VERSION 5.8 ;
BUSBITCHARS "[]" ;
DIVIDERCHAR "/" ;
UNITS
    DATABASE MICRONS 1000 ;
END UNITS

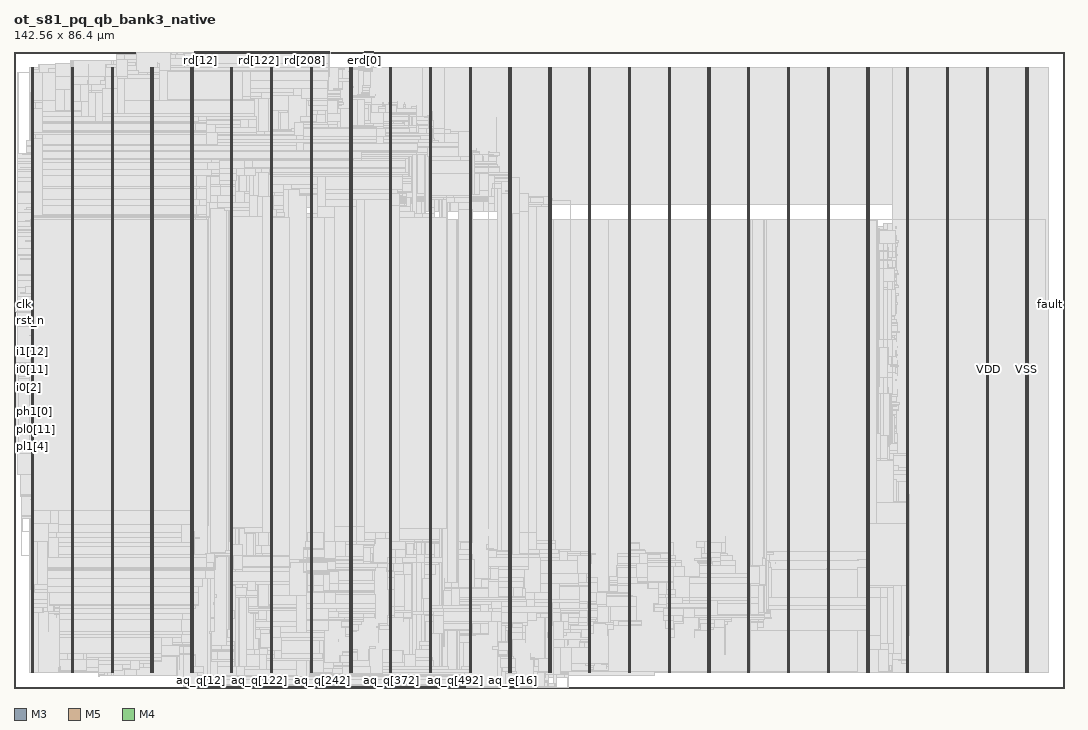
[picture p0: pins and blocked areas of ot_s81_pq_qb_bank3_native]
MACRO ot_s81_pq_qb_bank3_native
  FOREIGN ot_s81_pq_qb_bank3_native 0 0 ;
  CLASS BLOCK ;
  SIZE 142.56 BY 86.4 ;
  PIN aq_e[0]
    DIRECTION INPUT ;
    USE SIGNAL ;
    PORT
      LAYER M3 ;
        RECT  66.528 0 66.546 0.144 ;
    END
  END aq_e[0]
  PIN aq_e[10]
    DIRECTION INPUT ;
    USE SIGNAL ;
    PORT
      LAYER M3 ;
        RECT  67.248 0 67.266 0.144 ;
    END
  END aq_e[10]
  PIN aq_e[11]
    DIRECTION INPUT ;
    USE SIGNAL ;
    PORT
      LAYER M5 ;
        RECT  67.296 0 67.32 0.192 ;
    END
  END aq_e[11]
  PIN aq_e[12]
    DIRECTION INPUT ;
    USE SIGNAL ;
    PORT
      LAYER M3 ;
        RECT  67.392 0 67.41 0.144 ;
    END
  END aq_e[12]
  PIN aq_e[13]
    DIRECTION INPUT ;
    USE SIGNAL ;
    PORT
      LAYER M5 ;
        RECT  67.44 0 67.464 0.192 ;
    END
  END aq_e[13]
  PIN aq_e[14]
    DIRECTION INPUT ;
    USE SIGNAL ;
    PORT
      LAYER M3 ;
        RECT  67.536 0 67.554 0.144 ;
    END
  END aq_e[14]
  PIN aq_e[15]
    DIRECTION INPUT ;
    USE SIGNAL ;
    PORT
      LAYER M5 ;
        RECT  67.584 0 67.608 0.192 ;
    END
  END aq_e[15]
  PIN aq_e[16]
    DIRECTION INPUT ;
    USE SIGNAL ;
    PORT
      LAYER M3 ;
        RECT  67.68 0 67.698 0.144 ;
    END
  END aq_e[16]
  PIN aq_e[17]
    DIRECTION INPUT ;
    USE SIGNAL ;
    PORT
      LAYER M5 ;
        RECT  67.728 0 67.752 0.192 ;
    END
  END aq_e[17]
  PIN aq_e[18]
    DIRECTION INPUT ;
    USE SIGNAL ;
    PORT
      LAYER M3 ;
        RECT  67.824 0 67.842 0.144 ;
    END
  END aq_e[18]
  PIN aq_e[19]
    DIRECTION INPUT ;
    USE SIGNAL ;
    PORT
      LAYER M5 ;
        RECT  67.872 0 67.896 0.192 ;
    END
  END aq_e[19]
  PIN aq_e[1]
    DIRECTION INPUT ;
    USE SIGNAL ;
    PORT
      LAYER M5 ;
        RECT  66.576 0 66.6 0.192 ;
    END
  END aq_e[1]
  PIN aq_e[2]
    DIRECTION INPUT ;
    USE SIGNAL ;
    PORT
      LAYER M3 ;
        RECT  66.672 0 66.69 0.144 ;
    END
  END aq_e[2]
  PIN aq_e[3]
    DIRECTION INPUT ;
    USE SIGNAL ;
    PORT
      LAYER M5 ;
        RECT  66.72 0 66.744 0.192 ;
    END
  END aq_e[3]
  PIN aq_e[4]
    DIRECTION INPUT ;
    USE SIGNAL ;
    PORT
      LAYER M3 ;
        RECT  66.816 0 66.834 0.144 ;
    END
  END aq_e[4]
  PIN aq_e[5]
    DIRECTION INPUT ;
    USE SIGNAL ;
    PORT
      LAYER M5 ;
        RECT  66.864 0 66.888 0.192 ;
    END
  END aq_e[5]
  PIN aq_e[6]
    DIRECTION INPUT ;
    USE SIGNAL ;
    PORT
      LAYER M3 ;
        RECT  66.96 0 66.978 0.144 ;
    END
  END aq_e[6]
  PIN aq_e[7]
    DIRECTION INPUT ;
    USE SIGNAL ;
    PORT
      LAYER M5 ;
        RECT  67.008 0 67.032 0.192 ;
    END
  END aq_e[7]
  PIN aq_e[8]
    DIRECTION INPUT ;
    USE SIGNAL ;
    PORT
      LAYER M3 ;
        RECT  67.104 0 67.122 0.144 ;
    END
  END aq_e[8]
  PIN aq_e[9]
    DIRECTION INPUT ;
    USE SIGNAL ;
    PORT
      LAYER M5 ;
        RECT  67.152 0 67.176 0.192 ;
    END
  END aq_e[9]
  PIN aq_p[0]
    DIRECTION INPUT ;
    USE SIGNAL ;
    PORT
      LAYER M3 ;
        RECT  70.488 0 70.506 0.144 ;
    END
  END aq_p[0]
  PIN aq_p[1]
    DIRECTION INPUT ;
    USE SIGNAL ;
    PORT
      LAYER M5 ;
        RECT  70.512 0 70.536 0.192 ;
    END
  END aq_p[1]
  PIN aq_p[2]
    DIRECTION INPUT ;
    USE SIGNAL ;
    PORT
      LAYER M3 ;
        RECT  70.632 0 70.65 0.144 ;
    END
  END aq_p[2]
  PIN aq_p[3]
    DIRECTION INPUT ;
    USE SIGNAL ;
    PORT
      LAYER M5 ;
        RECT  70.656 0 70.68 0.192 ;
    END
  END aq_p[3]
  PIN aq_p[4]
    DIRECTION INPUT ;
    USE SIGNAL ;
    PORT
      LAYER M3 ;
        RECT  70.776 0 70.794 0.144 ;
    END
  END aq_p[4]
  PIN aq_p[5]
    DIRECTION INPUT ;
    USE SIGNAL ;
    PORT
      LAYER M5 ;
        RECT  70.8 0 70.824 0.192 ;
    END
  END aq_p[5]
  PIN aq_p[6]
    DIRECTION INPUT ;
    USE SIGNAL ;
    PORT
      LAYER M3 ;
        RECT  70.92 0 70.938 0.144 ;
    END
  END aq_p[6]
  PIN aq_p[7]
    DIRECTION INPUT ;
    USE SIGNAL ;
    PORT
      LAYER M5 ;
        RECT  70.944 0 70.968 0.192 ;
    END
  END aq_p[7]
  PIN aq_p[8]
    DIRECTION INPUT ;
    USE SIGNAL ;
    PORT
      LAYER M3 ;
        RECT  71.064 0 71.082 0.144 ;
    END
  END aq_p[8]
  PIN aq_p[9]
    DIRECTION INPUT ;
    USE SIGNAL ;
    PORT
      LAYER M5 ;
        RECT  71.088 0 71.112 0.192 ;
    END
  END aq_p[9]
  PIN aq_q[0]
    DIRECTION INPUT ;
    USE SIGNAL ;
    PORT
      LAYER M3 ;
        RECT  24.48 0 24.498 0.144 ;
    END
  END aq_q[0]
  PIN aq_q[100]
    DIRECTION INPUT ;
    USE SIGNAL ;
    PORT
      LAYER M3 ;
        RECT  31.68 0 31.698 0.144 ;
    END
  END aq_q[100]
  PIN aq_q[101]
    DIRECTION INPUT ;
    USE SIGNAL ;
    PORT
      LAYER M5 ;
        RECT  31.728 0 31.752 0.192 ;
    END
  END aq_q[101]
  PIN aq_q[102]
    DIRECTION INPUT ;
    USE SIGNAL ;
    PORT
      LAYER M3 ;
        RECT  31.824 0 31.842 0.144 ;
    END
  END aq_q[102]
  PIN aq_q[103]
    DIRECTION INPUT ;
    USE SIGNAL ;
    PORT
      LAYER M5 ;
        RECT  31.872 0 31.896 0.192 ;
    END
  END aq_q[103]
  PIN aq_q[104]
    DIRECTION INPUT ;
    USE SIGNAL ;
    PORT
      LAYER M3 ;
        RECT  31.968 0 31.986 0.144 ;
    END
  END aq_q[104]
  PIN aq_q[105]
    DIRECTION INPUT ;
    USE SIGNAL ;
    PORT
      LAYER M5 ;
        RECT  32.016 0 32.04 0.192 ;
    END
  END aq_q[105]
  PIN aq_q[106]
    DIRECTION INPUT ;
    USE SIGNAL ;
    PORT
      LAYER M3 ;
        RECT  32.112 0 32.13 0.144 ;
    END
  END aq_q[106]
  PIN aq_q[107]
    DIRECTION INPUT ;
    USE SIGNAL ;
    PORT
      LAYER M5 ;
        RECT  32.16 0 32.184 0.192 ;
    END
  END aq_q[107]
  PIN aq_q[108]
    DIRECTION INPUT ;
    USE SIGNAL ;
    PORT
      LAYER M3 ;
        RECT  32.256 0 32.274 0.144 ;
    END
  END aq_q[108]
  PIN aq_q[109]
    DIRECTION INPUT ;
    USE SIGNAL ;
    PORT
      LAYER M5 ;
        RECT  32.304 0 32.328 0.192 ;
    END
  END aq_q[109]
  PIN aq_q[10]
    DIRECTION INPUT ;
    USE SIGNAL ;
    PORT
      LAYER M3 ;
        RECT  25.2 0 25.218 0.144 ;
    END
  END aq_q[10]
  PIN aq_q[110]
    DIRECTION INPUT ;
    USE SIGNAL ;
    PORT
      LAYER M3 ;
        RECT  32.4 0 32.418 0.144 ;
    END
  END aq_q[110]
  PIN aq_q[111]
    DIRECTION INPUT ;
    USE SIGNAL ;
    PORT
      LAYER M5 ;
        RECT  32.448 0 32.472 0.192 ;
    END
  END aq_q[111]
  PIN aq_q[112]
    DIRECTION INPUT ;
    USE SIGNAL ;
    PORT
      LAYER M3 ;
        RECT  32.544 0 32.562 0.144 ;
    END
  END aq_q[112]
  PIN aq_q[113]
    DIRECTION INPUT ;
    USE SIGNAL ;
    PORT
      LAYER M5 ;
        RECT  32.592 0 32.616 0.192 ;
    END
  END aq_q[113]
  PIN aq_q[114]
    DIRECTION INPUT ;
    USE SIGNAL ;
    PORT
      LAYER M3 ;
        RECT  32.688 0 32.706 0.144 ;
    END
  END aq_q[114]
  PIN aq_q[115]
    DIRECTION INPUT ;
    USE SIGNAL ;
    PORT
      LAYER M5 ;
        RECT  32.736 0 32.76 0.192 ;
    END
  END aq_q[115]
  PIN aq_q[116]
    DIRECTION INPUT ;
    USE SIGNAL ;
    PORT
      LAYER M3 ;
        RECT  32.832 0 32.85 0.144 ;
    END
  END aq_q[116]
  PIN aq_q[117]
    DIRECTION INPUT ;
    USE SIGNAL ;
    PORT
      LAYER M5 ;
        RECT  32.88 0 32.904 0.192 ;
    END
  END aq_q[117]
  PIN aq_q[118]
    DIRECTION INPUT ;
    USE SIGNAL ;
    PORT
      LAYER M3 ;
        RECT  32.976 0 32.994 0.144 ;
    END
  END aq_q[118]
  PIN aq_q[119]
    DIRECTION INPUT ;
    USE SIGNAL ;
    PORT
      LAYER M5 ;
        RECT  33.024 0 33.048 0.192 ;
    END
  END aq_q[119]
  PIN aq_q[11]
    DIRECTION INPUT ;
    USE SIGNAL ;
    PORT
      LAYER M5 ;
        RECT  25.248 0 25.272 0.192 ;
    END
  END aq_q[11]
  PIN aq_q[120]
    DIRECTION INPUT ;
    USE SIGNAL ;
    PORT
      LAYER M3 ;
        RECT  33.12 0 33.138 0.144 ;
    END
  END aq_q[120]
  PIN aq_q[121]
    DIRECTION INPUT ;
    USE SIGNAL ;
    PORT
      LAYER M5 ;
        RECT  33.168 0 33.192 0.192 ;
    END
  END aq_q[121]
  PIN aq_q[122]
    DIRECTION INPUT ;
    USE SIGNAL ;
    PORT
      LAYER M3 ;
        RECT  33.264 0 33.282 0.144 ;
    END
  END aq_q[122]
  PIN aq_q[123]
    DIRECTION INPUT ;
    USE SIGNAL ;
    PORT
      LAYER M5 ;
        RECT  33.312 0 33.336 0.192 ;
    END
  END aq_q[123]
  PIN aq_q[124]
    DIRECTION INPUT ;
    USE SIGNAL ;
    PORT
      LAYER M3 ;
        RECT  33.408 0 33.426 0.144 ;
    END
  END aq_q[124]
  PIN aq_q[125]
    DIRECTION INPUT ;
    USE SIGNAL ;
    PORT
      LAYER M5 ;
        RECT  33.456 0 33.48 0.192 ;
    END
  END aq_q[125]
  PIN aq_q[126]
    DIRECTION INPUT ;
    USE SIGNAL ;
    PORT
      LAYER M3 ;
        RECT  33.552 0 33.57 0.144 ;
    END
  END aq_q[126]
  PIN aq_q[127]
    DIRECTION INPUT ;
    USE SIGNAL ;
    PORT
      LAYER M5 ;
        RECT  33.6 0 33.624 0.192 ;
    END
  END aq_q[127]
  PIN aq_q[128]
    DIRECTION INPUT ;
    USE SIGNAL ;
    PORT
      LAYER M3 ;
        RECT  33.696 0 33.714 0.144 ;
    END
  END aq_q[128]
  PIN aq_q[129]
    DIRECTION INPUT ;
    USE SIGNAL ;
    PORT
      LAYER M5 ;
        RECT  33.744 0 33.768 0.192 ;
    END
  END aq_q[129]
  PIN aq_q[12]
    DIRECTION INPUT ;
    USE SIGNAL ;
    PORT
      LAYER M3 ;
        RECT  25.344 0 25.362 0.144 ;
    END
  END aq_q[12]
  PIN aq_q[130]
    DIRECTION INPUT ;
    USE SIGNAL ;
    PORT
      LAYER M3 ;
        RECT  33.84 0 33.858 0.144 ;
    END
  END aq_q[130]
  PIN aq_q[131]
    DIRECTION INPUT ;
    USE SIGNAL ;
    PORT
      LAYER M5 ;
        RECT  33.888 0 33.912 0.192 ;
    END
  END aq_q[131]
  PIN aq_q[132]
    DIRECTION INPUT ;
    USE SIGNAL ;
    PORT
      LAYER M3 ;
        RECT  33.984 0 34.002 0.144 ;
    END
  END aq_q[132]
  PIN aq_q[133]
    DIRECTION INPUT ;
    USE SIGNAL ;
    PORT
      LAYER M5 ;
        RECT  34.032 0 34.056 0.192 ;
    END
  END aq_q[133]
  PIN aq_q[134]
    DIRECTION INPUT ;
    USE SIGNAL ;
    PORT
      LAYER M3 ;
        RECT  34.128 0 34.146 0.144 ;
    END
  END aq_q[134]
  PIN aq_q[135]
    DIRECTION INPUT ;
    USE SIGNAL ;
    PORT
      LAYER M5 ;
        RECT  34.176 0 34.2 0.192 ;
    END
  END aq_q[135]
  PIN aq_q[136]
    DIRECTION INPUT ;
    USE SIGNAL ;
    PORT
      LAYER M3 ;
        RECT  34.272 0 34.29 0.144 ;
    END
  END aq_q[136]
  PIN aq_q[137]
    DIRECTION INPUT ;
    USE SIGNAL ;
    PORT
      LAYER M5 ;
        RECT  34.32 0 34.344 0.192 ;
    END
  END aq_q[137]
  PIN aq_q[138]
    DIRECTION INPUT ;
    USE SIGNAL ;
    PORT
      LAYER M3 ;
        RECT  34.416 0 34.434 0.144 ;
    END
  END aq_q[138]
  PIN aq_q[139]
    DIRECTION INPUT ;
    USE SIGNAL ;
    PORT
      LAYER M5 ;
        RECT  34.464 0 34.488 0.192 ;
    END
  END aq_q[139]
  PIN aq_q[13]
    DIRECTION INPUT ;
    USE SIGNAL ;
    PORT
      LAYER M5 ;
        RECT  25.392 0 25.416 0.192 ;
    END
  END aq_q[13]
  PIN aq_q[140]
    DIRECTION INPUT ;
    USE SIGNAL ;
    PORT
      LAYER M3 ;
        RECT  34.56 0 34.578 0.144 ;
    END
  END aq_q[140]
  PIN aq_q[141]
    DIRECTION INPUT ;
    USE SIGNAL ;
    PORT
      LAYER M5 ;
        RECT  34.608 0 34.632 0.192 ;
    END
  END aq_q[141]
  PIN aq_q[142]
    DIRECTION INPUT ;
    USE SIGNAL ;
    PORT
      LAYER M3 ;
        RECT  34.704 0 34.722 0.144 ;
    END
  END aq_q[142]
  PIN aq_q[143]
    DIRECTION INPUT ;
    USE SIGNAL ;
    PORT
      LAYER M5 ;
        RECT  34.752 0 34.776 0.192 ;
    END
  END aq_q[143]
  PIN aq_q[144]
    DIRECTION INPUT ;
    USE SIGNAL ;
    PORT
      LAYER M3 ;
        RECT  34.848 0 34.866 0.144 ;
    END
  END aq_q[144]
  PIN aq_q[145]
    DIRECTION INPUT ;
    USE SIGNAL ;
    PORT
      LAYER M5 ;
        RECT  34.896 0 34.92 0.192 ;
    END
  END aq_q[145]
  PIN aq_q[146]
    DIRECTION INPUT ;
    USE SIGNAL ;
    PORT
      LAYER M3 ;
        RECT  34.992 0 35.01 0.144 ;
    END
  END aq_q[146]
  PIN aq_q[147]
    DIRECTION INPUT ;
    USE SIGNAL ;
    PORT
      LAYER M5 ;
        RECT  35.04 0 35.064 0.192 ;
    END
  END aq_q[147]
  PIN aq_q[148]
    DIRECTION INPUT ;
    USE SIGNAL ;
    PORT
      LAYER M3 ;
        RECT  35.136 0 35.154 0.144 ;
    END
  END aq_q[148]
  PIN aq_q[149]
    DIRECTION INPUT ;
    USE SIGNAL ;
    PORT
      LAYER M5 ;
        RECT  35.184 0 35.208 0.192 ;
    END
  END aq_q[149]
  PIN aq_q[14]
    DIRECTION INPUT ;
    USE SIGNAL ;
    PORT
      LAYER M3 ;
        RECT  25.488 0 25.506 0.144 ;
    END
  END aq_q[14]
  PIN aq_q[150]
    DIRECTION INPUT ;
    USE SIGNAL ;
    PORT
      LAYER M3 ;
        RECT  35.28 0 35.298 0.144 ;
    END
  END aq_q[150]
  PIN aq_q[151]
    DIRECTION INPUT ;
    USE SIGNAL ;
    PORT
      LAYER M5 ;
        RECT  35.328 0 35.352 0.192 ;
    END
  END aq_q[151]
  PIN aq_q[152]
    DIRECTION INPUT ;
    USE SIGNAL ;
    PORT
      LAYER M3 ;
        RECT  35.424 0 35.442 0.144 ;
    END
  END aq_q[152]
  PIN aq_q[153]
    DIRECTION INPUT ;
    USE SIGNAL ;
    PORT
      LAYER M5 ;
        RECT  35.472 0 35.496 0.192 ;
    END
  END aq_q[153]
  PIN aq_q[154]
    DIRECTION INPUT ;
    USE SIGNAL ;
    PORT
      LAYER M3 ;
        RECT  35.568 0 35.586 0.144 ;
    END
  END aq_q[154]
  PIN aq_q[155]
    DIRECTION INPUT ;
    USE SIGNAL ;
    PORT
      LAYER M5 ;
        RECT  35.616 0 35.64 0.192 ;
    END
  END aq_q[155]
  PIN aq_q[156]
    DIRECTION INPUT ;
    USE SIGNAL ;
    PORT
      LAYER M3 ;
        RECT  35.712 0 35.73 0.144 ;
    END
  END aq_q[156]
  PIN aq_q[157]
    DIRECTION INPUT ;
    USE SIGNAL ;
    PORT
      LAYER M5 ;
        RECT  35.76 0 35.784 0.192 ;
    END
  END aq_q[157]
  PIN aq_q[158]
    DIRECTION INPUT ;
    USE SIGNAL ;
    PORT
      LAYER M3 ;
        RECT  35.856 0 35.874 0.144 ;
    END
  END aq_q[158]
  PIN aq_q[159]
    DIRECTION INPUT ;
    USE SIGNAL ;
    PORT
      LAYER M5 ;
        RECT  35.904 0 35.928 0.192 ;
    END
  END aq_q[159]
  PIN aq_q[15]
    DIRECTION INPUT ;
    USE SIGNAL ;
    PORT
      LAYER M5 ;
        RECT  25.536 0 25.56 0.192 ;
    END
  END aq_q[15]
  PIN aq_q[160]
    DIRECTION INPUT ;
    USE SIGNAL ;
    PORT
      LAYER M3 ;
        RECT  36 0 36.018 0.144 ;
    END
  END aq_q[160]
  PIN aq_q[161]
    DIRECTION INPUT ;
    USE SIGNAL ;
    PORT
      LAYER M5 ;
        RECT  36.048 0 36.072 0.192 ;
    END
  END aq_q[161]
  PIN aq_q[162]
    DIRECTION INPUT ;
    USE SIGNAL ;
    PORT
      LAYER M3 ;
        RECT  36.144 0 36.162 0.144 ;
    END
  END aq_q[162]
  PIN aq_q[163]
    DIRECTION INPUT ;
    USE SIGNAL ;
    PORT
      LAYER M5 ;
        RECT  36.192 0 36.216 0.192 ;
    END
  END aq_q[163]
  PIN aq_q[164]
    DIRECTION INPUT ;
    USE SIGNAL ;
    PORT
      LAYER M3 ;
        RECT  36.288 0 36.306 0.144 ;
    END
  END aq_q[164]
  PIN aq_q[165]
    DIRECTION INPUT ;
    USE SIGNAL ;
    PORT
      LAYER M5 ;
        RECT  36.336 0 36.36 0.192 ;
    END
  END aq_q[165]
  PIN aq_q[166]
    DIRECTION INPUT ;
    USE SIGNAL ;
    PORT
      LAYER M3 ;
        RECT  36.432 0 36.45 0.144 ;
    END
  END aq_q[166]
  PIN aq_q[167]
    DIRECTION INPUT ;
    USE SIGNAL ;
    PORT
      LAYER M5 ;
        RECT  36.48 0 36.504 0.192 ;
    END
  END aq_q[167]
  PIN aq_q[168]
    DIRECTION INPUT ;
    USE SIGNAL ;
    PORT
      LAYER M3 ;
        RECT  36.576 0 36.594 0.144 ;
    END
  END aq_q[168]
  PIN aq_q[169]
    DIRECTION INPUT ;
    USE SIGNAL ;
    PORT
      LAYER M5 ;
        RECT  36.624 0 36.648 0.192 ;
    END
  END aq_q[169]
  PIN aq_q[16]
    DIRECTION INPUT ;
    USE SIGNAL ;
    PORT
      LAYER M3 ;
        RECT  25.632 0 25.65 0.144 ;
    END
  END aq_q[16]
  PIN aq_q[170]
    DIRECTION INPUT ;
    USE SIGNAL ;
    PORT
      LAYER M3 ;
        RECT  36.72 0 36.738 0.144 ;
    END
  END aq_q[170]
  PIN aq_q[171]
    DIRECTION INPUT ;
    USE SIGNAL ;
    PORT
      LAYER M5 ;
        RECT  36.768 0 36.792 0.192 ;
    END
  END aq_q[171]
  PIN aq_q[172]
    DIRECTION INPUT ;
    USE SIGNAL ;
    PORT
      LAYER M3 ;
        RECT  36.864 0 36.882 0.144 ;
    END
  END aq_q[172]
  PIN aq_q[173]
    DIRECTION INPUT ;
    USE SIGNAL ;
    PORT
      LAYER M5 ;
        RECT  36.912 0 36.936 0.192 ;
    END
  END aq_q[173]
  PIN aq_q[174]
    DIRECTION INPUT ;
    USE SIGNAL ;
    PORT
      LAYER M3 ;
        RECT  37.008 0 37.026 0.144 ;
    END
  END aq_q[174]
  PIN aq_q[175]
    DIRECTION INPUT ;
    USE SIGNAL ;
    PORT
      LAYER M5 ;
        RECT  37.056 0 37.08 0.192 ;
    END
  END aq_q[175]
  PIN aq_q[176]
    DIRECTION INPUT ;
    USE SIGNAL ;
    PORT
      LAYER M3 ;
        RECT  37.152 0 37.17 0.144 ;
    END
  END aq_q[176]
  PIN aq_q[177]
    DIRECTION INPUT ;
    USE SIGNAL ;
    PORT
      LAYER M5 ;
        RECT  37.2 0 37.224 0.192 ;
    END
  END aq_q[177]
  PIN aq_q[178]
    DIRECTION INPUT ;
    USE SIGNAL ;
    PORT
      LAYER M3 ;
        RECT  37.296 0 37.314 0.144 ;
    END
  END aq_q[178]
  PIN aq_q[179]
    DIRECTION INPUT ;
    USE SIGNAL ;
    PORT
      LAYER M5 ;
        RECT  37.344 0 37.368 0.192 ;
    END
  END aq_q[179]
  PIN aq_q[17]
    DIRECTION INPUT ;
    USE SIGNAL ;
    PORT
      LAYER M5 ;
        RECT  25.68 0 25.704 0.192 ;
    END
  END aq_q[17]
  PIN aq_q[180]
    DIRECTION INPUT ;
    USE SIGNAL ;
    PORT
      LAYER M3 ;
        RECT  37.44 0 37.458 0.144 ;
    END
  END aq_q[180]
  PIN aq_q[181]
    DIRECTION INPUT ;
    USE SIGNAL ;
    PORT
      LAYER M5 ;
        RECT  37.488 0 37.512 0.192 ;
    END
  END aq_q[181]
  PIN aq_q[182]
    DIRECTION INPUT ;
    USE SIGNAL ;
    PORT
      LAYER M3 ;
        RECT  37.584 0 37.602 0.144 ;
    END
  END aq_q[182]
  PIN aq_q[183]
    DIRECTION INPUT ;
    USE SIGNAL ;
    PORT
      LAYER M5 ;
        RECT  37.632 0 37.656 0.192 ;
    END
  END aq_q[183]
  PIN aq_q[184]
    DIRECTION INPUT ;
    USE SIGNAL ;
    PORT
      LAYER M3 ;
        RECT  37.728 0 37.746 0.144 ;
    END
  END aq_q[184]
  PIN aq_q[185]
    DIRECTION INPUT ;
    USE SIGNAL ;
    PORT
      LAYER M5 ;
        RECT  37.776 0 37.8 0.192 ;
    END
  END aq_q[185]
  PIN aq_q[186]
    DIRECTION INPUT ;
    USE SIGNAL ;
    PORT
      LAYER M3 ;
        RECT  37.872 0 37.89 0.144 ;
    END
  END aq_q[186]
  PIN aq_q[187]
    DIRECTION INPUT ;
    USE SIGNAL ;
    PORT
      LAYER M5 ;
        RECT  37.92 0 37.944 0.192 ;
    END
  END aq_q[187]
  PIN aq_q[188]
    DIRECTION INPUT ;
    USE SIGNAL ;
    PORT
      LAYER M3 ;
        RECT  38.016 0 38.034 0.144 ;
    END
  END aq_q[188]
  PIN aq_q[189]
    DIRECTION INPUT ;
    USE SIGNAL ;
    PORT
      LAYER M5 ;
        RECT  38.064 0 38.088 0.192 ;
    END
  END aq_q[189]
  PIN aq_q[18]
    DIRECTION INPUT ;
    USE SIGNAL ;
    PORT
      LAYER M3 ;
        RECT  25.776 0 25.794 0.144 ;
    END
  END aq_q[18]
  PIN aq_q[190]
    DIRECTION INPUT ;
    USE SIGNAL ;
    PORT
      LAYER M3 ;
        RECT  38.16 0 38.178 0.144 ;
    END
  END aq_q[190]
  PIN aq_q[191]
    DIRECTION INPUT ;
    USE SIGNAL ;
    PORT
      LAYER M5 ;
        RECT  38.208 0 38.232 0.192 ;
    END
  END aq_q[191]
  PIN aq_q[192]
    DIRECTION INPUT ;
    USE SIGNAL ;
    PORT
      LAYER M3 ;
        RECT  38.304 0 38.322 0.144 ;
    END
  END aq_q[192]
  PIN aq_q[193]
    DIRECTION INPUT ;
    USE SIGNAL ;
    PORT
      LAYER M5 ;
        RECT  38.352 0 38.376 0.192 ;
    END
  END aq_q[193]
  PIN aq_q[194]
    DIRECTION INPUT ;
    USE SIGNAL ;
    PORT
      LAYER M3 ;
        RECT  38.448 0 38.466 0.144 ;
    END
  END aq_q[194]
  PIN aq_q[195]
    DIRECTION INPUT ;
    USE SIGNAL ;
    PORT
      LAYER M5 ;
        RECT  38.496 0 38.52 0.192 ;
    END
  END aq_q[195]
  PIN aq_q[196]
    DIRECTION INPUT ;
    USE SIGNAL ;
    PORT
      LAYER M3 ;
        RECT  38.592 0 38.61 0.144 ;
    END
  END aq_q[196]
  PIN aq_q[197]
    DIRECTION INPUT ;
    USE SIGNAL ;
    PORT
      LAYER M5 ;
        RECT  38.64 0 38.664 0.192 ;
    END
  END aq_q[197]
  PIN aq_q[198]
    DIRECTION INPUT ;
    USE SIGNAL ;
    PORT
      LAYER M3 ;
        RECT  38.736 0 38.754 0.144 ;
    END
  END aq_q[198]
  PIN aq_q[199]
    DIRECTION INPUT ;
    USE SIGNAL ;
    PORT
      LAYER M5 ;
        RECT  38.784 0 38.808 0.192 ;
    END
  END aq_q[199]
  PIN aq_q[19]
    DIRECTION INPUT ;
    USE SIGNAL ;
    PORT
      LAYER M5 ;
        RECT  25.824 0 25.848 0.192 ;
    END
  END aq_q[19]
  PIN aq_q[1]
    DIRECTION INPUT ;
    USE SIGNAL ;
    PORT
      LAYER M5 ;
        RECT  24.528 0 24.552 0.192 ;
    END
  END aq_q[1]
  PIN aq_q[200]
    DIRECTION INPUT ;
    USE SIGNAL ;
    PORT
      LAYER M3 ;
        RECT  38.88 0 38.898 0.144 ;
    END
  END aq_q[200]
  PIN aq_q[201]
    DIRECTION INPUT ;
    USE SIGNAL ;
    PORT
      LAYER M5 ;
        RECT  38.928 0 38.952 0.192 ;
    END
  END aq_q[201]
  PIN aq_q[202]
    DIRECTION INPUT ;
    USE SIGNAL ;
    PORT
      LAYER M3 ;
        RECT  39.024 0 39.042 0.144 ;
    END
  END aq_q[202]
  PIN aq_q[203]
    DIRECTION INPUT ;
    USE SIGNAL ;
    PORT
      LAYER M5 ;
        RECT  39.072 0 39.096 0.192 ;
    END
  END aq_q[203]
  PIN aq_q[204]
    DIRECTION INPUT ;
    USE SIGNAL ;
    PORT
      LAYER M3 ;
        RECT  39.168 0 39.186 0.144 ;
    END
  END aq_q[204]
  PIN aq_q[205]
    DIRECTION INPUT ;
    USE SIGNAL ;
    PORT
      LAYER M5 ;
        RECT  39.216 0 39.24 0.192 ;
    END
  END aq_q[205]
  PIN aq_q[206]
    DIRECTION INPUT ;
    USE SIGNAL ;
    PORT
      LAYER M3 ;
        RECT  39.312 0 39.33 0.144 ;
    END
  END aq_q[206]
  PIN aq_q[207]
    DIRECTION INPUT ;
    USE SIGNAL ;
    PORT
      LAYER M5 ;
        RECT  39.36 0 39.384 0.192 ;
    END
  END aq_q[207]
  PIN aq_q[208]
    DIRECTION INPUT ;
    USE SIGNAL ;
    PORT
      LAYER M3 ;
        RECT  39.456 0 39.474 0.144 ;
    END
  END aq_q[208]
  PIN aq_q[209]
    DIRECTION INPUT ;
    USE SIGNAL ;
    PORT
      LAYER M5 ;
        RECT  39.504 0 39.528 0.192 ;
    END
  END aq_q[209]
  PIN aq_q[20]
    DIRECTION INPUT ;
    USE SIGNAL ;
    PORT
      LAYER M3 ;
        RECT  25.92 0 25.938 0.144 ;
    END
  END aq_q[20]
  PIN aq_q[210]
    DIRECTION INPUT ;
    USE SIGNAL ;
    PORT
      LAYER M3 ;
        RECT  39.6 0 39.618 0.144 ;
    END
  END aq_q[210]
  PIN aq_q[211]
    DIRECTION INPUT ;
    USE SIGNAL ;
    PORT
      LAYER M5 ;
        RECT  39.648 0 39.672 0.192 ;
    END
  END aq_q[211]
  PIN aq_q[212]
    DIRECTION INPUT ;
    USE SIGNAL ;
    PORT
      LAYER M3 ;
        RECT  39.744 0 39.762 0.144 ;
    END
  END aq_q[212]
  PIN aq_q[213]
    DIRECTION INPUT ;
    USE SIGNAL ;
    PORT
      LAYER M5 ;
        RECT  39.792 0 39.816 0.192 ;
    END
  END aq_q[213]
  PIN aq_q[214]
    DIRECTION INPUT ;
    USE SIGNAL ;
    PORT
      LAYER M3 ;
        RECT  39.888 0 39.906 0.144 ;
    END
  END aq_q[214]
  PIN aq_q[215]
    DIRECTION INPUT ;
    USE SIGNAL ;
    PORT
      LAYER M5 ;
        RECT  39.936 0 39.96 0.192 ;
    END
  END aq_q[215]
  PIN aq_q[216]
    DIRECTION INPUT ;
    USE SIGNAL ;
    PORT
      LAYER M3 ;
        RECT  40.032 0 40.05 0.144 ;
    END
  END aq_q[216]
  PIN aq_q[217]
    DIRECTION INPUT ;
    USE SIGNAL ;
    PORT
      LAYER M5 ;
        RECT  40.08 0 40.104 0.192 ;
    END
  END aq_q[217]
  PIN aq_q[218]
    DIRECTION INPUT ;
    USE SIGNAL ;
    PORT
      LAYER M3 ;
        RECT  40.176 0 40.194 0.144 ;
    END
  END aq_q[218]
  PIN aq_q[219]
    DIRECTION INPUT ;
    USE SIGNAL ;
    PORT
      LAYER M5 ;
        RECT  40.224 0 40.248 0.192 ;
    END
  END aq_q[219]
  PIN aq_q[21]
    DIRECTION INPUT ;
    USE SIGNAL ;
    PORT
      LAYER M5 ;
        RECT  25.968 0 25.992 0.192 ;
    END
  END aq_q[21]
  PIN aq_q[220]
    DIRECTION INPUT ;
    USE SIGNAL ;
    PORT
      LAYER M3 ;
        RECT  40.32 0 40.338 0.144 ;
    END
  END aq_q[220]
  PIN aq_q[221]
    DIRECTION INPUT ;
    USE SIGNAL ;
    PORT
      LAYER M5 ;
        RECT  40.368 0 40.392 0.192 ;
    END
  END aq_q[221]
  PIN aq_q[222]
    DIRECTION INPUT ;
    USE SIGNAL ;
    PORT
      LAYER M3 ;
        RECT  40.464 0 40.482 0.144 ;
    END
  END aq_q[222]
  PIN aq_q[223]
    DIRECTION INPUT ;
    USE SIGNAL ;
    PORT
      LAYER M5 ;
        RECT  40.512 0 40.536 0.192 ;
    END
  END aq_q[223]
  PIN aq_q[224]
    DIRECTION INPUT ;
    USE SIGNAL ;
    PORT
      LAYER M3 ;
        RECT  40.608 0 40.626 0.144 ;
    END
  END aq_q[224]
  PIN aq_q[225]
    DIRECTION INPUT ;
    USE SIGNAL ;
    PORT
      LAYER M5 ;
        RECT  40.656 0 40.68 0.192 ;
    END
  END aq_q[225]
  PIN aq_q[226]
    DIRECTION INPUT ;
    USE SIGNAL ;
    PORT
      LAYER M3 ;
        RECT  40.752 0 40.77 0.144 ;
    END
  END aq_q[226]
  PIN aq_q[227]
    DIRECTION INPUT ;
    USE SIGNAL ;
    PORT
      LAYER M5 ;
        RECT  40.8 0 40.824 0.192 ;
    END
  END aq_q[227]
  PIN aq_q[228]
    DIRECTION INPUT ;
    USE SIGNAL ;
    PORT
      LAYER M3 ;
        RECT  40.896 0 40.914 0.144 ;
    END
  END aq_q[228]
  PIN aq_q[229]
    DIRECTION INPUT ;
    USE SIGNAL ;
    PORT
      LAYER M5 ;
        RECT  40.944 0 40.968 0.192 ;
    END
  END aq_q[229]
  PIN aq_q[22]
    DIRECTION INPUT ;
    USE SIGNAL ;
    PORT
      LAYER M3 ;
        RECT  26.064 0 26.082 0.144 ;
    END
  END aq_q[22]
  PIN aq_q[230]
    DIRECTION INPUT ;
    USE SIGNAL ;
    PORT
      LAYER M3 ;
        RECT  41.04 0 41.058 0.144 ;
    END
  END aq_q[230]
  PIN aq_q[231]
    DIRECTION INPUT ;
    USE SIGNAL ;
    PORT
      LAYER M5 ;
        RECT  41.088 0 41.112 0.192 ;
    END
  END aq_q[231]
  PIN aq_q[232]
    DIRECTION INPUT ;
    USE SIGNAL ;
    PORT
      LAYER M3 ;
        RECT  41.184 0 41.202 0.144 ;
    END
  END aq_q[232]
  PIN aq_q[233]
    DIRECTION INPUT ;
    USE SIGNAL ;
    PORT
      LAYER M5 ;
        RECT  41.232 0 41.256 0.192 ;
    END
  END aq_q[233]
  PIN aq_q[234]
    DIRECTION INPUT ;
    USE SIGNAL ;
    PORT
      LAYER M3 ;
        RECT  41.328 0 41.346 0.144 ;
    END
  END aq_q[234]
  PIN aq_q[235]
    DIRECTION INPUT ;
    USE SIGNAL ;
    PORT
      LAYER M5 ;
        RECT  41.376 0 41.4 0.192 ;
    END
  END aq_q[235]
  PIN aq_q[236]
    DIRECTION INPUT ;
    USE SIGNAL ;
    PORT
      LAYER M3 ;
        RECT  41.472 0 41.49 0.144 ;
    END
  END aq_q[236]
  PIN aq_q[237]
    DIRECTION INPUT ;
    USE SIGNAL ;
    PORT
      LAYER M5 ;
        RECT  41.52 0 41.544 0.192 ;
    END
  END aq_q[237]
  PIN aq_q[238]
    DIRECTION INPUT ;
    USE SIGNAL ;
    PORT
      LAYER M3 ;
        RECT  41.616 0 41.634 0.144 ;
    END
  END aq_q[238]
  PIN aq_q[239]
    DIRECTION INPUT ;
    USE SIGNAL ;
    PORT
      LAYER M5 ;
        RECT  41.664 0 41.688 0.192 ;
    END
  END aq_q[239]
  PIN aq_q[23]
    DIRECTION INPUT ;
    USE SIGNAL ;
    PORT
      LAYER M5 ;
        RECT  26.112 0 26.136 0.192 ;
    END
  END aq_q[23]
  PIN aq_q[240]
    DIRECTION INPUT ;
    USE SIGNAL ;
    PORT
      LAYER M3 ;
        RECT  41.76 0 41.778 0.144 ;
    END
  END aq_q[240]
  PIN aq_q[241]
    DIRECTION INPUT ;
    USE SIGNAL ;
    PORT
      LAYER M5 ;
        RECT  41.808 0 41.832 0.192 ;
    END
  END aq_q[241]
  PIN aq_q[242]
    DIRECTION INPUT ;
    USE SIGNAL ;
    PORT
      LAYER M3 ;
        RECT  41.904 0 41.922 0.144 ;
    END
  END aq_q[242]
  PIN aq_q[243]
    DIRECTION INPUT ;
    USE SIGNAL ;
    PORT
      LAYER M5 ;
        RECT  41.952 0 41.976 0.192 ;
    END
  END aq_q[243]
  PIN aq_q[244]
    DIRECTION INPUT ;
    USE SIGNAL ;
    PORT
      LAYER M3 ;
        RECT  42.048 0 42.066 0.144 ;
    END
  END aq_q[244]
  PIN aq_q[245]
    DIRECTION INPUT ;
    USE SIGNAL ;
    PORT
      LAYER M5 ;
        RECT  42.096 0 42.12 0.192 ;
    END
  END aq_q[245]
  PIN aq_q[246]
    DIRECTION INPUT ;
    USE SIGNAL ;
    PORT
      LAYER M3 ;
        RECT  42.192 0 42.21 0.144 ;
    END
  END aq_q[246]
  PIN aq_q[247]
    DIRECTION INPUT ;
    USE SIGNAL ;
    PORT
      LAYER M5 ;
        RECT  42.24 0 42.264 0.192 ;
    END
  END aq_q[247]
  PIN aq_q[248]
    DIRECTION INPUT ;
    USE SIGNAL ;
    PORT
      LAYER M3 ;
        RECT  42.336 0 42.354 0.144 ;
    END
    PORT
      LAYER M3 ;
        RECT  42.264 0.031 42.426 0.067 ;
    END
  END aq_q[248]
  PIN aq_q[249]
    DIRECTION INPUT ;
    USE SIGNAL ;
    PORT
      LAYER M5 ;
        RECT  42.384 0 42.408 0.192 ;
    END
  END aq_q[249]
  PIN aq_q[24]
    DIRECTION INPUT ;
    USE SIGNAL ;
    PORT
      LAYER M3 ;
        RECT  26.208 0 26.226 0.144 ;
    END
  END aq_q[24]
  PIN aq_q[250]
    DIRECTION INPUT ;
    USE SIGNAL ;
    PORT
      LAYER M3 ;
        RECT  42.48 0 42.498 0.144 ;
    END
  END aq_q[250]
  PIN aq_q[251]
    DIRECTION INPUT ;
    USE SIGNAL ;
    PORT
      LAYER M5 ;
        RECT  42.528 0 42.552 0.192 ;
    END
  END aq_q[251]
  PIN aq_q[252]
    DIRECTION INPUT ;
    USE SIGNAL ;
    PORT
      LAYER M3 ;
        RECT  42.624 0 42.642 0.144 ;
    END
  END aq_q[252]
  PIN aq_q[253]
    DIRECTION INPUT ;
    USE SIGNAL ;
    PORT
      LAYER M5 ;
        RECT  42.672 0 42.696 0.192 ;
    END
  END aq_q[253]
  PIN aq_q[254]
    DIRECTION INPUT ;
    USE SIGNAL ;
    PORT
      LAYER M3 ;
        RECT  42.768 0 42.786 0.144 ;
    END
  END aq_q[254]
  PIN aq_q[255]
    DIRECTION INPUT ;
    USE SIGNAL ;
    PORT
      LAYER M5 ;
        RECT  42.816 0 42.84 0.192 ;
    END
  END aq_q[255]
  PIN aq_q[256]
    DIRECTION INPUT ;
    USE SIGNAL ;
    PORT
      LAYER M3 ;
        RECT  42.912 0 42.93 0.144 ;
    END
  END aq_q[256]
  PIN aq_q[257]
    DIRECTION INPUT ;
    USE SIGNAL ;
    PORT
      LAYER M5 ;
        RECT  42.96 0 42.984 0.192 ;
    END
  END aq_q[257]
  PIN aq_q[258]
    DIRECTION INPUT ;
    USE SIGNAL ;
    PORT
      LAYER M3 ;
        RECT  43.056 0 43.074 0.144 ;
    END
  END aq_q[258]
  PIN aq_q[259]
    DIRECTION INPUT ;
    USE SIGNAL ;
    PORT
      LAYER M5 ;
        RECT  43.104 0 43.128 0.192 ;
    END
  END aq_q[259]
  PIN aq_q[25]
    DIRECTION INPUT ;
    USE SIGNAL ;
    PORT
      LAYER M5 ;
        RECT  26.256 0 26.28 0.192 ;
    END
  END aq_q[25]
  PIN aq_q[260]
    DIRECTION INPUT ;
    USE SIGNAL ;
    PORT
      LAYER M3 ;
        RECT  43.2 0 43.218 0.144 ;
    END
  END aq_q[260]
  PIN aq_q[261]
    DIRECTION INPUT ;
    USE SIGNAL ;
    PORT
      LAYER M5 ;
        RECT  43.248 0 43.272 0.192 ;
    END
  END aq_q[261]
  PIN aq_q[262]
    DIRECTION INPUT ;
    USE SIGNAL ;
    PORT
      LAYER M3 ;
        RECT  43.344 0 43.362 0.144 ;
    END
  END aq_q[262]
  PIN aq_q[263]
    DIRECTION INPUT ;
    USE SIGNAL ;
    PORT
      LAYER M5 ;
        RECT  43.392 0 43.416 0.192 ;
    END
  END aq_q[263]
  PIN aq_q[264]
    DIRECTION INPUT ;
    USE SIGNAL ;
    PORT
      LAYER M3 ;
        RECT  43.488 0 43.506 0.144 ;
    END
  END aq_q[264]
  PIN aq_q[265]
    DIRECTION INPUT ;
    USE SIGNAL ;
    PORT
      LAYER M5 ;
        RECT  43.536 0 43.56 0.192 ;
    END
  END aq_q[265]
  PIN aq_q[266]
    DIRECTION INPUT ;
    USE SIGNAL ;
    PORT
      LAYER M3 ;
        RECT  43.632 0 43.65 0.144 ;
    END
  END aq_q[266]
  PIN aq_q[267]
    DIRECTION INPUT ;
    USE SIGNAL ;
    PORT
      LAYER M5 ;
        RECT  43.68 0 43.704 0.192 ;
    END
  END aq_q[267]
  PIN aq_q[268]
    DIRECTION INPUT ;
    USE SIGNAL ;
    PORT
      LAYER M3 ;
        RECT  43.776 0 43.794 0.144 ;
    END
  END aq_q[268]
  PIN aq_q[269]
    DIRECTION INPUT ;
    USE SIGNAL ;
    PORT
      LAYER M5 ;
        RECT  43.824 0 43.848 0.192 ;
    END
  END aq_q[269]
  PIN aq_q[26]
    DIRECTION INPUT ;
    USE SIGNAL ;
    PORT
      LAYER M3 ;
        RECT  26.352 0 26.37 0.144 ;
    END
  END aq_q[26]
  PIN aq_q[270]
    DIRECTION INPUT ;
    USE SIGNAL ;
    PORT
      LAYER M3 ;
        RECT  43.92 0 43.938 0.144 ;
    END
  END aq_q[270]
  PIN aq_q[271]
    DIRECTION INPUT ;
    USE SIGNAL ;
    PORT
      LAYER M5 ;
        RECT  43.968 0 43.992 0.192 ;
    END
  END aq_q[271]
  PIN aq_q[272]
    DIRECTION INPUT ;
    USE SIGNAL ;
    PORT
      LAYER M3 ;
        RECT  44.064 0 44.082 0.144 ;
    END
  END aq_q[272]
  PIN aq_q[273]
    DIRECTION INPUT ;
    USE SIGNAL ;
    PORT
      LAYER M5 ;
        RECT  44.112 0 44.136 0.192 ;
    END
  END aq_q[273]
  PIN aq_q[274]
    DIRECTION INPUT ;
    USE SIGNAL ;
    PORT
      LAYER M3 ;
        RECT  44.208 0 44.226 0.144 ;
    END
  END aq_q[274]
  PIN aq_q[275]
    DIRECTION INPUT ;
    USE SIGNAL ;
    PORT
      LAYER M5 ;
        RECT  44.256 0 44.28 0.192 ;
    END
  END aq_q[275]
  PIN aq_q[276]
    DIRECTION INPUT ;
    USE SIGNAL ;
    PORT
      LAYER M3 ;
        RECT  44.352 0 44.37 0.144 ;
    END
  END aq_q[276]
  PIN aq_q[277]
    DIRECTION INPUT ;
    USE SIGNAL ;
    PORT
      LAYER M5 ;
        RECT  44.4 0 44.424 0.192 ;
    END
  END aq_q[277]
  PIN aq_q[278]
    DIRECTION INPUT ;
    USE SIGNAL ;
    PORT
      LAYER M3 ;
        RECT  44.496 0 44.514 0.144 ;
    END
  END aq_q[278]
  PIN aq_q[279]
    DIRECTION INPUT ;
    USE SIGNAL ;
    PORT
      LAYER M5 ;
        RECT  44.544 0 44.568 0.192 ;
    END
  END aq_q[279]
  PIN aq_q[27]
    DIRECTION INPUT ;
    USE SIGNAL ;
    PORT
      LAYER M5 ;
        RECT  26.4 0 26.424 0.192 ;
    END
  END aq_q[27]
  PIN aq_q[280]
    DIRECTION INPUT ;
    USE SIGNAL ;
    PORT
      LAYER M3 ;
        RECT  44.64 0 44.658 0.144 ;
    END
  END aq_q[280]
  PIN aq_q[281]
    DIRECTION INPUT ;
    USE SIGNAL ;
    PORT
      LAYER M5 ;
        RECT  44.688 0 44.712 0.192 ;
    END
  END aq_q[281]
  PIN aq_q[282]
    DIRECTION INPUT ;
    USE SIGNAL ;
    PORT
      LAYER M3 ;
        RECT  44.784 0 44.802 0.144 ;
    END
  END aq_q[282]
  PIN aq_q[283]
    DIRECTION INPUT ;
    USE SIGNAL ;
    PORT
      LAYER M5 ;
        RECT  44.832 0 44.856 0.192 ;
    END
  END aq_q[283]
  PIN aq_q[284]
    DIRECTION INPUT ;
    USE SIGNAL ;
    PORT
      LAYER M3 ;
        RECT  44.928 0 44.946 0.144 ;
    END
  END aq_q[284]
  PIN aq_q[285]
    DIRECTION INPUT ;
    USE SIGNAL ;
    PORT
      LAYER M5 ;
        RECT  44.976 0 45 0.192 ;
    END
  END aq_q[285]
  PIN aq_q[286]
    DIRECTION INPUT ;
    USE SIGNAL ;
    PORT
      LAYER M3 ;
        RECT  45.072 0 45.09 0.144 ;
    END
  END aq_q[286]
  PIN aq_q[287]
    DIRECTION INPUT ;
    USE SIGNAL ;
    PORT
      LAYER M5 ;
        RECT  45.12 0 45.144 0.192 ;
    END
  END aq_q[287]
  PIN aq_q[288]
    DIRECTION INPUT ;
    USE SIGNAL ;
    PORT
      LAYER M3 ;
        RECT  45.216 0 45.234 0.144 ;
    END
  END aq_q[288]
  PIN aq_q[289]
    DIRECTION INPUT ;
    USE SIGNAL ;
    PORT
      LAYER M5 ;
        RECT  45.264 0 45.288 0.192 ;
    END
  END aq_q[289]
  PIN aq_q[28]
    DIRECTION INPUT ;
    USE SIGNAL ;
    PORT
      LAYER M3 ;
        RECT  26.496 0 26.514 0.144 ;
    END
  END aq_q[28]
  PIN aq_q[290]
    DIRECTION INPUT ;
    USE SIGNAL ;
    PORT
      LAYER M3 ;
        RECT  45.36 0 45.378 0.144 ;
    END
  END aq_q[290]
  PIN aq_q[291]
    DIRECTION INPUT ;
    USE SIGNAL ;
    PORT
      LAYER M5 ;
        RECT  45.408 0 45.432 0.192 ;
    END
  END aq_q[291]
  PIN aq_q[292]
    DIRECTION INPUT ;
    USE SIGNAL ;
    PORT
      LAYER M3 ;
        RECT  45.504 0 45.522 0.144 ;
    END
  END aq_q[292]
  PIN aq_q[293]
    DIRECTION INPUT ;
    USE SIGNAL ;
    PORT
      LAYER M5 ;
        RECT  45.552 0 45.576 0.192 ;
    END
  END aq_q[293]
  PIN aq_q[294]
    DIRECTION INPUT ;
    USE SIGNAL ;
    PORT
      LAYER M3 ;
        RECT  45.648 0 45.666 0.144 ;
    END
  END aq_q[294]
  PIN aq_q[295]
    DIRECTION INPUT ;
    USE SIGNAL ;
    PORT
      LAYER M5 ;
        RECT  45.696 0 45.72 0.192 ;
    END
  END aq_q[295]
  PIN aq_q[296]
    DIRECTION INPUT ;
    USE SIGNAL ;
    PORT
      LAYER M3 ;
        RECT  45.792 0 45.81 0.144 ;
    END
  END aq_q[296]
  PIN aq_q[297]
    DIRECTION INPUT ;
    USE SIGNAL ;
    PORT
      LAYER M5 ;
        RECT  45.84 0 45.864 0.192 ;
    END
  END aq_q[297]
  PIN aq_q[298]
    DIRECTION INPUT ;
    USE SIGNAL ;
    PORT
      LAYER M3 ;
        RECT  45.936 0 45.954 0.144 ;
    END
  END aq_q[298]
  PIN aq_q[299]
    DIRECTION INPUT ;
    USE SIGNAL ;
    PORT
      LAYER M5 ;
        RECT  45.984 0 46.008 0.192 ;
    END
  END aq_q[299]
  PIN aq_q[29]
    DIRECTION INPUT ;
    USE SIGNAL ;
    PORT
      LAYER M5 ;
        RECT  26.544 0 26.568 0.192 ;
    END
  END aq_q[29]
  PIN aq_q[2]
    DIRECTION INPUT ;
    USE SIGNAL ;
    PORT
      LAYER M3 ;
        RECT  24.624 0 24.642 0.144 ;
    END
  END aq_q[2]
  PIN aq_q[300]
    DIRECTION INPUT ;
    USE SIGNAL ;
    PORT
      LAYER M3 ;
        RECT  46.08 0 46.098 0.144 ;
    END
  END aq_q[300]
  PIN aq_q[301]
    DIRECTION INPUT ;
    USE SIGNAL ;
    PORT
      LAYER M5 ;
        RECT  46.128 0 46.152 0.192 ;
    END
  END aq_q[301]
  PIN aq_q[302]
    DIRECTION INPUT ;
    USE SIGNAL ;
    PORT
      LAYER M3 ;
        RECT  46.224 0 46.242 0.144 ;
    END
  END aq_q[302]
  PIN aq_q[303]
    DIRECTION INPUT ;
    USE SIGNAL ;
    PORT
      LAYER M5 ;
        RECT  46.272 0 46.296 0.192 ;
    END
  END aq_q[303]
  PIN aq_q[304]
    DIRECTION INPUT ;
    USE SIGNAL ;
    PORT
      LAYER M3 ;
        RECT  46.368 0 46.386 0.144 ;
    END
  END aq_q[304]
  PIN aq_q[305]
    DIRECTION INPUT ;
    USE SIGNAL ;
    PORT
      LAYER M5 ;
        RECT  46.416 0 46.44 0.192 ;
    END
  END aq_q[305]
  PIN aq_q[306]
    DIRECTION INPUT ;
    USE SIGNAL ;
    PORT
      LAYER M3 ;
        RECT  46.512 0 46.53 0.144 ;
    END
  END aq_q[306]
  PIN aq_q[307]
    DIRECTION INPUT ;
    USE SIGNAL ;
    PORT
      LAYER M5 ;
        RECT  46.56 0 46.584 0.192 ;
    END
  END aq_q[307]
  PIN aq_q[308]
    DIRECTION INPUT ;
    USE SIGNAL ;
    PORT
      LAYER M3 ;
        RECT  46.656 0 46.674 0.144 ;
    END
  END aq_q[308]
  PIN aq_q[309]
    DIRECTION INPUT ;
    USE SIGNAL ;
    PORT
      LAYER M5 ;
        RECT  46.704 0 46.728 0.192 ;
    END
  END aq_q[309]
  PIN aq_q[30]
    DIRECTION INPUT ;
    USE SIGNAL ;
    PORT
      LAYER M3 ;
        RECT  26.64 0 26.658 0.144 ;
    END
  END aq_q[30]
  PIN aq_q[310]
    DIRECTION INPUT ;
    USE SIGNAL ;
    PORT
      LAYER M3 ;
        RECT  46.8 0 46.818 0.144 ;
    END
  END aq_q[310]
  PIN aq_q[311]
    DIRECTION INPUT ;
    USE SIGNAL ;
    PORT
      LAYER M5 ;
        RECT  46.848 0 46.872 0.192 ;
    END
  END aq_q[311]
  PIN aq_q[312]
    DIRECTION INPUT ;
    USE SIGNAL ;
    PORT
      LAYER M3 ;
        RECT  46.944 0 46.962 0.144 ;
    END
  END aq_q[312]
  PIN aq_q[313]
    DIRECTION INPUT ;
    USE SIGNAL ;
    PORT
      LAYER M5 ;
        RECT  46.992 0 47.016 0.192 ;
    END
  END aq_q[313]
  PIN aq_q[314]
    DIRECTION INPUT ;
    USE SIGNAL ;
    PORT
      LAYER M3 ;
        RECT  47.088 0 47.106 0.144 ;
    END
  END aq_q[314]
  PIN aq_q[315]
    DIRECTION INPUT ;
    USE SIGNAL ;
    PORT
      LAYER M5 ;
        RECT  47.136 0 47.16 0.192 ;
    END
  END aq_q[315]
  PIN aq_q[316]
    DIRECTION INPUT ;
    USE SIGNAL ;
    PORT
      LAYER M3 ;
        RECT  47.232 0 47.25 0.144 ;
    END
  END aq_q[316]
  PIN aq_q[317]
    DIRECTION INPUT ;
    USE SIGNAL ;
    PORT
      LAYER M5 ;
        RECT  47.28 0 47.304 0.192 ;
    END
  END aq_q[317]
  PIN aq_q[318]
    DIRECTION INPUT ;
    USE SIGNAL ;
    PORT
      LAYER M3 ;
        RECT  47.376 0 47.394 0.144 ;
    END
  END aq_q[318]
  PIN aq_q[319]
    DIRECTION INPUT ;
    USE SIGNAL ;
    PORT
      LAYER M5 ;
        RECT  47.424 0 47.448 0.192 ;
    END
  END aq_q[319]
  PIN aq_q[31]
    DIRECTION INPUT ;
    USE SIGNAL ;
    PORT
      LAYER M5 ;
        RECT  26.688 0 26.712 0.192 ;
    END
  END aq_q[31]
  PIN aq_q[320]
    DIRECTION INPUT ;
    USE SIGNAL ;
    PORT
      LAYER M3 ;
        RECT  47.52 0 47.538 0.144 ;
    END
  END aq_q[320]
  PIN aq_q[321]
    DIRECTION INPUT ;
    USE SIGNAL ;
    PORT
      LAYER M5 ;
        RECT  47.568 0 47.592 0.192 ;
    END
  END aq_q[321]
  PIN aq_q[322]
    DIRECTION INPUT ;
    USE SIGNAL ;
    PORT
      LAYER M3 ;
        RECT  47.664 0 47.682 0.144 ;
    END
  END aq_q[322]
  PIN aq_q[323]
    DIRECTION INPUT ;
    USE SIGNAL ;
    PORT
      LAYER M5 ;
        RECT  47.712 0 47.736 0.192 ;
    END
  END aq_q[323]
  PIN aq_q[324]
    DIRECTION INPUT ;
    USE SIGNAL ;
    PORT
      LAYER M3 ;
        RECT  47.808 0 47.826 0.144 ;
    END
  END aq_q[324]
  PIN aq_q[325]
    DIRECTION INPUT ;
    USE SIGNAL ;
    PORT
      LAYER M5 ;
        RECT  47.856 0 47.88 0.192 ;
    END
  END aq_q[325]
  PIN aq_q[326]
    DIRECTION INPUT ;
    USE SIGNAL ;
    PORT
      LAYER M3 ;
        RECT  47.952 0 47.97 0.144 ;
    END
  END aq_q[326]
  PIN aq_q[327]
    DIRECTION INPUT ;
    USE SIGNAL ;
    PORT
      LAYER M5 ;
        RECT  48 0 48.024 0.192 ;
    END
  END aq_q[327]
  PIN aq_q[328]
    DIRECTION INPUT ;
    USE SIGNAL ;
    PORT
      LAYER M3 ;
        RECT  48.096 0 48.114 0.144 ;
    END
  END aq_q[328]
  PIN aq_q[329]
    DIRECTION INPUT ;
    USE SIGNAL ;
    PORT
      LAYER M5 ;
        RECT  48.144 0 48.168 0.192 ;
    END
  END aq_q[329]
  PIN aq_q[32]
    DIRECTION INPUT ;
    USE SIGNAL ;
    PORT
      LAYER M3 ;
        RECT  26.784 0 26.802 0.144 ;
    END
  END aq_q[32]
  PIN aq_q[330]
    DIRECTION INPUT ;
    USE SIGNAL ;
    PORT
      LAYER M3 ;
        RECT  48.24 0 48.258 0.144 ;
    END
  END aq_q[330]
  PIN aq_q[331]
    DIRECTION INPUT ;
    USE SIGNAL ;
    PORT
      LAYER M5 ;
        RECT  48.288 0 48.312 0.192 ;
    END
  END aq_q[331]
  PIN aq_q[332]
    DIRECTION INPUT ;
    USE SIGNAL ;
    PORT
      LAYER M3 ;
        RECT  48.384 0 48.402 0.144 ;
    END
  END aq_q[332]
  PIN aq_q[333]
    DIRECTION INPUT ;
    USE SIGNAL ;
    PORT
      LAYER M5 ;
        RECT  48.432 0 48.456 0.192 ;
    END
  END aq_q[333]
  PIN aq_q[334]
    DIRECTION INPUT ;
    USE SIGNAL ;
    PORT
      LAYER M3 ;
        RECT  48.528 0 48.546 0.144 ;
    END
  END aq_q[334]
  PIN aq_q[335]
    DIRECTION INPUT ;
    USE SIGNAL ;
    PORT
      LAYER M5 ;
        RECT  48.576 0 48.6 0.192 ;
    END
  END aq_q[335]
  PIN aq_q[336]
    DIRECTION INPUT ;
    USE SIGNAL ;
    PORT
      LAYER M3 ;
        RECT  48.672 0 48.69 0.144 ;
    END
  END aq_q[336]
  PIN aq_q[337]
    DIRECTION INPUT ;
    USE SIGNAL ;
    PORT
      LAYER M5 ;
        RECT  48.72 0 48.744 0.192 ;
    END
  END aq_q[337]
  PIN aq_q[338]
    DIRECTION INPUT ;
    USE SIGNAL ;
    PORT
      LAYER M3 ;
        RECT  48.816 0 48.834 0.144 ;
    END
  END aq_q[338]
  PIN aq_q[339]
    DIRECTION INPUT ;
    USE SIGNAL ;
    PORT
      LAYER M5 ;
        RECT  48.864 0 48.888 0.192 ;
    END
  END aq_q[339]
  PIN aq_q[33]
    DIRECTION INPUT ;
    USE SIGNAL ;
    PORT
      LAYER M5 ;
        RECT  26.832 0 26.856 0.192 ;
    END
  END aq_q[33]
  PIN aq_q[340]
    DIRECTION INPUT ;
    USE SIGNAL ;
    PORT
      LAYER M3 ;
        RECT  48.96 0 48.978 0.144 ;
    END
  END aq_q[340]
  PIN aq_q[341]
    DIRECTION INPUT ;
    USE SIGNAL ;
    PORT
      LAYER M5 ;
        RECT  49.008 0 49.032 0.192 ;
    END
  END aq_q[341]
  PIN aq_q[342]
    DIRECTION INPUT ;
    USE SIGNAL ;
    PORT
      LAYER M3 ;
        RECT  49.104 0 49.122 0.144 ;
    END
  END aq_q[342]
  PIN aq_q[343]
    DIRECTION INPUT ;
    USE SIGNAL ;
    PORT
      LAYER M5 ;
        RECT  49.152 0 49.176 0.192 ;
    END
  END aq_q[343]
  PIN aq_q[344]
    DIRECTION INPUT ;
    USE SIGNAL ;
    PORT
      LAYER M3 ;
        RECT  49.248 0 49.266 0.144 ;
    END
  END aq_q[344]
  PIN aq_q[345]
    DIRECTION INPUT ;
    USE SIGNAL ;
    PORT
      LAYER M5 ;
        RECT  49.296 0 49.32 0.192 ;
    END
  END aq_q[345]
  PIN aq_q[346]
    DIRECTION INPUT ;
    USE SIGNAL ;
    PORT
      LAYER M3 ;
        RECT  49.392 0 49.41 0.144 ;
    END
  END aq_q[346]
  PIN aq_q[347]
    DIRECTION INPUT ;
    USE SIGNAL ;
    PORT
      LAYER M5 ;
        RECT  49.44 0 49.464 0.192 ;
    END
  END aq_q[347]
  PIN aq_q[348]
    DIRECTION INPUT ;
    USE SIGNAL ;
    PORT
      LAYER M3 ;
        RECT  49.536 0 49.554 0.144 ;
    END
  END aq_q[348]
  PIN aq_q[349]
    DIRECTION INPUT ;
    USE SIGNAL ;
    PORT
      LAYER M5 ;
        RECT  49.584 0 49.608 0.192 ;
    END
  END aq_q[349]
  PIN aq_q[34]
    DIRECTION INPUT ;
    USE SIGNAL ;
    PORT
      LAYER M3 ;
        RECT  26.928 0 26.946 0.144 ;
    END
  END aq_q[34]
  PIN aq_q[350]
    DIRECTION INPUT ;
    USE SIGNAL ;
    PORT
      LAYER M3 ;
        RECT  49.68 0 49.698 0.144 ;
    END
  END aq_q[350]
  PIN aq_q[351]
    DIRECTION INPUT ;
    USE SIGNAL ;
    PORT
      LAYER M5 ;
        RECT  49.728 0 49.752 0.192 ;
    END
  END aq_q[351]
  PIN aq_q[352]
    DIRECTION INPUT ;
    USE SIGNAL ;
    PORT
      LAYER M3 ;
        RECT  49.824 0 49.842 0.144 ;
    END
  END aq_q[352]
  PIN aq_q[353]
    DIRECTION INPUT ;
    USE SIGNAL ;
    PORT
      LAYER M5 ;
        RECT  49.872 0 49.896 0.192 ;
    END
  END aq_q[353]
  PIN aq_q[354]
    DIRECTION INPUT ;
    USE SIGNAL ;
    PORT
      LAYER M3 ;
        RECT  49.968 0 49.986 0.144 ;
    END
  END aq_q[354]
  PIN aq_q[355]
    DIRECTION INPUT ;
    USE SIGNAL ;
    PORT
      LAYER M5 ;
        RECT  50.016 0 50.04 0.192 ;
    END
  END aq_q[355]
  PIN aq_q[356]
    DIRECTION INPUT ;
    USE SIGNAL ;
    PORT
      LAYER M3 ;
        RECT  50.112 0 50.13 0.144 ;
    END
  END aq_q[356]
  PIN aq_q[357]
    DIRECTION INPUT ;
    USE SIGNAL ;
    PORT
      LAYER M5 ;
        RECT  50.16 0 50.184 0.192 ;
    END
  END aq_q[357]
  PIN aq_q[358]
    DIRECTION INPUT ;
    USE SIGNAL ;
    PORT
      LAYER M3 ;
        RECT  50.256 0 50.274 0.144 ;
    END
  END aq_q[358]
  PIN aq_q[359]
    DIRECTION INPUT ;
    USE SIGNAL ;
    PORT
      LAYER M5 ;
        RECT  50.304 0 50.328 0.192 ;
    END
  END aq_q[359]
  PIN aq_q[35]
    DIRECTION INPUT ;
    USE SIGNAL ;
    PORT
      LAYER M5 ;
        RECT  26.976 0 27 0.192 ;
    END
  END aq_q[35]
  PIN aq_q[360]
    DIRECTION INPUT ;
    USE SIGNAL ;
    PORT
      LAYER M3 ;
        RECT  50.4 0 50.418 0.144 ;
    END
  END aq_q[360]
  PIN aq_q[361]
    DIRECTION INPUT ;
    USE SIGNAL ;
    PORT
      LAYER M5 ;
        RECT  50.448 0 50.472 0.192 ;
    END
  END aq_q[361]
  PIN aq_q[362]
    DIRECTION INPUT ;
    USE SIGNAL ;
    PORT
      LAYER M3 ;
        RECT  50.544 0 50.562 0.144 ;
    END
  END aq_q[362]
  PIN aq_q[363]
    DIRECTION INPUT ;
    USE SIGNAL ;
    PORT
      LAYER M5 ;
        RECT  50.592 0 50.616 0.192 ;
    END
  END aq_q[363]
  PIN aq_q[364]
    DIRECTION INPUT ;
    USE SIGNAL ;
    PORT
      LAYER M3 ;
        RECT  50.688 0 50.706 0.144 ;
    END
  END aq_q[364]
  PIN aq_q[365]
    DIRECTION INPUT ;
    USE SIGNAL ;
    PORT
      LAYER M5 ;
        RECT  50.736 0 50.76 0.192 ;
    END
  END aq_q[365]
  PIN aq_q[366]
    DIRECTION INPUT ;
    USE SIGNAL ;
    PORT
      LAYER M3 ;
        RECT  50.832 0 50.85 0.144 ;
    END
  END aq_q[366]
  PIN aq_q[367]
    DIRECTION INPUT ;
    USE SIGNAL ;
    PORT
      LAYER M5 ;
        RECT  50.88 0 50.904 0.192 ;
    END
  END aq_q[367]
  PIN aq_q[368]
    DIRECTION INPUT ;
    USE SIGNAL ;
    PORT
      LAYER M3 ;
        RECT  50.976 0 50.994 0.144 ;
    END
  END aq_q[368]
  PIN aq_q[369]
    DIRECTION INPUT ;
    USE SIGNAL ;
    PORT
      LAYER M5 ;
        RECT  51.024 0 51.048 0.192 ;
    END
  END aq_q[369]
  PIN aq_q[36]
    DIRECTION INPUT ;
    USE SIGNAL ;
    PORT
      LAYER M3 ;
        RECT  27.072 0 27.09 0.144 ;
    END
  END aq_q[36]
  PIN aq_q[370]
    DIRECTION INPUT ;
    USE SIGNAL ;
    PORT
      LAYER M3 ;
        RECT  51.12 0 51.138 0.144 ;
    END
  END aq_q[370]
  PIN aq_q[371]
    DIRECTION INPUT ;
    USE SIGNAL ;
    PORT
      LAYER M5 ;
        RECT  51.168 0 51.192 0.192 ;
    END
  END aq_q[371]
  PIN aq_q[372]
    DIRECTION INPUT ;
    USE SIGNAL ;
    PORT
      LAYER M3 ;
        RECT  51.264 0 51.282 0.144 ;
    END
  END aq_q[372]
  PIN aq_q[373]
    DIRECTION INPUT ;
    USE SIGNAL ;
    PORT
      LAYER M5 ;
        RECT  51.312 0 51.336 0.192 ;
    END
  END aq_q[373]
  PIN aq_q[374]
    DIRECTION INPUT ;
    USE SIGNAL ;
    PORT
      LAYER M3 ;
        RECT  51.408 0 51.426 0.144 ;
    END
  END aq_q[374]
  PIN aq_q[375]
    DIRECTION INPUT ;
    USE SIGNAL ;
    PORT
      LAYER M5 ;
        RECT  51.456 0 51.48 0.192 ;
    END
  END aq_q[375]
  PIN aq_q[376]
    DIRECTION INPUT ;
    USE SIGNAL ;
    PORT
      LAYER M3 ;
        RECT  51.552 0 51.57 0.144 ;
    END
  END aq_q[376]
  PIN aq_q[377]
    DIRECTION INPUT ;
    USE SIGNAL ;
    PORT
      LAYER M5 ;
        RECT  51.6 0 51.624 0.192 ;
    END
  END aq_q[377]
  PIN aq_q[378]
    DIRECTION INPUT ;
    USE SIGNAL ;
    PORT
      LAYER M3 ;
        RECT  51.696 0 51.714 0.144 ;
    END
  END aq_q[378]
  PIN aq_q[379]
    DIRECTION INPUT ;
    USE SIGNAL ;
    PORT
      LAYER M5 ;
        RECT  51.744 0 51.768 0.192 ;
    END
  END aq_q[379]
  PIN aq_q[37]
    DIRECTION INPUT ;
    USE SIGNAL ;
    PORT
      LAYER M5 ;
        RECT  27.12 0 27.144 0.192 ;
    END
  END aq_q[37]
  PIN aq_q[380]
    DIRECTION INPUT ;
    USE SIGNAL ;
    PORT
      LAYER M3 ;
        RECT  51.84 0 51.858 0.144 ;
    END
  END aq_q[380]
  PIN aq_q[381]
    DIRECTION INPUT ;
    USE SIGNAL ;
    PORT
      LAYER M5 ;
        RECT  51.888 0 51.912 0.192 ;
    END
  END aq_q[381]
  PIN aq_q[382]
    DIRECTION INPUT ;
    USE SIGNAL ;
    PORT
      LAYER M3 ;
        RECT  51.984 0 52.002 0.144 ;
    END
  END aq_q[382]
  PIN aq_q[383]
    DIRECTION INPUT ;
    USE SIGNAL ;
    PORT
      LAYER M5 ;
        RECT  52.032 0 52.056 0.192 ;
    END
  END aq_q[383]
  PIN aq_q[384]
    DIRECTION INPUT ;
    USE SIGNAL ;
    PORT
      LAYER M3 ;
        RECT  52.128 0 52.146 0.144 ;
    END
  END aq_q[384]
  PIN aq_q[385]
    DIRECTION INPUT ;
    USE SIGNAL ;
    PORT
      LAYER M5 ;
        RECT  52.176 0 52.2 0.192 ;
    END
  END aq_q[385]
  PIN aq_q[386]
    DIRECTION INPUT ;
    USE SIGNAL ;
    PORT
      LAYER M3 ;
        RECT  52.272 0 52.29 0.144 ;
    END
  END aq_q[386]
  PIN aq_q[387]
    DIRECTION INPUT ;
    USE SIGNAL ;
    PORT
      LAYER M5 ;
        RECT  52.32 0 52.344 0.192 ;
    END
  END aq_q[387]
  PIN aq_q[388]
    DIRECTION INPUT ;
    USE SIGNAL ;
    PORT
      LAYER M3 ;
        RECT  52.416 0 52.434 0.144 ;
    END
  END aq_q[388]
  PIN aq_q[389]
    DIRECTION INPUT ;
    USE SIGNAL ;
    PORT
      LAYER M5 ;
        RECT  52.464 0 52.488 0.192 ;
    END
  END aq_q[389]
  PIN aq_q[38]
    DIRECTION INPUT ;
    USE SIGNAL ;
    PORT
      LAYER M3 ;
        RECT  27.216 0 27.234 0.144 ;
    END
  END aq_q[38]
  PIN aq_q[390]
    DIRECTION INPUT ;
    USE SIGNAL ;
    PORT
      LAYER M3 ;
        RECT  52.56 0 52.578 0.144 ;
    END
  END aq_q[390]
  PIN aq_q[391]
    DIRECTION INPUT ;
    USE SIGNAL ;
    PORT
      LAYER M5 ;
        RECT  52.608 0 52.632 0.192 ;
    END
  END aq_q[391]
  PIN aq_q[392]
    DIRECTION INPUT ;
    USE SIGNAL ;
    PORT
      LAYER M3 ;
        RECT  52.704 0 52.722 0.144 ;
    END
  END aq_q[392]
  PIN aq_q[393]
    DIRECTION INPUT ;
    USE SIGNAL ;
    PORT
      LAYER M5 ;
        RECT  52.752 0 52.776 0.192 ;
    END
  END aq_q[393]
  PIN aq_q[394]
    DIRECTION INPUT ;
    USE SIGNAL ;
    PORT
      LAYER M3 ;
        RECT  52.848 0 52.866 0.144 ;
    END
  END aq_q[394]
  PIN aq_q[395]
    DIRECTION INPUT ;
    USE SIGNAL ;
    PORT
      LAYER M5 ;
        RECT  52.896 0 52.92 0.192 ;
    END
  END aq_q[395]
  PIN aq_q[396]
    DIRECTION INPUT ;
    USE SIGNAL ;
    PORT
      LAYER M3 ;
        RECT  52.992 0 53.01 0.144 ;
    END
  END aq_q[396]
  PIN aq_q[397]
    DIRECTION INPUT ;
    USE SIGNAL ;
    PORT
      LAYER M5 ;
        RECT  53.04 0 53.064 0.192 ;
    END
  END aq_q[397]
  PIN aq_q[398]
    DIRECTION INPUT ;
    USE SIGNAL ;
    PORT
      LAYER M3 ;
        RECT  53.136 0 53.154 0.144 ;
    END
  END aq_q[398]
  PIN aq_q[399]
    DIRECTION INPUT ;
    USE SIGNAL ;
    PORT
      LAYER M5 ;
        RECT  53.184 0 53.208 0.192 ;
    END
  END aq_q[399]
  PIN aq_q[39]
    DIRECTION INPUT ;
    USE SIGNAL ;
    PORT
      LAYER M5 ;
        RECT  27.264 0 27.288 0.192 ;
    END
  END aq_q[39]
  PIN aq_q[3]
    DIRECTION INPUT ;
    USE SIGNAL ;
    PORT
      LAYER M5 ;
        RECT  24.672 0 24.696 0.192 ;
    END
  END aq_q[3]
  PIN aq_q[400]
    DIRECTION INPUT ;
    USE SIGNAL ;
    PORT
      LAYER M3 ;
        RECT  53.28 0 53.298 0.144 ;
    END
  END aq_q[400]
  PIN aq_q[401]
    DIRECTION INPUT ;
    USE SIGNAL ;
    PORT
      LAYER M5 ;
        RECT  53.328 0 53.352 0.192 ;
    END
  END aq_q[401]
  PIN aq_q[402]
    DIRECTION INPUT ;
    USE SIGNAL ;
    PORT
      LAYER M3 ;
        RECT  53.424 0 53.442 0.144 ;
    END
  END aq_q[402]
  PIN aq_q[403]
    DIRECTION INPUT ;
    USE SIGNAL ;
    PORT
      LAYER M5 ;
        RECT  53.472 0 53.496 0.192 ;
    END
  END aq_q[403]
  PIN aq_q[404]
    DIRECTION INPUT ;
    USE SIGNAL ;
    PORT
      LAYER M3 ;
        RECT  53.568 0 53.586 0.144 ;
    END
  END aq_q[404]
  PIN aq_q[405]
    DIRECTION INPUT ;
    USE SIGNAL ;
    PORT
      LAYER M5 ;
        RECT  53.616 0 53.64 0.192 ;
    END
  END aq_q[405]
  PIN aq_q[406]
    DIRECTION INPUT ;
    USE SIGNAL ;
    PORT
      LAYER M3 ;
        RECT  53.712 0 53.73 0.144 ;
    END
  END aq_q[406]
  PIN aq_q[407]
    DIRECTION INPUT ;
    USE SIGNAL ;
    PORT
      LAYER M5 ;
        RECT  53.76 0 53.784 0.192 ;
    END
  END aq_q[407]
  PIN aq_q[408]
    DIRECTION INPUT ;
    USE SIGNAL ;
    PORT
      LAYER M3 ;
        RECT  53.856 0 53.874 0.144 ;
    END
  END aq_q[408]
  PIN aq_q[409]
    DIRECTION INPUT ;
    USE SIGNAL ;
    PORT
      LAYER M5 ;
        RECT  53.904 0 53.928 0.192 ;
    END
  END aq_q[409]
  PIN aq_q[40]
    DIRECTION INPUT ;
    USE SIGNAL ;
    PORT
      LAYER M3 ;
        RECT  27.36 0 27.378 0.144 ;
    END
  END aq_q[40]
  PIN aq_q[410]
    DIRECTION INPUT ;
    USE SIGNAL ;
    PORT
      LAYER M3 ;
        RECT  54 0 54.018 0.144 ;
    END
  END aq_q[410]
  PIN aq_q[411]
    DIRECTION INPUT ;
    USE SIGNAL ;
    PORT
      LAYER M5 ;
        RECT  54.048 0 54.072 0.192 ;
    END
  END aq_q[411]
  PIN aq_q[412]
    DIRECTION INPUT ;
    USE SIGNAL ;
    PORT
      LAYER M3 ;
        RECT  54.144 0 54.162 0.144 ;
    END
  END aq_q[412]
  PIN aq_q[413]
    DIRECTION INPUT ;
    USE SIGNAL ;
    PORT
      LAYER M5 ;
        RECT  54.192 0 54.216 0.192 ;
    END
  END aq_q[413]
  PIN aq_q[414]
    DIRECTION INPUT ;
    USE SIGNAL ;
    PORT
      LAYER M3 ;
        RECT  54.288 0 54.306 0.144 ;
    END
  END aq_q[414]
  PIN aq_q[415]
    DIRECTION INPUT ;
    USE SIGNAL ;
    PORT
      LAYER M5 ;
        RECT  54.336 0 54.36 0.192 ;
    END
  END aq_q[415]
  PIN aq_q[416]
    DIRECTION INPUT ;
    USE SIGNAL ;
    PORT
      LAYER M3 ;
        RECT  54.432 0 54.45 0.144 ;
    END
  END aq_q[416]
  PIN aq_q[417]
    DIRECTION INPUT ;
    USE SIGNAL ;
    PORT
      LAYER M5 ;
        RECT  54.48 0 54.504 0.192 ;
    END
  END aq_q[417]
  PIN aq_q[418]
    DIRECTION INPUT ;
    USE SIGNAL ;
    PORT
      LAYER M3 ;
        RECT  54.576 0 54.594 0.144 ;
    END
  END aq_q[418]
  PIN aq_q[419]
    DIRECTION INPUT ;
    USE SIGNAL ;
    PORT
      LAYER M5 ;
        RECT  54.624 0 54.648 0.192 ;
    END
  END aq_q[419]
  PIN aq_q[41]
    DIRECTION INPUT ;
    USE SIGNAL ;
    PORT
      LAYER M5 ;
        RECT  27.408 0 27.432 0.192 ;
    END
  END aq_q[41]
  PIN aq_q[420]
    DIRECTION INPUT ;
    USE SIGNAL ;
    PORT
      LAYER M3 ;
        RECT  54.72 0 54.738 0.144 ;
    END
  END aq_q[420]
  PIN aq_q[421]
    DIRECTION INPUT ;
    USE SIGNAL ;
    PORT
      LAYER M5 ;
        RECT  54.768 0 54.792 0.192 ;
    END
  END aq_q[421]
  PIN aq_q[422]
    DIRECTION INPUT ;
    USE SIGNAL ;
    PORT
      LAYER M3 ;
        RECT  54.864 0 54.882 0.144 ;
    END
  END aq_q[422]
  PIN aq_q[423]
    DIRECTION INPUT ;
    USE SIGNAL ;
    PORT
      LAYER M5 ;
        RECT  54.912 0 54.936 0.192 ;
    END
  END aq_q[423]
  PIN aq_q[424]
    DIRECTION INPUT ;
    USE SIGNAL ;
    PORT
      LAYER M3 ;
        RECT  55.008 0 55.026 0.144 ;
    END
  END aq_q[424]
  PIN aq_q[425]
    DIRECTION INPUT ;
    USE SIGNAL ;
    PORT
      LAYER M5 ;
        RECT  55.056 0 55.08 0.192 ;
    END
  END aq_q[425]
  PIN aq_q[426]
    DIRECTION INPUT ;
    USE SIGNAL ;
    PORT
      LAYER M3 ;
        RECT  55.152 0 55.17 0.144 ;
    END
  END aq_q[426]
  PIN aq_q[427]
    DIRECTION INPUT ;
    USE SIGNAL ;
    PORT
      LAYER M5 ;
        RECT  55.2 0 55.224 0.192 ;
    END
  END aq_q[427]
  PIN aq_q[428]
    DIRECTION INPUT ;
    USE SIGNAL ;
    PORT
      LAYER M3 ;
        RECT  55.296 0 55.314 0.144 ;
    END
  END aq_q[428]
  PIN aq_q[429]
    DIRECTION INPUT ;
    USE SIGNAL ;
    PORT
      LAYER M5 ;
        RECT  55.344 0 55.368 0.192 ;
    END
  END aq_q[429]
  PIN aq_q[42]
    DIRECTION INPUT ;
    USE SIGNAL ;
    PORT
      LAYER M3 ;
        RECT  27.504 0 27.522 0.144 ;
    END
  END aq_q[42]
  PIN aq_q[430]
    DIRECTION INPUT ;
    USE SIGNAL ;
    PORT
      LAYER M3 ;
        RECT  55.44 0 55.458 0.144 ;
    END
  END aq_q[430]
  PIN aq_q[431]
    DIRECTION INPUT ;
    USE SIGNAL ;
    PORT
      LAYER M5 ;
        RECT  55.488 0 55.512 0.192 ;
    END
  END aq_q[431]
  PIN aq_q[432]
    DIRECTION INPUT ;
    USE SIGNAL ;
    PORT
      LAYER M3 ;
        RECT  55.584 0 55.602 0.144 ;
    END
  END aq_q[432]
  PIN aq_q[433]
    DIRECTION INPUT ;
    USE SIGNAL ;
    PORT
      LAYER M5 ;
        RECT  55.632 0 55.656 0.192 ;
    END
  END aq_q[433]
  PIN aq_q[434]
    DIRECTION INPUT ;
    USE SIGNAL ;
    PORT
      LAYER M3 ;
        RECT  55.728 0 55.746 0.144 ;
    END
  END aq_q[434]
  PIN aq_q[435]
    DIRECTION INPUT ;
    USE SIGNAL ;
    PORT
      LAYER M5 ;
        RECT  55.776 0 55.8 0.192 ;
    END
  END aq_q[435]
  PIN aq_q[436]
    DIRECTION INPUT ;
    USE SIGNAL ;
    PORT
      LAYER M3 ;
        RECT  55.872 0 55.89 0.144 ;
    END
  END aq_q[436]
  PIN aq_q[437]
    DIRECTION INPUT ;
    USE SIGNAL ;
    PORT
      LAYER M5 ;
        RECT  55.92 0 55.944 0.192 ;
    END
  END aq_q[437]
  PIN aq_q[438]
    DIRECTION INPUT ;
    USE SIGNAL ;
    PORT
      LAYER M3 ;
        RECT  56.016 0 56.034 0.144 ;
    END
  END aq_q[438]
  PIN aq_q[439]
    DIRECTION INPUT ;
    USE SIGNAL ;
    PORT
      LAYER M5 ;
        RECT  56.064 0 56.088 0.192 ;
    END
  END aq_q[439]
  PIN aq_q[43]
    DIRECTION INPUT ;
    USE SIGNAL ;
    PORT
      LAYER M5 ;
        RECT  27.552 0 27.576 0.192 ;
    END
  END aq_q[43]
  PIN aq_q[440]
    DIRECTION INPUT ;
    USE SIGNAL ;
    PORT
      LAYER M3 ;
        RECT  56.16 0 56.178 0.144 ;
    END
  END aq_q[440]
  PIN aq_q[441]
    DIRECTION INPUT ;
    USE SIGNAL ;
    PORT
      LAYER M5 ;
        RECT  56.208 0 56.232 0.192 ;
    END
  END aq_q[441]
  PIN aq_q[442]
    DIRECTION INPUT ;
    USE SIGNAL ;
    PORT
      LAYER M3 ;
        RECT  56.304 0 56.322 0.144 ;
    END
  END aq_q[442]
  PIN aq_q[443]
    DIRECTION INPUT ;
    USE SIGNAL ;
    PORT
      LAYER M5 ;
        RECT  56.352 0 56.376 0.192 ;
    END
  END aq_q[443]
  PIN aq_q[444]
    DIRECTION INPUT ;
    USE SIGNAL ;
    PORT
      LAYER M3 ;
        RECT  56.448 0 56.466 0.144 ;
    END
  END aq_q[444]
  PIN aq_q[445]
    DIRECTION INPUT ;
    USE SIGNAL ;
    PORT
      LAYER M5 ;
        RECT  56.496 0 56.52 0.192 ;
    END
  END aq_q[445]
  PIN aq_q[446]
    DIRECTION INPUT ;
    USE SIGNAL ;
    PORT
      LAYER M3 ;
        RECT  56.592 0 56.61 0.144 ;
    END
  END aq_q[446]
  PIN aq_q[447]
    DIRECTION INPUT ;
    USE SIGNAL ;
    PORT
      LAYER M5 ;
        RECT  56.64 0 56.664 0.192 ;
    END
  END aq_q[447]
  PIN aq_q[448]
    DIRECTION INPUT ;
    USE SIGNAL ;
    PORT
      LAYER M3 ;
        RECT  56.736 0 56.754 0.144 ;
    END
  END aq_q[448]
  PIN aq_q[449]
    DIRECTION INPUT ;
    USE SIGNAL ;
    PORT
      LAYER M5 ;
        RECT  56.784 0 56.808 0.192 ;
    END
  END aq_q[449]
  PIN aq_q[44]
    DIRECTION INPUT ;
    USE SIGNAL ;
    PORT
      LAYER M3 ;
        RECT  27.648 0 27.666 0.144 ;
    END
  END aq_q[44]
  PIN aq_q[450]
    DIRECTION INPUT ;
    USE SIGNAL ;
    PORT
      LAYER M3 ;
        RECT  56.88 0 56.898 0.144 ;
    END
  END aq_q[450]
  PIN aq_q[451]
    DIRECTION INPUT ;
    USE SIGNAL ;
    PORT
      LAYER M5 ;
        RECT  56.928 0 56.952 0.192 ;
    END
  END aq_q[451]
  PIN aq_q[452]
    DIRECTION INPUT ;
    USE SIGNAL ;
    PORT
      LAYER M3 ;
        RECT  57.024 0 57.042 0.144 ;
    END
  END aq_q[452]
  PIN aq_q[453]
    DIRECTION INPUT ;
    USE SIGNAL ;
    PORT
      LAYER M5 ;
        RECT  57.072 0 57.096 0.192 ;
    END
  END aq_q[453]
  PIN aq_q[454]
    DIRECTION INPUT ;
    USE SIGNAL ;
    PORT
      LAYER M3 ;
        RECT  57.168 0 57.186 0.144 ;
    END
  END aq_q[454]
  PIN aq_q[455]
    DIRECTION INPUT ;
    USE SIGNAL ;
    PORT
      LAYER M5 ;
        RECT  57.216 0 57.24 0.192 ;
    END
  END aq_q[455]
  PIN aq_q[456]
    DIRECTION INPUT ;
    USE SIGNAL ;
    PORT
      LAYER M3 ;
        RECT  57.312 0 57.33 0.144 ;
    END
  END aq_q[456]
  PIN aq_q[457]
    DIRECTION INPUT ;
    USE SIGNAL ;
    PORT
      LAYER M5 ;
        RECT  57.36 0 57.384 0.192 ;
    END
  END aq_q[457]
  PIN aq_q[458]
    DIRECTION INPUT ;
    USE SIGNAL ;
    PORT
      LAYER M3 ;
        RECT  57.456 0 57.474 0.144 ;
    END
  END aq_q[458]
  PIN aq_q[459]
    DIRECTION INPUT ;
    USE SIGNAL ;
    PORT
      LAYER M5 ;
        RECT  57.504 0 57.528 0.192 ;
    END
  END aq_q[459]
  PIN aq_q[45]
    DIRECTION INPUT ;
    USE SIGNAL ;
    PORT
      LAYER M5 ;
        RECT  27.696 0 27.72 0.192 ;
    END
  END aq_q[45]
  PIN aq_q[460]
    DIRECTION INPUT ;
    USE SIGNAL ;
    PORT
      LAYER M3 ;
        RECT  57.6 0 57.618 0.144 ;
    END
  END aq_q[460]
  PIN aq_q[461]
    DIRECTION INPUT ;
    USE SIGNAL ;
    PORT
      LAYER M5 ;
        RECT  57.648 0 57.672 0.192 ;
    END
  END aq_q[461]
  PIN aq_q[462]
    DIRECTION INPUT ;
    USE SIGNAL ;
    PORT
      LAYER M3 ;
        RECT  57.744 0 57.762 0.144 ;
    END
  END aq_q[462]
  PIN aq_q[463]
    DIRECTION INPUT ;
    USE SIGNAL ;
    PORT
      LAYER M5 ;
        RECT  57.792 0 57.816 0.192 ;
    END
  END aq_q[463]
  PIN aq_q[464]
    DIRECTION INPUT ;
    USE SIGNAL ;
    PORT
      LAYER M3 ;
        RECT  57.888 0 57.906 0.144 ;
    END
  END aq_q[464]
  PIN aq_q[465]
    DIRECTION INPUT ;
    USE SIGNAL ;
    PORT
      LAYER M5 ;
        RECT  57.936 0 57.96 0.192 ;
    END
  END aq_q[465]
  PIN aq_q[466]
    DIRECTION INPUT ;
    USE SIGNAL ;
    PORT
      LAYER M3 ;
        RECT  58.032 0 58.05 0.144 ;
    END
  END aq_q[466]
  PIN aq_q[467]
    DIRECTION INPUT ;
    USE SIGNAL ;
    PORT
      LAYER M5 ;
        RECT  58.08 0 58.104 0.192 ;
    END
  END aq_q[467]
  PIN aq_q[468]
    DIRECTION INPUT ;
    USE SIGNAL ;
    PORT
      LAYER M3 ;
        RECT  58.176 0 58.194 0.144 ;
    END
  END aq_q[468]
  PIN aq_q[469]
    DIRECTION INPUT ;
    USE SIGNAL ;
    PORT
      LAYER M5 ;
        RECT  58.224 0 58.248 0.192 ;
    END
  END aq_q[469]
  PIN aq_q[46]
    DIRECTION INPUT ;
    USE SIGNAL ;
    PORT
      LAYER M3 ;
        RECT  27.792 0 27.81 0.144 ;
    END
  END aq_q[46]
  PIN aq_q[470]
    DIRECTION INPUT ;
    USE SIGNAL ;
    PORT
      LAYER M3 ;
        RECT  58.32 0 58.338 0.144 ;
    END
  END aq_q[470]
  PIN aq_q[471]
    DIRECTION INPUT ;
    USE SIGNAL ;
    PORT
      LAYER M5 ;
        RECT  58.368 0 58.392 0.192 ;
    END
  END aq_q[471]
  PIN aq_q[472]
    DIRECTION INPUT ;
    USE SIGNAL ;
    PORT
      LAYER M3 ;
        RECT  58.464 0 58.482 0.144 ;
    END
  END aq_q[472]
  PIN aq_q[473]
    DIRECTION INPUT ;
    USE SIGNAL ;
    PORT
      LAYER M5 ;
        RECT  58.512 0 58.536 0.192 ;
    END
  END aq_q[473]
  PIN aq_q[474]
    DIRECTION INPUT ;
    USE SIGNAL ;
    PORT
      LAYER M3 ;
        RECT  58.608 0 58.626 0.144 ;
    END
  END aq_q[474]
  PIN aq_q[475]
    DIRECTION INPUT ;
    USE SIGNAL ;
    PORT
      LAYER M5 ;
        RECT  58.656 0 58.68 0.192 ;
    END
  END aq_q[475]
  PIN aq_q[476]
    DIRECTION INPUT ;
    USE SIGNAL ;
    PORT
      LAYER M3 ;
        RECT  58.752 0 58.77 0.144 ;
    END
  END aq_q[476]
  PIN aq_q[477]
    DIRECTION INPUT ;
    USE SIGNAL ;
    PORT
      LAYER M5 ;
        RECT  58.8 0 58.824 0.192 ;
    END
  END aq_q[477]
  PIN aq_q[478]
    DIRECTION INPUT ;
    USE SIGNAL ;
    PORT
      LAYER M3 ;
        RECT  58.896 0 58.914 0.144 ;
    END
  END aq_q[478]
  PIN aq_q[479]
    DIRECTION INPUT ;
    USE SIGNAL ;
    PORT
      LAYER M5 ;
        RECT  58.944 0 58.968 0.192 ;
    END
  END aq_q[479]
  PIN aq_q[47]
    DIRECTION INPUT ;
    USE SIGNAL ;
    PORT
      LAYER M5 ;
        RECT  27.84 0 27.864 0.192 ;
    END
  END aq_q[47]
  PIN aq_q[480]
    DIRECTION INPUT ;
    USE SIGNAL ;
    PORT
      LAYER M3 ;
        RECT  59.04 0 59.058 0.144 ;
    END
  END aq_q[480]
  PIN aq_q[481]
    DIRECTION INPUT ;
    USE SIGNAL ;
    PORT
      LAYER M5 ;
        RECT  59.088 0 59.112 0.192 ;
    END
  END aq_q[481]
  PIN aq_q[482]
    DIRECTION INPUT ;
    USE SIGNAL ;
    PORT
      LAYER M3 ;
        RECT  59.184 0 59.202 0.144 ;
    END
  END aq_q[482]
  PIN aq_q[483]
    DIRECTION INPUT ;
    USE SIGNAL ;
    PORT
      LAYER M5 ;
        RECT  59.232 0 59.256 0.192 ;
    END
  END aq_q[483]
  PIN aq_q[484]
    DIRECTION INPUT ;
    USE SIGNAL ;
    PORT
      LAYER M3 ;
        RECT  59.328 0 59.346 0.144 ;
    END
  END aq_q[484]
  PIN aq_q[485]
    DIRECTION INPUT ;
    USE SIGNAL ;
    PORT
      LAYER M5 ;
        RECT  59.376 0 59.4 0.192 ;
    END
  END aq_q[485]
  PIN aq_q[486]
    DIRECTION INPUT ;
    USE SIGNAL ;
    PORT
      LAYER M3 ;
        RECT  59.472 0 59.49 0.144 ;
    END
  END aq_q[486]
  PIN aq_q[487]
    DIRECTION INPUT ;
    USE SIGNAL ;
    PORT
      LAYER M5 ;
        RECT  59.52 0 59.544 0.192 ;
    END
  END aq_q[487]
  PIN aq_q[488]
    DIRECTION INPUT ;
    USE SIGNAL ;
    PORT
      LAYER M3 ;
        RECT  59.616 0 59.634 0.144 ;
    END
  END aq_q[488]
  PIN aq_q[489]
    DIRECTION INPUT ;
    USE SIGNAL ;
    PORT
      LAYER M5 ;
        RECT  59.664 0 59.688 0.192 ;
    END
  END aq_q[489]
  PIN aq_q[48]
    DIRECTION INPUT ;
    USE SIGNAL ;
    PORT
      LAYER M3 ;
        RECT  27.936 0 27.954 0.144 ;
    END
  END aq_q[48]
  PIN aq_q[490]
    DIRECTION INPUT ;
    USE SIGNAL ;
    PORT
      LAYER M3 ;
        RECT  59.76 0 59.778 0.144 ;
    END
  END aq_q[490]
  PIN aq_q[491]
    DIRECTION INPUT ;
    USE SIGNAL ;
    PORT
      LAYER M5 ;
        RECT  59.808 0 59.832 0.192 ;
    END
  END aq_q[491]
  PIN aq_q[492]
    DIRECTION INPUT ;
    USE SIGNAL ;
    PORT
      LAYER M3 ;
        RECT  59.904 0 59.922 0.144 ;
    END
  END aq_q[492]
  PIN aq_q[493]
    DIRECTION INPUT ;
    USE SIGNAL ;
    PORT
      LAYER M5 ;
        RECT  59.952 0 59.976 0.192 ;
    END
  END aq_q[493]
  PIN aq_q[494]
    DIRECTION INPUT ;
    USE SIGNAL ;
    PORT
      LAYER M3 ;
        RECT  60.048 0 60.066 0.144 ;
    END
  END aq_q[494]
  PIN aq_q[495]
    DIRECTION INPUT ;
    USE SIGNAL ;
    PORT
      LAYER M5 ;
        RECT  60.096 0 60.12 0.192 ;
    END
  END aq_q[495]
  PIN aq_q[496]
    DIRECTION INPUT ;
    USE SIGNAL ;
    PORT
      LAYER M3 ;
        RECT  60.192 0 60.21 0.144 ;
    END
  END aq_q[496]
  PIN aq_q[497]
    DIRECTION INPUT ;
    USE SIGNAL ;
    PORT
      LAYER M5 ;
        RECT  60.24 0 60.264 0.192 ;
    END
  END aq_q[497]
  PIN aq_q[498]
    DIRECTION INPUT ;
    USE SIGNAL ;
    PORT
      LAYER M3 ;
        RECT  60.336 0 60.354 0.144 ;
    END
  END aq_q[498]
  PIN aq_q[499]
    DIRECTION INPUT ;
    USE SIGNAL ;
    PORT
      LAYER M5 ;
        RECT  60.384 0 60.408 0.192 ;
    END
  END aq_q[499]
  PIN aq_q[49]
    DIRECTION INPUT ;
    USE SIGNAL ;
    PORT
      LAYER M5 ;
        RECT  27.984 0 28.008 0.192 ;
    END
  END aq_q[49]
  PIN aq_q[4]
    DIRECTION INPUT ;
    USE SIGNAL ;
    PORT
      LAYER M3 ;
        RECT  24.768 0 24.786 0.144 ;
    END
  END aq_q[4]
  PIN aq_q[500]
    DIRECTION INPUT ;
    USE SIGNAL ;
    PORT
      LAYER M3 ;
        RECT  60.48 0 60.498 0.144 ;
    END
  END aq_q[500]
  PIN aq_q[501]
    DIRECTION INPUT ;
    USE SIGNAL ;
    PORT
      LAYER M5 ;
        RECT  60.528 0 60.552 0.192 ;
    END
  END aq_q[501]
  PIN aq_q[502]
    DIRECTION INPUT ;
    USE SIGNAL ;
    PORT
      LAYER M3 ;
        RECT  60.624 0 60.642 0.144 ;
    END
  END aq_q[502]
  PIN aq_q[503]
    DIRECTION INPUT ;
    USE SIGNAL ;
    PORT
      LAYER M5 ;
        RECT  60.672 0 60.696 0.192 ;
    END
  END aq_q[503]
  PIN aq_q[504]
    DIRECTION INPUT ;
    USE SIGNAL ;
    PORT
      LAYER M3 ;
        RECT  60.768 0 60.786 0.144 ;
    END
  END aq_q[504]
  PIN aq_q[505]
    DIRECTION INPUT ;
    USE SIGNAL ;
    PORT
      LAYER M5 ;
        RECT  60.816 0 60.84 0.192 ;
    END
  END aq_q[505]
  PIN aq_q[506]
    DIRECTION INPUT ;
    USE SIGNAL ;
    PORT
      LAYER M3 ;
        RECT  60.912 0 60.93 0.144 ;
    END
  END aq_q[506]
  PIN aq_q[507]
    DIRECTION INPUT ;
    USE SIGNAL ;
    PORT
      LAYER M5 ;
        RECT  60.96 0 60.984 0.192 ;
    END
  END aq_q[507]
  PIN aq_q[508]
    DIRECTION INPUT ;
    USE SIGNAL ;
    PORT
      LAYER M3 ;
        RECT  61.056 0 61.074 0.144 ;
    END
  END aq_q[508]
  PIN aq_q[509]
    DIRECTION INPUT ;
    USE SIGNAL ;
    PORT
      LAYER M5 ;
        RECT  61.104 0 61.128 0.192 ;
    END
  END aq_q[509]
  PIN aq_q[50]
    DIRECTION INPUT ;
    USE SIGNAL ;
    PORT
      LAYER M3 ;
        RECT  28.08 0 28.098 0.144 ;
    END
  END aq_q[50]
  PIN aq_q[510]
    DIRECTION INPUT ;
    USE SIGNAL ;
    PORT
      LAYER M3 ;
        RECT  61.2 0 61.218 0.144 ;
    END
  END aq_q[510]
  PIN aq_q[511]
    DIRECTION INPUT ;
    USE SIGNAL ;
    PORT
      LAYER M5 ;
        RECT  61.248 0 61.272 0.192 ;
    END
  END aq_q[511]
  PIN aq_q[51]
    DIRECTION INPUT ;
    USE SIGNAL ;
    PORT
      LAYER M5 ;
        RECT  28.128 0 28.152 0.192 ;
    END
  END aq_q[51]
  PIN aq_q[52]
    DIRECTION INPUT ;
    USE SIGNAL ;
    PORT
      LAYER M3 ;
        RECT  28.224 0 28.242 0.144 ;
    END
  END aq_q[52]
  PIN aq_q[53]
    DIRECTION INPUT ;
    USE SIGNAL ;
    PORT
      LAYER M5 ;
        RECT  28.272 0 28.296 0.192 ;
    END
  END aq_q[53]
  PIN aq_q[54]
    DIRECTION INPUT ;
    USE SIGNAL ;
    PORT
      LAYER M3 ;
        RECT  28.368 0 28.386 0.144 ;
    END
  END aq_q[54]
  PIN aq_q[55]
    DIRECTION INPUT ;
    USE SIGNAL ;
    PORT
      LAYER M5 ;
        RECT  28.416 0 28.44 0.192 ;
    END
  END aq_q[55]
  PIN aq_q[56]
    DIRECTION INPUT ;
    USE SIGNAL ;
    PORT
      LAYER M3 ;
        RECT  28.512 0 28.53 0.144 ;
    END
  END aq_q[56]
  PIN aq_q[57]
    DIRECTION INPUT ;
    USE SIGNAL ;
    PORT
      LAYER M5 ;
        RECT  28.56 0 28.584 0.192 ;
    END
  END aq_q[57]
  PIN aq_q[58]
    DIRECTION INPUT ;
    USE SIGNAL ;
    PORT
      LAYER M3 ;
        RECT  28.656 0 28.674 0.144 ;
    END
  END aq_q[58]
  PIN aq_q[59]
    DIRECTION INPUT ;
    USE SIGNAL ;
    PORT
      LAYER M5 ;
        RECT  28.704 0 28.728 0.192 ;
    END
  END aq_q[59]
  PIN aq_q[5]
    DIRECTION INPUT ;
    USE SIGNAL ;
    PORT
      LAYER M5 ;
        RECT  24.816 0 24.84 0.192 ;
    END
  END aq_q[5]
  PIN aq_q[60]
    DIRECTION INPUT ;
    USE SIGNAL ;
    PORT
      LAYER M3 ;
        RECT  28.8 0 28.818 0.144 ;
    END
  END aq_q[60]
  PIN aq_q[61]
    DIRECTION INPUT ;
    USE SIGNAL ;
    PORT
      LAYER M5 ;
        RECT  28.848 0 28.872 0.192 ;
    END
  END aq_q[61]
  PIN aq_q[62]
    DIRECTION INPUT ;
    USE SIGNAL ;
    PORT
      LAYER M3 ;
        RECT  28.944 0 28.962 0.144 ;
    END
  END aq_q[62]
  PIN aq_q[63]
    DIRECTION INPUT ;
    USE SIGNAL ;
    PORT
      LAYER M5 ;
        RECT  28.992 0 29.016 0.192 ;
    END
  END aq_q[63]
  PIN aq_q[64]
    DIRECTION INPUT ;
    USE SIGNAL ;
    PORT
      LAYER M3 ;
        RECT  29.088 0 29.106 0.144 ;
    END
  END aq_q[64]
  PIN aq_q[65]
    DIRECTION INPUT ;
    USE SIGNAL ;
    PORT
      LAYER M5 ;
        RECT  29.136 0 29.16 0.192 ;
    END
  END aq_q[65]
  PIN aq_q[66]
    DIRECTION INPUT ;
    USE SIGNAL ;
    PORT
      LAYER M3 ;
        RECT  29.232 0 29.25 0.144 ;
    END
  END aq_q[66]
  PIN aq_q[67]
    DIRECTION INPUT ;
    USE SIGNAL ;
    PORT
      LAYER M5 ;
        RECT  29.28 0 29.304 0.192 ;
    END
  END aq_q[67]
  PIN aq_q[68]
    DIRECTION INPUT ;
    USE SIGNAL ;
    PORT
      LAYER M3 ;
        RECT  29.376 0 29.394 0.144 ;
    END
  END aq_q[68]
  PIN aq_q[69]
    DIRECTION INPUT ;
    USE SIGNAL ;
    PORT
      LAYER M5 ;
        RECT  29.424 0 29.448 0.192 ;
    END
  END aq_q[69]
  PIN aq_q[6]
    DIRECTION INPUT ;
    USE SIGNAL ;
    PORT
      LAYER M3 ;
        RECT  24.912 0 24.93 0.144 ;
    END
  END aq_q[6]
  PIN aq_q[70]
    DIRECTION INPUT ;
    USE SIGNAL ;
    PORT
      LAYER M3 ;
        RECT  29.52 0 29.538 0.144 ;
    END
  END aq_q[70]
  PIN aq_q[71]
    DIRECTION INPUT ;
    USE SIGNAL ;
    PORT
      LAYER M5 ;
        RECT  29.568 0 29.592 0.192 ;
    END
  END aq_q[71]
  PIN aq_q[72]
    DIRECTION INPUT ;
    USE SIGNAL ;
    PORT
      LAYER M3 ;
        RECT  29.664 0 29.682 0.144 ;
    END
  END aq_q[72]
  PIN aq_q[73]
    DIRECTION INPUT ;
    USE SIGNAL ;
    PORT
      LAYER M5 ;
        RECT  29.712 0 29.736 0.192 ;
    END
  END aq_q[73]
  PIN aq_q[74]
    DIRECTION INPUT ;
    USE SIGNAL ;
    PORT
      LAYER M3 ;
        RECT  29.808 0 29.826 0.144 ;
    END
  END aq_q[74]
  PIN aq_q[75]
    DIRECTION INPUT ;
    USE SIGNAL ;
    PORT
      LAYER M5 ;
        RECT  29.856 0 29.88 0.192 ;
    END
  END aq_q[75]
  PIN aq_q[76]
    DIRECTION INPUT ;
    USE SIGNAL ;
    PORT
      LAYER M3 ;
        RECT  29.952 0 29.97 0.144 ;
    END
  END aq_q[76]
  PIN aq_q[77]
    DIRECTION INPUT ;
    USE SIGNAL ;
    PORT
      LAYER M5 ;
        RECT  30 0 30.024 0.192 ;
    END
  END aq_q[77]
  PIN aq_q[78]
    DIRECTION INPUT ;
    USE SIGNAL ;
    PORT
      LAYER M3 ;
        RECT  30.096 0 30.114 0.144 ;
    END
  END aq_q[78]
  PIN aq_q[79]
    DIRECTION INPUT ;
    USE SIGNAL ;
    PORT
      LAYER M5 ;
        RECT  30.144 0 30.168 0.192 ;
    END
  END aq_q[79]
  PIN aq_q[7]
    DIRECTION INPUT ;
    USE SIGNAL ;
    PORT
      LAYER M5 ;
        RECT  24.96 0 24.984 0.192 ;
    END
  END aq_q[7]
  PIN aq_q[80]
    DIRECTION INPUT ;
    USE SIGNAL ;
    PORT
      LAYER M3 ;
        RECT  30.24 0 30.258 0.144 ;
    END
  END aq_q[80]
  PIN aq_q[81]
    DIRECTION INPUT ;
    USE SIGNAL ;
    PORT
      LAYER M5 ;
        RECT  30.288 0 30.312 0.192 ;
    END
  END aq_q[81]
  PIN aq_q[82]
    DIRECTION INPUT ;
    USE SIGNAL ;
    PORT
      LAYER M3 ;
        RECT  30.384 0 30.402 0.144 ;
    END
  END aq_q[82]
  PIN aq_q[83]
    DIRECTION INPUT ;
    USE SIGNAL ;
    PORT
      LAYER M5 ;
        RECT  30.432 0 30.456 0.192 ;
    END
  END aq_q[83]
  PIN aq_q[84]
    DIRECTION INPUT ;
    USE SIGNAL ;
    PORT
      LAYER M3 ;
        RECT  30.528 0 30.546 0.144 ;
    END
  END aq_q[84]
  PIN aq_q[85]
    DIRECTION INPUT ;
    USE SIGNAL ;
    PORT
      LAYER M5 ;
        RECT  30.576 0 30.6 0.192 ;
    END
  END aq_q[85]
  PIN aq_q[86]
    DIRECTION INPUT ;
    USE SIGNAL ;
    PORT
      LAYER M3 ;
        RECT  30.672 0 30.69 0.144 ;
    END
  END aq_q[86]
  PIN aq_q[87]
    DIRECTION INPUT ;
    USE SIGNAL ;
    PORT
      LAYER M5 ;
        RECT  30.72 0 30.744 0.192 ;
    END
  END aq_q[87]
  PIN aq_q[88]
    DIRECTION INPUT ;
    USE SIGNAL ;
    PORT
      LAYER M3 ;
        RECT  30.816 0 30.834 0.144 ;
    END
  END aq_q[88]
  PIN aq_q[89]
    DIRECTION INPUT ;
    USE SIGNAL ;
    PORT
      LAYER M5 ;
        RECT  30.864 0 30.888 0.192 ;
    END
  END aq_q[89]
  PIN aq_q[8]
    DIRECTION INPUT ;
    USE SIGNAL ;
    PORT
      LAYER M3 ;
        RECT  25.056 0 25.074 0.144 ;
    END
  END aq_q[8]
  PIN aq_q[90]
    DIRECTION INPUT ;
    USE SIGNAL ;
    PORT
      LAYER M3 ;
        RECT  30.96 0 30.978 0.144 ;
    END
  END aq_q[90]
  PIN aq_q[91]
    DIRECTION INPUT ;
    USE SIGNAL ;
    PORT
      LAYER M5 ;
        RECT  31.008 0 31.032 0.192 ;
    END
  END aq_q[91]
  PIN aq_q[92]
    DIRECTION INPUT ;
    USE SIGNAL ;
    PORT
      LAYER M3 ;
        RECT  31.104 0 31.122 0.144 ;
    END
  END aq_q[92]
  PIN aq_q[93]
    DIRECTION INPUT ;
    USE SIGNAL ;
    PORT
      LAYER M5 ;
        RECT  31.152 0 31.176 0.192 ;
    END
  END aq_q[93]
  PIN aq_q[94]
    DIRECTION INPUT ;
    USE SIGNAL ;
    PORT
      LAYER M3 ;
        RECT  31.248 0 31.266 0.144 ;
    END
  END aq_q[94]
  PIN aq_q[95]
    DIRECTION INPUT ;
    USE SIGNAL ;
    PORT
      LAYER M5 ;
        RECT  31.296 0 31.32 0.192 ;
    END
  END aq_q[95]
  PIN aq_q[96]
    DIRECTION INPUT ;
    USE SIGNAL ;
    PORT
      LAYER M3 ;
        RECT  31.392 0 31.41 0.144 ;
    END
  END aq_q[96]
  PIN aq_q[97]
    DIRECTION INPUT ;
    USE SIGNAL ;
    PORT
      LAYER M5 ;
        RECT  31.44 0 31.464 0.192 ;
    END
  END aq_q[97]
  PIN aq_q[98]
    DIRECTION INPUT ;
    USE SIGNAL ;
    PORT
      LAYER M3 ;
        RECT  31.536 0 31.554 0.144 ;
    END
  END aq_q[98]
  PIN aq_q[99]
    DIRECTION INPUT ;
    USE SIGNAL ;
    PORT
      LAYER M5 ;
        RECT  31.584 0 31.608 0.192 ;
    END
  END aq_q[99]
  PIN aq_q[9]
    DIRECTION INPUT ;
    USE SIGNAL ;
    PORT
      LAYER M5 ;
        RECT  25.104 0 25.128 0.192 ;
    END
  END aq_q[9]
  PIN clk
    DIRECTION INPUT ;
    USE SIGNAL ;
    PORT
      LAYER M4 ;
        RECT  0 52.032 0.192 52.056 ;
    END
    PORT
      LAYER M4 ;
        RECT  0.156 52.032 0.205 52.056 ;
    END
  END clk
  PIN erd[0]
    DIRECTION OUTPUT ;
    USE SIGNAL ;
    PORT
      LAYER M3 ;
        RECT  47.52 86.256 47.538 86.4 ;
    END
  END erd[0]
  PIN erd[1]
    DIRECTION OUTPUT ;
    USE SIGNAL ;
    PORT
      LAYER M3 ;
        RECT  47.664 86.256 47.682 86.4 ;
    END
  END erd[1]
  PIN erd[2]
    DIRECTION OUTPUT ;
    USE SIGNAL ;
    PORT
      LAYER M3 ;
        RECT  47.808 86.256 47.826 86.4 ;
    END
  END erd[2]
  PIN erd[3]
    DIRECTION OUTPUT ;
    USE SIGNAL ;
    PORT
      LAYER M3 ;
        RECT  47.952 86.256 47.97 86.4 ;
    END
  END erd[3]
  PIN erd[4]
    DIRECTION OUTPUT ;
    USE SIGNAL ;
    PORT
      LAYER M3 ;
        RECT  48.096 86.256 48.114 86.4 ;
    END
  END erd[4]
  PIN erd[5]
    DIRECTION OUTPUT ;
    USE SIGNAL ;
    PORT
      LAYER M3 ;
        RECT  48.24 86.256 48.258 86.4 ;
    END
  END erd[5]
  PIN erd[6]
    DIRECTION OUTPUT ;
    USE SIGNAL ;
    PORT
      LAYER M3 ;
        RECT  48.384 86.256 48.402 86.4 ;
    END
  END erd[6]
  PIN erd[7]
    DIRECTION OUTPUT ;
    USE SIGNAL ;
    PORT
      LAYER M3 ;
        RECT  48.528 86.256 48.546 86.4 ;
    END
  END erd[7]
  PIN erd[8]
    DIRECTION OUTPUT ;
    USE SIGNAL ;
    PORT
      LAYER M3 ;
        RECT  48.672 86.256 48.69 86.4 ;
    END
  END erd[8]
  PIN erd[9]
    DIRECTION OUTPUT ;
    USE SIGNAL ;
    PORT
      LAYER M3 ;
        RECT  48.816 86.256 48.834 86.4 ;
    END
  END erd[9]
  PIN fault
    DIRECTION OUTPUT ;
    USE SIGNAL ;
    PORT
      LAYER M4 ;
        RECT  142.368 52.032 142.56 52.056 ;
    END
    PORT
      LAYER M4 ;
        RECT  141.325 52.032 142.38 52.056 ;
    END
  END fault
  PIN i0[0]
    DIRECTION INPUT ;
    USE SIGNAL ;
    PORT
      LAYER M4 ;
        RECT  0 41.616 0.192 41.64 ;
    END
  END i0[0]
  PIN i0[10]
    DIRECTION INPUT ;
    USE SIGNAL ;
    PORT
      LAYER M4 ;
        RECT  0 43.056 0.192 43.08 ;
    END
  END i0[10]
  PIN i0[11]
    DIRECTION INPUT ;
    USE SIGNAL ;
    PORT
      LAYER M4 ;
        RECT  0 43.2 0.192 43.224 ;
    END
  END i0[11]
  PIN i0[12]
    DIRECTION INPUT ;
    USE SIGNAL ;
    PORT
      LAYER M4 ;
        RECT  0 43.344 0.192 43.368 ;
    END
  END i0[12]
  PIN i0[13]
    DIRECTION INPUT ;
    USE SIGNAL ;
    PORT
      LAYER M4 ;
        RECT  0 43.488 0.192 43.512 ;
    END
  END i0[13]
  PIN i0[14]
    DIRECTION INPUT ;
    USE SIGNAL ;
    PORT
      LAYER M4 ;
        RECT  0 43.632 0.192 43.656 ;
    END
  END i0[14]
  PIN i0[15]
    DIRECTION INPUT ;
    USE SIGNAL ;
    PORT
      LAYER M4 ;
        RECT  0 43.776 0.192 43.8 ;
    END
  END i0[15]
  PIN i0[1]
    DIRECTION INPUT ;
    USE SIGNAL ;
    PORT
      LAYER M4 ;
        RECT  0 41.76 0.192 41.784 ;
    END
  END i0[1]
  PIN i0[2]
    DIRECTION INPUT ;
    USE SIGNAL ;
    PORT
      LAYER M4 ;
        RECT  0 41.904 0.192 41.928 ;
    END
  END i0[2]
  PIN i0[3]
    DIRECTION INPUT ;
    USE SIGNAL ;
    PORT
      LAYER M4 ;
        RECT  0 42.048 0.192 42.072 ;
    END
  END i0[3]
  PIN i0[4]
    DIRECTION INPUT ;
    USE SIGNAL ;
    PORT
      LAYER M4 ;
        RECT  0 42.192 0.192 42.216 ;
    END
  END i0[4]
  PIN i0[5]
    DIRECTION INPUT ;
    USE SIGNAL ;
    PORT
      LAYER M4 ;
        RECT  0 42.336 0.192 42.36 ;
    END
  END i0[5]
  PIN i0[6]
    DIRECTION INPUT ;
    USE SIGNAL ;
    PORT
      LAYER M4 ;
        RECT  0 42.48 0.192 42.504 ;
    END
  END i0[6]
  PIN i0[7]
    DIRECTION INPUT ;
    USE SIGNAL ;
    PORT
      LAYER M4 ;
        RECT  0 42.624 0.192 42.648 ;
    END
  END i0[7]
  PIN i0[8]
    DIRECTION INPUT ;
    USE SIGNAL ;
    PORT
      LAYER M4 ;
        RECT  0 42.768 0.192 42.792 ;
    END
  END i0[8]
  PIN i0[9]
    DIRECTION INPUT ;
    USE SIGNAL ;
    PORT
      LAYER M4 ;
        RECT  0 42.912 0.192 42.936 ;
    END
  END i0[9]
  PIN i1[0]
    DIRECTION INPUT ;
    USE SIGNAL ;
    PORT
      LAYER M4 ;
        RECT  0 43.92 0.192 43.944 ;
    END
  END i1[0]
  PIN i1[10]
    DIRECTION INPUT ;
    USE SIGNAL ;
    PORT
      LAYER M4 ;
        RECT  0 45.36 0.192 45.384 ;
    END
  END i1[10]
  PIN i1[11]
    DIRECTION INPUT ;
    USE SIGNAL ;
    PORT
      LAYER M4 ;
        RECT  0 45.504 0.192 45.528 ;
    END
  END i1[11]
  PIN i1[12]
    DIRECTION INPUT ;
    USE SIGNAL ;
    PORT
      LAYER M4 ;
        RECT  0 45.648 0.192 45.672 ;
    END
  END i1[12]
  PIN i1[13]
    DIRECTION INPUT ;
    USE SIGNAL ;
    PORT
      LAYER M4 ;
        RECT  0 45.792 0.192 45.816 ;
    END
  END i1[13]
  PIN i1[14]
    DIRECTION INPUT ;
    USE SIGNAL ;
    PORT
      LAYER M4 ;
        RECT  0 45.936 0.192 45.96 ;
    END
  END i1[14]
  PIN i1[15]
    DIRECTION INPUT ;
    USE SIGNAL ;
    PORT
      LAYER M4 ;
        RECT  0 46.08 0.192 46.104 ;
    END
  END i1[15]
  PIN i1[1]
    DIRECTION INPUT ;
    USE SIGNAL ;
    PORT
      LAYER M4 ;
        RECT  0 44.064 0.192 44.088 ;
    END
  END i1[1]
  PIN i1[2]
    DIRECTION INPUT ;
    USE SIGNAL ;
    PORT
      LAYER M4 ;
        RECT  0 44.208 0.192 44.232 ;
    END
  END i1[2]
  PIN i1[3]
    DIRECTION INPUT ;
    USE SIGNAL ;
    PORT
      LAYER M4 ;
        RECT  0 44.352 0.192 44.376 ;
    END
  END i1[3]
  PIN i1[4]
    DIRECTION INPUT ;
    USE SIGNAL ;
    PORT
      LAYER M4 ;
        RECT  0 44.496 0.192 44.52 ;
    END
  END i1[4]
  PIN i1[5]
    DIRECTION INPUT ;
    USE SIGNAL ;
    PORT
      LAYER M4 ;
        RECT  0 44.64 0.192 44.664 ;
    END
  END i1[5]
  PIN i1[6]
    DIRECTION INPUT ;
    USE SIGNAL ;
    PORT
      LAYER M4 ;
        RECT  0 44.784 0.192 44.808 ;
    END
  END i1[6]
  PIN i1[7]
    DIRECTION INPUT ;
    USE SIGNAL ;
    PORT
      LAYER M4 ;
        RECT  0 44.928 0.192 44.952 ;
    END
  END i1[7]
  PIN i1[8]
    DIRECTION INPUT ;
    USE SIGNAL ;
    PORT
      LAYER M4 ;
        RECT  0 45.072 0.192 45.096 ;
    END
  END i1[8]
  PIN i1[9]
    DIRECTION INPUT ;
    USE SIGNAL ;
    PORT
      LAYER M4 ;
        RECT  0 45.216 0.192 45.24 ;
    END
  END i1[9]
  PIN ph0[0]
    DIRECTION INPUT ;
    USE SIGNAL ;
    PORT
      LAYER M4 ;
        RECT  0 38.448 0.192 38.472 ;
    END
  END ph0[0]
  PIN ph0[1]
    DIRECTION INPUT ;
    USE SIGNAL ;
    PORT
      LAYER M4 ;
        RECT  0 38.304 0.192 38.328 ;
    END
  END ph0[1]
  PIN ph0[2]
    DIRECTION INPUT ;
    USE SIGNAL ;
    PORT
      LAYER M4 ;
        RECT  0 38.16 0.192 38.184 ;
    END
  END ph0[2]
  PIN ph0[3]
    DIRECTION INPUT ;
    USE SIGNAL ;
    PORT
      LAYER M4 ;
        RECT  0 38.016 0.192 38.04 ;
    END
  END ph0[3]
  PIN ph0[4]
    DIRECTION INPUT ;
    USE SIGNAL ;
    PORT
      LAYER M4 ;
        RECT  0 37.872 0.192 37.896 ;
    END
  END ph0[4]
  PIN ph0[5]
    DIRECTION INPUT ;
    USE SIGNAL ;
    PORT
      LAYER M4 ;
        RECT  0 37.728 0.192 37.752 ;
    END
  END ph0[5]
  PIN ph1[0]
    DIRECTION INPUT ;
    USE SIGNAL ;
    PORT
      LAYER M4 ;
        RECT  0 37.584 0.192 37.608 ;
    END
  END ph1[0]
  PIN ph1[1]
    DIRECTION INPUT ;
    USE SIGNAL ;
    PORT
      LAYER M4 ;
        RECT  0 37.44 0.192 37.464 ;
    END
  END ph1[1]
  PIN ph1[2]
    DIRECTION INPUT ;
    USE SIGNAL ;
    PORT
      LAYER M4 ;
        RECT  0 37.296 0.192 37.32 ;
    END
  END ph1[2]
  PIN ph1[3]
    DIRECTION INPUT ;
    USE SIGNAL ;
    PORT
      LAYER M4 ;
        RECT  0 37.152 0.192 37.176 ;
    END
  END ph1[3]
  PIN ph1[4]
    DIRECTION INPUT ;
    USE SIGNAL ;
    PORT
      LAYER M4 ;
        RECT  0 37.008 0.192 37.032 ;
    END
  END ph1[4]
  PIN ph1[5]
    DIRECTION INPUT ;
    USE SIGNAL ;
    PORT
      LAYER M4 ;
        RECT  0 36.864 0.192 36.888 ;
    END
  END ph1[5]
  PIN pl0[0]
    DIRECTION INPUT ;
    USE SIGNAL ;
    PORT
      LAYER M4 ;
        RECT  0 36.72 0.192 36.744 ;
    END
  END pl0[0]
  PIN pl0[10]
    DIRECTION INPUT ;
    USE SIGNAL ;
    PORT
      LAYER M4 ;
        RECT  0 35.28 0.192 35.304 ;
    END
  END pl0[10]
  PIN pl0[11]
    DIRECTION INPUT ;
    USE SIGNAL ;
    PORT
      LAYER M4 ;
        RECT  0 35.136 0.192 35.16 ;
    END
  END pl0[11]
  PIN pl0[12]
    DIRECTION INPUT ;
    USE SIGNAL ;
    PORT
      LAYER M4 ;
        RECT  0 34.992 0.192 35.016 ;
    END
  END pl0[12]
  PIN pl0[13]
    DIRECTION INPUT ;
    USE SIGNAL ;
    PORT
      LAYER M4 ;
        RECT  0 34.848 0.192 34.872 ;
    END
  END pl0[13]
  PIN pl0[14]
    DIRECTION INPUT ;
    USE SIGNAL ;
    PORT
      LAYER M4 ;
        RECT  0 34.704 0.192 34.728 ;
    END
  END pl0[14]
  PIN pl0[15]
    DIRECTION INPUT ;
    USE SIGNAL ;
    PORT
      LAYER M4 ;
        RECT  0 34.56 0.192 34.584 ;
    END
  END pl0[15]
  PIN pl0[1]
    DIRECTION INPUT ;
    USE SIGNAL ;
    PORT
      LAYER M4 ;
        RECT  0 36.576 0.192 36.6 ;
    END
  END pl0[1]
  PIN pl0[2]
    DIRECTION INPUT ;
    USE SIGNAL ;
    PORT
      LAYER M4 ;
        RECT  0 36.432 0.192 36.456 ;
    END
  END pl0[2]
  PIN pl0[3]
    DIRECTION INPUT ;
    USE SIGNAL ;
    PORT
      LAYER M4 ;
        RECT  0 36.288 0.192 36.312 ;
    END
  END pl0[3]
  PIN pl0[4]
    DIRECTION INPUT ;
    USE SIGNAL ;
    PORT
      LAYER M4 ;
        RECT  0 36.144 0.192 36.168 ;
    END
  END pl0[4]
  PIN pl0[5]
    DIRECTION INPUT ;
    USE SIGNAL ;
    PORT
      LAYER M4 ;
        RECT  0 36 0.192 36.024 ;
    END
  END pl0[5]
  PIN pl0[6]
    DIRECTION INPUT ;
    USE SIGNAL ;
    PORT
      LAYER M4 ;
        RECT  0 35.856 0.192 35.88 ;
    END
  END pl0[6]
  PIN pl0[7]
    DIRECTION INPUT ;
    USE SIGNAL ;
    PORT
      LAYER M4 ;
        RECT  0 35.712 0.192 35.736 ;
    END
  END pl0[7]
  PIN pl0[8]
    DIRECTION INPUT ;
    USE SIGNAL ;
    PORT
      LAYER M4 ;
        RECT  0 35.568 0.192 35.592 ;
    END
  END pl0[8]
  PIN pl0[9]
    DIRECTION INPUT ;
    USE SIGNAL ;
    PORT
      LAYER M4 ;
        RECT  0 35.424 0.192 35.448 ;
    END
  END pl0[9]
  PIN pl1[0]
    DIRECTION INPUT ;
    USE SIGNAL ;
    PORT
      LAYER M4 ;
        RECT  0 34.416 0.192 34.44 ;
    END
  END pl1[0]
  PIN pl1[10]
    DIRECTION INPUT ;
    USE SIGNAL ;
    PORT
      LAYER M4 ;
        RECT  0 32.976 0.192 33 ;
    END
  END pl1[10]
  PIN pl1[11]
    DIRECTION INPUT ;
    USE SIGNAL ;
    PORT
      LAYER M4 ;
        RECT  0 32.832 0.192 32.856 ;
    END
  END pl1[11]
  PIN pl1[12]
    DIRECTION INPUT ;
    USE SIGNAL ;
    PORT
      LAYER M4 ;
        RECT  0 32.688 0.192 32.712 ;
    END
  END pl1[12]
  PIN pl1[13]
    DIRECTION INPUT ;
    USE SIGNAL ;
    PORT
      LAYER M4 ;
        RECT  0 32.544 0.192 32.568 ;
    END
  END pl1[13]
  PIN pl1[14]
    DIRECTION INPUT ;
    USE SIGNAL ;
    PORT
      LAYER M4 ;
        RECT  0 32.4 0.192 32.424 ;
    END
  END pl1[14]
  PIN pl1[15]
    DIRECTION INPUT ;
    USE SIGNAL ;
    PORT
      LAYER M4 ;
        RECT  0 32.256 0.192 32.28 ;
    END
  END pl1[15]
  PIN pl1[1]
    DIRECTION INPUT ;
    USE SIGNAL ;
    PORT
      LAYER M4 ;
        RECT  0 34.272 0.192 34.296 ;
    END
  END pl1[1]
  PIN pl1[2]
    DIRECTION INPUT ;
    USE SIGNAL ;
    PORT
      LAYER M4 ;
        RECT  0 34.128 0.192 34.152 ;
    END
  END pl1[2]
  PIN pl1[3]
    DIRECTION INPUT ;
    USE SIGNAL ;
    PORT
      LAYER M4 ;
        RECT  0 33.984 0.192 34.008 ;
    END
  END pl1[3]
  PIN pl1[4]
    DIRECTION INPUT ;
    USE SIGNAL ;
    PORT
      LAYER M4 ;
        RECT  0 33.84 0.192 33.864 ;
    END
  END pl1[4]
  PIN pl1[5]
    DIRECTION INPUT ;
    USE SIGNAL ;
    PORT
      LAYER M4 ;
        RECT  0 33.696 0.192 33.72 ;
    END
  END pl1[5]
  PIN pl1[6]
    DIRECTION INPUT ;
    USE SIGNAL ;
    PORT
      LAYER M4 ;
        RECT  0 33.552 0.192 33.576 ;
    END
  END pl1[6]
  PIN pl1[7]
    DIRECTION INPUT ;
    USE SIGNAL ;
    PORT
      LAYER M4 ;
        RECT  0 33.408 0.192 33.432 ;
    END
  END pl1[7]
  PIN pl1[8]
    DIRECTION INPUT ;
    USE SIGNAL ;
    PORT
      LAYER M4 ;
        RECT  0 33.264 0.192 33.288 ;
    END
  END pl1[8]
  PIN pl1[9]
    DIRECTION INPUT ;
    USE SIGNAL ;
    PORT
      LAYER M4 ;
        RECT  0 33.12 0.192 33.144 ;
    END
  END pl1[9]
  PIN rd[0]
    DIRECTION OUTPUT ;
    USE SIGNAL ;
    PORT
      LAYER M3 ;
        RECT  24.48 86.256 24.498 86.4 ;
    END
  END rd[0]
  PIN rd[100]
    DIRECTION OUTPUT ;
    USE SIGNAL ;
    PORT
      LAYER M3 ;
        RECT  31.68 86.256 31.698 86.4 ;
    END
  END rd[100]
  PIN rd[101]
    DIRECTION OUTPUT ;
    USE SIGNAL ;
    PORT
      LAYER M5 ;
        RECT  31.728 86.208 31.752 86.4 ;
    END
  END rd[101]
  PIN rd[102]
    DIRECTION OUTPUT ;
    USE SIGNAL ;
    PORT
      LAYER M3 ;
        RECT  31.824 86.256 31.842 86.4 ;
    END
  END rd[102]
  PIN rd[103]
    DIRECTION OUTPUT ;
    USE SIGNAL ;
    PORT
      LAYER M5 ;
        RECT  31.872 86.208 31.896 86.4 ;
    END
  END rd[103]
  PIN rd[104]
    DIRECTION OUTPUT ;
    USE SIGNAL ;
    PORT
      LAYER M3 ;
        RECT  31.968 86.256 31.986 86.4 ;
    END
  END rd[104]
  PIN rd[105]
    DIRECTION OUTPUT ;
    USE SIGNAL ;
    PORT
      LAYER M5 ;
        RECT  32.016 86.208 32.04 86.4 ;
    END
  END rd[105]
  PIN rd[106]
    DIRECTION OUTPUT ;
    USE SIGNAL ;
    PORT
      LAYER M3 ;
        RECT  32.112 86.256 32.13 86.4 ;
    END
  END rd[106]
  PIN rd[107]
    DIRECTION OUTPUT ;
    USE SIGNAL ;
    PORT
      LAYER M5 ;
        RECT  32.16 86.208 32.184 86.4 ;
    END
  END rd[107]
  PIN rd[108]
    DIRECTION OUTPUT ;
    USE SIGNAL ;
    PORT
      LAYER M3 ;
        RECT  32.256 86.256 32.274 86.4 ;
    END
  END rd[108]
  PIN rd[109]
    DIRECTION OUTPUT ;
    USE SIGNAL ;
    PORT
      LAYER M5 ;
        RECT  32.304 86.208 32.328 86.4 ;
    END
  END rd[109]
  PIN rd[10]
    DIRECTION OUTPUT ;
    USE SIGNAL ;
    PORT
      LAYER M3 ;
        RECT  25.2 86.256 25.218 86.4 ;
    END
  END rd[10]
  PIN rd[110]
    DIRECTION OUTPUT ;
    USE SIGNAL ;
    PORT
      LAYER M3 ;
        RECT  32.4 86.256 32.418 86.4 ;
    END
  END rd[110]
  PIN rd[111]
    DIRECTION OUTPUT ;
    USE SIGNAL ;
    PORT
      LAYER M5 ;
        RECT  32.448 86.208 32.472 86.4 ;
    END
  END rd[111]
  PIN rd[112]
    DIRECTION OUTPUT ;
    USE SIGNAL ;
    PORT
      LAYER M3 ;
        RECT  32.544 86.256 32.562 86.4 ;
    END
  END rd[112]
  PIN rd[113]
    DIRECTION OUTPUT ;
    USE SIGNAL ;
    PORT
      LAYER M5 ;
        RECT  32.592 86.208 32.616 86.4 ;
    END
  END rd[113]
  PIN rd[114]
    DIRECTION OUTPUT ;
    USE SIGNAL ;
    PORT
      LAYER M3 ;
        RECT  32.688 86.256 32.706 86.4 ;
    END
  END rd[114]
  PIN rd[115]
    DIRECTION OUTPUT ;
    USE SIGNAL ;
    PORT
      LAYER M5 ;
        RECT  32.736 86.208 32.76 86.4 ;
    END
  END rd[115]
  PIN rd[116]
    DIRECTION OUTPUT ;
    USE SIGNAL ;
    PORT
      LAYER M3 ;
        RECT  32.832 86.256 32.85 86.4 ;
    END
  END rd[116]
  PIN rd[117]
    DIRECTION OUTPUT ;
    USE SIGNAL ;
    PORT
      LAYER M5 ;
        RECT  32.88 86.208 32.904 86.4 ;
    END
  END rd[117]
  PIN rd[118]
    DIRECTION OUTPUT ;
    USE SIGNAL ;
    PORT
      LAYER M3 ;
        RECT  32.976 86.256 32.994 86.4 ;
    END
  END rd[118]
  PIN rd[119]
    DIRECTION OUTPUT ;
    USE SIGNAL ;
    PORT
      LAYER M5 ;
        RECT  33.024 86.208 33.048 86.4 ;
    END
  END rd[119]
  PIN rd[11]
    DIRECTION OUTPUT ;
    USE SIGNAL ;
    PORT
      LAYER M5 ;
        RECT  25.248 86.208 25.272 86.4 ;
    END
  END rd[11]
  PIN rd[120]
    DIRECTION OUTPUT ;
    USE SIGNAL ;
    PORT
      LAYER M3 ;
        RECT  33.12 86.256 33.138 86.4 ;
    END
  END rd[120]
  PIN rd[121]
    DIRECTION OUTPUT ;
    USE SIGNAL ;
    PORT
      LAYER M5 ;
        RECT  33.168 86.208 33.192 86.4 ;
    END
  END rd[121]
  PIN rd[122]
    DIRECTION OUTPUT ;
    USE SIGNAL ;
    PORT
      LAYER M3 ;
        RECT  33.264 86.256 33.282 86.4 ;
    END
  END rd[122]
  PIN rd[123]
    DIRECTION OUTPUT ;
    USE SIGNAL ;
    PORT
      LAYER M5 ;
        RECT  33.312 86.208 33.336 86.4 ;
    END
  END rd[123]
  PIN rd[124]
    DIRECTION OUTPUT ;
    USE SIGNAL ;
    PORT
      LAYER M3 ;
        RECT  33.408 86.256 33.426 86.4 ;
    END
  END rd[124]
  PIN rd[125]
    DIRECTION OUTPUT ;
    USE SIGNAL ;
    PORT
      LAYER M5 ;
        RECT  33.456 86.208 33.48 86.4 ;
    END
  END rd[125]
  PIN rd[126]
    DIRECTION OUTPUT ;
    USE SIGNAL ;
    PORT
      LAYER M3 ;
        RECT  33.552 86.256 33.57 86.4 ;
    END
  END rd[126]
  PIN rd[127]
    DIRECTION OUTPUT ;
    USE SIGNAL ;
    PORT
      LAYER M5 ;
        RECT  33.6 86.208 33.624 86.4 ;
    END
  END rd[127]
  PIN rd[128]
    DIRECTION OUTPUT ;
    USE SIGNAL ;
    PORT
      LAYER M3 ;
        RECT  33.696 86.256 33.714 86.4 ;
    END
  END rd[128]
  PIN rd[129]
    DIRECTION OUTPUT ;
    USE SIGNAL ;
    PORT
      LAYER M5 ;
        RECT  33.744 86.208 33.768 86.4 ;
    END
  END rd[129]
  PIN rd[12]
    DIRECTION OUTPUT ;
    USE SIGNAL ;
    PORT
      LAYER M3 ;
        RECT  25.344 86.256 25.362 86.4 ;
    END
  END rd[12]
  PIN rd[130]
    DIRECTION OUTPUT ;
    USE SIGNAL ;
    PORT
      LAYER M3 ;
        RECT  33.84 86.256 33.858 86.4 ;
    END
  END rd[130]
  PIN rd[131]
    DIRECTION OUTPUT ;
    USE SIGNAL ;
    PORT
      LAYER M5 ;
        RECT  33.888 86.208 33.912 86.4 ;
    END
  END rd[131]
  PIN rd[132]
    DIRECTION OUTPUT ;
    USE SIGNAL ;
    PORT
      LAYER M3 ;
        RECT  33.984 86.256 34.002 86.4 ;
    END
  END rd[132]
  PIN rd[133]
    DIRECTION OUTPUT ;
    USE SIGNAL ;
    PORT
      LAYER M5 ;
        RECT  34.032 86.208 34.056 86.4 ;
    END
  END rd[133]
  PIN rd[134]
    DIRECTION OUTPUT ;
    USE SIGNAL ;
    PORT
      LAYER M3 ;
        RECT  34.128 86.256 34.146 86.4 ;
    END
  END rd[134]
  PIN rd[135]
    DIRECTION OUTPUT ;
    USE SIGNAL ;
    PORT
      LAYER M5 ;
        RECT  34.176 86.208 34.2 86.4 ;
    END
  END rd[135]
  PIN rd[136]
    DIRECTION OUTPUT ;
    USE SIGNAL ;
    PORT
      LAYER M3 ;
        RECT  34.272 86.256 34.29 86.4 ;
    END
  END rd[136]
  PIN rd[137]
    DIRECTION OUTPUT ;
    USE SIGNAL ;
    PORT
      LAYER M5 ;
        RECT  34.32 86.208 34.344 86.4 ;
    END
  END rd[137]
  PIN rd[138]
    DIRECTION OUTPUT ;
    USE SIGNAL ;
    PORT
      LAYER M3 ;
        RECT  34.416 86.256 34.434 86.4 ;
    END
  END rd[138]
  PIN rd[139]
    DIRECTION OUTPUT ;
    USE SIGNAL ;
    PORT
      LAYER M5 ;
        RECT  34.464 86.208 34.488 86.4 ;
    END
  END rd[139]
  PIN rd[13]
    DIRECTION OUTPUT ;
    USE SIGNAL ;
    PORT
      LAYER M5 ;
        RECT  25.392 86.208 25.416 86.4 ;
    END
  END rd[13]
  PIN rd[140]
    DIRECTION OUTPUT ;
    USE SIGNAL ;
    PORT
      LAYER M3 ;
        RECT  34.56 86.256 34.578 86.4 ;
    END
  END rd[140]
  PIN rd[141]
    DIRECTION OUTPUT ;
    USE SIGNAL ;
    PORT
      LAYER M5 ;
        RECT  34.608 86.208 34.632 86.4 ;
    END
  END rd[141]
  PIN rd[142]
    DIRECTION OUTPUT ;
    USE SIGNAL ;
    PORT
      LAYER M3 ;
        RECT  34.704 86.256 34.722 86.4 ;
    END
  END rd[142]
  PIN rd[143]
    DIRECTION OUTPUT ;
    USE SIGNAL ;
    PORT
      LAYER M5 ;
        RECT  34.752 86.208 34.776 86.4 ;
    END
  END rd[143]
  PIN rd[144]
    DIRECTION OUTPUT ;
    USE SIGNAL ;
    PORT
      LAYER M3 ;
        RECT  34.848 86.256 34.866 86.4 ;
    END
  END rd[144]
  PIN rd[145]
    DIRECTION OUTPUT ;
    USE SIGNAL ;
    PORT
      LAYER M5 ;
        RECT  34.896 86.208 34.92 86.4 ;
    END
  END rd[145]
  PIN rd[146]
    DIRECTION OUTPUT ;
    USE SIGNAL ;
    PORT
      LAYER M3 ;
        RECT  34.992 86.256 35.01 86.4 ;
    END
  END rd[146]
  PIN rd[147]
    DIRECTION OUTPUT ;
    USE SIGNAL ;
    PORT
      LAYER M5 ;
        RECT  35.04 86.208 35.064 86.4 ;
    END
  END rd[147]
  PIN rd[148]
    DIRECTION OUTPUT ;
    USE SIGNAL ;
    PORT
      LAYER M3 ;
        RECT  35.136 86.256 35.154 86.4 ;
    END
  END rd[148]
  PIN rd[149]
    DIRECTION OUTPUT ;
    USE SIGNAL ;
    PORT
      LAYER M5 ;
        RECT  35.184 86.208 35.208 86.4 ;
    END
  END rd[149]
  PIN rd[14]
    DIRECTION OUTPUT ;
    USE SIGNAL ;
    PORT
      LAYER M3 ;
        RECT  25.488 86.256 25.506 86.4 ;
    END
  END rd[14]
  PIN rd[150]
    DIRECTION OUTPUT ;
    USE SIGNAL ;
    PORT
      LAYER M3 ;
        RECT  35.28 86.256 35.298 86.4 ;
    END
  END rd[150]
  PIN rd[151]
    DIRECTION OUTPUT ;
    USE SIGNAL ;
    PORT
      LAYER M5 ;
        RECT  35.328 86.208 35.352 86.4 ;
    END
  END rd[151]
  PIN rd[152]
    DIRECTION OUTPUT ;
    USE SIGNAL ;
    PORT
      LAYER M3 ;
        RECT  35.424 86.256 35.442 86.4 ;
    END
  END rd[152]
  PIN rd[153]
    DIRECTION OUTPUT ;
    USE SIGNAL ;
    PORT
      LAYER M5 ;
        RECT  35.472 86.208 35.496 86.4 ;
    END
  END rd[153]
  PIN rd[154]
    DIRECTION OUTPUT ;
    USE SIGNAL ;
    PORT
      LAYER M3 ;
        RECT  35.568 86.256 35.586 86.4 ;
    END
  END rd[154]
  PIN rd[155]
    DIRECTION OUTPUT ;
    USE SIGNAL ;
    PORT
      LAYER M5 ;
        RECT  35.616 86.208 35.64 86.4 ;
    END
  END rd[155]
  PIN rd[156]
    DIRECTION OUTPUT ;
    USE SIGNAL ;
    PORT
      LAYER M3 ;
        RECT  35.712 86.256 35.73 86.4 ;
    END
  END rd[156]
  PIN rd[157]
    DIRECTION OUTPUT ;
    USE SIGNAL ;
    PORT
      LAYER M5 ;
        RECT  35.76 86.208 35.784 86.4 ;
    END
  END rd[157]
  PIN rd[158]
    DIRECTION OUTPUT ;
    USE SIGNAL ;
    PORT
      LAYER M3 ;
        RECT  35.856 86.256 35.874 86.4 ;
    END
  END rd[158]
  PIN rd[159]
    DIRECTION OUTPUT ;
    USE SIGNAL ;
    PORT
      LAYER M5 ;
        RECT  35.904 86.208 35.928 86.4 ;
    END
  END rd[159]
  PIN rd[15]
    DIRECTION OUTPUT ;
    USE SIGNAL ;
    PORT
      LAYER M5 ;
        RECT  25.536 86.208 25.56 86.4 ;
    END
  END rd[15]
  PIN rd[160]
    DIRECTION OUTPUT ;
    USE SIGNAL ;
    PORT
      LAYER M3 ;
        RECT  36 86.256 36.018 86.4 ;
    END
  END rd[160]
  PIN rd[161]
    DIRECTION OUTPUT ;
    USE SIGNAL ;
    PORT
      LAYER M5 ;
        RECT  36.048 86.208 36.072 86.4 ;
    END
  END rd[161]
  PIN rd[162]
    DIRECTION OUTPUT ;
    USE SIGNAL ;
    PORT
      LAYER M3 ;
        RECT  36.144 86.256 36.162 86.4 ;
    END
  END rd[162]
  PIN rd[163]
    DIRECTION OUTPUT ;
    USE SIGNAL ;
    PORT
      LAYER M5 ;
        RECT  36.192 86.208 36.216 86.4 ;
    END
  END rd[163]
  PIN rd[164]
    DIRECTION OUTPUT ;
    USE SIGNAL ;
    PORT
      LAYER M3 ;
        RECT  36.288 86.256 36.306 86.4 ;
    END
  END rd[164]
  PIN rd[165]
    DIRECTION OUTPUT ;
    USE SIGNAL ;
    PORT
      LAYER M5 ;
        RECT  36.336 86.208 36.36 86.4 ;
    END
  END rd[165]
  PIN rd[166]
    DIRECTION OUTPUT ;
    USE SIGNAL ;
    PORT
      LAYER M3 ;
        RECT  36.432 86.256 36.45 86.4 ;
    END
  END rd[166]
  PIN rd[167]
    DIRECTION OUTPUT ;
    USE SIGNAL ;
    PORT
      LAYER M5 ;
        RECT  36.48 86.208 36.504 86.4 ;
    END
  END rd[167]
  PIN rd[168]
    DIRECTION OUTPUT ;
    USE SIGNAL ;
    PORT
      LAYER M3 ;
        RECT  36.576 86.256 36.594 86.4 ;
    END
  END rd[168]
  PIN rd[169]
    DIRECTION OUTPUT ;
    USE SIGNAL ;
    PORT
      LAYER M5 ;
        RECT  36.624 86.208 36.648 86.4 ;
    END
  END rd[169]
  PIN rd[16]
    DIRECTION OUTPUT ;
    USE SIGNAL ;
    PORT
      LAYER M3 ;
        RECT  25.632 86.256 25.65 86.4 ;
    END
  END rd[16]
  PIN rd[170]
    DIRECTION OUTPUT ;
    USE SIGNAL ;
    PORT
      LAYER M3 ;
        RECT  36.72 86.256 36.738 86.4 ;
    END
  END rd[170]
  PIN rd[171]
    DIRECTION OUTPUT ;
    USE SIGNAL ;
    PORT
      LAYER M5 ;
        RECT  36.768 86.208 36.792 86.4 ;
    END
  END rd[171]
  PIN rd[172]
    DIRECTION OUTPUT ;
    USE SIGNAL ;
    PORT
      LAYER M3 ;
        RECT  36.864 86.256 36.882 86.4 ;
    END
  END rd[172]
  PIN rd[173]
    DIRECTION OUTPUT ;
    USE SIGNAL ;
    PORT
      LAYER M5 ;
        RECT  36.912 86.208 36.936 86.4 ;
    END
  END rd[173]
  PIN rd[174]
    DIRECTION OUTPUT ;
    USE SIGNAL ;
    PORT
      LAYER M3 ;
        RECT  37.008 86.256 37.026 86.4 ;
    END
  END rd[174]
  PIN rd[175]
    DIRECTION OUTPUT ;
    USE SIGNAL ;
    PORT
      LAYER M5 ;
        RECT  37.056 86.208 37.08 86.4 ;
    END
  END rd[175]
  PIN rd[176]
    DIRECTION OUTPUT ;
    USE SIGNAL ;
    PORT
      LAYER M3 ;
        RECT  37.152 86.256 37.17 86.4 ;
    END
  END rd[176]
  PIN rd[177]
    DIRECTION OUTPUT ;
    USE SIGNAL ;
    PORT
      LAYER M5 ;
        RECT  37.2 86.208 37.224 86.4 ;
    END
  END rd[177]
  PIN rd[178]
    DIRECTION OUTPUT ;
    USE SIGNAL ;
    PORT
      LAYER M3 ;
        RECT  37.296 86.256 37.314 86.4 ;
    END
  END rd[178]
  PIN rd[179]
    DIRECTION OUTPUT ;
    USE SIGNAL ;
    PORT
      LAYER M5 ;
        RECT  37.344 86.208 37.368 86.4 ;
    END
  END rd[179]
  PIN rd[17]
    DIRECTION OUTPUT ;
    USE SIGNAL ;
    PORT
      LAYER M5 ;
        RECT  25.68 86.208 25.704 86.4 ;
    END
  END rd[17]
  PIN rd[180]
    DIRECTION OUTPUT ;
    USE SIGNAL ;
    PORT
      LAYER M3 ;
        RECT  37.44 86.256 37.458 86.4 ;
    END
  END rd[180]
  PIN rd[181]
    DIRECTION OUTPUT ;
    USE SIGNAL ;
    PORT
      LAYER M5 ;
        RECT  37.488 86.208 37.512 86.4 ;
    END
  END rd[181]
  PIN rd[182]
    DIRECTION OUTPUT ;
    USE SIGNAL ;
    PORT
      LAYER M3 ;
        RECT  37.584 86.256 37.602 86.4 ;
    END
  END rd[182]
  PIN rd[183]
    DIRECTION OUTPUT ;
    USE SIGNAL ;
    PORT
      LAYER M5 ;
        RECT  37.632 86.208 37.656 86.4 ;
    END
  END rd[183]
  PIN rd[184]
    DIRECTION OUTPUT ;
    USE SIGNAL ;
    PORT
      LAYER M3 ;
        RECT  37.728 86.256 37.746 86.4 ;
    END
  END rd[184]
  PIN rd[185]
    DIRECTION OUTPUT ;
    USE SIGNAL ;
    PORT
      LAYER M5 ;
        RECT  37.776 86.208 37.8 86.4 ;
    END
  END rd[185]
  PIN rd[186]
    DIRECTION OUTPUT ;
    USE SIGNAL ;
    PORT
      LAYER M3 ;
        RECT  37.872 86.256 37.89 86.4 ;
    END
  END rd[186]
  PIN rd[187]
    DIRECTION OUTPUT ;
    USE SIGNAL ;
    PORT
      LAYER M5 ;
        RECT  37.92 86.208 37.944 86.4 ;
    END
  END rd[187]
  PIN rd[188]
    DIRECTION OUTPUT ;
    USE SIGNAL ;
    PORT
      LAYER M3 ;
        RECT  38.016 86.256 38.034 86.4 ;
    END
  END rd[188]
  PIN rd[189]
    DIRECTION OUTPUT ;
    USE SIGNAL ;
    PORT
      LAYER M5 ;
        RECT  38.064 86.208 38.088 86.4 ;
    END
  END rd[189]
  PIN rd[18]
    DIRECTION OUTPUT ;
    USE SIGNAL ;
    PORT
      LAYER M3 ;
        RECT  25.776 86.256 25.794 86.4 ;
    END
  END rd[18]
  PIN rd[190]
    DIRECTION OUTPUT ;
    USE SIGNAL ;
    PORT
      LAYER M3 ;
        RECT  38.16 86.256 38.178 86.4 ;
    END
  END rd[190]
  PIN rd[191]
    DIRECTION OUTPUT ;
    USE SIGNAL ;
    PORT
      LAYER M5 ;
        RECT  38.208 86.208 38.232 86.4 ;
    END
  END rd[191]
  PIN rd[192]
    DIRECTION OUTPUT ;
    USE SIGNAL ;
    PORT
      LAYER M3 ;
        RECT  38.304 86.256 38.322 86.4 ;
    END
  END rd[192]
  PIN rd[193]
    DIRECTION OUTPUT ;
    USE SIGNAL ;
    PORT
      LAYER M5 ;
        RECT  38.352 86.208 38.376 86.4 ;
    END
  END rd[193]
  PIN rd[194]
    DIRECTION OUTPUT ;
    USE SIGNAL ;
    PORT
      LAYER M3 ;
        RECT  38.448 86.256 38.466 86.4 ;
    END
  END rd[194]
  PIN rd[195]
    DIRECTION OUTPUT ;
    USE SIGNAL ;
    PORT
      LAYER M5 ;
        RECT  38.496 86.208 38.52 86.4 ;
    END
  END rd[195]
  PIN rd[196]
    DIRECTION OUTPUT ;
    USE SIGNAL ;
    PORT
      LAYER M3 ;
        RECT  38.592 86.256 38.61 86.4 ;
    END
  END rd[196]
  PIN rd[197]
    DIRECTION OUTPUT ;
    USE SIGNAL ;
    PORT
      LAYER M5 ;
        RECT  38.64 86.208 38.664 86.4 ;
    END
  END rd[197]
  PIN rd[198]
    DIRECTION OUTPUT ;
    USE SIGNAL ;
    PORT
      LAYER M3 ;
        RECT  38.736 86.256 38.754 86.4 ;
    END
  END rd[198]
  PIN rd[199]
    DIRECTION OUTPUT ;
    USE SIGNAL ;
    PORT
      LAYER M5 ;
        RECT  38.784 86.208 38.808 86.4 ;
    END
  END rd[199]
  PIN rd[19]
    DIRECTION OUTPUT ;
    USE SIGNAL ;
    PORT
      LAYER M5 ;
        RECT  25.824 86.208 25.848 86.4 ;
    END
  END rd[19]
  PIN rd[1]
    DIRECTION OUTPUT ;
    USE SIGNAL ;
    PORT
      LAYER M5 ;
        RECT  24.528 86.208 24.552 86.4 ;
    END
  END rd[1]
  PIN rd[200]
    DIRECTION OUTPUT ;
    USE SIGNAL ;
    PORT
      LAYER M3 ;
        RECT  38.88 86.256 38.898 86.4 ;
    END
  END rd[200]
  PIN rd[201]
    DIRECTION OUTPUT ;
    USE SIGNAL ;
    PORT
      LAYER M5 ;
        RECT  38.928 86.208 38.952 86.4 ;
    END
  END rd[201]
  PIN rd[202]
    DIRECTION OUTPUT ;
    USE SIGNAL ;
    PORT
      LAYER M3 ;
        RECT  39.024 86.256 39.042 86.4 ;
    END
  END rd[202]
  PIN rd[203]
    DIRECTION OUTPUT ;
    USE SIGNAL ;
    PORT
      LAYER M5 ;
        RECT  39.072 86.208 39.096 86.4 ;
    END
  END rd[203]
  PIN rd[204]
    DIRECTION OUTPUT ;
    USE SIGNAL ;
    PORT
      LAYER M3 ;
        RECT  39.168 86.256 39.186 86.4 ;
    END
  END rd[204]
  PIN rd[205]
    DIRECTION OUTPUT ;
    USE SIGNAL ;
    PORT
      LAYER M5 ;
        RECT  39.216 86.208 39.24 86.4 ;
    END
  END rd[205]
  PIN rd[206]
    DIRECTION OUTPUT ;
    USE SIGNAL ;
    PORT
      LAYER M3 ;
        RECT  39.312 86.256 39.33 86.4 ;
    END
  END rd[206]
  PIN rd[207]
    DIRECTION OUTPUT ;
    USE SIGNAL ;
    PORT
      LAYER M5 ;
        RECT  39.36 86.208 39.384 86.4 ;
    END
  END rd[207]
  PIN rd[208]
    DIRECTION OUTPUT ;
    USE SIGNAL ;
    PORT
      LAYER M3 ;
        RECT  39.456 86.256 39.474 86.4 ;
    END
  END rd[208]
  PIN rd[209]
    DIRECTION OUTPUT ;
    USE SIGNAL ;
    PORT
      LAYER M5 ;
        RECT  39.504 86.208 39.528 86.4 ;
    END
  END rd[209]
  PIN rd[20]
    DIRECTION OUTPUT ;
    USE SIGNAL ;
    PORT
      LAYER M3 ;
        RECT  25.92 86.256 25.938 86.4 ;
    END
  END rd[20]
  PIN rd[210]
    DIRECTION OUTPUT ;
    USE SIGNAL ;
    PORT
      LAYER M3 ;
        RECT  39.6 86.256 39.618 86.4 ;
    END
  END rd[210]
  PIN rd[211]
    DIRECTION OUTPUT ;
    USE SIGNAL ;
    PORT
      LAYER M5 ;
        RECT  39.648 86.208 39.672 86.4 ;
    END
  END rd[211]
  PIN rd[212]
    DIRECTION OUTPUT ;
    USE SIGNAL ;
    PORT
      LAYER M3 ;
        RECT  39.744 86.256 39.762 86.4 ;
    END
  END rd[212]
  PIN rd[213]
    DIRECTION OUTPUT ;
    USE SIGNAL ;
    PORT
      LAYER M5 ;
        RECT  39.792 86.208 39.816 86.4 ;
    END
  END rd[213]
  PIN rd[214]
    DIRECTION OUTPUT ;
    USE SIGNAL ;
    PORT
      LAYER M3 ;
        RECT  39.888 86.256 39.906 86.4 ;
    END
  END rd[214]
  PIN rd[215]
    DIRECTION OUTPUT ;
    USE SIGNAL ;
    PORT
      LAYER M5 ;
        RECT  39.936 86.208 39.96 86.4 ;
    END
  END rd[215]
  PIN rd[216]
    DIRECTION OUTPUT ;
    USE SIGNAL ;
    PORT
      LAYER M3 ;
        RECT  40.032 86.256 40.05 86.4 ;
    END
  END rd[216]
  PIN rd[217]
    DIRECTION OUTPUT ;
    USE SIGNAL ;
    PORT
      LAYER M5 ;
        RECT  40.08 86.208 40.104 86.4 ;
    END
  END rd[217]
  PIN rd[218]
    DIRECTION OUTPUT ;
    USE SIGNAL ;
    PORT
      LAYER M3 ;
        RECT  40.176 86.256 40.194 86.4 ;
    END
  END rd[218]
  PIN rd[219]
    DIRECTION OUTPUT ;
    USE SIGNAL ;
    PORT
      LAYER M5 ;
        RECT  40.224 86.208 40.248 86.4 ;
    END
  END rd[219]
  PIN rd[21]
    DIRECTION OUTPUT ;
    USE SIGNAL ;
    PORT
      LAYER M5 ;
        RECT  25.968 86.208 25.992 86.4 ;
    END
  END rd[21]
  PIN rd[220]
    DIRECTION OUTPUT ;
    USE SIGNAL ;
    PORT
      LAYER M3 ;
        RECT  40.32 86.256 40.338 86.4 ;
    END
  END rd[220]
  PIN rd[221]
    DIRECTION OUTPUT ;
    USE SIGNAL ;
    PORT
      LAYER M5 ;
        RECT  40.368 86.208 40.392 86.4 ;
    END
  END rd[221]
  PIN rd[222]
    DIRECTION OUTPUT ;
    USE SIGNAL ;
    PORT
      LAYER M3 ;
        RECT  40.464 86.256 40.482 86.4 ;
    END
  END rd[222]
  PIN rd[223]
    DIRECTION OUTPUT ;
    USE SIGNAL ;
    PORT
      LAYER M5 ;
        RECT  40.512 86.208 40.536 86.4 ;
    END
  END rd[223]
  PIN rd[224]
    DIRECTION OUTPUT ;
    USE SIGNAL ;
    PORT
      LAYER M3 ;
        RECT  40.608 86.256 40.626 86.4 ;
    END
  END rd[224]
  PIN rd[225]
    DIRECTION OUTPUT ;
    USE SIGNAL ;
    PORT
      LAYER M5 ;
        RECT  40.656 86.208 40.68 86.4 ;
    END
  END rd[225]
  PIN rd[226]
    DIRECTION OUTPUT ;
    USE SIGNAL ;
    PORT
      LAYER M3 ;
        RECT  40.752 86.256 40.77 86.4 ;
    END
  END rd[226]
  PIN rd[227]
    DIRECTION OUTPUT ;
    USE SIGNAL ;
    PORT
      LAYER M5 ;
        RECT  40.8 86.208 40.824 86.4 ;
    END
  END rd[227]
  PIN rd[228]
    DIRECTION OUTPUT ;
    USE SIGNAL ;
    PORT
      LAYER M3 ;
        RECT  40.896 86.256 40.914 86.4 ;
    END
    PORT
      LAYER M3 ;
        RECT  40.86 86.268 40.986 86.333 ;
    END
  END rd[228]
  PIN rd[229]
    DIRECTION OUTPUT ;
    USE SIGNAL ;
    PORT
      LAYER M5 ;
        RECT  40.944 86.208 40.968 86.4 ;
    END
  END rd[229]
  PIN rd[22]
    DIRECTION OUTPUT ;
    USE SIGNAL ;
    PORT
      LAYER M3 ;
        RECT  26.064 86.256 26.082 86.4 ;
    END
  END rd[22]
  PIN rd[230]
    DIRECTION OUTPUT ;
    USE SIGNAL ;
    PORT
      LAYER M3 ;
        RECT  41.04 86.256 41.058 86.4 ;
    END
  END rd[230]
  PIN rd[231]
    DIRECTION OUTPUT ;
    USE SIGNAL ;
    PORT
      LAYER M5 ;
        RECT  41.088 86.208 41.112 86.4 ;
    END
  END rd[231]
  PIN rd[232]
    DIRECTION OUTPUT ;
    USE SIGNAL ;
    PORT
      LAYER M3 ;
        RECT  41.184 86.256 41.202 86.4 ;
    END
  END rd[232]
  PIN rd[233]
    DIRECTION OUTPUT ;
    USE SIGNAL ;
    PORT
      LAYER M5 ;
        RECT  41.232 86.208 41.256 86.4 ;
    END
  END rd[233]
  PIN rd[234]
    DIRECTION OUTPUT ;
    USE SIGNAL ;
    PORT
      LAYER M3 ;
        RECT  41.328 86.256 41.346 86.4 ;
    END
  END rd[234]
  PIN rd[235]
    DIRECTION OUTPUT ;
    USE SIGNAL ;
    PORT
      LAYER M5 ;
        RECT  41.376 86.208 41.4 86.4 ;
    END
  END rd[235]
  PIN rd[236]
    DIRECTION OUTPUT ;
    USE SIGNAL ;
    PORT
      LAYER M3 ;
        RECT  41.472 86.256 41.49 86.4 ;
    END
  END rd[236]
  PIN rd[237]
    DIRECTION OUTPUT ;
    USE SIGNAL ;
    PORT
      LAYER M5 ;
        RECT  41.52 86.208 41.544 86.4 ;
    END
  END rd[237]
  PIN rd[238]
    DIRECTION OUTPUT ;
    USE SIGNAL ;
    PORT
      LAYER M3 ;
        RECT  41.616 86.256 41.634 86.4 ;
    END
  END rd[238]
  PIN rd[239]
    DIRECTION OUTPUT ;
    USE SIGNAL ;
    PORT
      LAYER M5 ;
        RECT  41.664 86.208 41.688 86.4 ;
    END
  END rd[239]
  PIN rd[23]
    DIRECTION OUTPUT ;
    USE SIGNAL ;
    PORT
      LAYER M5 ;
        RECT  26.112 86.208 26.136 86.4 ;
    END
  END rd[23]
  PIN rd[240]
    DIRECTION OUTPUT ;
    USE SIGNAL ;
    PORT
      LAYER M3 ;
        RECT  41.76 86.256 41.778 86.4 ;
    END
  END rd[240]
  PIN rd[241]
    DIRECTION OUTPUT ;
    USE SIGNAL ;
    PORT
      LAYER M5 ;
        RECT  41.808 86.208 41.832 86.4 ;
    END
  END rd[241]
  PIN rd[242]
    DIRECTION OUTPUT ;
    USE SIGNAL ;
    PORT
      LAYER M3 ;
        RECT  41.904 86.256 41.922 86.4 ;
    END
  END rd[242]
  PIN rd[243]
    DIRECTION OUTPUT ;
    USE SIGNAL ;
    PORT
      LAYER M5 ;
        RECT  41.952 86.208 41.976 86.4 ;
    END
  END rd[243]
  PIN rd[244]
    DIRECTION OUTPUT ;
    USE SIGNAL ;
    PORT
      LAYER M3 ;
        RECT  42.048 86.256 42.066 86.4 ;
    END
  END rd[244]
  PIN rd[245]
    DIRECTION OUTPUT ;
    USE SIGNAL ;
    PORT
      LAYER M5 ;
        RECT  42.096 86.208 42.12 86.4 ;
    END
  END rd[245]
  PIN rd[246]
    DIRECTION OUTPUT ;
    USE SIGNAL ;
    PORT
      LAYER M3 ;
        RECT  42.192 86.256 42.21 86.4 ;
    END
  END rd[246]
  PIN rd[247]
    DIRECTION OUTPUT ;
    USE SIGNAL ;
    PORT
      LAYER M5 ;
        RECT  42.24 86.208 42.264 86.4 ;
    END
  END rd[247]
  PIN rd[248]
    DIRECTION OUTPUT ;
    USE SIGNAL ;
    PORT
      LAYER M3 ;
        RECT  42.336 86.256 42.354 86.4 ;
    END
  END rd[248]
  PIN rd[249]
    DIRECTION OUTPUT ;
    USE SIGNAL ;
    PORT
      LAYER M5 ;
        RECT  42.384 86.208 42.408 86.4 ;
    END
  END rd[249]
  PIN rd[24]
    DIRECTION OUTPUT ;
    USE SIGNAL ;
    PORT
      LAYER M3 ;
        RECT  26.208 86.256 26.226 86.4 ;
    END
  END rd[24]
  PIN rd[250]
    DIRECTION OUTPUT ;
    USE SIGNAL ;
    PORT
      LAYER M3 ;
        RECT  42.48 86.256 42.498 86.4 ;
    END
  END rd[250]
  PIN rd[251]
    DIRECTION OUTPUT ;
    USE SIGNAL ;
    PORT
      LAYER M5 ;
        RECT  42.528 86.208 42.552 86.4 ;
    END
  END rd[251]
  PIN rd[252]
    DIRECTION OUTPUT ;
    USE SIGNAL ;
    PORT
      LAYER M3 ;
        RECT  42.624 86.256 42.642 86.4 ;
    END
  END rd[252]
  PIN rd[253]
    DIRECTION OUTPUT ;
    USE SIGNAL ;
    PORT
      LAYER M5 ;
        RECT  42.672 86.208 42.696 86.4 ;
    END
  END rd[253]
  PIN rd[254]
    DIRECTION OUTPUT ;
    USE SIGNAL ;
    PORT
      LAYER M3 ;
        RECT  42.768 86.256 42.786 86.4 ;
    END
  END rd[254]
  PIN rd[255]
    DIRECTION OUTPUT ;
    USE SIGNAL ;
    PORT
      LAYER M5 ;
        RECT  42.816 86.208 42.84 86.4 ;
    END
  END rd[255]
  PIN rd[25]
    DIRECTION OUTPUT ;
    USE SIGNAL ;
    PORT
      LAYER M5 ;
        RECT  26.256 86.208 26.28 86.4 ;
    END
  END rd[25]
  PIN rd[26]
    DIRECTION OUTPUT ;
    USE SIGNAL ;
    PORT
      LAYER M3 ;
        RECT  26.352 86.256 26.37 86.4 ;
    END
  END rd[26]
  PIN rd[27]
    DIRECTION OUTPUT ;
    USE SIGNAL ;
    PORT
      LAYER M5 ;
        RECT  26.4 86.208 26.424 86.4 ;
    END
  END rd[27]
  PIN rd[28]
    DIRECTION OUTPUT ;
    USE SIGNAL ;
    PORT
      LAYER M3 ;
        RECT  26.496 86.256 26.514 86.4 ;
    END
  END rd[28]
  PIN rd[29]
    DIRECTION OUTPUT ;
    USE SIGNAL ;
    PORT
      LAYER M5 ;
        RECT  26.544 86.208 26.568 86.4 ;
    END
  END rd[29]
  PIN rd[2]
    DIRECTION OUTPUT ;
    USE SIGNAL ;
    PORT
      LAYER M3 ;
        RECT  24.624 86.256 24.642 86.4 ;
    END
  END rd[2]
  PIN rd[30]
    DIRECTION OUTPUT ;
    USE SIGNAL ;
    PORT
      LAYER M3 ;
        RECT  26.64 86.256 26.658 86.4 ;
    END
  END rd[30]
  PIN rd[31]
    DIRECTION OUTPUT ;
    USE SIGNAL ;
    PORT
      LAYER M5 ;
        RECT  26.688 86.208 26.712 86.4 ;
    END
  END rd[31]
  PIN rd[32]
    DIRECTION OUTPUT ;
    USE SIGNAL ;
    PORT
      LAYER M3 ;
        RECT  26.784 86.256 26.802 86.4 ;
    END
  END rd[32]
  PIN rd[33]
    DIRECTION OUTPUT ;
    USE SIGNAL ;
    PORT
      LAYER M5 ;
        RECT  26.832 86.208 26.856 86.4 ;
    END
  END rd[33]
  PIN rd[34]
    DIRECTION OUTPUT ;
    USE SIGNAL ;
    PORT
      LAYER M3 ;
        RECT  26.928 86.256 26.946 86.4 ;
    END
  END rd[34]
  PIN rd[35]
    DIRECTION OUTPUT ;
    USE SIGNAL ;
    PORT
      LAYER M5 ;
        RECT  26.976 86.208 27 86.4 ;
    END
  END rd[35]
  PIN rd[36]
    DIRECTION OUTPUT ;
    USE SIGNAL ;
    PORT
      LAYER M3 ;
        RECT  27.072 86.256 27.09 86.4 ;
    END
  END rd[36]
  PIN rd[37]
    DIRECTION OUTPUT ;
    USE SIGNAL ;
    PORT
      LAYER M5 ;
        RECT  27.12 86.208 27.144 86.4 ;
    END
  END rd[37]
  PIN rd[38]
    DIRECTION OUTPUT ;
    USE SIGNAL ;
    PORT
      LAYER M3 ;
        RECT  27.216 86.256 27.234 86.4 ;
    END
  END rd[38]
  PIN rd[39]
    DIRECTION OUTPUT ;
    USE SIGNAL ;
    PORT
      LAYER M5 ;
        RECT  27.264 86.208 27.288 86.4 ;
    END
  END rd[39]
  PIN rd[3]
    DIRECTION OUTPUT ;
    USE SIGNAL ;
    PORT
      LAYER M5 ;
        RECT  24.672 86.208 24.696 86.4 ;
    END
  END rd[3]
  PIN rd[40]
    DIRECTION OUTPUT ;
    USE SIGNAL ;
    PORT
      LAYER M3 ;
        RECT  27.36 86.256 27.378 86.4 ;
    END
  END rd[40]
  PIN rd[41]
    DIRECTION OUTPUT ;
    USE SIGNAL ;
    PORT
      LAYER M5 ;
        RECT  27.408 86.208 27.432 86.4 ;
    END
  END rd[41]
  PIN rd[42]
    DIRECTION OUTPUT ;
    USE SIGNAL ;
    PORT
      LAYER M3 ;
        RECT  27.504 86.256 27.522 86.4 ;
    END
  END rd[42]
  PIN rd[43]
    DIRECTION OUTPUT ;
    USE SIGNAL ;
    PORT
      LAYER M5 ;
        RECT  27.552 86.208 27.576 86.4 ;
    END
  END rd[43]
  PIN rd[44]
    DIRECTION OUTPUT ;
    USE SIGNAL ;
    PORT
      LAYER M3 ;
        RECT  27.648 86.256 27.666 86.4 ;
    END
  END rd[44]
  PIN rd[45]
    DIRECTION OUTPUT ;
    USE SIGNAL ;
    PORT
      LAYER M5 ;
        RECT  27.696 86.208 27.72 86.4 ;
    END
  END rd[45]
  PIN rd[46]
    DIRECTION OUTPUT ;
    USE SIGNAL ;
    PORT
      LAYER M3 ;
        RECT  27.792 86.256 27.81 86.4 ;
    END
  END rd[46]
  PIN rd[47]
    DIRECTION OUTPUT ;
    USE SIGNAL ;
    PORT
      LAYER M5 ;
        RECT  27.84 86.208 27.864 86.4 ;
    END
  END rd[47]
  PIN rd[48]
    DIRECTION OUTPUT ;
    USE SIGNAL ;
    PORT
      LAYER M3 ;
        RECT  27.936 86.256 27.954 86.4 ;
    END
  END rd[48]
  PIN rd[49]
    DIRECTION OUTPUT ;
    USE SIGNAL ;
    PORT
      LAYER M5 ;
        RECT  27.984 86.208 28.008 86.4 ;
    END
  END rd[49]
  PIN rd[4]
    DIRECTION OUTPUT ;
    USE SIGNAL ;
    PORT
      LAYER M3 ;
        RECT  24.768 86.256 24.786 86.4 ;
    END
  END rd[4]
  PIN rd[50]
    DIRECTION OUTPUT ;
    USE SIGNAL ;
    PORT
      LAYER M3 ;
        RECT  28.08 86.256 28.098 86.4 ;
    END
  END rd[50]
  PIN rd[51]
    DIRECTION OUTPUT ;
    USE SIGNAL ;
    PORT
      LAYER M5 ;
        RECT  28.128 86.208 28.152 86.4 ;
    END
  END rd[51]
  PIN rd[52]
    DIRECTION OUTPUT ;
    USE SIGNAL ;
    PORT
      LAYER M3 ;
        RECT  28.224 86.256 28.242 86.4 ;
    END
  END rd[52]
  PIN rd[53]
    DIRECTION OUTPUT ;
    USE SIGNAL ;
    PORT
      LAYER M5 ;
        RECT  28.272 86.208 28.296 86.4 ;
    END
  END rd[53]
  PIN rd[54]
    DIRECTION OUTPUT ;
    USE SIGNAL ;
    PORT
      LAYER M3 ;
        RECT  28.368 86.256 28.386 86.4 ;
    END
  END rd[54]
  PIN rd[55]
    DIRECTION OUTPUT ;
    USE SIGNAL ;
    PORT
      LAYER M5 ;
        RECT  28.416 86.208 28.44 86.4 ;
    END
  END rd[55]
  PIN rd[56]
    DIRECTION OUTPUT ;
    USE SIGNAL ;
    PORT
      LAYER M3 ;
        RECT  28.512 86.256 28.53 86.4 ;
    END
  END rd[56]
  PIN rd[57]
    DIRECTION OUTPUT ;
    USE SIGNAL ;
    PORT
      LAYER M5 ;
        RECT  28.56 86.208 28.584 86.4 ;
    END
  END rd[57]
  PIN rd[58]
    DIRECTION OUTPUT ;
    USE SIGNAL ;
    PORT
      LAYER M3 ;
        RECT  28.656 86.256 28.674 86.4 ;
    END
  END rd[58]
  PIN rd[59]
    DIRECTION OUTPUT ;
    USE SIGNAL ;
    PORT
      LAYER M5 ;
        RECT  28.704 86.208 28.728 86.4 ;
    END
  END rd[59]
  PIN rd[5]
    DIRECTION OUTPUT ;
    USE SIGNAL ;
    PORT
      LAYER M5 ;
        RECT  24.816 86.208 24.84 86.4 ;
    END
  END rd[5]
  PIN rd[60]
    DIRECTION OUTPUT ;
    USE SIGNAL ;
    PORT
      LAYER M3 ;
        RECT  28.8 86.256 28.818 86.4 ;
    END
  END rd[60]
  PIN rd[61]
    DIRECTION OUTPUT ;
    USE SIGNAL ;
    PORT
      LAYER M5 ;
        RECT  28.848 86.208 28.872 86.4 ;
    END
  END rd[61]
  PIN rd[62]
    DIRECTION OUTPUT ;
    USE SIGNAL ;
    PORT
      LAYER M3 ;
        RECT  28.944 86.256 28.962 86.4 ;
    END
  END rd[62]
  PIN rd[63]
    DIRECTION OUTPUT ;
    USE SIGNAL ;
    PORT
      LAYER M5 ;
        RECT  28.992 86.208 29.016 86.4 ;
    END
  END rd[63]
  PIN rd[64]
    DIRECTION OUTPUT ;
    USE SIGNAL ;
    PORT
      LAYER M3 ;
        RECT  29.088 86.256 29.106 86.4 ;
    END
  END rd[64]
  PIN rd[65]
    DIRECTION OUTPUT ;
    USE SIGNAL ;
    PORT
      LAYER M5 ;
        RECT  29.136 86.208 29.16 86.4 ;
    END
  END rd[65]
  PIN rd[66]
    DIRECTION OUTPUT ;
    USE SIGNAL ;
    PORT
      LAYER M3 ;
        RECT  29.232 86.256 29.25 86.4 ;
    END
  END rd[66]
  PIN rd[67]
    DIRECTION OUTPUT ;
    USE SIGNAL ;
    PORT
      LAYER M5 ;
        RECT  29.28 86.208 29.304 86.4 ;
    END
  END rd[67]
  PIN rd[68]
    DIRECTION OUTPUT ;
    USE SIGNAL ;
    PORT
      LAYER M3 ;
        RECT  29.376 86.256 29.394 86.4 ;
    END
  END rd[68]
  PIN rd[69]
    DIRECTION OUTPUT ;
    USE SIGNAL ;
    PORT
      LAYER M5 ;
        RECT  29.424 86.208 29.448 86.4 ;
    END
  END rd[69]
  PIN rd[6]
    DIRECTION OUTPUT ;
    USE SIGNAL ;
    PORT
      LAYER M3 ;
        RECT  24.912 86.256 24.93 86.4 ;
    END
  END rd[6]
  PIN rd[70]
    DIRECTION OUTPUT ;
    USE SIGNAL ;
    PORT
      LAYER M3 ;
        RECT  29.52 86.256 29.538 86.4 ;
    END
  END rd[70]
  PIN rd[71]
    DIRECTION OUTPUT ;
    USE SIGNAL ;
    PORT
      LAYER M5 ;
        RECT  29.568 86.208 29.592 86.4 ;
    END
  END rd[71]
  PIN rd[72]
    DIRECTION OUTPUT ;
    USE SIGNAL ;
    PORT
      LAYER M3 ;
        RECT  29.664 86.256 29.682 86.4 ;
    END
  END rd[72]
  PIN rd[73]
    DIRECTION OUTPUT ;
    USE SIGNAL ;
    PORT
      LAYER M5 ;
        RECT  29.712 86.208 29.736 86.4 ;
    END
  END rd[73]
  PIN rd[74]
    DIRECTION OUTPUT ;
    USE SIGNAL ;
    PORT
      LAYER M3 ;
        RECT  29.808 86.256 29.826 86.4 ;
    END
  END rd[74]
  PIN rd[75]
    DIRECTION OUTPUT ;
    USE SIGNAL ;
    PORT
      LAYER M5 ;
        RECT  29.856 86.208 29.88 86.4 ;
    END
  END rd[75]
  PIN rd[76]
    DIRECTION OUTPUT ;
    USE SIGNAL ;
    PORT
      LAYER M3 ;
        RECT  29.952 86.256 29.97 86.4 ;
    END
  END rd[76]
  PIN rd[77]
    DIRECTION OUTPUT ;
    USE SIGNAL ;
    PORT
      LAYER M5 ;
        RECT  30 86.208 30.024 86.4 ;
    END
  END rd[77]
  PIN rd[78]
    DIRECTION OUTPUT ;
    USE SIGNAL ;
    PORT
      LAYER M3 ;
        RECT  30.096 86.256 30.114 86.4 ;
    END
  END rd[78]
  PIN rd[79]
    DIRECTION OUTPUT ;
    USE SIGNAL ;
    PORT
      LAYER M5 ;
        RECT  30.144 86.208 30.168 86.4 ;
    END
  END rd[79]
  PIN rd[7]
    DIRECTION OUTPUT ;
    USE SIGNAL ;
    PORT
      LAYER M5 ;
        RECT  24.96 86.208 24.984 86.4 ;
    END
  END rd[7]
  PIN rd[80]
    DIRECTION OUTPUT ;
    USE SIGNAL ;
    PORT
      LAYER M3 ;
        RECT  30.24 86.256 30.258 86.4 ;
    END
  END rd[80]
  PIN rd[81]
    DIRECTION OUTPUT ;
    USE SIGNAL ;
    PORT
      LAYER M5 ;
        RECT  30.288 86.208 30.312 86.4 ;
    END
  END rd[81]
  PIN rd[82]
    DIRECTION OUTPUT ;
    USE SIGNAL ;
    PORT
      LAYER M3 ;
        RECT  30.384 86.256 30.402 86.4 ;
    END
  END rd[82]
  PIN rd[83]
    DIRECTION OUTPUT ;
    USE SIGNAL ;
    PORT
      LAYER M5 ;
        RECT  30.432 86.208 30.456 86.4 ;
    END
  END rd[83]
  PIN rd[84]
    DIRECTION OUTPUT ;
    USE SIGNAL ;
    PORT
      LAYER M3 ;
        RECT  30.528 86.256 30.546 86.4 ;
    END
  END rd[84]
  PIN rd[85]
    DIRECTION OUTPUT ;
    USE SIGNAL ;
    PORT
      LAYER M5 ;
        RECT  30.576 86.208 30.6 86.4 ;
    END
  END rd[85]
  PIN rd[86]
    DIRECTION OUTPUT ;
    USE SIGNAL ;
    PORT
      LAYER M3 ;
        RECT  30.672 86.256 30.69 86.4 ;
    END
  END rd[86]
  PIN rd[87]
    DIRECTION OUTPUT ;
    USE SIGNAL ;
    PORT
      LAYER M5 ;
        RECT  30.72 86.208 30.744 86.4 ;
    END
  END rd[87]
  PIN rd[88]
    DIRECTION OUTPUT ;
    USE SIGNAL ;
    PORT
      LAYER M3 ;
        RECT  30.816 86.256 30.834 86.4 ;
    END
  END rd[88]
  PIN rd[89]
    DIRECTION OUTPUT ;
    USE SIGNAL ;
    PORT
      LAYER M5 ;
        RECT  30.864 86.208 30.888 86.4 ;
    END
  END rd[89]
  PIN rd[8]
    DIRECTION OUTPUT ;
    USE SIGNAL ;
    PORT
      LAYER M3 ;
        RECT  25.056 86.256 25.074 86.4 ;
    END
  END rd[8]
  PIN rd[90]
    DIRECTION OUTPUT ;
    USE SIGNAL ;
    PORT
      LAYER M3 ;
        RECT  30.96 86.256 30.978 86.4 ;
    END
  END rd[90]
  PIN rd[91]
    DIRECTION OUTPUT ;
    USE SIGNAL ;
    PORT
      LAYER M5 ;
        RECT  31.008 86.208 31.032 86.4 ;
    END
  END rd[91]
  PIN rd[92]
    DIRECTION OUTPUT ;
    USE SIGNAL ;
    PORT
      LAYER M3 ;
        RECT  31.104 86.256 31.122 86.4 ;
    END
  END rd[92]
  PIN rd[93]
    DIRECTION OUTPUT ;
    USE SIGNAL ;
    PORT
      LAYER M5 ;
        RECT  31.152 86.208 31.176 86.4 ;
    END
  END rd[93]
  PIN rd[94]
    DIRECTION OUTPUT ;
    USE SIGNAL ;
    PORT
      LAYER M3 ;
        RECT  31.248 86.256 31.266 86.4 ;
    END
  END rd[94]
  PIN rd[95]
    DIRECTION OUTPUT ;
    USE SIGNAL ;
    PORT
      LAYER M5 ;
        RECT  31.296 86.208 31.32 86.4 ;
    END
  END rd[95]
  PIN rd[96]
    DIRECTION OUTPUT ;
    USE SIGNAL ;
    PORT
      LAYER M3 ;
        RECT  31.392 86.256 31.41 86.4 ;
    END
  END rd[96]
  PIN rd[97]
    DIRECTION OUTPUT ;
    USE SIGNAL ;
    PORT
      LAYER M5 ;
        RECT  31.44 86.208 31.464 86.4 ;
    END
  END rd[97]
  PIN rd[98]
    DIRECTION OUTPUT ;
    USE SIGNAL ;
    PORT
      LAYER M3 ;
        RECT  31.536 86.256 31.554 86.4 ;
    END
  END rd[98]
  PIN rd[99]
    DIRECTION OUTPUT ;
    USE SIGNAL ;
    PORT
      LAYER M5 ;
        RECT  31.584 86.208 31.608 86.4 ;
    END
  END rd[99]
  PIN rd[9]
    DIRECTION OUTPUT ;
    USE SIGNAL ;
    PORT
      LAYER M5 ;
        RECT  25.104 86.208 25.128 86.4 ;
    END
  END rd[9]
  PIN rq0
    DIRECTION INPUT ;
    USE SIGNAL ;
    PORT
      LAYER M4 ;
        RECT  0 38.736 0.192 38.76 ;
    END
  END rq0
  PIN rq1
    DIRECTION INPUT ;
    USE SIGNAL ;
    PORT
      LAYER M4 ;
        RECT  0 38.592 0.192 38.616 ;
    END
  END rq1
  PIN rst_n
    DIRECTION INPUT ;
    USE SIGNAL ;
    PORT
      LAYER M4 ;
        RECT  0 51.024 0.192 51.048 ;
    END
    PORT
      LAYER M4 ;
        RECT  0.156 51.024 0.205 51.048 ;
    END
  END rst_n
  PIN w0[0]
    DIRECTION INPUT ;
    USE SIGNAL ;
    PORT
      LAYER M4 ;
        RECT  0 38.88 0.192 38.904 ;
    END
  END w0[0]
  PIN w0[1]
    DIRECTION INPUT ;
    USE SIGNAL ;
    PORT
      LAYER M4 ;
        RECT  0 39.024 0.192 39.048 ;
    END
  END w0[1]
  PIN w0[2]
    DIRECTION INPUT ;
    USE SIGNAL ;
    PORT
      LAYER M4 ;
        RECT  0 39.168 0.192 39.192 ;
    END
  END w0[2]
  PIN w0[3]
    DIRECTION INPUT ;
    USE SIGNAL ;
    PORT
      LAYER M4 ;
        RECT  0 39.312 0.192 39.336 ;
    END
  END w0[3]
  PIN w0[4]
    DIRECTION INPUT ;
    USE SIGNAL ;
    PORT
      LAYER M4 ;
        RECT  0 39.456 0.192 39.48 ;
    END
  END w0[4]
  PIN w0[5]
    DIRECTION INPUT ;
    USE SIGNAL ;
    PORT
      LAYER M4 ;
        RECT  0 39.6 0.192 39.624 ;
    END
  END w0[5]
  PIN w0[6]
    DIRECTION INPUT ;
    USE SIGNAL ;
    PORT
      LAYER M4 ;
        RECT  0 39.744 0.192 39.768 ;
    END
  END w0[6]
  PIN w0[7]
    DIRECTION INPUT ;
    USE SIGNAL ;
    PORT
      LAYER M4 ;
        RECT  0 39.888 0.192 39.912 ;
    END
  END w0[7]
  PIN w0[8]
    DIRECTION INPUT ;
    USE SIGNAL ;
    PORT
      LAYER M4 ;
        RECT  0 40.032 0.192 40.056 ;
    END
  END w0[8]
  PIN w1[0]
    DIRECTION INPUT ;
    USE SIGNAL ;
    PORT
      LAYER M4 ;
        RECT  0 40.176 0.192 40.2 ;
    END
  END w1[0]
  PIN w1[1]
    DIRECTION INPUT ;
    USE SIGNAL ;
    PORT
      LAYER M4 ;
        RECT  0 40.32 0.192 40.344 ;
    END
  END w1[1]
  PIN w1[2]
    DIRECTION INPUT ;
    USE SIGNAL ;
    PORT
      LAYER M4 ;
        RECT  0 40.464 0.192 40.488 ;
    END
  END w1[2]
  PIN w1[3]
    DIRECTION INPUT ;
    USE SIGNAL ;
    PORT
      LAYER M4 ;
        RECT  0 40.608 0.192 40.632 ;
    END
  END w1[3]
  PIN w1[4]
    DIRECTION INPUT ;
    USE SIGNAL ;
    PORT
      LAYER M4 ;
        RECT  0 40.752 0.192 40.776 ;
    END
  END w1[4]
  PIN w1[5]
    DIRECTION INPUT ;
    USE SIGNAL ;
    PORT
      LAYER M4 ;
        RECT  0 40.896 0.192 40.92 ;
    END
  END w1[5]
  PIN w1[6]
    DIRECTION INPUT ;
    USE SIGNAL ;
    PORT
      LAYER M4 ;
        RECT  0 41.04 0.192 41.064 ;
    END
  END w1[6]
  PIN w1[7]
    DIRECTION INPUT ;
    USE SIGNAL ;
    PORT
      LAYER M4 ;
        RECT  0 41.184 0.192 41.208 ;
    END
  END w1[7]
  PIN w1[8]
    DIRECTION INPUT ;
    USE SIGNAL ;
    PORT
      LAYER M4 ;
        RECT  0 41.328 0.192 41.352 ;
    END
  END w1[8]
  PIN wv
    DIRECTION INPUT ;
    USE SIGNAL ;
    PORT
      LAYER M4 ;
        RECT  0 41.472 0.192 41.496 ;
    END
  END wv
  PIN VDD
    DIRECTION INOUT ;
    USE POWER ;
    PORT
      LAYER M5 ;
        RECT  137.592 2.151 137.712 84.249 ;
        RECT  132.192 2.151 132.312 84.249 ;
        RECT  126.792 2.151 126.912 84.249 ;
        RECT  121.392 2.151 121.512 84.249 ;
        RECT  115.992 2.151 116.112 84.249 ;
        RECT  110.592 2.151 110.712 84.249 ;
        RECT  105.192 2.151 105.312 84.249 ;
        RECT  99.792 2.151 99.912 84.249 ;
        RECT  94.392 2.151 94.512 84.249 ;
        RECT  88.992 2.151 89.112 84.249 ;
        RECT  83.592 2.151 83.712 84.249 ;
        RECT  78.192 2.151 78.312 84.249 ;
        RECT  72.792 2.151 72.912 84.249 ;
        RECT  67.392 2.151 67.512 84.249 ;
        RECT  61.992 2.151 62.112 84.249 ;
        RECT  56.592 2.151 56.712 84.249 ;
        RECT  51.192 2.151 51.312 84.249 ;
        RECT  45.792 2.151 45.912 84.249 ;
        RECT  40.392 2.151 40.512 84.249 ;
        RECT  34.992 2.151 35.112 84.249 ;
        RECT  29.592 2.151 29.712 84.249 ;
        RECT  24.192 2.151 24.312 84.249 ;
        RECT  18.792 2.151 18.912 84.249 ;
        RECT  13.392 2.151 13.512 84.249 ;
        RECT  7.992 2.151 8.112 84.249 ;
        RECT  2.592 2.151 2.712 84.249 ;
    END
  END VDD
  PIN VSS
    DIRECTION INOUT ;
    USE GROUND ;
    PORT
      LAYER M5 ;
        RECT  137.4 2.137 137.52 84.263 ;
        RECT  132 2.137 132.12 84.263 ;
        RECT  126.6 2.137 126.72 84.263 ;
        RECT  121.2 2.137 121.32 84.263 ;
        RECT  115.8 2.137 115.92 84.263 ;
        RECT  110.4 2.137 110.52 84.263 ;
        RECT  105 2.137 105.12 84.263 ;
        RECT  99.6 2.137 99.72 84.263 ;
        RECT  94.2 2.137 94.32 84.263 ;
        RECT  88.8 2.137 88.92 84.263 ;
        RECT  83.4 2.137 83.52 84.263 ;
        RECT  78 2.137 78.12 84.263 ;
        RECT  72.6 2.137 72.72 84.263 ;
        RECT  67.2 2.137 67.32 84.263 ;
        RECT  61.8 2.137 61.92 84.263 ;
        RECT  56.4 2.137 56.52 84.263 ;
        RECT  51 2.137 51.12 84.263 ;
        RECT  45.6 2.137 45.72 84.263 ;
        RECT  40.2 2.137 40.32 84.263 ;
        RECT  34.8 2.137 34.92 84.263 ;
        RECT  29.4 2.137 29.52 84.263 ;
        RECT  24 2.137 24.12 84.263 ;
        RECT  18.6 2.137 18.72 84.263 ;
        RECT  13.2 2.137 13.32 84.263 ;
        RECT  7.8 2.137 7.92 84.263 ;
        RECT  2.4 2.137 2.52 84.263 ;
    END
  END VSS
  # OT_OBS_CLOSED layer=M5 d_um=1.536 added=444
  OBS
    LAYER RVTN ;
     RECT  2.16 2.16 140.4 2.295 ;
     RECT  2.16 2.565 140.4 2.835 ;
     RECT  2.16 3.105 140.4 3.375 ;
     RECT  2.16 3.645 140.4 3.915 ;
     RECT  2.16 4.185 140.4 4.455 ;
     RECT  2.16 4.725 140.4 4.995 ;
     RECT  2.16 5.265 140.4 5.535 ;
     RECT  2.16 5.805 140.4 6.075 ;
     RECT  2.16 6.345 140.4 6.615 ;
     RECT  2.16 6.885 140.4 7.155 ;
     RECT  2.16 7.425 140.4 7.695 ;
     RECT  2.16 7.965 140.4 8.235 ;
     RECT  2.16 8.505 140.4 8.775 ;
     RECT  2.16 9.045 140.4 9.315 ;
     RECT  2.16 9.585 140.4 9.855 ;
     RECT  2.16 10.125 140.4 10.395 ;
     RECT  2.16 10.665 140.4 10.935 ;
     RECT  2.16 11.205 140.4 11.475 ;
     RECT  2.16 11.745 140.4 12.015 ;
     RECT  2.16 12.285 140.4 12.555 ;
     RECT  2.16 12.825 140.4 13.095 ;
     RECT  2.16 13.365 140.4 13.635 ;
     RECT  2.16 13.905 140.4 14.175 ;
     RECT  2.16 14.445 140.4 14.715 ;
     RECT  2.16 14.985 140.4 15.255 ;
     RECT  2.16 15.525 140.4 15.795 ;
     RECT  2.16 16.065 140.4 16.335 ;
     RECT  2.16 16.605 140.4 16.875 ;
     RECT  2.16 17.145 140.4 17.415 ;
     RECT  2.16 17.685 140.4 17.955 ;
     RECT  2.16 18.225 140.4 18.495 ;
     RECT  2.16 18.765 140.4 19.035 ;
     RECT  2.16 19.305 140.4 19.575 ;
     RECT  2.16 19.845 140.4 20.115 ;
     RECT  2.16 20.385 20.412 20.655 ;
     RECT  119.34 20.385 140.4 20.655 ;
     RECT  2.16 20.925 20.412 21.195 ;
     RECT  119.34 20.925 140.4 21.195 ;
     RECT  2.16 21.465 20.412 21.735 ;
     RECT  119.34 21.465 140.4 21.735 ;
     RECT  2.16 22.005 20.412 22.275 ;
     RECT  119.34 22.005 140.4 22.275 ;
     RECT  2.16 22.545 20.412 22.815 ;
     RECT  119.34 22.545 140.4 22.815 ;
     RECT  2.16 23.085 20.412 23.355 ;
     RECT  119.34 23.085 140.4 23.355 ;
     RECT  2.16 23.625 20.412 23.895 ;
     RECT  119.34 23.625 140.4 23.895 ;
     RECT  2.16 24.165 20.412 24.435 ;
     RECT  119.34 24.165 140.4 24.435 ;
     RECT  2.16 24.705 20.412 24.975 ;
     RECT  119.34 24.705 140.4 24.975 ;
     RECT  2.16 25.245 20.412 25.515 ;
     RECT  119.34 25.245 140.4 25.515 ;
     RECT  2.16 25.785 20.412 26.055 ;
     RECT  119.34 25.785 140.4 26.055 ;
     RECT  2.16 26.325 20.412 26.595 ;
     RECT  119.34 26.325 140.4 26.595 ;
     RECT  2.16 26.865 20.412 27.135 ;
     RECT  119.34 26.865 140.4 27.135 ;
     RECT  2.16 27.405 20.412 27.675 ;
     RECT  119.34 27.405 140.4 27.675 ;
     RECT  2.16 27.945 20.412 28.215 ;
     RECT  119.34 27.945 140.4 28.215 ;
     RECT  2.16 28.485 20.412 28.755 ;
     RECT  119.34 28.485 140.4 28.755 ;
     RECT  2.16 29.025 20.412 29.295 ;
     RECT  119.34 29.025 140.4 29.295 ;
     RECT  2.16 29.565 20.412 29.835 ;
     RECT  119.34 29.565 140.4 29.835 ;
     RECT  2.16 30.105 20.412 30.375 ;
     RECT  119.34 30.105 140.4 30.375 ;
     RECT  2.16 30.645 20.412 30.915 ;
     RECT  119.34 30.645 140.4 30.915 ;
     RECT  2.16 31.185 20.412 31.455 ;
     RECT  119.34 31.185 140.4 31.455 ;
     RECT  2.16 31.725 20.412 31.995 ;
     RECT  119.34 31.725 140.4 31.995 ;
     RECT  2.16 32.265 20.412 32.535 ;
     RECT  119.34 32.265 140.4 32.535 ;
     RECT  2.16 32.805 20.412 33.075 ;
     RECT  119.34 32.805 140.4 33.075 ;
     RECT  2.16 33.345 20.412 33.615 ;
     RECT  119.34 33.345 140.4 33.615 ;
     RECT  2.16 33.885 20.412 34.155 ;
     RECT  119.34 33.885 140.4 34.155 ;
     RECT  2.16 34.425 20.412 34.695 ;
     RECT  119.34 34.425 140.4 34.695 ;
     RECT  2.16 34.965 20.412 35.235 ;
     RECT  119.34 34.965 140.4 35.235 ;
     RECT  2.16 35.505 20.412 35.775 ;
     RECT  119.34 35.505 140.4 35.775 ;
     RECT  2.16 36.045 20.412 36.315 ;
     RECT  119.34 36.045 140.4 36.315 ;
     RECT  2.16 36.585 20.412 36.855 ;
     RECT  119.34 36.585 140.4 36.855 ;
     RECT  2.16 37.125 20.412 37.395 ;
     RECT  119.34 37.125 140.4 37.395 ;
     RECT  2.16 37.665 20.412 37.935 ;
     RECT  119.34 37.665 140.4 37.935 ;
     RECT  2.16 38.205 20.412 38.475 ;
     RECT  119.34 38.205 140.4 38.475 ;
     RECT  2.16 38.745 20.412 39.015 ;
     RECT  119.34 38.745 140.4 39.015 ;
     RECT  2.16 39.285 20.412 39.555 ;
     RECT  119.34 39.285 140.4 39.555 ;
     RECT  2.16 39.825 20.412 40.095 ;
     RECT  119.34 39.825 140.4 40.095 ;
     RECT  2.16 40.365 20.412 40.635 ;
     RECT  119.34 40.365 140.4 40.635 ;
     RECT  2.16 40.905 20.412 41.175 ;
     RECT  119.34 40.905 140.4 41.175 ;
     RECT  2.16 41.445 20.412 41.715 ;
     RECT  119.34 41.445 140.4 41.715 ;
     RECT  2.16 41.985 20.412 42.255 ;
     RECT  119.34 41.985 140.4 42.255 ;
     RECT  2.16 42.525 20.412 42.795 ;
     RECT  119.34 42.525 140.4 42.795 ;
     RECT  2.16 43.065 20.412 43.335 ;
     RECT  119.34 43.065 140.4 43.335 ;
     RECT  2.16 43.605 20.412 43.875 ;
     RECT  119.34 43.605 140.4 43.875 ;
     RECT  2.16 44.145 20.412 44.415 ;
     RECT  119.34 44.145 140.4 44.415 ;
     RECT  2.16 44.685 20.412 44.955 ;
     RECT  119.34 44.685 140.4 44.955 ;
     RECT  2.16 45.225 20.412 45.495 ;
     RECT  119.34 45.225 140.4 45.495 ;
     RECT  2.16 45.765 20.412 46.035 ;
     RECT  119.34 45.765 140.4 46.035 ;
     RECT  2.16 46.305 20.412 46.575 ;
     RECT  119.34 46.305 140.4 46.575 ;
     RECT  2.16 46.845 20.412 47.115 ;
     RECT  119.34 46.845 140.4 47.115 ;
     RECT  2.16 47.385 20.412 47.655 ;
     RECT  119.34 47.385 140.4 47.655 ;
     RECT  2.16 47.925 20.412 48.195 ;
     RECT  119.34 47.925 140.4 48.195 ;
     RECT  2.16 48.465 20.412 48.735 ;
     RECT  119.34 48.465 140.4 48.735 ;
     RECT  2.16 49.005 20.412 49.275 ;
     RECT  119.34 49.005 140.4 49.275 ;
     RECT  2.16 49.545 20.412 49.815 ;
     RECT  119.34 49.545 140.4 49.815 ;
     RECT  2.16 50.085 20.412 50.355 ;
     RECT  119.34 50.085 140.4 50.355 ;
     RECT  2.16 50.625 20.412 50.895 ;
     RECT  119.34 50.625 140.4 50.895 ;
     RECT  2.16 51.165 20.412 51.435 ;
     RECT  119.34 51.165 140.4 51.435 ;
     RECT  2.16 51.705 20.412 51.975 ;
     RECT  119.34 51.705 140.4 51.975 ;
     RECT  2.16 52.245 20.412 52.515 ;
     RECT  119.34 52.245 140.4 52.515 ;
     RECT  2.16 52.785 20.412 53.055 ;
     RECT  119.34 52.785 140.4 53.055 ;
     RECT  2.16 53.325 20.412 53.595 ;
     RECT  119.34 53.325 140.4 53.595 ;
     RECT  2.16 53.865 20.412 54.135 ;
     RECT  119.34 53.865 140.4 54.135 ;
     RECT  2.16 54.405 20.412 54.675 ;
     RECT  119.34 54.405 140.4 54.675 ;
     RECT  2.16 54.945 20.412 55.215 ;
     RECT  119.34 54.945 140.4 55.215 ;
     RECT  2.16 55.485 20.412 55.755 ;
     RECT  119.34 55.485 140.4 55.755 ;
     RECT  2.16 56.025 20.412 56.295 ;
     RECT  119.34 56.025 140.4 56.295 ;
     RECT  2.16 56.565 20.412 56.835 ;
     RECT  119.34 56.565 140.4 56.835 ;
     RECT  2.16 57.105 20.412 57.375 ;
     RECT  119.34 57.105 140.4 57.375 ;
     RECT  2.16 57.645 20.412 57.915 ;
     RECT  119.34 57.645 140.4 57.915 ;
     RECT  2.16 58.185 20.412 58.455 ;
     RECT  119.34 58.185 140.4 58.455 ;
     RECT  2.16 58.725 20.412 58.995 ;
     RECT  119.34 58.725 140.4 58.995 ;
     RECT  2.16 59.265 20.412 59.535 ;
     RECT  119.34 59.265 140.4 59.535 ;
     RECT  2.16 59.805 20.412 60.075 ;
     RECT  119.34 59.805 140.4 60.075 ;
     RECT  2.16 60.345 20.412 60.615 ;
     RECT  119.34 60.345 140.4 60.615 ;
     RECT  2.16 60.885 20.412 61.155 ;
     RECT  119.34 60.885 140.4 61.155 ;
     RECT  2.16 61.425 20.412 61.695 ;
     RECT  119.34 61.425 140.4 61.695 ;
     RECT  2.16 61.965 20.412 62.235 ;
     RECT  119.34 61.965 140.4 62.235 ;
     RECT  2.16 62.505 20.412 62.775 ;
     RECT  119.34 62.505 140.4 62.775 ;
     RECT  2.16 63.045 20.412 63.315 ;
     RECT  119.34 63.045 140.4 63.315 ;
     RECT  2.16 63.585 20.412 63.855 ;
     RECT  119.34 63.585 140.4 63.855 ;
     RECT  2.16 64.125 20.412 64.395 ;
     RECT  119.34 64.125 140.4 64.395 ;
     RECT  2.16 64.665 20.412 64.935 ;
     RECT  119.34 64.665 140.4 64.935 ;
     RECT  2.16 65.205 20.412 65.475 ;
     RECT  119.34 65.205 140.4 65.475 ;
     RECT  2.16 65.745 140.4 66.015 ;
     RECT  2.16 66.285 140.4 66.555 ;
     RECT  2.16 66.825 140.4 67.095 ;
     RECT  2.16 67.365 140.4 67.635 ;
     RECT  2.16 67.905 140.4 68.175 ;
     RECT  2.16 68.445 140.4 68.715 ;
     RECT  2.16 68.985 140.4 69.255 ;
     RECT  2.16 69.525 140.4 69.795 ;
     RECT  2.16 70.065 140.4 70.335 ;
     RECT  2.16 70.605 140.4 70.875 ;
     RECT  2.16 71.145 140.4 71.415 ;
     RECT  2.16 71.685 140.4 71.955 ;
     RECT  2.16 72.225 140.4 72.495 ;
     RECT  2.16 72.765 140.4 73.035 ;
     RECT  2.16 73.305 140.4 73.575 ;
     RECT  2.16 73.845 140.4 74.115 ;
     RECT  2.16 74.385 140.4 74.655 ;
     RECT  2.16 74.925 140.4 75.195 ;
     RECT  2.16 75.465 140.4 75.735 ;
     RECT  2.16 76.005 140.4 76.275 ;
     RECT  2.16 76.545 140.4 76.815 ;
     RECT  2.16 77.085 140.4 77.355 ;
     RECT  2.16 77.625 140.4 77.895 ;
     RECT  2.16 78.165 140.4 78.435 ;
     RECT  2.16 78.705 140.4 78.975 ;
     RECT  2.16 79.245 140.4 79.515 ;
     RECT  2.16 79.785 140.4 80.055 ;
     RECT  2.16 80.325 140.4 80.595 ;
     RECT  2.16 80.865 140.4 81.135 ;
     RECT  2.16 81.405 140.4 81.675 ;
     RECT  2.16 81.945 140.4 82.215 ;
     RECT  2.16 82.485 140.4 82.755 ;
     RECT  2.16 83.025 140.4 83.295 ;
     RECT  2.16 83.565 140.4 83.835 ;
     RECT  2.16 84.105 140.4 84.24 ;
    LAYER RVTP ;
     RECT  2.16 2.295 140.4 2.565 ;
     RECT  2.16 2.835 140.4 3.105 ;
     RECT  2.16 3.375 140.4 3.645 ;
     RECT  2.16 3.915 140.4 4.185 ;
     RECT  2.16 4.455 140.4 4.725 ;
     RECT  2.16 4.995 140.4 5.265 ;
     RECT  2.16 5.535 140.4 5.805 ;
     RECT  2.16 6.075 140.4 6.345 ;
     RECT  2.16 6.615 140.4 6.885 ;
     RECT  2.16 7.155 140.4 7.425 ;
     RECT  2.16 7.695 140.4 7.965 ;
     RECT  2.16 8.235 140.4 8.505 ;
     RECT  2.16 8.775 140.4 9.045 ;
     RECT  2.16 9.315 140.4 9.585 ;
     RECT  2.16 9.855 140.4 10.125 ;
     RECT  2.16 10.395 140.4 10.665 ;
     RECT  2.16 10.935 140.4 11.205 ;
     RECT  2.16 11.475 140.4 11.745 ;
     RECT  2.16 12.015 140.4 12.285 ;
     RECT  2.16 12.555 140.4 12.825 ;
     RECT  2.16 13.095 140.4 13.365 ;
     RECT  2.16 13.635 140.4 13.905 ;
     RECT  2.16 14.175 140.4 14.445 ;
     RECT  2.16 14.715 140.4 14.985 ;
     RECT  2.16 15.255 140.4 15.525 ;
     RECT  2.16 15.795 140.4 16.065 ;
     RECT  2.16 16.335 140.4 16.605 ;
     RECT  2.16 16.875 140.4 17.145 ;
     RECT  2.16 17.415 140.4 17.685 ;
     RECT  2.16 17.955 140.4 18.225 ;
     RECT  2.16 18.495 140.4 18.765 ;
     RECT  2.16 19.035 140.4 19.305 ;
     RECT  2.16 19.575 140.4 19.845 ;
     RECT  2.16 20.115 140.4 20.25 ;
     RECT  2.16 20.25 20.412 20.385 ;
     RECT  119.34 20.25 140.4 20.385 ;
     RECT  2.16 20.655 20.412 20.925 ;
     RECT  119.34 20.655 140.4 20.925 ;
     RECT  2.16 21.195 20.412 21.465 ;
     RECT  119.34 21.195 140.4 21.465 ;
     RECT  2.16 21.735 20.412 22.005 ;
     RECT  119.34 21.735 140.4 22.005 ;
     RECT  2.16 22.275 20.412 22.545 ;
     RECT  119.34 22.275 140.4 22.545 ;
     RECT  2.16 22.815 20.412 23.085 ;
     RECT  119.34 22.815 140.4 23.085 ;
     RECT  2.16 23.355 20.412 23.625 ;
     RECT  119.34 23.355 140.4 23.625 ;
     RECT  2.16 23.895 20.412 24.165 ;
     RECT  119.34 23.895 140.4 24.165 ;
     RECT  2.16 24.435 20.412 24.705 ;
     RECT  119.34 24.435 140.4 24.705 ;
     RECT  2.16 24.975 20.412 25.245 ;
     RECT  119.34 24.975 140.4 25.245 ;
     RECT  2.16 25.515 20.412 25.785 ;
     RECT  119.34 25.515 140.4 25.785 ;
     RECT  2.16 26.055 20.412 26.325 ;
     RECT  119.34 26.055 140.4 26.325 ;
     RECT  2.16 26.595 20.412 26.865 ;
     RECT  119.34 26.595 140.4 26.865 ;
     RECT  2.16 27.135 20.412 27.405 ;
     RECT  119.34 27.135 140.4 27.405 ;
     RECT  2.16 27.675 20.412 27.945 ;
     RECT  119.34 27.675 140.4 27.945 ;
     RECT  2.16 28.215 20.412 28.485 ;
     RECT  119.34 28.215 140.4 28.485 ;
     RECT  2.16 28.755 20.412 29.025 ;
     RECT  119.34 28.755 140.4 29.025 ;
     RECT  2.16 29.295 20.412 29.565 ;
     RECT  119.34 29.295 140.4 29.565 ;
     RECT  2.16 29.835 20.412 30.105 ;
     RECT  119.34 29.835 140.4 30.105 ;
     RECT  2.16 30.375 20.412 30.645 ;
     RECT  119.34 30.375 140.4 30.645 ;
     RECT  2.16 30.915 20.412 31.185 ;
     RECT  119.34 30.915 140.4 31.185 ;
     RECT  2.16 31.455 20.412 31.725 ;
     RECT  119.34 31.455 140.4 31.725 ;
     RECT  2.16 31.995 20.412 32.265 ;
     RECT  119.34 31.995 140.4 32.265 ;
     RECT  2.16 32.535 20.412 32.805 ;
     RECT  119.34 32.535 140.4 32.805 ;
     RECT  2.16 33.075 20.412 33.345 ;
     RECT  119.34 33.075 140.4 33.345 ;
     RECT  2.16 33.615 20.412 33.885 ;
     RECT  119.34 33.615 140.4 33.885 ;
     RECT  2.16 34.155 20.412 34.425 ;
     RECT  119.34 34.155 140.4 34.425 ;
     RECT  2.16 34.695 20.412 34.965 ;
     RECT  119.34 34.695 140.4 34.965 ;
     RECT  2.16 35.235 20.412 35.505 ;
     RECT  119.34 35.235 140.4 35.505 ;
     RECT  2.16 35.775 20.412 36.045 ;
     RECT  119.34 35.775 140.4 36.045 ;
     RECT  2.16 36.315 20.412 36.585 ;
     RECT  119.34 36.315 140.4 36.585 ;
     RECT  2.16 36.855 20.412 37.125 ;
     RECT  119.34 36.855 140.4 37.125 ;
     RECT  2.16 37.395 20.412 37.665 ;
     RECT  119.34 37.395 140.4 37.665 ;
     RECT  2.16 37.935 20.412 38.205 ;
     RECT  119.34 37.935 140.4 38.205 ;
     RECT  2.16 38.475 20.412 38.745 ;
     RECT  119.34 38.475 140.4 38.745 ;
     RECT  2.16 39.015 20.412 39.285 ;
     RECT  119.34 39.015 140.4 39.285 ;
     RECT  2.16 39.555 20.412 39.825 ;
     RECT  119.34 39.555 140.4 39.825 ;
     RECT  2.16 40.095 20.412 40.365 ;
     RECT  119.34 40.095 140.4 40.365 ;
     RECT  2.16 40.635 20.412 40.905 ;
     RECT  119.34 40.635 140.4 40.905 ;
     RECT  2.16 41.175 20.412 41.445 ;
     RECT  119.34 41.175 140.4 41.445 ;
     RECT  2.16 41.715 20.412 41.985 ;
     RECT  119.34 41.715 140.4 41.985 ;
     RECT  2.16 42.255 20.412 42.525 ;
     RECT  119.34 42.255 140.4 42.525 ;
     RECT  2.16 42.795 20.412 43.065 ;
     RECT  119.34 42.795 140.4 43.065 ;
     RECT  2.16 43.335 20.412 43.605 ;
     RECT  119.34 43.335 140.4 43.605 ;
     RECT  2.16 43.875 20.412 44.145 ;
     RECT  119.34 43.875 140.4 44.145 ;
     RECT  2.16 44.415 20.412 44.685 ;
     RECT  119.34 44.415 140.4 44.685 ;
     RECT  2.16 44.955 20.412 45.225 ;
     RECT  119.34 44.955 140.4 45.225 ;
     RECT  2.16 45.495 20.412 45.765 ;
     RECT  119.34 45.495 140.4 45.765 ;
     RECT  2.16 46.035 20.412 46.305 ;
     RECT  119.34 46.035 140.4 46.305 ;
     RECT  2.16 46.575 20.412 46.845 ;
     RECT  119.34 46.575 140.4 46.845 ;
     RECT  2.16 47.115 20.412 47.385 ;
     RECT  119.34 47.115 140.4 47.385 ;
     RECT  2.16 47.655 20.412 47.925 ;
     RECT  119.34 47.655 140.4 47.925 ;
     RECT  2.16 48.195 20.412 48.465 ;
     RECT  119.34 48.195 140.4 48.465 ;
     RECT  2.16 48.735 20.412 49.005 ;
     RECT  119.34 48.735 140.4 49.005 ;
     RECT  2.16 49.275 20.412 49.545 ;
     RECT  119.34 49.275 140.4 49.545 ;
     RECT  2.16 49.815 20.412 50.085 ;
     RECT  119.34 49.815 140.4 50.085 ;
     RECT  2.16 50.355 20.412 50.625 ;
     RECT  119.34 50.355 140.4 50.625 ;
     RECT  2.16 50.895 20.412 51.165 ;
     RECT  119.34 50.895 140.4 51.165 ;
     RECT  2.16 51.435 20.412 51.705 ;
     RECT  119.34 51.435 140.4 51.705 ;
     RECT  2.16 51.975 20.412 52.245 ;
     RECT  119.34 51.975 140.4 52.245 ;
     RECT  2.16 52.515 20.412 52.785 ;
     RECT  119.34 52.515 140.4 52.785 ;
     RECT  2.16 53.055 20.412 53.325 ;
     RECT  119.34 53.055 140.4 53.325 ;
     RECT  2.16 53.595 20.412 53.865 ;
     RECT  119.34 53.595 140.4 53.865 ;
     RECT  2.16 54.135 20.412 54.405 ;
     RECT  119.34 54.135 140.4 54.405 ;
     RECT  2.16 54.675 20.412 54.945 ;
     RECT  119.34 54.675 140.4 54.945 ;
     RECT  2.16 55.215 20.412 55.485 ;
     RECT  119.34 55.215 140.4 55.485 ;
     RECT  2.16 55.755 20.412 56.025 ;
     RECT  119.34 55.755 140.4 56.025 ;
     RECT  2.16 56.295 20.412 56.565 ;
     RECT  119.34 56.295 140.4 56.565 ;
     RECT  2.16 56.835 20.412 57.105 ;
     RECT  119.34 56.835 140.4 57.105 ;
     RECT  2.16 57.375 20.412 57.645 ;
     RECT  119.34 57.375 140.4 57.645 ;
     RECT  2.16 57.915 20.412 58.185 ;
     RECT  119.34 57.915 140.4 58.185 ;
     RECT  2.16 58.455 20.412 58.725 ;
     RECT  119.34 58.455 140.4 58.725 ;
     RECT  2.16 58.995 20.412 59.265 ;
     RECT  119.34 58.995 140.4 59.265 ;
     RECT  2.16 59.535 20.412 59.805 ;
     RECT  119.34 59.535 140.4 59.805 ;
     RECT  2.16 60.075 20.412 60.345 ;
     RECT  119.34 60.075 140.4 60.345 ;
     RECT  2.16 60.615 20.412 60.885 ;
     RECT  119.34 60.615 140.4 60.885 ;
     RECT  2.16 61.155 20.412 61.425 ;
     RECT  119.34 61.155 140.4 61.425 ;
     RECT  2.16 61.695 20.412 61.965 ;
     RECT  119.34 61.695 140.4 61.965 ;
     RECT  2.16 62.235 20.412 62.505 ;
     RECT  119.34 62.235 140.4 62.505 ;
     RECT  2.16 62.775 20.412 63.045 ;
     RECT  119.34 62.775 140.4 63.045 ;
     RECT  2.16 63.315 20.412 63.585 ;
     RECT  119.34 63.315 140.4 63.585 ;
     RECT  2.16 63.855 20.412 64.125 ;
     RECT  119.34 63.855 140.4 64.125 ;
     RECT  2.16 64.395 20.412 64.665 ;
     RECT  119.34 64.395 140.4 64.665 ;
     RECT  2.16 64.935 20.412 65.205 ;
     RECT  119.34 64.935 140.4 65.205 ;
     RECT  2.16 65.475 20.412 65.61 ;
     RECT  119.34 65.475 140.4 65.61 ;
     RECT  2.16 65.61 140.4 65.745 ;
     RECT  2.16 66.015 140.4 66.285 ;
     RECT  2.16 66.555 140.4 66.825 ;
     RECT  2.16 67.095 140.4 67.365 ;
     RECT  2.16 67.635 140.4 67.905 ;
     RECT  2.16 68.175 140.4 68.445 ;
     RECT  2.16 68.715 140.4 68.985 ;
     RECT  2.16 69.255 140.4 69.525 ;
     RECT  2.16 69.795 140.4 70.065 ;
     RECT  2.16 70.335 140.4 70.605 ;
     RECT  2.16 70.875 140.4 71.145 ;
     RECT  2.16 71.415 140.4 71.685 ;
     RECT  2.16 71.955 140.4 72.225 ;
     RECT  2.16 72.495 140.4 72.765 ;
     RECT  2.16 73.035 140.4 73.305 ;
     RECT  2.16 73.575 140.4 73.845 ;
     RECT  2.16 74.115 140.4 74.385 ;
     RECT  2.16 74.655 140.4 74.925 ;
     RECT  2.16 75.195 140.4 75.465 ;
     RECT  2.16 75.735 140.4 76.005 ;
     RECT  2.16 76.275 140.4 76.545 ;
     RECT  2.16 76.815 140.4 77.085 ;
     RECT  2.16 77.355 140.4 77.625 ;
     RECT  2.16 77.895 140.4 78.165 ;
     RECT  2.16 78.435 140.4 78.705 ;
     RECT  2.16 78.975 140.4 79.245 ;
     RECT  2.16 79.515 140.4 79.785 ;
     RECT  2.16 80.055 140.4 80.325 ;
     RECT  2.16 80.595 140.4 80.865 ;
     RECT  2.16 81.135 140.4 81.405 ;
     RECT  2.16 81.675 140.4 81.945 ;
     RECT  2.16 82.215 140.4 82.485 ;
     RECT  2.16 82.755 140.4 83.025 ;
     RECT  2.16 83.295 140.4 83.565 ;
     RECT  2.16 83.835 140.4 84.105 ;
    LAYER M1 ;
     RECT  2.16 2.151 140.4 20.259 ;
     RECT  22.464 22.464 117.288 63.528 ;
     RECT  2.16 20.259 20.412 65.601 ;
     RECT  119.34 20.259 140.4 65.601 ;
     RECT  2.16 65.601 140.4 84.249 ;
    LAYER M2 ;
     RECT  0.211 34.092 0.319 34.11 ;
     RECT  0.211 37.602 0.319 37.62 ;
     RECT  0.211 35.586 0.427 35.604 ;
     RECT  0.319 37.602 0.427 37.89 ;
     RECT  0.427 35.28 0.535 35.604 ;
     RECT  0.427 37.404 0.535 37.89 ;
     RECT  0.211 39.096 0.535 41.94 ;
     RECT  0.211 42.732 0.535 43.29 ;
     RECT  0.319 34.092 0.859 34.452 ;
     RECT  1.003 54.756 1.075 54.774 ;
     RECT  0.931 25.956 1.147 25.974 ;
     RECT  0.535 35.28 1.147 43.29 ;
     RECT  1.147 25.866 1.175 25.974 ;
     RECT  1.147 35.28 1.363 43.56 ;
     RECT  1.363 35.28 1.507 43.668 ;
     RECT  1.003 23.436 1.651 23.454 ;
     RECT  0.859 33.426 1.723 34.452 ;
     RECT  1.507 35.28 1.723 43.704 ;
     RECT  0.211 45.162 1.723 45.18 ;
     RECT  1.075 54.756 2.155 54.972 ;
     RECT  0.859 55.764 2.155 55.782 ;
     RECT  1.039 18.036 2.16 18.054 ;
     RECT  1.075 21.276 2.16 21.294 ;
     RECT  1.651 22.986 2.16 23.454 ;
     RECT  1.111 24.444 2.16 24.462 ;
     RECT  1.175 25.866 2.16 25.884 ;
     RECT  1.579 26.946 2.16 26.964 ;
     RECT  0.463 29.034 2.16 29.052 ;
     RECT  1.615 31.266 2.16 31.284 ;
     RECT  0.211 32.274 2.16 32.292 ;
     RECT  1.723 33.426 2.16 45.18 ;
     RECT  0.463 49.05 2.16 49.068 ;
     RECT  1.039 50.166 2.16 50.184 ;
     RECT  0.211 51.102 2.16 51.12 ;
     RECT  2.047 52.29 2.16 52.308 ;
     RECT  2.155 54.756 2.16 55.782 ;
     RECT  2.119 61.974 2.16 61.992 ;
     RECT  0.499 65.79 2.16 65.808 ;
     RECT  1.507 67.716 2.16 67.734 ;
     RECT  0.967 71.73 2.16 71.748 ;
     RECT  0.535 83.538 2.16 83.556 ;
     RECT  2.16 2.151 3.379 84.249 ;
     RECT  3.379 2.151 12.523 84.636 ;
     RECT  12.523 2.151 14.935 84.789 ;
     RECT  14.935 2.151 20.412 85.284 ;
     RECT  20.412 35.442 20.435 35.604 ;
     RECT  20.412 23.634 20.471 26.694 ;
     RECT  20.412 45.81 20.507 53.352 ;
     RECT  20.412 36.486 20.543 44.676 ;
     RECT  20.412 27.72 20.579 32.058 ;
     RECT  20.412 54.144 20.579 58.788 ;
     RECT  20.471 23.634 20.651 25.119 ;
     RECT  20.579 54.45 20.723 58.788 ;
     RECT  20.723 54.45 20.759 55.512 ;
     RECT  20.412 59.886 20.759 85.284 ;
     RECT  20.759 60.084 20.767 85.284 ;
     RECT  20.543 36.486 20.795 37.494 ;
     RECT  20.767 60.084 20.795 85.41 ;
     RECT  20.507 45.81 20.831 53.28 ;
     RECT  20.412 33.084 20.867 33.372 ;
     RECT  20.579 27.72 20.903 29.934 ;
     RECT  20.579 30.996 20.903 32.058 ;
     RECT  20.903 27.72 20.939 28.242 ;
     RECT  20.903 29.34 20.939 29.934 ;
     RECT  20.903 30.996 20.975 31.014 ;
     RECT  20.412 2.151 20.983 22.644 ;
     RECT  20.543 38.646 21.047 44.676 ;
     RECT  20.939 27.72 21.119 28.089 ;
     RECT  20.471 25.866 21.155 26.694 ;
     RECT  21.047 44.388 21.163 44.676 ;
     RECT  20.831 45.81 21.163 49.842 ;
     RECT  20.723 56.574 21.191 58.788 ;
     RECT  20.831 50.634 21.227 53.28 ;
     RECT  21.163 44.388 21.263 49.842 ;
     RECT  20.983 1.881 21.271 22.644 ;
     RECT  21.263 45.306 21.299 49.842 ;
     RECT  20.759 54.576 21.299 55.512 ;
     RECT  20.867 33.354 21.335 33.372 ;
     RECT  21.191 56.574 21.335 57.204 ;
     RECT  20.903 32.04 21.343 32.058 ;
     RECT  21.299 45.306 21.371 49.374 ;
     RECT  21.227 50.634 21.371 53.118 ;
     RECT  20.651 23.634 21.379 24.93 ;
     RECT  21.371 45.306 21.407 47.484 ;
     RECT  21.299 54.576 21.407 55.476 ;
     RECT  20.795 60.156 21.407 85.41 ;
     RECT  21.191 58.086 21.415 58.788 ;
     RECT  21.335 57.078 21.443 57.204 ;
     RECT  21.415 58.086 21.443 59.328 ;
     RECT  21.407 60.156 21.443 62.226 ;
     RECT  21.343 32.04 21.479 32.49 ;
     RECT  20.795 37.17 21.479 37.494 ;
     RECT  21.443 60.516 21.479 62.226 ;
     RECT  21.407 54.846 21.515 55.476 ;
     RECT  21.443 58.158 21.515 59.328 ;
     RECT  21.271 1.881 21.523 22.806 ;
     RECT  21.379 23.634 21.551 25.119 ;
     RECT  21.119 27.756 21.551 28.089 ;
     RECT  21.479 37.17 21.551 37.422 ;
     RECT  21.407 45.306 21.551 45.99 ;
     RECT  21.407 46.746 21.551 47.484 ;
     RECT  21.551 28.026 21.587 28.089 ;
     RECT  21.047 38.646 21.587 43.326 ;
     RECT  21.443 57.186 21.587 57.204 ;
     RECT  21.551 23.634 21.623 24.93 ;
     RECT  21.155 26.028 21.623 26.694 ;
     RECT  21.551 37.251 21.623 37.422 ;
     RECT  21.551 46.818 21.623 47.484 ;
     RECT  21.371 48.816 21.623 49.374 ;
     RECT  21.515 58.158 21.623 58.788 ;
     RECT  21.587 28.026 21.659 28.044 ;
     RECT  21.587 38.646 21.659 39.654 ;
     RECT  21.479 32.472 21.695 32.49 ;
     RECT  20.435 35.442 21.695 35.46 ;
     RECT  21.371 50.634 21.695 51.966 ;
     RECT  21.479 60.516 21.695 61.758 ;
     RECT  21.623 23.634 21.731 23.652 ;
     RECT  21.263 44.388 21.731 44.514 ;
     RECT  20.939 29.916 21.883 29.934 ;
     RECT  21.523 1.836 22.171 22.806 ;
     RECT  21.371 52.758 22.207 53.118 ;
     RECT  21.515 55.458 22.207 55.476 ;
     RECT  21.991 56.268 22.207 56.286 ;
     RECT  21.623 24.678 22.279 24.93 ;
     RECT  21.623 26.028 22.279 26.154 ;
     RECT  21.883 29.268 22.315 29.934 ;
     RECT  22.171 1.116 22.464 22.806 ;
     RECT  22.279 24.678 22.464 26.154 ;
     RECT  22.315 28.611 22.464 29.934 ;
     RECT  22.099 32.544 22.464 32.562 ;
     RECT  22.243 34.776 22.464 35.028 ;
     RECT  21.623 37.404 22.464 37.422 ;
     RECT  21.659 38.988 22.464 39.006 ;
     RECT  21.587 40.716 22.464 42.282 ;
     RECT  21.587 43.038 22.464 43.326 ;
     RECT  21.731 44.496 22.464 44.514 ;
     RECT  21.623 47.196 22.464 47.484 ;
     RECT  21.623 48.816 22.464 48.96 ;
     RECT  21.695 50.634 22.464 51.66 ;
     RECT  22.207 52.758 22.464 54.36 ;
     RECT  22.207 55.458 22.464 56.286 ;
     RECT  21.623 58.158 22.464 58.176 ;
     RECT  21.695 60.966 22.464 61.758 ;
     RECT  21.407 62.982 22.464 85.41 ;
     RECT  22.464 1.116 22.855 85.41 ;
     RECT  22.855 1.071 22.999 85.41 ;
     RECT  22.999 1.026 24.151 85.41 ;
     RECT  24.151 1.026 24.935 85.518 ;
     RECT  24.935 1.026 25.799 85.41 ;
     RECT  25.447 0.144 26.419 0.162 ;
     RECT  26.419 0.144 26.663 0.234 ;
     RECT  25.799 1.026 26.815 85.374 ;
     RECT  26.663 0.144 26.879 0.162 ;
     RECT  26.815 1.026 26.951 85.644 ;
     RECT  26.951 1.026 27.275 85.599 ;
     RECT  27.275 1.026 27.491 85.518 ;
     RECT  27.571 0.216 27.643 0.234 ;
     RECT  27.643 0.144 27.815 0.234 ;
     RECT  28.651 86.238 28.687 86.256 ;
     RECT  28.687 86.238 28.795 86.328 ;
     RECT  28.795 86.166 28.931 86.328 ;
     RECT  28.931 86.238 29.471 86.328 ;
     RECT  27.815 0.144 30.343 0.162 ;
     RECT  27.491 1.026 30.343 85.374 ;
     RECT  30.379 86.238 30.415 86.256 ;
     RECT  30.343 0.144 30.479 85.374 ;
     RECT  30.415 86.238 30.515 86.328 ;
     RECT  30.479 1.026 30.775 85.374 ;
     RECT  30.479 0.144 31.271 0.234 ;
     RECT  31.271 0.144 31.451 0.162 ;
     RECT  30.775 1.026 31.711 85.518 ;
     RECT  31.711 1.026 32.279 85.599 ;
     RECT  32.279 1.026 33.323 85.518 ;
     RECT  33.323 1.071 33.331 85.518 ;
     RECT  33.403 0.144 34.303 0.162 ;
     RECT  33.331 1.071 34.583 85.599 ;
     RECT  34.583 1.071 34.979 85.518 ;
     RECT  34.303 0.144 35.095 0.279 ;
     RECT  35.095 0.036 35.231 0.279 ;
     RECT  34.979 64.674 35.447 85.518 ;
     RECT  35.231 0.036 35.959 0.054 ;
     RECT  35.959 0.036 36.167 0.162 ;
     RECT  35.447 64.674 36.599 85.329 ;
     RECT  36.167 0.036 36.931 0.054 ;
     RECT  36.599 64.674 37.319 85.284 ;
     RECT  36.931 0.036 37.435 0.162 ;
     RECT  37.319 64.674 37.463 84.294 ;
     RECT  37.463 64.674 37.787 84.249 ;
     RECT  37.435 0.036 37.939 0.234 ;
     RECT  34.979 1.071 37.939 63.528 ;
     RECT  37.787 65.25 38.615 84.249 ;
     RECT  38.615 65.601 40.135 84.249 ;
     RECT  40.135 65.601 40.343 84.33 ;
     RECT  37.319 85.194 40.523 85.284 ;
     RECT  40.855 86.31 40.891 86.328 ;
     RECT  40.891 86.238 40.991 86.328 ;
     RECT  40.523 85.266 42.071 85.284 ;
     RECT  40.343 65.601 46.759 84.249 ;
     RECT  46.759 65.601 48.263 84.366 ;
     RECT  48.263 65.601 55.399 84.249 ;
     RECT  37.939 0.036 57.479 63.528 ;
     RECT  55.399 65.556 58.415 84.249 ;
     RECT  57.479 0.036 58.819 0.09 ;
     RECT  57.479 0.846 58.819 63.528 ;
     RECT  58.819 0.036 58.919 63.528 ;
     RECT  58.919 0.036 60.331 0.054 ;
     RECT  58.919 0.846 60.331 63.528 ;
     RECT  60.331 0.036 61.331 63.528 ;
     RECT  61.331 0.036 66.883 0.09 ;
     RECT  61.331 0.846 66.883 63.528 ;
     RECT  66.883 0.036 67.919 63.528 ;
     RECT  67.919 0.036 70.555 0.09 ;
     RECT  67.919 0.846 70.555 63.528 ;
     RECT  70.555 0.036 70.655 63.528 ;
     RECT  70.655 0.036 72.391 0.09 ;
     RECT  70.655 0.846 72.391 63.528 ;
     RECT  72.391 0.036 72.563 63.528 ;
     RECT  72.563 0.036 73.319 0.594 ;
     RECT  72.563 1.458 74.723 63.528 ;
     RECT  73.319 0.036 75.227 0.054 ;
     RECT  74.723 1.692 86.927 63.528 ;
     RECT  86.927 2.151 117.288 63.528 ;
     RECT  117.288 2.151 117.419 22.419 ;
     RECT  117.288 26.874 117.419 26.892 ;
     RECT  117.419 2.151 117.959 22.374 ;
     RECT  117.288 23.4 117.959 23.418 ;
     RECT  117.959 22.356 117.995 22.374 ;
     RECT  117.288 36.792 118.039 62.694 ;
     RECT  117.288 28.458 118.283 29.052 ;
     RECT  117.288 33.588 118.579 35.874 ;
     RECT  118.039 36.792 118.579 63 ;
     RECT  117.959 2.151 119.34 21.528 ;
     RECT  118.283 28.458 119.34 28.476 ;
     RECT  117.288 30.186 119.34 30.204 ;
     RECT  118.579 33.588 119.34 63 ;
     RECT  58.415 65.601 119.34 84.249 ;
     RECT  119.34 2.151 140.4 84.249 ;
     RECT  140.4 52.146 141.359 52.164 ;
    LAYER M3 ;
     RECT  59.868 0.031 60.426 0.067 ;
     RECT  42.264 0.067 42.57 0.103 ;
     RECT  35.1 0.031 35.118 0.108 ;
     RECT  37.548 0.067 37.566 0.108 ;
     RECT  41.256 0.067 41.274 0.108 ;
     RECT  42.264 0.103 42.858 0.108 ;
     RECT  57.06 0.103 57.078 0.108 ;
     RECT  58.212 0.067 58.23 0.108 ;
     RECT  59.868 0.067 60.966 0.108 ;
     RECT  24.48 0.108 61.218 0.139 ;
     RECT  66.528 0.108 67.842 0.187 ;
     RECT  71.82 0.067 71.838 0.187 ;
     RECT  24.48 0.139 61.326 0.235 ;
     RECT  23.04 0.187 23.058 0.283 ;
     RECT  63.288 0.187 63.306 0.283 ;
     RECT  66.528 0.187 67.914 0.284 ;
     RECT  62.712 0.283 63.306 0.461 ;
     RECT  23.04 0.283 23.31 0.571 ;
     RECT  73.584 0.139 73.602 0.571 ;
     RECT  64.98 0.379 64.998 0.763 ;
     RECT  65.736 0.187 65.754 0.763 ;
     RECT  70.488 0.108 71.082 0.811 ;
     RECT  71.82 0.187 72.414 0.811 ;
     RECT  64.98 0.763 65.754 0.859 ;
     RECT  24.372 0.235 61.326 0.877 ;
     RECT  70.488 0.811 72.414 0.877 ;
     RECT  70.488 0.877 72.486 0.949 ;
     RECT  70.128 0.949 72.486 0.985 ;
     RECT  23.04 0.571 23.346 1.021 ;
     RECT  70.128 0.985 72.558 1.021 ;
     RECT  66.528 0.284 67.842 1.051 ;
     RECT  22.248 0.811 22.266 1.066 ;
     RECT  23.004 1.021 23.346 1.066 ;
     RECT  64.764 0.859 65.754 1.099 ;
     RECT  22.248 1.066 23.346 1.111 ;
     RECT  62.82 0.461 63.306 1.387 ;
     RECT  62.676 1.387 63.306 1.453 ;
     RECT  75.204 0.031 75.222 1.453 ;
     RECT  62.676 1.453 63.378 1.483 ;
     RECT  22.176 1.111 23.346 1.579 ;
     RECT  64.296 1.099 65.754 1.579 ;
     RECT  66.528 1.051 68.058 1.579 ;
     RECT  22.104 1.579 23.346 1.606 ;
     RECT  24.372 0.877 61.758 1.606 ;
     RECT  22.104 1.606 61.758 1.723 ;
     RECT  22.104 1.723 61.794 1.759 ;
     RECT  62.568 1.483 63.378 1.759 ;
     RECT  73.296 0.571 73.602 1.819 ;
     RECT  74.7 1.453 75.222 1.819 ;
     RECT  22.104 1.759 63.378 1.831 ;
     RECT  64.296 1.579 68.058 1.867 ;
     RECT  21.528 1.831 63.378 1.876 ;
     RECT  69.912 1.021 72.558 1.921 ;
     RECT  73.296 1.819 75.222 1.921 ;
     RECT  69.912 1.921 75.222 2.101 ;
     RECT  20.988 1.876 63.378 2.191 ;
     RECT  64.296 1.867 68.418 2.191 ;
     RECT  78.015 2.143 78.105 2.191 ;
     RECT  88.815 2.143 88.905 2.191 ;
     RECT  99.615 2.143 99.705 2.191 ;
     RECT  110.415 2.143 110.505 2.191 ;
     RECT  77.904 2.191 78.21 2.237 ;
     RECT  88.704 2.191 89.01 2.237 ;
     RECT  99.504 2.191 99.81 2.237 ;
     RECT  110.304 2.191 110.61 2.237 ;
     RECT  114.588 2.059 114.606 2.237 ;
     RECT  20.988 2.191 68.634 2.255 ;
     RECT  83.415 2.143 83.505 2.299 ;
     RECT  21.096 2.255 68.634 2.347 ;
     RECT  69.372 2.101 75.222 2.347 ;
     RECT  21.096 2.347 75.222 2.371 ;
     RECT  2.415 2.143 2.505 2.413 ;
     RECT  7.815 2.143 7.905 2.413 ;
     RECT  13.215 2.143 13.305 2.413 ;
     RECT  18.615 2.143 18.705 2.413 ;
     RECT  78.015 2.237 78.21 2.413 ;
     RECT  83.415 2.299 83.574 2.413 ;
     RECT  88.815 2.237 89.01 2.413 ;
     RECT  94.215 2.143 94.305 2.413 ;
     RECT  99.615 2.237 99.81 2.413 ;
     RECT  105.015 2.143 105.105 2.413 ;
     RECT  110.415 2.237 110.61 2.413 ;
     RECT  115.815 2.143 115.905 2.413 ;
     RECT  121.215 2.143 121.305 2.413 ;
     RECT  126.615 2.143 126.705 2.413 ;
     RECT  132.015 2.143 132.105 2.413 ;
     RECT  137.415 2.143 137.505 2.413 ;
     RECT  78.015 2.413 78.297 2.461 ;
     RECT  21.096 2.371 75.438 2.497 ;
     RECT  21.096 2.497 75.474 2.539 ;
     RECT  18.615 2.413 18.897 2.725 ;
     RECT  6.012 2.299 6.03 2.731 ;
     RECT  94.215 2.413 94.497 2.731 ;
     RECT  6.012 2.731 6.246 2.759 ;
     RECT  18.504 2.725 18.897 2.765 ;
     RECT  78.015 2.461 78.642 2.803 ;
     RECT  6.228 2.759 6.246 2.861 ;
     RECT  21.096 2.539 75.546 2.875 ;
     RECT  81.504 2.371 81.522 2.875 ;
     RECT  80.388 2.641 80.406 2.911 ;
     RECT  81.288 2.875 81.522 2.911 ;
     RECT  78.015 2.803 78.678 3.037 ;
     RECT  18.615 2.765 18.897 3.073 ;
     RECT  21.096 2.875 75.618 3.136 ;
     RECT  88.815 2.413 89.097 3.145 ;
     RECT  80.388 2.911 81.522 3.181 ;
     RECT  21.096 3.136 75.654 3.197 ;
     RECT  77.616 3.037 78.822 3.271 ;
     RECT  21.096 3.197 75.294 3.299 ;
     RECT  83.415 2.413 83.697 3.307 ;
     RECT  117.288 2.059 117.306 3.307 ;
     RECT  118.368 3.037 118.386 3.307 ;
     RECT  76.968 3.271 78.822 3.343 ;
     RECT  79.812 3.181 81.522 3.343 ;
     RECT  121.215 2.413 121.497 3.343 ;
     RECT  88.815 3.145 89.514 3.403 ;
     RECT  86.076 2.335 86.094 3.415 ;
     RECT  86.904 1.687 86.922 3.415 ;
     RECT  76.968 3.343 81.774 3.451 ;
     RECT  83.415 3.307 84.402 3.451 ;
     RECT  88.815 3.403 89.946 3.451 ;
     RECT  90.792 2.497 90.81 3.451 ;
     RECT  76.968 3.451 84.402 3.479 ;
     RECT  92.304 2.533 92.322 3.541 ;
     RECT  76.968 3.479 79.218 3.569 ;
     RECT  86.076 3.415 86.922 3.569 ;
     RECT  92.304 3.541 92.538 3.569 ;
     RECT  117.288 3.307 118.386 3.577 ;
     RECT  117.288 3.577 118.422 3.613 ;
     RECT  21.096 3.299 75.222 3.629 ;
     RECT  86.292 3.569 86.922 3.649 ;
     RECT  87.804 2.839 87.822 3.649 ;
     RECT  86.292 3.649 87.822 3.677 ;
     RECT  114.588 3.547 114.606 3.677 ;
     RECT  86.652 3.677 87.822 3.685 ;
     RECT  88.815 3.451 90.81 3.685 ;
     RECT  120.528 3.343 121.497 3.721 ;
     RECT  80.388 3.479 84.402 3.749 ;
     RECT  21.096 3.629 74.754 3.811 ;
     RECT  85.392 3.811 85.41 3.835 ;
     RECT  80.388 3.749 82.638 3.839 ;
     RECT  83.415 3.749 84.402 3.847 ;
     RECT  85.176 3.835 85.41 3.847 ;
     RECT  117.288 3.613 118.962 3.847 ;
     RECT  120.024 3.721 121.497 3.847 ;
     RECT  80.388 3.839 81.378 3.875 ;
     RECT  18.615 3.073 19.026 3.877 ;
     RECT  18.036 3.877 19.026 3.917 ;
     RECT  94.215 2.731 94.914 3.919 ;
     RECT  80.388 3.875 81.234 3.983 ;
     RECT  86.652 3.685 90.882 3.991 ;
     RECT  86.652 3.991 91.098 4.109 ;
     RECT  96.3 3.991 96.318 4.117 ;
     RECT  80.388 3.983 81.054 4.181 ;
     RECT  96.3 4.117 96.606 4.217 ;
     RECT  20.556 3.811 74.754 4.219 ;
     RECT  80.388 4.181 80.982 4.225 ;
     RECT  82.116 3.839 82.638 4.253 ;
     RECT  94.215 3.919 95.13 4.261 ;
     RECT  96.3 4.217 96.534 4.387 ;
     RECT  87.984 4.109 90.99 4.451 ;
     RECT  77.544 3.569 79.218 4.531 ;
     RECT  80.244 4.225 80.982 4.531 ;
     RECT  96.12 4.387 96.534 4.541 ;
     RECT  82.188 4.253 82.638 4.621 ;
     RECT  83.415 3.847 85.41 4.621 ;
     RECT  19.944 4.219 74.754 4.649 ;
     RECT  19.944 4.649 73.242 4.721 ;
     RECT  13.215 2.413 13.497 4.792 ;
     RECT  72.615 4.721 73.242 4.793 ;
     RECT  74.052 4.649 74.754 4.801 ;
     RECT  77.544 4.531 80.982 4.801 ;
     RECT  13.104 4.792 13.497 4.829 ;
     RECT  19.944 4.721 71.694 4.829 ;
     RECT  82.188 4.621 85.41 4.919 ;
     RECT  86.652 4.109 87.21 4.927 ;
     RECT  84.456 4.919 85.41 4.991 ;
     RECT  14.724 3.613 14.742 4.999 ;
     RECT  74.052 4.801 74.79 5.027 ;
     RECT  82.188 4.919 83.697 5.035 ;
     RECT  74.052 5.027 74.754 5.099 ;
     RECT  77.508 4.801 80.982 5.099 ;
     RECT  82.044 5.035 83.697 5.099 ;
     RECT  86.544 4.927 87.21 5.099 ;
     RECT  18.576 3.917 19.026 5.161 ;
     RECT  19.944 4.829 71.658 5.161 ;
     RECT  84.528 4.991 85.41 5.189 ;
     RECT  87.984 4.451 90.09 5.189 ;
     RECT  76.392 4.729 76.41 5.197 ;
     RECT  77.508 5.099 78.858 5.197 ;
     RECT  79.668 5.099 80.982 5.197 ;
     RECT  79.668 5.197 81.054 5.213 ;
     RECT  79.74 5.213 81.054 5.269 ;
     RECT  82.044 5.099 82.602 5.269 ;
     RECT  79.74 5.269 81.126 5.305 ;
     RECT  81.864 5.269 82.602 5.305 ;
     RECT  76.392 5.197 78.858 5.333 ;
     RECT  79.74 5.305 82.602 5.333 ;
     RECT  90.972 4.451 90.99 5.341 ;
     RECT  14.688 4.999 14.742 5.371 ;
     RECT  76.392 5.333 76.77 5.459 ;
     RECT  79.848 5.333 82.602 5.459 ;
     RECT  14.688 5.371 14.85 5.501 ;
     RECT  72.615 4.793 73.062 5.539 ;
     RECT  79.848 5.459 79.866 5.567 ;
     RECT  80.784 5.459 82.602 5.603 ;
     RECT  84.6 5.189 85.41 5.611 ;
     RECT  90.612 5.341 90.99 5.773 ;
     RECT  14.688 5.501 14.742 5.845 ;
     RECT  18.576 5.161 71.658 5.845 ;
     RECT  75.168 5.809 75.186 5.845 ;
     RECT  18.576 5.845 71.694 5.873 ;
     RECT  63.216 5.873 71.694 5.881 ;
     RECT  72.615 5.539 73.134 5.881 ;
     RECT  75.132 5.845 75.186 5.971 ;
     RECT  18.576 5.873 62.298 5.999 ;
     RECT  18.576 5.999 57.366 6.029 ;
     RECT  63.216 5.881 73.134 6.043 ;
     RECT  17.424 4.261 17.442 6.079 ;
     RECT  81.468 5.603 82.602 6.107 ;
     RECT  37.224 6.029 57.366 6.125 ;
     RECT  63.216 6.043 73.17 6.151 ;
     RECT  76.752 5.459 76.77 6.151 ;
     RECT  77.508 5.333 78.858 6.151 ;
     RECT  92.52 3.569 92.538 6.151 ;
     RECT  37.26 6.125 57.366 6.179 ;
     RECT  83.415 5.099 83.697 6.241 ;
     RECT  76.752 6.151 79.362 6.269 ;
     RECT  63.216 6.151 73.242 6.305 ;
     RECT  83.16 6.241 83.697 6.313 ;
     RECT  83.16 6.313 83.754 6.331 ;
     RECT  83.16 6.331 83.826 6.385 ;
     RECT  84.6 5.611 86.022 6.385 ;
     RECT  87.156 5.099 87.21 6.421 ;
     RECT  87.984 5.189 89.442 6.421 ;
     RECT  80.28 6.421 80.298 6.427 ;
     RECT  80.28 6.427 80.478 6.523 ;
     RECT  81.468 6.107 82.35 6.523 ;
     RECT  15.876 5.611 15.894 6.547 ;
     RECT  99.615 2.413 99.897 6.547 ;
     RECT  63.216 6.305 70.722 6.619 ;
     RECT  92.34 6.151 92.538 6.619 ;
     RECT  93.456 5.341 93.474 6.619 ;
     RECT  76.932 6.269 79.362 6.655 ;
     RECT  63.18 6.619 70.722 6.667 ;
     RECT  71.496 6.305 73.242 6.691 ;
     RECT  76.932 6.655 79.434 6.691 ;
     RECT  80.28 6.523 82.35 6.691 ;
     RECT  58.104 5.999 62.298 6.763 ;
     RECT  63.036 6.667 70.722 6.763 ;
     RECT  71.496 6.691 73.602 6.781 ;
     RECT  75.132 5.971 75.258 6.781 ;
     RECT  58.104 6.763 70.722 6.809 ;
     RECT  76.932 6.691 82.35 6.809 ;
     RECT  75.132 6.781 75.87 6.811 ;
     RECT  87.156 6.421 89.442 6.811 ;
     RECT  37.26 6.179 42.786 6.845 ;
     RECT  83.16 6.385 86.022 6.851 ;
     RECT  14.292 5.845 14.742 6.853 ;
     RECT  15.876 6.547 16.542 6.853 ;
     RECT  71.496 6.781 73.998 6.853 ;
     RECT  74.916 6.811 75.87 6.853 ;
     RECT  87.156 6.811 89.73 6.853 ;
     RECT  96.12 4.541 96.138 6.853 ;
     RECT  96.984 5.809 97.002 6.853 ;
     RECT  98.352 3.649 98.37 6.853 ;
     RECT  14.292 6.853 14.814 6.881 ;
     RECT  96.984 6.853 97.182 6.881 ;
     RECT  92.34 6.619 93.474 6.889 ;
     RECT  86.76 6.853 89.73 6.907 ;
     RECT  90.612 5.773 91.17 6.907 ;
     RECT  18.576 6.029 36.414 6.961 ;
     RECT  37.26 6.845 41.958 6.961 ;
     RECT  43.56 6.179 57.366 6.961 ;
     RECT  58.104 6.809 59.634 6.961 ;
     RECT  86.76 6.907 91.17 7.003 ;
     RECT  110.415 2.413 110.697 7.045 ;
     RECT  63.828 6.809 70.722 7.051 ;
     RECT  71.496 6.853 75.87 7.051 ;
     RECT  99.615 6.547 100.026 7.051 ;
     RECT  43.56 6.961 59.634 7.079 ;
     RECT  76.932 6.809 81.99 7.079 ;
     RECT  110.304 7.045 110.697 7.085 ;
     RECT  63.828 7.051 76.194 7.087 ;
     RECT  76.932 7.079 81.954 7.087 ;
     RECT  83.196 6.851 86.022 7.087 ;
     RECT  86.76 7.003 91.242 7.087 ;
     RECT  99.504 7.051 100.026 7.088 ;
     RECT  91.98 6.889 93.474 7.123 ;
     RECT  94.215 4.261 95.166 7.123 ;
     RECT  43.56 7.079 49.158 7.151 ;
     RECT  63.828 7.087 81.954 7.151 ;
     RECT  10.944 6.511 10.962 7.159 ;
     RECT  11.736 6.961 11.754 7.159 ;
     RECT  83.196 7.087 91.242 7.159 ;
     RECT  91.98 7.123 95.166 7.159 ;
     RECT  117.288 3.847 121.497 7.195 ;
     RECT  18.576 6.961 41.958 7.229 ;
     RECT  15.876 6.853 16.614 7.231 ;
     RECT  17.388 6.079 17.442 7.231 ;
     RECT  25.308 7.229 41.958 7.373 ;
     RECT  114.588 7.051 114.606 7.373 ;
     RECT  96.12 6.853 96.21 7.429 ;
     RECT  42.732 6.845 42.786 7.465 ;
     RECT  43.56 7.151 46.71 7.465 ;
     RECT  98.352 6.853 98.478 7.483 ;
     RECT  26.208 7.373 41.958 7.493 ;
     RECT  50.004 7.079 59.634 7.531 ;
     RECT  60.516 6.809 63.018 7.531 ;
     RECT  26.244 7.493 41.958 7.619 ;
     RECT  26.28 7.619 41.958 7.627 ;
     RECT  50.004 7.531 63.018 7.699 ;
     RECT  26.28 7.627 41.994 7.727 ;
     RECT  13.215 4.829 13.497 7.771 ;
     RECT  95.904 7.429 96.21 7.861 ;
     RECT  97.164 6.881 97.182 7.861 ;
     RECT  50.004 7.699 63.054 7.889 ;
     RECT  26.784 7.727 41.994 7.897 ;
     RECT  42.732 7.465 46.71 7.897 ;
     RECT  47.556 7.151 49.158 7.915 ;
     RECT  95.904 7.861 97.182 7.915 ;
     RECT  98.172 7.483 98.478 7.915 ;
     RECT  63.864 7.151 81.954 7.933 ;
     RECT  83.196 7.159 95.166 7.933 ;
     RECT  95.904 7.915 98.478 7.933 ;
     RECT  47.556 7.915 49.194 7.969 ;
     RECT  50.004 7.889 63.018 7.969 ;
     RECT  26.784 7.897 46.71 8.005 ;
     RECT  47.556 7.969 63.018 8.005 ;
     RECT  26.784 8.005 63.018 8.033 ;
     RECT  83.196 7.933 98.478 8.041 ;
     RECT  100.98 7.969 100.998 8.041 ;
     RECT  28.404 8.033 63.018 8.159 ;
     RECT  83.196 8.041 98.55 8.203 ;
     RECT  83.196 8.203 98.766 8.239 ;
     RECT  99.615 7.088 100.026 8.239 ;
     RECT  100.908 8.041 100.998 8.239 ;
     RECT  63.864 7.933 82.026 8.275 ;
     RECT  83.196 8.239 100.026 8.275 ;
     RECT  18.576 7.229 24.57 8.303 ;
     RECT  28.764 8.159 63.018 8.671 ;
     RECT  63.864 8.275 100.026 8.671 ;
     RECT  28.764 8.671 100.026 8.827 ;
     RECT  100.908 8.239 101.718 8.827 ;
     RECT  28.764 8.827 101.718 8.909 ;
     RECT  50.436 8.909 101.718 8.969 ;
     RECT  10.152 6.619 10.17 9.121 ;
     RECT  12.96 7.771 13.497 9.121 ;
     RECT  50.76 8.969 101.718 9.122 ;
     RECT  23.868 8.303 24.57 9.259 ;
     RECT  25.308 7.373 25.398 9.259 ;
     RECT  50.796 9.122 101.718 9.349 ;
     RECT  12.852 9.121 13.497 9.391 ;
     RECT  50.796 9.349 101.79 9.391 ;
     RECT  7.815 2.413 8.097 9.481 ;
     RECT  9.144 9.391 9.162 9.481 ;
     RECT  10.044 9.121 10.17 9.481 ;
     RECT  10.944 7.159 11.754 9.481 ;
     RECT  28.764 8.909 49.698 9.485 ;
     RECT  28.836 9.485 49.698 9.509 ;
     RECT  50.796 9.391 102.798 9.509 ;
     RECT  12.852 9.391 13.626 9.589 ;
     RECT  15.876 7.231 17.442 9.625 ;
     RECT  28.836 9.509 29.862 9.629 ;
     RECT  30.6 9.509 49.698 9.643 ;
     RECT  15.876 9.625 17.55 9.691 ;
     RECT  18.576 8.303 23.022 9.751 ;
     RECT  23.868 9.259 25.398 9.751 ;
     RECT  26.784 8.033 27.378 9.751 ;
     RECT  12.564 9.589 13.626 9.787 ;
     RECT  14.364 6.881 14.814 9.787 ;
     RECT  18.576 9.751 25.398 9.787 ;
     RECT  15.876 9.691 17.694 9.823 ;
     RECT  18.576 9.787 25.938 9.823 ;
     RECT  15.876 9.823 25.938 9.859 ;
     RECT  10.044 9.481 11.754 9.872 ;
     RECT  12.564 9.787 14.814 9.872 ;
     RECT  26.784 9.751 27.702 9.895 ;
     RECT  5.796 9.517 5.814 9.931 ;
     RECT  7.815 9.481 9.162 9.931 ;
     RECT  10.044 9.872 14.814 9.931 ;
     RECT  15.876 9.859 26.046 9.931 ;
     RECT  26.784 9.895 27.918 9.931 ;
     RECT  4.644 7.663 4.662 10.129 ;
     RECT  5.472 9.931 6.426 10.129 ;
     RECT  50.796 9.509 102.654 10.165 ;
     RECT  30.6 9.643 49.806 10.171 ;
     RECT  50.688 10.165 102.654 10.171 ;
     RECT  7.815 9.931 26.046 10.201 ;
     RECT  26.784 9.931 28.062 10.201 ;
     RECT  30.6 10.171 102.654 10.267 ;
     RECT  4.644 10.129 6.534 10.399 ;
     RECT  7.815 10.201 28.062 10.399 ;
     RECT  4.644 10.399 28.062 10.411 ;
     RECT  28.836 9.629 29.79 10.411 ;
     RECT  30.528 10.267 102.654 10.411 ;
     RECT  4.644 10.411 28.098 10.471 ;
     RECT  28.836 10.411 102.654 10.471 ;
     RECT  4.644 10.471 102.654 10.589 ;
     RECT  4.644 10.589 102.438 10.661 ;
     RECT  3.852 10.831 3.87 10.843 ;
     RECT  3.564 10.843 3.87 10.867 ;
     RECT  4.644 10.661 6.426 10.867 ;
     RECT  2.415 2.413 2.697 10.975 ;
     RECT  3.564 10.867 6.426 10.975 ;
     RECT  2.415 10.975 6.426 11.443 ;
     RECT  7.164 10.661 102.438 11.443 ;
     RECT  2.415 11.443 102.438 13.027 ;
     RECT  2.415 13.027 102.906 13.441 ;
     RECT  110.415 7.085 110.697 13.963 ;
     RECT  110.304 13.963 110.697 14.009 ;
     RECT  2.232 13.441 102.906 14.341 ;
     RECT  2.232 14.341 103.302 14.549 ;
     RECT  2.232 14.549 103.122 14.819 ;
     RECT  2.232 14.819 102.402 15.601 ;
     RECT  2.232 15.601 102.69 16.105 ;
     RECT  110.415 14.009 110.697 16.123 ;
     RECT  2.232 16.105 102.762 16.141 ;
     RECT  110.304 16.123 110.697 16.169 ;
     RECT  114.588 16.123 114.606 16.301 ;
     RECT  2.232 16.141 102.834 16.349 ;
     RECT  2.232 16.349 102.654 17.069 ;
     RECT  103.428 16.951 103.446 17.069 ;
     RECT  110.415 16.169 110.697 17.311 ;
     RECT  110.304 17.311 110.697 17.357 ;
     RECT  117.288 7.195 121.554 17.419 ;
     RECT  114.588 17.323 114.606 17.453 ;
     RECT  2.232 17.069 102.582 18.193 ;
     RECT  2.232 18.193 103.122 18.455 ;
     RECT  63.288 18.455 103.122 18.563 ;
     RECT  116.892 17.419 121.554 18.571 ;
     RECT  2.232 18.455 62.55 18.689 ;
     RECT  70.704 18.563 103.122 18.689 ;
     RECT  2.232 18.689 51.297 18.725 ;
     RECT  63.288 18.563 69.894 18.725 ;
     RECT  63.288 18.725 69.786 18.845 ;
     RECT  70.704 18.689 73.782 18.893 ;
     RECT  74.628 18.689 101.466 18.959 ;
     RECT  63.288 18.845 69.282 19.031 ;
     RECT  2.232 18.725 46.206 19.04 ;
     RECT  2.232 19.04 45.99 19.085 ;
     RECT  47.052 18.725 51.297 19.139 ;
     RECT  2.232 19.085 45.897 19.265 ;
     RECT  47.052 19.139 50.274 19.265 ;
     RECT  74.628 18.959 100.638 19.277 ;
     RECT  26.1 19.265 45.897 19.301 ;
     RECT  74.628 19.277 99.897 19.301 ;
     RECT  92.088 19.301 99.897 19.325 ;
     RECT  93.168 19.325 99.897 19.337 ;
     RECT  101.448 18.959 101.466 19.337 ;
     RECT  34.668 19.301 45.897 19.373 ;
     RECT  52.236 18.689 62.55 19.373 ;
     RECT  100.62 19.277 100.638 19.373 ;
     RECT  34.668 19.373 36.126 19.409 ;
     RECT  47.052 19.265 50.166 19.409 ;
     RECT  36.972 19.373 45.897 19.499 ;
     RECT  74.628 19.301 91.314 19.499 ;
     RECT  92.088 19.325 92.394 19.499 ;
     RECT  93.168 19.337 93.186 19.499 ;
     RECT  47.052 19.409 49.77 19.531 ;
     RECT  46.98 19.531 49.77 19.571 ;
     RECT  76.968 19.499 81.99 19.571 ;
     RECT  47.052 19.571 49.77 19.607 ;
     RECT  76.968 19.571 81.846 19.607 ;
     RECT  74.628 19.499 76.122 19.613 ;
     RECT  70.704 18.893 73.71 19.651 ;
     RECT  36.972 19.499 38.574 19.661 ;
     RECT  63.576 19.031 69.282 19.679 ;
     RECT  74.772 19.613 76.122 19.679 ;
     RECT  80.1 19.607 81.846 19.679 ;
     RECT  92.232 19.499 92.322 19.679 ;
     RECT  80.964 19.679 81.846 19.709 ;
     RECT  52.236 19.373 58.77 19.741 ;
     RECT  26.1 19.301 33.894 19.769 ;
     RECT  36.972 19.661 37.674 19.769 ;
     RECT  38.448 19.661 38.574 19.769 ;
     RECT  74.772 19.679 76.086 19.769 ;
     RECT  81.036 19.709 81.846 19.769 ;
     RECT  93.996 19.337 99.897 19.769 ;
     RECT  26.1 19.769 26.406 19.805 ;
     RECT  36.972 19.769 37.494 19.805 ;
     RECT  63.576 19.679 64.602 19.805 ;
     RECT  70.524 19.651 73.962 19.805 ;
     RECT  76.968 19.607 79.002 19.805 ;
     RECT  83.415 19.499 91.278 19.805 ;
     RECT  52.2 19.741 58.77 19.813 ;
     RECT  70.884 19.805 73.962 19.841 ;
     RECT  87.84 19.805 91.278 19.841 ;
     RECT  47.232 19.607 49.77 19.853 ;
     RECT  92.304 19.679 92.322 19.853 ;
     RECT  27.936 19.769 33.894 19.877 ;
     RECT  39.312 19.499 45.897 19.877 ;
     RECT  75.96 19.769 76.086 19.877 ;
     RECT  81.036 19.769 81.774 19.877 ;
     RECT  83.415 19.805 86.994 19.877 ;
     RECT  87.84 19.841 90.99 19.877 ;
     RECT  95.94 19.769 98.694 19.877 ;
     RECT  26.1 19.805 26.118 19.913 ;
     RECT  34.668 19.409 35.694 19.913 ;
     RECT  39.312 19.877 42.318 19.913 ;
     RECT  63.792 19.805 64.602 19.913 ;
     RECT  65.34 19.679 69.282 19.913 ;
     RECT  27.936 19.877 32.274 19.949 ;
     RECT  41.796 19.913 42.318 19.949 ;
     RECT  43.236 19.877 45.897 19.949 ;
     RECT  47.232 19.853 49.626 19.949 ;
     RECT  52.164 19.813 58.77 19.949 ;
     RECT  77.076 19.805 79.002 19.949 ;
     RECT  81.036 19.877 81.63 19.949 ;
     RECT  87.84 19.877 87.93 19.949 ;
     RECT  93.996 19.769 95.13 19.949 ;
     RECT  95.94 19.877 97.974 19.949 ;
     RECT  2.232 19.265 25.326 19.997 ;
     RECT  34.668 19.913 35.097 19.997 ;
     RECT  51.015 19.139 51.297 19.997 ;
     RECT  67.215 19.913 69.282 19.997 ;
     RECT  78.015 19.949 79.002 19.997 ;
     RECT  83.415 19.877 86.022 19.997 ;
     RECT  88.815 19.877 90.954 19.997 ;
     RECT  94.215 19.949 95.13 19.997 ;
     RECT  99.615 19.769 99.897 19.997 ;
     RECT  105.015 2.413 105.297 19.997 ;
     RECT  110.415 17.357 110.697 19.997 ;
     RECT  115.815 2.413 116.097 19.997 ;
     RECT  3.96 19.997 25.326 20.039 ;
     RECT  32.04 19.949 32.274 20.039 ;
     RECT  44.964 19.949 45.897 20.039 ;
     RECT  47.232 19.949 49.59 20.039 ;
     RECT  59.508 19.373 62.55 20.039 ;
     RECT  67.407 19.997 69.282 20.039 ;
     RECT  71.496 19.841 73.962 20.039 ;
     RECT  77.076 19.949 77.202 20.039 ;
     RECT  78.156 19.997 79.002 20.039 ;
     RECT  94.407 19.997 95.13 20.039 ;
     RECT  95.94 19.949 97.614 20.039 ;
     RECT  2.232 19.997 3.186 20.075 ;
     RECT  39.456 19.913 41.058 20.075 ;
     RECT  43.236 19.949 43.506 20.075 ;
     RECT  67.407 20.039 69.138 20.075 ;
     RECT  94.407 20.039 94.986 20.075 ;
     RECT  33.048 19.877 33.894 20.083 ;
     RECT  4.068 20.039 25.326 20.111 ;
     RECT  45 20.039 45.897 20.111 ;
     RECT  71.496 20.039 73.314 20.111 ;
     RECT  25.02 20.111 25.326 20.119 ;
     RECT  27.936 19.949 31.194 20.141 ;
     RECT  65.34 19.913 66.15 20.147 ;
     RECT  33.048 20.083 33.93 20.155 ;
     RECT  45.036 20.111 45.897 20.155 ;
     RECT  39.528 20.075 41.058 20.183 ;
     RECT  59.508 20.039 59.85 20.183 ;
     RECT  96.336 20.039 97.614 20.183 ;
     RECT  65.34 20.147 65.466 20.189 ;
     RECT  25.02 20.119 25.362 20.191 ;
     RECT  116.856 18.571 121.554 20.191 ;
     RECT  40.032 20.183 41.058 20.219 ;
     RECT  96.336 20.183 96.786 20.219 ;
     RECT  4.068 20.111 24.297 20.267 ;
     RECT  28.512 20.141 30.258 20.267 ;
     RECT  35.007 19.997 35.097 20.267 ;
     RECT  51.207 19.997 51.297 20.267 ;
     RECT  52.236 19.949 58.77 20.267 ;
     RECT  67.407 20.075 67.626 20.267 ;
     RECT  72.18 20.111 73.314 20.267 ;
     RECT  78.207 20.039 79.002 20.267 ;
     RECT  83.607 19.997 86.022 20.267 ;
     RECT  89.007 19.997 90.954 20.267 ;
     RECT  94.407 20.075 94.806 20.267 ;
     RECT  99.807 19.997 99.897 20.267 ;
     RECT  105.207 19.997 105.297 20.267 ;
     RECT  110.607 19.997 110.697 20.267 ;
     RECT  116.007 19.997 116.097 20.267 ;
     RECT  116.856 20.191 121.59 20.281 ;
     RECT  25.02 20.191 25.506 20.285 ;
     RECT  45.036 20.155 45.99 20.285 ;
     RECT  36.972 19.805 37.134 20.309 ;
     RECT  65.34 20.189 65.358 20.309 ;
     RECT  97.524 20.183 97.614 20.309 ;
     RECT  52.236 20.267 55.962 20.333 ;
     RECT  47.232 20.039 49.338 20.345 ;
     RECT  89.712 20.267 90.954 20.345 ;
     RECT  25.02 20.285 25.362 20.381 ;
     RECT  31.176 20.141 31.194 20.381 ;
     RECT  45.036 20.285 45.45 20.381 ;
     RECT  47.304 20.345 49.338 20.381 ;
     RECT  59.508 20.183 59.706 20.381 ;
     RECT  94.644 20.267 94.806 20.381 ;
     RECT  97.596 20.309 97.614 20.381 ;
     RECT  36.972 20.309 37.062 20.425 ;
     RECT  59.508 20.381 59.526 20.429 ;
     RECT  25.02 20.381 25.326 20.453 ;
     RECT  30.204 20.267 30.258 20.453 ;
     RECT  53.604 20.333 55.962 20.477 ;
     RECT  25.236 20.453 25.254 20.489 ;
     RECT  28.512 20.267 29.25 20.489 ;
     RECT  30.204 20.453 30.222 20.489 ;
     RECT  33.048 20.155 34.182 20.489 ;
     RECT  47.304 20.381 47.574 20.489 ;
     RECT  28.98 20.489 29.178 20.534 ;
     RECT  36.936 20.425 37.062 20.534 ;
     RECT  40.032 20.219 40.734 20.534 ;
     RECT  94.788 20.381 94.806 20.534 ;
     RECT  33.048 20.489 34.146 20.573 ;
     RECT  52.236 20.333 52.866 20.573 ;
     RECT  48.312 20.381 49.338 20.579 ;
     RECT  96.768 20.219 96.786 20.615 ;
     RECT  45.072 20.381 45.45 20.651 ;
     RECT  78.66 20.267 79.002 20.651 ;
     RECT  47.556 20.489 47.574 20.687 ;
     RECT  80.1 19.679 80.118 20.687 ;
     RECT  48.312 20.579 49.158 20.717 ;
     RECT  86.976 19.877 86.994 20.723 ;
     RECT  48.312 20.717 49.014 20.759 ;
     RECT  36.972 20.534 36.99 20.804 ;
     RECT  81.612 19.949 81.63 20.849 ;
     RECT  73.08 20.267 73.314 20.861 ;
     RECT  83.88 20.267 86.022 20.885 ;
     RECT  86.004 20.885 86.022 20.921 ;
     RECT  57.096 20.267 58.77 20.957 ;
     RECT  78.66 20.651 78.894 20.957 ;
     RECT  84.78 20.885 84.798 20.957 ;
     RECT  57.096 20.957 58.41 20.993 ;
     RECT  90.936 20.345 90.954 20.993 ;
     RECT  64.152 19.913 64.602 21.005 ;
     RECT  52.236 20.573 52.65 21.029 ;
     RECT  60.66 20.039 62.19 21.046 ;
     RECT  78.66 20.957 78.75 21.074 ;
     RECT  48.78 20.759 49.014 21.101 ;
     RECT  43.236 20.075 43.398 21.119 ;
     RECT  83.88 20.885 83.898 21.119 ;
     RECT  33.588 20.573 33.606 21.149 ;
     RECT  41.796 19.949 42.066 21.149 ;
     RECT  77.112 20.039 77.202 21.155 ;
     RECT  41.796 21.149 41.814 21.191 ;
     RECT  75.96 19.877 75.978 21.191 ;
     RECT  74.988 19.769 75.006 21.227 ;
     RECT  1.044 18.031 1.062 21.271 ;
     RECT  45.072 20.651 45.09 21.299 ;
     RECT  53.604 20.477 53.802 21.389 ;
     RECT  54.576 20.477 55.962 21.389 ;
     RECT  57.096 20.993 57.474 21.389 ;
     RECT  64.584 21.005 64.602 21.425 ;
     RECT  68.904 20.075 69.138 21.425 ;
     RECT  89.712 20.345 89.73 21.437 ;
     RECT  40.032 20.534 40.086 21.461 ;
     RECT  67.608 20.267 67.626 21.461 ;
     RECT  73.296 20.861 73.314 21.461 ;
     RECT  72.18 20.267 72.198 21.497 ;
     RECT  4.068 20.267 23.706 21.533 ;
     RECT  32.256 20.039 32.274 21.533 ;
     RECT  52.236 21.029 52.614 21.533 ;
     RECT  77.112 21.155 77.13 21.533 ;
     RECT  40.032 21.461 40.05 21.569 ;
     RECT  78.732 21.074 78.75 21.569 ;
     RECT  25.056 21.505 25.074 21.614 ;
     RECT  54.576 21.389 54.954 21.695 ;
     RECT  69.12 21.425 69.138 21.731 ;
     RECT  4.068 21.533 23.202 22.464 ;
     RECT  34.2 21.361 34.218 22.464 ;
     RECT  43.38 21.119 43.398 22.464 ;
     RECT  48.996 21.101 49.014 22.464 ;
     RECT  52.596 21.533 52.614 22.464 ;
     RECT  53.784 21.389 53.802 22.464 ;
     RECT  54.576 21.695 54.774 22.464 ;
     RECT  55.728 21.389 55.962 22.464 ;
     RECT  57.096 21.389 57.114 22.464 ;
     RECT  58.284 20.993 58.41 22.464 ;
     RECT  60.66 21.046 62.226 22.464 ;
     RECT  116.856 20.281 121.626 22.464 ;
     RECT  4.068 22.464 121.626 22.747 ;
     RECT  4.032 22.747 121.626 22.891 ;
     RECT  1.044 21.271 1.098 22.981 ;
     RECT  2.232 20.075 2.697 22.981 ;
     RECT  1.044 22.981 2.697 23.323 ;
     RECT  3.42 22.891 121.626 23.323 ;
     RECT  1.044 23.323 121.626 23.431 ;
     RECT  1.008 23.431 121.626 25.951 ;
     RECT  0.936 25.951 121.626 26.141 ;
     RECT  0.936 26.141 121.554 26.333 ;
     RECT  0.936 26.333 121.497 29.029 ;
     RECT  0.468 29.029 121.497 31.901 ;
     RECT  0.468 31.901 120.006 32.251 ;
     RECT  0.216 32.251 120.006 32.297 ;
     RECT  0.252 32.297 120.006 33.341 ;
     RECT  0.252 33.341 117.63 33.437 ;
     RECT  0.252 33.437 117.414 34.087 ;
     RECT  0.216 34.087 117.414 34.157 ;
     RECT  0.252 34.157 117.414 34.589 ;
     RECT  118.368 33.341 120.006 34.589 ;
     RECT  0.288 34.589 117.414 34.843 ;
     RECT  118.368 34.589 119.754 34.843 ;
     RECT  0.288 34.843 119.754 35.165 ;
     RECT  0.288 35.165 118.602 35.267 ;
     RECT  118.584 35.267 118.602 35.357 ;
     RECT  0.288 35.267 117.414 35.563 ;
     RECT  0.216 35.563 117.414 35.609 ;
     RECT  119.628 35.165 119.754 35.645 ;
     RECT  119.628 35.645 119.718 35.744 ;
     RECT  0.468 35.609 117.414 35.933 ;
     RECT  119.628 35.744 119.682 36.091 ;
     RECT  119.52 36.091 119.682 36.472 ;
     RECT  118.584 36.283 118.602 37.085 ;
     RECT  0.468 35.933 117.378 37.147 ;
     RECT  119.52 36.472 119.79 37.147 ;
     RECT  0.216 37.147 117.378 37.339 ;
     RECT  0.216 37.339 118.026 37.625 ;
     RECT  119.088 37.147 119.79 37.633 ;
     RECT  0.252 37.625 118.026 37.831 ;
     RECT  119.088 37.633 120.078 37.831 ;
     RECT  0.252 37.831 120.078 38.309 ;
     RECT  118.584 38.309 120.078 38.551 ;
     RECT  118.584 38.551 120.186 38.741 ;
     RECT  118.584 38.741 119.754 38.909 ;
     RECT  0.252 38.309 117.414 39.019 ;
     RECT  119.052 38.909 119.754 39.559 ;
     RECT  119.052 39.559 119.79 39.631 ;
     RECT  119.052 39.631 119.97 39.893 ;
     RECT  119.052 39.893 119.106 39.965 ;
     RECT  119.952 39.893 119.97 40.469 ;
     RECT  118.62 40.063 118.746 40.567 ;
     RECT  118.584 40.567 118.746 40.667 ;
     RECT  118.584 40.667 118.674 40.739 ;
     RECT  0.216 39.019 117.414 40.972 ;
     RECT  119.844 40.873 119.862 40.973 ;
     RECT  118.584 40.739 118.602 41.009 ;
     RECT  119.952 41.413 119.97 41.513 ;
     RECT  119.736 41.755 119.754 41.909 ;
     RECT  0.216 40.972 117.45 42.077 ;
     RECT  119.196 42.139 119.214 42.187 ;
     RECT  118.584 42.187 119.214 42.359 ;
     RECT  118.584 42.359 118.638 42.557 ;
     RECT  119.988 42.421 120.006 42.629 ;
     RECT  118.584 42.557 118.602 43.421 ;
     RECT  0.216 42.077 117.414 43.501 ;
     RECT  119.664 42.691 119.97 43.501 ;
     RECT  119.628 43.501 119.97 43.681 ;
     RECT  119.052 43.681 120.042 43.835 ;
     RECT  0.216 43.501 117.45 43.901 ;
     RECT  119.052 43.835 119.97 43.979 ;
     RECT  119.052 43.979 119.106 43.997 ;
     RECT  0.216 43.901 117.414 44.093 ;
     RECT  119.052 43.997 119.07 44.093 ;
     RECT  119.952 43.979 119.97 44.447 ;
     RECT  118.584 44.347 118.638 45.019 ;
     RECT  119.808 44.851 119.826 45.019 ;
     RECT  118.584 45.019 119.826 45.059 ;
     RECT  0.468 44.093 117.414 45.067 ;
     RECT  0.216 45.067 117.414 45.185 ;
     RECT  119.736 45.059 119.826 45.193 ;
     RECT  0.468 45.185 117.414 45.292 ;
     RECT  119.736 45.193 119.97 45.293 ;
     RECT  0.468 45.292 117.45 45.341 ;
     RECT  118.584 45.059 118.674 45.527 ;
     RECT  119.736 45.293 119.754 45.869 ;
     RECT  118.62 45.527 118.674 45.967 ;
     RECT  118.62 45.967 118.71 46.103 ;
     RECT  118.692 46.103 118.71 46.205 ;
     RECT  119.988 46.201 120.006 46.409 ;
     RECT  119.952 46.849 119.97 46.949 ;
     RECT  119.844 47.047 119.862 47.357 ;
     RECT  118.584 47.281 118.602 47.659 ;
     RECT  118.584 47.659 118.71 47.804 ;
     RECT  118.62 47.804 118.71 47.857 ;
     RECT  119.52 47.425 119.79 47.857 ;
     RECT  118.62 47.857 119.79 48.199 ;
     RECT  118.62 48.199 120.186 48.389 ;
     RECT  0.468 45.341 117.414 49.073 ;
     RECT  118.62 48.389 119.898 49.279 ;
     RECT  118.584 49.279 119.898 49.477 ;
     RECT  118.584 49.477 119.97 49.613 ;
     RECT  118.584 49.613 119.754 49.661 ;
     RECT  118.656 49.661 119.754 50.009 ;
     RECT  118.656 50.009 119.61 50.431 ;
     RECT  118.584 50.431 119.61 50.693 ;
     RECT  119.052 50.693 119.61 50.717 ;
     RECT  119.52 50.717 119.61 50.899 ;
     RECT  0.504 49.073 117.414 51.019 ;
     RECT  0.216 51.019 117.414 51.125 ;
     RECT  0.504 51.125 117.414 51.835 ;
     RECT  0.504 51.835 118.026 51.931 ;
     RECT  119.52 50.899 119.79 52.051 ;
     RECT  0.216 51.931 118.026 52.061 ;
     RECT  141.336 52.027 141.354 52.169 ;
     RECT  0.504 52.061 118.026 52.177 ;
     RECT  0.504 52.177 118.638 52.213 ;
     RECT  119.52 52.051 119.97 52.277 ;
     RECT  0.504 52.213 118.71 52.349 ;
     RECT  119.52 52.277 119.79 52.951 ;
     RECT  119.448 52.951 119.79 53.087 ;
     RECT  0.504 52.349 118.638 53.213 ;
     RECT  119.592 53.087 119.79 53.293 ;
     RECT  119.592 53.293 120.078 53.555 ;
     RECT  0.504 53.213 118.602 54.337 ;
     RECT  119.592 53.555 119.646 54.409 ;
     RECT  119.592 54.409 120.078 54.635 ;
     RECT  119.592 54.635 119.898 54.779 ;
     RECT  119.592 54.779 119.79 55.195 ;
     RECT  0.504 54.337 118.638 55.291 ;
     RECT  119.556 55.195 119.79 55.291 ;
     RECT  0.504 55.291 119.79 56.057 ;
     RECT  119.16 56.057 119.79 56.101 ;
     RECT  0.504 56.057 118.026 56.129 ;
     RECT  119.16 56.101 120.078 56.255 ;
     RECT  119.16 56.255 119.97 56.669 ;
     RECT  119.16 56.669 119.754 57.037 ;
     RECT  118.62 57.037 119.754 57.101 ;
     RECT  118.62 57.101 118.746 57.145 ;
     RECT  118.584 57.145 118.746 57.524 ;
     RECT  119.736 57.101 119.754 57.991 ;
     RECT  119.736 57.991 119.79 58.075 ;
     RECT  119.088 58.075 119.79 58.459 ;
     RECT  118.692 58.459 119.79 58.487 ;
     RECT  118.692 58.487 118.71 58.531 ;
     RECT  118.584 58.531 118.71 58.559 ;
     RECT  119.7 58.487 119.79 58.657 ;
     RECT  0.504 56.129 117.45 58.685 ;
     RECT  119.7 58.657 119.97 58.793 ;
     RECT  0.504 58.685 117.414 58.877 ;
     RECT  119.7 58.793 119.79 59.227 ;
     RECT  119.628 59.227 119.79 59.459 ;
     RECT  0.504 58.877 117.378 59.605 ;
     RECT  118.584 58.559 118.674 59.656 ;
     RECT  118.584 59.656 118.746 59.765 ;
     RECT  118.584 59.765 118.674 59.837 ;
     RECT  119.736 59.459 119.79 59.881 ;
     RECT  119.736 59.881 119.97 60.379 ;
     RECT  119.628 60.379 119.97 60.511 ;
     RECT  119.628 60.511 120.114 60.719 ;
     RECT  118.584 59.837 118.602 60.955 ;
     RECT  119.628 60.719 119.754 60.955 ;
     RECT  118.584 60.955 119.754 60.989 ;
     RECT  119.16 60.989 119.754 61.223 ;
     RECT  0.504 59.605 117.414 61.339 ;
     RECT  119.628 61.223 119.754 61.385 ;
     RECT  0.504 61.339 118.026 61.861 ;
     RECT  0.504 61.861 118.638 62.069 ;
     RECT  119.628 61.385 119.646 62.159 ;
     RECT  0.504 62.069 118.602 62.303 ;
     RECT  0.504 62.303 118.062 62.699 ;
     RECT  119.736 62.401 119.754 62.699 ;
     RECT  118.044 62.699 118.062 63.005 ;
     RECT  0.504 62.699 117.288 63.347 ;
     RECT  0.504 63.347 4.482 63.383 ;
     RECT  5.256 63.347 117.288 63.528 ;
     RECT  140.004 52.285 140.022 63.629 ;
     RECT  5.256 63.528 25.578 63.815 ;
     RECT  5.256 63.815 23.238 64.193 ;
     RECT  0.504 63.383 4.23 64.493 ;
     RECT  37.044 64.651 37.062 64.669 ;
     RECT  65.7 64.363 65.718 64.699 ;
     RECT  26.64 63.528 27.378 65.209 ;
     RECT  26.64 65.209 27.522 65.326 ;
     RECT  28.512 63.528 28.53 65.326 ;
     RECT  5.256 64.193 23.202 65.371 ;
     RECT  23.976 63.815 25.578 65.371 ;
     RECT  48.204 64.651 48.222 65.515 ;
     RECT  26.64 65.326 28.53 65.551 ;
     RECT  31.572 65.371 31.59 65.551 ;
     RECT  55.8 63.528 55.818 65.551 ;
     RECT  58.86 63.528 58.878 65.551 ;
     RECT  26.64 65.551 28.998 65.593 ;
     RECT  29.952 65.563 29.97 65.593 ;
     RECT  34.2 63.528 34.974 65.593 ;
     RECT  51.516 65.515 51.534 65.593 ;
     RECT  5.256 65.371 25.578 65.641 ;
     RECT  26.64 65.593 29.97 65.641 ;
     RECT  34.2 65.593 35.097 65.641 ;
     RECT  35.82 64.747 35.838 65.641 ;
     RECT  40.407 65.593 40.497 65.641 ;
     RECT  42.048 64.699 42.066 65.641 ;
     RECT  71.532 65.611 71.55 65.641 ;
     RECT  30.708 65.101 30.726 65.659 ;
     RECT  31.572 65.551 32.31 65.659 ;
     RECT  52.956 65.275 52.974 65.704 ;
     RECT  52.884 65.704 52.974 65.707 ;
     RECT  53.712 64.363 53.73 65.707 ;
     RECT  56.607 65.593 56.697 65.707 ;
     RECT  71.532 65.641 71.766 65.707 ;
     RECT  44.82 65.611 44.838 65.713 ;
     RECT  58.392 65.551 58.878 65.713 ;
     RECT  61.236 64.987 61.254 65.713 ;
     RECT  55.404 65.551 55.818 65.749 ;
     RECT  56.592 65.707 56.697 65.749 ;
     RECT  5.256 65.641 29.97 65.755 ;
     RECT  30.708 65.659 32.31 65.755 ;
     RECT  52.884 65.707 53.73 65.755 ;
     RECT  54.612 63.528 54.63 65.755 ;
     RECT  5.256 65.755 32.31 65.785 ;
     RECT  48.204 65.515 48.402 65.785 ;
     RECT  49.824 65.749 49.842 65.785 ;
     RECT  51.207 65.593 51.534 65.785 ;
     RECT  52.884 65.755 54.63 65.785 ;
     RECT  60.948 65.713 61.254 65.785 ;
     RECT  62.007 65.593 62.097 65.785 ;
     RECT  45.807 65.593 45.897 65.803 ;
     RECT  63.432 65.707 63.45 65.803 ;
     RECT  67.407 65.593 67.497 65.803 ;
     RECT  0.504 64.493 3.906 65.813 ;
     RECT  38.592 65.245 38.61 65.821 ;
     RECT  40.068 65.641 40.497 65.821 ;
     RECT  41.688 65.641 42.066 65.821 ;
     RECT  55.404 65.749 56.79 65.821 ;
     RECT  65.592 64.699 65.718 65.821 ;
     RECT  44.82 65.713 45.054 65.863 ;
     RECT  45.792 65.803 45.897 65.863 ;
     RECT  51.207 65.785 54.63 65.863 ;
     RECT  72.807 65.593 72.897 65.863 ;
     RECT  78.207 65.593 78.297 65.863 ;
     RECT  83.607 65.593 83.697 65.863 ;
     RECT  89.007 65.593 89.097 65.863 ;
     RECT  94.407 65.593 94.497 65.863 ;
     RECT  99.807 65.593 99.897 65.863 ;
     RECT  105.207 65.593 105.297 65.863 ;
     RECT  110.607 65.593 110.697 65.863 ;
     RECT  116.007 65.593 116.097 65.863 ;
     RECT  70.668 65.821 70.686 65.885 ;
     RECT  37.044 64.669 37.782 65.911 ;
     RECT  63.432 65.803 63.738 65.911 ;
     RECT  4.896 65.785 32.31 65.939 ;
     RECT  67.104 65.803 67.497 65.939 ;
     RECT  71.532 65.707 71.838 65.939 ;
     RECT  63.432 65.911 63.846 65.983 ;
     RECT  38.592 65.821 38.862 66.019 ;
     RECT  44.82 65.863 45.897 66.019 ;
     RECT  34.2 65.641 35.838 66.055 ;
     RECT  38.592 66.019 39.294 66.055 ;
     RECT  38.592 66.055 39.33 66.091 ;
     RECT  40.068 65.821 40.842 66.091 ;
     RECT  41.652 65.821 42.066 66.091 ;
     RECT  43.056 65.515 43.074 66.091 ;
     RECT  44.532 66.019 45.897 66.091 ;
     RECT  46.692 65.323 46.71 66.091 ;
     RECT  51.015 65.863 54.63 66.091 ;
     RECT  55.404 65.821 57.294 66.091 ;
     RECT  58.176 65.713 58.878 66.091 ;
     RECT  59.616 66.019 59.634 66.091 ;
     RECT  48.204 65.785 49.842 66.139 ;
     RECT  72.615 65.863 72.897 66.139 ;
     RECT  37.008 65.911 37.782 66.181 ;
     RECT  47.448 66.019 47.466 66.181 ;
     RECT  48.204 66.139 49.986 66.181 ;
     RECT  51.015 66.091 54.666 66.181 ;
     RECT  55.404 66.091 58.878 66.181 ;
     RECT  59.616 66.091 59.814 66.181 ;
     RECT  67.215 65.939 67.497 66.187 ;
     RECT  4.896 65.939 32.13 66.209 ;
     RECT  34.2 66.055 36.234 66.217 ;
     RECT  36.972 66.181 37.782 66.217 ;
     RECT  59.616 66.181 59.886 66.217 ;
     RECT  60.768 65.785 62.097 66.217 ;
     RECT  59.616 66.217 62.097 66.253 ;
     RECT  63.432 65.983 63.918 66.253 ;
     RECT  64.98 65.821 65.718 66.253 ;
     RECT  67.215 66.187 67.59 66.317 ;
     RECT  44.424 66.091 46.71 66.325 ;
     RECT  47.448 66.181 58.878 66.325 ;
     RECT  44.424 66.325 58.878 66.331 ;
     RECT  44.352 66.331 58.878 66.361 ;
     RECT  59.616 66.253 65.718 66.361 ;
     RECT  38.592 66.091 43.29 66.451 ;
     RECT  72.615 66.139 73.098 66.479 ;
     RECT  34.2 66.217 37.782 66.523 ;
     RECT  38.592 66.451 43.362 66.523 ;
     RECT  44.352 66.361 65.718 66.523 ;
     RECT  33.084 66.331 33.102 66.605 ;
     RECT  34.2 66.523 65.718 66.631 ;
     RECT  71.532 65.939 71.766 66.659 ;
     RECT  34.2 66.631 66.366 66.715 ;
     RECT  33.156 66.715 66.366 66.749 ;
     RECT  70.668 66.712 70.686 66.749 ;
     RECT  71.856 66.712 71.874 66.749 ;
     RECT  0.54 65.813 3.906 67.243 ;
     RECT  4.896 66.209 31.95 67.243 ;
     RECT  0.54 67.243 31.95 67.397 ;
     RECT  4.932 67.397 31.95 67.435 ;
     RECT  67.215 66.317 67.497 67.441 ;
     RECT  66.708 67.441 67.497 67.559 ;
     RECT  33.156 66.749 65.862 67.667 ;
     RECT  33.156 67.667 44.262 67.703 ;
     RECT  45.036 67.667 65.862 67.771 ;
     RECT  4.932 67.435 32.202 67.801 ;
     RECT  33.156 67.703 44.19 67.801 ;
     RECT  4.932 67.801 44.19 68.299 ;
     RECT  4.86 68.299 44.19 68.369 ;
     RECT  5.148 68.369 44.19 68.441 ;
     RECT  5.184 68.441 44.19 68.449 ;
     RECT  45.036 67.771 66.222 68.449 ;
     RECT  0.54 67.397 4.05 68.791 ;
     RECT  5.184 68.449 66.222 68.791 ;
     RECT  67.14 67.559 67.497 68.791 ;
     RECT  5.184 68.791 67.497 69.197 ;
     RECT  0.54 68.791 4.374 69.295 ;
     RECT  5.184 69.197 44.226 69.295 ;
     RECT  45 69.197 67.497 69.719 ;
     RECT  61.2 69.719 67.497 69.989 ;
     RECT  61.2 69.989 66.006 70.025 ;
     RECT  0.54 69.295 44.226 70.105 ;
     RECT  45 69.719 60.426 70.105 ;
     RECT  0.54 70.105 60.426 70.331 ;
     RECT  0.54 70.331 43.65 70.397 ;
     RECT  44.604 70.331 60.426 70.681 ;
     RECT  61.2 70.025 65.862 70.681 ;
     RECT  44.604 70.681 65.862 70.799 ;
     RECT  44.604 70.799 65.646 71.117 ;
     RECT  0.54 70.397 43.614 71.221 ;
     RECT  44.604 71.117 65.538 71.221 ;
     RECT  0.54 71.221 65.538 71.501 ;
     RECT  0.54 71.501 62.19 71.519 ;
     RECT  62.928 71.501 65.538 71.519 ;
     RECT  0.54 71.519 49.806 71.879 ;
     RECT  62.928 71.519 63.738 72.221 ;
     RECT  64.476 71.519 65.538 72.229 ;
     RECT  48.78 71.879 49.806 72.265 ;
     RECT  50.58 71.519 62.19 72.265 ;
     RECT  48.78 72.265 62.19 72.301 ;
     RECT  62.928 72.221 63.234 72.301 ;
     RECT  64.476 72.229 65.61 72.301 ;
     RECT  0.54 71.879 47.898 72.509 ;
     RECT  48.78 72.301 63.234 72.689 ;
     RECT  64.476 72.301 65.934 72.689 ;
     RECT  1.692 72.509 47.898 72.761 ;
     RECT  50.472 72.689 63.234 72.797 ;
     RECT  48.78 72.689 49.734 72.805 ;
     RECT  61.596 72.797 63.234 72.833 ;
     RECT  64.476 72.689 64.494 72.833 ;
     RECT  50.472 72.797 60.822 72.893 ;
     RECT  48.672 72.805 49.734 72.955 ;
     RECT  61.596 72.833 62.838 72.959 ;
     RECT  60.264 72.893 60.822 73.229 ;
     RECT  62.82 72.959 62.838 73.229 ;
     RECT  60.264 73.229 60.75 73.337 ;
     RECT  48.636 72.955 49.734 73.471 ;
     RECT  50.472 72.893 59.526 73.471 ;
     RECT  60.3 73.337 60.75 73.499 ;
     RECT  1.692 72.761 47.826 73.507 ;
     RECT  61.596 72.959 62.097 73.517 ;
     RECT  48.636 73.471 59.526 73.535 ;
     RECT  60.3 73.499 60.606 73.535 ;
     RECT  1.692 73.507 47.862 73.607 ;
     RECT  59.22 73.535 59.526 73.769 ;
     RECT  48.636 73.535 57.582 73.813 ;
     RECT  48.6 73.813 57.582 74.309 ;
     RECT  1.692 73.607 47.826 74.381 ;
     RECT  2.304 74.381 47.826 74.623 ;
     RECT  48.6 74.309 57.15 74.623 ;
     RECT  2.304 74.623 57.15 74.651 ;
     RECT  2.304 74.651 56.934 74.885 ;
     RECT  60.588 73.535 60.606 75.119 ;
     RECT  2.304 74.885 10.458 75.739 ;
     RECT  11.412 74.885 56.934 75.739 ;
     RECT  58.392 75.883 58.41 75.929 ;
     RECT  2.304 75.739 56.934 76.199 ;
     RECT  2.304 76.199 56.898 77.009 ;
     RECT  65.484 72.689 65.502 77.423 ;
     RECT  2.304 77.009 56.826 77.555 ;
     RECT  2.304 77.555 55.314 77.597 ;
     RECT  2.304 77.597 55.242 77.621 ;
     RECT  56.088 77.555 56.826 77.693 ;
     RECT  2.304 77.621 54.666 77.855 ;
     RECT  33.084 77.855 54.666 77.963 ;
     RECT  33.084 77.963 44.514 77.999 ;
     RECT  2.304 77.855 32.31 78.089 ;
     RECT  45.576 77.963 54.666 78.089 ;
     RECT  49.464 78.089 54.666 78.161 ;
     RECT  56.415 77.693 56.826 78.233 ;
     RECT  45.615 78.089 48.51 78.539 ;
     RECT  33.084 77.999 43.974 78.629 ;
     RECT  49.536 78.161 54.666 78.629 ;
     RECT  33.084 78.629 42.822 78.665 ;
     RECT  47.448 78.539 48.51 78.665 ;
     RECT  52.92 78.629 54.666 78.737 ;
     RECT  54.036 78.737 54.666 78.899 ;
     RECT  52.92 78.737 53.19 78.971 ;
     RECT  49.536 78.629 52.11 79.007 ;
     RECT  54.648 78.899 54.666 79.043 ;
     RECT  43.56 78.629 43.974 79.051 ;
     RECT  49.968 79.007 52.11 79.169 ;
     RECT  52.92 78.971 53.118 79.241 ;
     RECT  43.56 79.051 44.478 79.285 ;
     RECT  2.304 78.089 31.95 79.321 ;
     RECT  43.56 79.285 44.73 79.439 ;
     RECT  49.968 79.169 50.166 79.439 ;
     RECT  50.904 79.169 52.038 79.439 ;
     RECT  52.956 79.241 53.046 79.439 ;
     RECT  33.084 78.665 42.462 79.447 ;
     RECT  45.615 78.539 46.71 79.447 ;
     RECT  47.448 78.665 48.474 79.447 ;
     RECT  49.968 79.439 49.986 79.475 ;
     RECT  52.956 79.439 52.974 79.475 ;
     RECT  52.02 79.439 52.038 79.583 ;
     RECT  43.56 79.439 44.586 79.591 ;
     RECT  2.304 79.321 32.346 79.825 ;
     RECT  33.084 79.447 42.642 79.825 ;
     RECT  2.304 79.825 42.642 79.951 ;
     RECT  43.488 79.591 44.586 79.951 ;
     RECT  2.304 79.951 44.586 80.015 ;
     RECT  18.144 80.015 44.586 80.051 ;
     RECT  45.615 79.447 48.474 80.131 ;
     RECT  18.144 80.051 44.298 80.249 ;
     RECT  18.144 80.249 32.13 80.285 ;
     RECT  45.615 80.131 48.978 80.285 ;
     RECT  18.144 80.285 32.022 80.357 ;
     RECT  45.615 80.285 48.294 80.393 ;
     RECT  32.904 80.249 44.262 80.555 ;
     RECT  49.068 80.401 49.086 80.555 ;
     RECT  46.62 80.393 48.294 80.591 ;
     RECT  18.216 80.357 32.022 80.627 ;
     RECT  32.976 80.555 44.262 80.663 ;
     RECT  18.288 80.627 32.022 80.699 ;
     RECT  47.196 80.591 48.294 80.699 ;
     RECT  2.304 80.015 17.406 80.789 ;
     RECT  6.336 80.789 16.578 80.825 ;
     RECT  17.388 80.789 17.406 80.825 ;
     RECT  47.196 80.699 48.222 80.825 ;
     RECT  2.304 80.789 5.202 80.897 ;
     RECT  7.308 80.825 16.578 80.897 ;
     RECT  7.815 80.897 16.578 80.933 ;
     RECT  17.46 80.833 17.478 80.933 ;
     RECT  2.415 80.897 5.202 81.059 ;
     RECT  6.336 80.825 6.498 81.059 ;
     RECT  9.108 80.933 16.578 81.059 ;
     RECT  47.268 80.825 48.222 81.059 ;
     RECT  6.336 81.059 6.354 81.095 ;
     RECT  7.815 80.933 8.19 81.095 ;
     RECT  9.144 81.059 16.578 81.095 ;
     RECT  33.048 80.663 44.262 81.095 ;
     RECT  43.38 81.095 44.262 81.211 ;
     RECT  10.98 81.095 16.578 81.239 ;
     RECT  4.248 81.059 5.202 81.329 ;
     RECT  9.144 81.095 9.99 81.329 ;
     RECT  10.98 81.239 16.506 81.329 ;
     RECT  4.248 81.329 4.266 81.365 ;
     RECT  9.144 81.329 9.162 81.365 ;
     RECT  43.38 81.211 44.622 81.365 ;
     RECT  45.615 80.393 45.897 81.409 ;
     RECT  43.56 81.365 44.622 81.437 ;
     RECT  47.304 81.059 48.222 81.481 ;
     RECT  10.98 81.329 16.434 81.509 ;
     RECT  45.615 81.409 45.99 81.571 ;
     RECT  45.615 81.571 46.134 81.671 ;
     RECT  18.36 80.699 32.022 81.677 ;
     RECT  47.304 81.481 48.438 81.869 ;
     RECT  22.608 81.677 32.022 81.913 ;
     RECT  33.048 81.095 42.642 81.913 ;
     RECT  18.36 81.677 21.798 81.977 ;
     RECT  18.396 81.977 21.798 82.205 ;
     RECT  43.992 81.437 44.622 82.291 ;
     RECT  45.615 81.671 45.99 82.291 ;
     RECT  9.972 81.329 9.99 82.445 ;
     RECT  11.7 81.509 16.434 82.481 ;
     RECT  18.615 82.205 21.798 82.637 ;
     RECT  43.992 82.291 45.99 82.715 ;
     RECT  22.608 81.913 42.642 82.987 ;
     RECT  22.608 82.987 42.786 83.093 ;
     RECT  0.54 72.509 0.558 83.561 ;
     RECT  12.24 82.481 16.434 83.597 ;
     RECT  45.615 82.715 45.99 83.641 ;
     RECT  47.448 81.869 48.438 83.641 ;
     RECT  45.432 83.641 45.99 83.759 ;
     RECT  47.448 83.641 48.69 83.839 ;
     RECT  45.615 83.759 45.99 83.911 ;
     RECT  46.764 83.839 48.69 83.911 ;
     RECT  18.615 82.637 18.99 83.933 ;
     RECT  12.24 83.597 16.11 83.939 ;
     RECT  2.415 81.059 3.402 83.987 ;
     RECT  7.815 81.095 8.097 83.987 ;
     RECT  12.24 83.939 15.39 83.987 ;
     RECT  51.015 79.439 51.297 83.987 ;
     RECT  56.415 78.233 56.697 83.987 ;
     RECT  61.815 73.517 62.097 83.987 ;
     RECT  67.215 69.989 67.497 83.987 ;
     RECT  72.615 66.479 72.897 83.987 ;
     RECT  78.015 65.863 78.297 83.987 ;
     RECT  83.415 65.863 83.697 83.987 ;
     RECT  88.815 65.863 89.097 83.987 ;
     RECT  94.215 65.863 94.497 83.987 ;
     RECT  99.615 65.863 99.897 83.987 ;
     RECT  105.015 65.863 105.297 83.987 ;
     RECT  110.415 65.863 110.697 83.987 ;
     RECT  115.815 65.863 116.097 83.987 ;
     RECT  121.215 31.901 121.497 83.987 ;
     RECT  126.615 2.413 126.897 83.987 ;
     RECT  132.015 2.413 132.297 83.987 ;
     RECT  137.415 2.413 137.697 83.987 ;
     RECT  22.896 83.093 42.786 83.995 ;
     RECT  43.992 82.715 44.622 84.001 ;
     RECT  12.24 83.987 13.305 84.065 ;
     RECT  43.992 84.001 44.838 84.065 ;
     RECT  45.615 83.911 48.69 84.065 ;
     RECT  18.615 83.933 18.954 84.101 ;
     RECT  22.824 83.995 42.786 84.109 ;
     RECT  12.492 84.065 13.305 84.137 ;
     RECT  44.82 84.065 44.838 84.137 ;
     RECT  19.764 82.637 21.798 84.173 ;
     RECT  46.764 84.065 48.69 84.181 ;
     RECT  2.415 83.987 2.505 84.257 ;
     RECT  7.815 83.987 7.905 84.257 ;
     RECT  12.528 84.137 13.305 84.257 ;
     RECT  18.615 84.101 18.846 84.257 ;
     RECT  45.615 84.065 45.705 84.257 ;
     RECT  51.015 83.987 51.105 84.257 ;
     RECT  56.415 83.987 56.505 84.257 ;
     RECT  61.815 83.987 61.905 84.257 ;
     RECT  67.215 83.987 67.305 84.257 ;
     RECT  72.615 83.987 72.705 84.257 ;
     RECT  78.015 83.987 78.105 84.257 ;
     RECT  83.415 83.987 83.505 84.257 ;
     RECT  88.815 83.987 88.905 84.257 ;
     RECT  94.215 83.987 94.305 84.257 ;
     RECT  99.615 83.987 99.705 84.257 ;
     RECT  105.015 83.987 105.105 84.257 ;
     RECT  110.415 83.987 110.505 84.257 ;
     RECT  115.815 83.987 115.905 84.257 ;
     RECT  121.215 83.987 121.305 84.257 ;
     RECT  126.615 83.987 126.705 84.257 ;
     RECT  132.015 83.987 132.105 84.257 ;
     RECT  137.415 83.987 137.505 84.257 ;
     RECT  18.828 84.257 18.846 84.299 ;
     RECT  22.788 84.109 42.786 84.299 ;
     RECT  46.764 84.181 48.834 84.299 ;
     RECT  22.86 84.299 42.786 84.371 ;
     RECT  46.764 84.299 46.782 84.371 ;
     RECT  3.384 83.987 3.402 84.641 ;
     RECT  14.148 83.987 15.39 84.677 ;
     RECT  19.836 84.173 21.798 84.701 ;
     RECT  12.528 84.257 12.546 84.794 ;
     RECT  23.076 84.371 42.786 84.839 ;
     RECT  23.364 84.839 42.786 84.875 ;
     RECT  23.364 84.875 23.382 84.947 ;
     RECT  14.148 84.677 15.282 85.217 ;
     RECT  19.836 84.701 19.854 85.253 ;
     RECT  14.148 85.217 14.958 85.277 ;
     RECT  14.94 85.277 14.958 85.289 ;
     RECT  14.148 85.277 14.166 85.325 ;
     RECT  20.772 84.701 21.798 85.334 ;
     RECT  21.708 85.334 21.798 85.379 ;
     RECT  20.772 85.334 20.79 85.415 ;
     RECT  24.156 84.875 42.786 85.523 ;
     RECT  21.708 85.379 21.726 86.189 ;
     RECT  24.48 85.523 42.786 86.268 ;
     RECT  47.52 84.299 48.834 86.268 ;
     RECT  28.692 86.268 29.466 86.333 ;
     RECT  30.42 86.268 30.51 86.333 ;
    LAYER M4 ;
     RECT  0.156 32.256 0.245 42.792 ;
     RECT  0.156 44.064 0.245 45.096 ;
     RECT  0.205 51.024 0.245 52.056 ;
     RECT  0.245 32.4 0.569 42.792 ;
     RECT  0.925 53.616 1.573 53.64 ;
     RECT  1.465 64.992 1.645 65.016 ;
     RECT  0.569 32.4 2.041 41.208 ;
     RECT  0.569 42.336 2.041 42.792 ;
     RECT  1.465 50.4 2.077 50.424 ;
     RECT  0.245 44.208 2.221 44.952 ;
     RECT  1.537 63.504 2.221 63.528 ;
     RECT  2.221 62.736 2.257 63.528 ;
     RECT  2.041 32.4 2.329 42.792 ;
     RECT  2.257 25.536 2.408 25.56 ;
     RECT  2.329 32.208 2.408 42.792 ;
     RECT  2.221 44.208 2.408 45.816 ;
     RECT  2.113 47.856 2.408 47.88 ;
     RECT  2.077 49.776 2.408 50.424 ;
     RECT  0.245 51.936 2.408 51.96 ;
     RECT  1.573 53.616 2.408 54.456 ;
     RECT  2.329 55.536 2.408 55.56 ;
     RECT  0.817 58.224 2.408 58.248 ;
     RECT  2.329 59.28 2.408 59.304 ;
     RECT  1.609 60.672 2.408 60.696 ;
     RECT  2.365 61.728 2.408 61.752 ;
     RECT  2.257 62.736 2.408 63.576 ;
     RECT  1.645 64.992 2.408 65.256 ;
     RECT  0.889 70.656 2.408 70.68 ;
     RECT  1.105 72.48 2.408 72.504 ;
     RECT  1.681 74.352 2.408 74.376 ;
     RECT  2.408 2.148 2.512 84.252 ;
     RECT  2.512 2.418 2.704 83.982 ;
     RECT  2.704 40.032 2.765 44.472 ;
     RECT  2.704 13.056 2.819 13.08 ;
     RECT  2.704 78.624 2.867 79.752 ;
     RECT  2.704 53.568 2.873 60.696 ;
     RECT  2.704 72.48 2.917 75.384 ;
     RECT  2.867 79.44 2.945 79.752 ;
     RECT  2.873 53.568 3.161 57.384 ;
     RECT  2.704 51.84 3.197 52.488 ;
     RECT  2.765 40.32 3.305 44.472 ;
     RECT  3.305 40.32 3.413 43.944 ;
     RECT  2.704 19.968 3.593 19.992 ;
     RECT  2.704 23.328 3.697 25.656 ;
     RECT  2.704 45.792 3.701 50.76 ;
     RECT  2.873 58.368 3.733 60.696 ;
     RECT  2.704 61.728 3.733 65.256 ;
     RECT  2.704 27.6 3.781 29.544 ;
     RECT  3.733 30.624 3.781 30.648 ;
     RECT  2.704 36.624 3.841 39 ;
     RECT  3.733 58.368 3.845 65.256 ;
     RECT  2.704 32.064 3.913 35.448 ;
     RECT  3.841 36.432 3.913 39 ;
     RECT  3.701 48.672 3.913 50.76 ;
     RECT  3.197 51.84 3.913 52.344 ;
     RECT  2.917 72.48 3.913 75.24 ;
     RECT  2.704 76.512 3.913 76.536 ;
     RECT  2.704 10.848 3.925 10.872 ;
     RECT  3.781 27.6 3.925 30.648 ;
     RECT  3.913 32.064 3.925 39 ;
     RECT  2.704 83.04 3.925 83.064 ;
     RECT  3.925 27.6 3.973 39 ;
     RECT  2.704 14.112 4.021 15.24 ;
     RECT  3.697 23.328 4.021 26.232 ;
     RECT  2.704 17.616 4.057 17.64 ;
     RECT  4.021 23.328 4.061 26.376 ;
     RECT  3.161 57.264 4.061 57.384 ;
     RECT  2.704 69.504 4.061 69.528 ;
     RECT  3.973 78.672 4.061 78.696 ;
     RECT  4.061 24.096 4.069 26.376 ;
     RECT  3.973 27.408 4.069 39 ;
     RECT  3.913 72.48 4.097 76.536 ;
     RECT  3.701 45.792 4.117 47.496 ;
     RECT  3.769 81.024 4.117 81.048 ;
     RECT  4.057 16.848 4.129 17.64 ;
     RECT  3.733 19.344 4.129 19.944 ;
     RECT  4.097 75.84 4.133 76.536 ;
     RECT  2.704 70.656 4.273 71.112 ;
     RECT  4.097 72.48 4.273 74.472 ;
     RECT  4.273 70.656 4.313 74.472 ;
     RECT  4.069 24.096 4.385 39 ;
     RECT  4.313 70.656 4.453 72.504 ;
     RECT  3.845 58.368 4.501 60.696 ;
     RECT  3.925 10.32 4.525 10.872 ;
     RECT  2.704 11.952 4.525 11.976 ;
     RECT  3.413 40.32 4.525 42.408 ;
     RECT  3.413 43.536 4.525 43.944 ;
     RECT  2.704 67.344 4.525 67.368 ;
     RECT  4.453 70.608 4.561 72.504 ;
     RECT  4.525 10.32 4.597 11.976 ;
     RECT  4.525 40.32 4.693 43.944 ;
     RECT  4.117 44.928 4.693 47.496 ;
     RECT  3.925 83.04 4.693 83.544 ;
     RECT  4.385 38.832 4.777 39 ;
     RECT  4.693 40.32 4.777 47.496 ;
     RECT  4.021 14.112 4.789 15.528 ;
     RECT  4.129 16.848 4.789 19.944 ;
     RECT  4.525 67.248 4.789 67.368 ;
     RECT  4.789 66.72 4.849 67.368 ;
     RECT  4.789 14.112 4.885 19.944 ;
     RECT  4.849 66.72 4.885 68.328 ;
     RECT  4.501 57.552 4.921 60.696 ;
     RECT  3.845 61.968 4.921 65.256 ;
     RECT  4.885 14.112 4.925 20.472 ;
     RECT  4.777 38.832 4.933 47.496 ;
     RECT  2.945 79.68 4.957 79.752 ;
     RECT  4.117 81.024 4.957 81.192 ;
     RECT  4.261 22.608 4.981 22.824 ;
     RECT  4.133 75.936 4.988 76.536 ;
     RECT  3.913 48.672 5.029 52.344 ;
     RECT  3.161 53.568 5.101 56.28 ;
     RECT  4.921 57.552 5.101 65.256 ;
     RECT  4.925 18.816 5.177 20.472 ;
     RECT  4.885 66.672 5.245 68.328 ;
     RECT  4.988 75.936 5.281 77.304 ;
     RECT  4.957 79.056 5.281 81.192 ;
     RECT  4.925 14.112 5.285 17.688 ;
     RECT  4.313 73.536 5.317 74.472 ;
     RECT  4.561 70.368 5.324 72.504 ;
     RECT  5.317 73.536 5.324 74.904 ;
     RECT  5.324 70.368 5.357 74.904 ;
     RECT  4.597 10.32 5.365 12.936 ;
     RECT  5.285 14.112 5.365 15.816 ;
     RECT  5.245 66.528 5.393 68.328 ;
     RECT  5.393 66.624 5.425 68.328 ;
     RECT  5.365 10.32 5.459 15.816 ;
     RECT  4.385 24.096 5.461 37.608 ;
     RECT  5.357 70.608 5.461 74.904 ;
     RECT  5.281 75.936 5.461 81.192 ;
     RECT  4.933 38.832 5.509 47.64 ;
     RECT  5.029 48.672 5.509 52.584 ;
     RECT  5.509 38.832 5.557 52.584 ;
     RECT  5.101 53.568 5.557 65.256 ;
     RECT  4.693 83.04 5.653 84.072 ;
     RECT  5.177 19.248 5.701 20.472 ;
     RECT  5.461 23.904 5.701 37.608 ;
     RECT  5.557 38.592 5.701 65.256 ;
     RECT  5.425 66.624 5.747 69 ;
     RECT  6.001 2.304 6.133 2.328 ;
     RECT  5.285 16.8 6.145 17.688 ;
     RECT  5.459 10.32 6.149 10.728 ;
     RECT  6.133 2.304 6.257 2.856 ;
     RECT  6.145 16.8 6.361 18.12 ;
     RECT  5.701 19.248 6.361 21.144 ;
     RECT  5.701 23.904 6.469 65.256 ;
     RECT  5.747 66.624 6.469 68.952 ;
     RECT  4.981 22.32 6.505 22.824 ;
     RECT  6.469 23.904 6.505 68.952 ;
     RECT  5.459 11.76 6.685 15.816 ;
     RECT  6.361 16.8 6.685 21.144 ;
     RECT  6.505 22.32 6.685 68.952 ;
     RECT  5.461 70.608 6.797 81.192 ;
     RECT  6.797 70.608 6.937 75.816 ;
     RECT  6.469 4.704 7.237 4.728 ;
     RECT  6.685 11.76 7.441 68.952 ;
     RECT  6.937 69.984 7.441 75.816 ;
     RECT  5.653 83.04 7.621 84.744 ;
     RECT  6.257 2.304 7.808 2.328 ;
     RECT  7.237 3.888 7.808 4.728 ;
     RECT  6.149 10.32 7.808 10.68 ;
     RECT  7.441 11.76 7.808 75.816 ;
     RECT  6.797 76.848 7.808 81.192 ;
     RECT  7.621 83.04 7.808 85.224 ;
     RECT  7.808 2.148 7.912 85.224 ;
     RECT  7.912 2.304 8.104 85.224 ;
     RECT  8.104 9.312 8.387 81.912 ;
     RECT  8.104 3.888 9.493 4.728 ;
     RECT  8.387 9.312 9.529 75.816 ;
     RECT  8.387 76.848 9.529 81.912 ;
     RECT  8.104 2.304 9.781 2.328 ;
     RECT  9.529 9.312 10.073 81.912 ;
     RECT  8.104 7.632 10.165 7.656 ;
     RECT  10.165 7.344 10.357 7.656 ;
     RECT  10.073 79.392 10.577 81.912 ;
     RECT  10.073 9.312 10.885 78.168 ;
     RECT  9.781 2.304 11.509 2.808 ;
     RECT  9.493 3.888 11.557 4.824 ;
     RECT  10.357 7.152 11.749 7.656 ;
     RECT  10.885 8.832 11.797 78.168 ;
     RECT  11.749 6.864 11.891 7.656 ;
     RECT  11.557 3.888 12.373 5.496 ;
     RECT  10.577 79.584 12.476 81.912 ;
     RECT  11.509 1.632 12.661 2.808 ;
     RECT  12.373 3.888 12.661 5.544 ;
     RECT  11.891 7.104 12.853 7.656 ;
     RECT  11.797 8.784 12.853 78.168 ;
     RECT  12.661 1.632 13.208 5.544 ;
     RECT  12.853 7.104 13.208 78.168 ;
     RECT  12.476 79.152 13.208 81.912 ;
     RECT  8.104 83.04 13.208 85.224 ;
     RECT  13.208 1.632 13.504 85.224 ;
     RECT  13.504 82.944 13.909 85.224 ;
     RECT  13.504 1.632 14.965 81.912 ;
     RECT  13.909 82.944 14.965 86.04 ;
     RECT  14.965 1.632 16.645 86.04 ;
     RECT  16.645 1.632 22.093 86.232 ;
     RECT  22.093 1.584 22.237 86.232 ;
     RECT  22.237 0.816 23.029 86.232 ;
     RECT  23.029 0.192 26.291 86.232 ;
     RECT  26.291 0.24 26.723 86.232 ;
     RECT  26.723 0.24 27.011 0.6 ;
     RECT  27.011 0.576 27.443 0.6 ;
     RECT  28.321 0.528 28.825 0.552 ;
     RECT  26.723 1.632 28.825 86.232 ;
     RECT  28.825 0.528 29.173 86.232 ;
     RECT  29.173 0.288 29.249 86.232 ;
     RECT  29.249 0.24 30.049 86.232 ;
     RECT  30.049 0.192 30.467 86.232 ;
     RECT  30.467 0.336 30.485 86.232 ;
     RECT  30.485 0.576 30.611 86.232 ;
     RECT  30.611 1.152 31.601 86.232 ;
     RECT  31.601 1.632 32.581 86.232 ;
     RECT  32.581 1.488 33.157 86.232 ;
     RECT  33.157 1.392 34.597 86.232 ;
     RECT  34.117 0.288 34.885 0.312 ;
     RECT  34.597 1.296 34.885 86.232 ;
     RECT  34.885 0.288 35.173 86.232 ;
     RECT  35.173 0.24 35.233 86.232 ;
     RECT  35.233 0.144 36.173 86.232 ;
     RECT  36.173 0.144 37.321 86.184 ;
     RECT  37.321 0.144 39.731 86.232 ;
     RECT  39.731 65.232 40.504 86.232 ;
     RECT  40.504 65.232 40.643 71.448 ;
     RECT  40.504 72.576 40.732 86.232 ;
     RECT  40.732 72.576 41.555 84.84 ;
     RECT  40.643 65.232 41.605 71.4 ;
     RECT  41.555 72.576 41.605 83.64 ;
     RECT  41.605 65.232 41.717 83.64 ;
     RECT  41.555 84.816 41.789 84.84 ;
     RECT  39.731 0.144 42.037 63.864 ;
     RECT  41.717 65.232 42.037 79.752 ;
     RECT  41.717 80.784 42.131 83.64 ;
     RECT  42.037 0.144 42.179 79.752 ;
     RECT  42.179 64.704 42.221 79.752 ;
     RECT  42.131 80.784 42.221 83.592 ;
     RECT  42.221 81.12 42.365 83.592 ;
     RECT  42.365 81.12 42.419 81.144 ;
     RECT  42.365 82.464 42.509 83.592 ;
     RECT  42.221 64.704 42.545 79.512 ;
     RECT  42.509 82.464 42.707 83.016 ;
     RECT  42.707 82.992 42.797 83.016 ;
     RECT  40.732 86.208 42.805 86.232 ;
     RECT  42.805 86.112 42.947 86.232 ;
     RECT  42.545 64.704 43.661 78.648 ;
     RECT  43.661 71.184 43.945 78.648 ;
     RECT  43.916 79.68 44.003 79.704 ;
     RECT  43.945 71.184 44.387 78.696 ;
     RECT  43.661 64.704 44.701 69.72 ;
     RECT  44.387 71.184 44.701 78.072 ;
     RECT  44.701 64.704 45.608 78.072 ;
     RECT  45.608 64.704 45.712 84.252 ;
     RECT  45.712 64.704 45.904 83.982 ;
     RECT  45.904 64.704 46.643 79.848 ;
     RECT  46.643 74.592 47.603 79.848 ;
     RECT  46.643 64.704 47.653 73.512 ;
     RECT  47.603 74.592 47.653 79.272 ;
     RECT  47.653 64.704 48.193 79.272 ;
     RECT  48.193 64.656 48.377 79.272 ;
     RECT  48.377 79.2 50.101 79.272 ;
     RECT  48.377 64.656 51.008 78.168 ;
     RECT  50.101 79.152 51.008 79.272 ;
     RECT  51.008 64.656 51.112 84.252 ;
     RECT  51.112 64.656 51.304 83.982 ;
     RECT  51.304 78.144 51.905 79.032 ;
     RECT  51.304 64.656 52.337 76.872 ;
     RECT  52.337 66.864 52.693 76.872 ;
     RECT  52.693 66.864 52.733 76.968 ;
     RECT  52.337 64.656 53.057 65.832 ;
     RECT  51.905 78.144 53.309 78.168 ;
     RECT  52.733 69.504 53.557 76.968 ;
     RECT  53.449 78.048 53.557 78.072 ;
     RECT  42.179 0.144 53.701 63.624 ;
     RECT  53.057 64.656 53.701 65.736 ;
     RECT  53.557 69.504 53.741 78.072 ;
     RECT  52.733 67.104 53.953 68.52 ;
     RECT  53.953 66.768 53.989 68.52 ;
     RECT  53.741 69.504 53.989 77.64 ;
     RECT  53.701 0.144 54.097 65.736 ;
     RECT  54.097 0.144 54.125 65.784 ;
     RECT  53.989 66.768 54.125 77.64 ;
     RECT  54.125 0.144 54.677 77.64 ;
     RECT  54.677 67.104 54.685 77.592 ;
     RECT  54.685 67.104 54.821 76.584 ;
     RECT  54.685 77.568 55.325 77.592 ;
     RECT  54.677 0.144 55.361 66.024 ;
     RECT  55.361 0.192 55.717 66.024 ;
     RECT  54.821 67.104 55.717 76.44 ;
     RECT  55.717 0.192 55.829 76.44 ;
     RECT  55.829 64.656 56.293 76.44 ;
     RECT  55.717 77.52 56.293 77.544 ;
     RECT  56.293 64.656 56.408 77.544 ;
     RECT  56.408 64.656 56.512 84.252 ;
     RECT  56.512 64.656 56.704 83.982 ;
     RECT  56.704 64.656 56.819 76.008 ;
     RECT  56.819 75.264 56.945 76.008 ;
     RECT  56.819 64.656 57.683 74.088 ;
     RECT  55.829 0.192 57.733 63.624 ;
     RECT  57.683 64.656 57.733 73.8 ;
     RECT  57.733 0.192 58.093 73.8 ;
     RECT  58.093 0.144 58.205 73.8 ;
     RECT  56.945 75.264 58.451 75.912 ;
     RECT  58.205 0.288 58.889 73.8 ;
     RECT  58.889 64.656 59.075 73.8 ;
     RECT  59.075 64.656 59.267 73.752 ;
     RECT  58.451 75.264 59.267 75.864 ;
     RECT  58.889 0.288 60.037 63.624 ;
     RECT  59.267 75.264 60.227 75.528 ;
     RECT  60.037 0.24 60.229 63.624 ;
     RECT  59.267 64.656 60.323 73.512 ;
     RECT  60.227 75.504 60.419 75.528 ;
     RECT  60.229 0.192 60.433 63.624 ;
     RECT  60.323 64.656 60.437 72.456 ;
     RECT  60.437 67.536 61.333 72.456 ;
     RECT  60.323 73.488 61.333 73.512 ;
     RECT  60.437 64.656 61.621 66.552 ;
     RECT  61.333 67.536 61.621 73.512 ;
     RECT  61.621 64.656 61.808 73.512 ;
     RECT  61.808 64.656 61.912 84.252 ;
     RECT  61.912 64.656 62.104 83.982 ;
     RECT  62.104 67.056 62.243 72.984 ;
     RECT  62.243 67.056 62.489 72.456 ;
     RECT  62.489 67.056 63.173 69.864 ;
     RECT  62.489 71.472 63.569 72.456 ;
     RECT  62.104 64.656 63.709 66.024 ;
     RECT  63.709 64.656 64.357 66.12 ;
     RECT  63.173 67.536 64.357 69.864 ;
     RECT  64.357 64.656 64.403 69.864 ;
     RECT  63.569 72.432 65.117 72.456 ;
     RECT  64.403 64.656 65.269 69.528 ;
     RECT  64.319 71.088 65.657 71.112 ;
     RECT  60.433 0.144 65.689 63.624 ;
     RECT  65.269 64.656 65.689 67.8 ;
     RECT  65.689 0.144 66.233 67.8 ;
     RECT  66.233 0.144 67.208 67.128 ;
     RECT  65.269 69.264 67.208 69.528 ;
     RECT  67.208 0.144 67.312 84.252 ;
     RECT  67.312 0.144 67.504 83.982 ;
     RECT  67.504 0.144 67.667 67.128 ;
     RECT  67.504 69.264 68.675 69.288 ;
     RECT  67.667 64.656 69.251 67.128 ;
     RECT  69.251 64.704 69.827 67.128 ;
     RECT  69.827 64.704 70.697 66.744 ;
     RECT  70.697 64.704 71.555 66.648 ;
     RECT  71.555 65.568 71.845 66.648 ;
     RECT  67.667 0.144 71.993 63.624 ;
     RECT  71.845 65.568 72.131 66.744 ;
     RECT  71.993 1.392 72.137 63.624 ;
     RECT  72.137 1.536 72.209 63.624 ;
     RECT  71.993 0.144 72.425 0.216 ;
     RECT  72.131 65.598 72.608 66.744 ;
     RECT  72.608 65.598 72.712 84.252 ;
     RECT  72.712 65.598 72.904 83.982 ;
     RECT  72.209 1.824 73.181 63.624 ;
     RECT  73.181 6.528 73.217 63.624 ;
     RECT  72.425 0.144 73.613 0.168 ;
     RECT  73.181 1.824 74.189 5.544 ;
     RECT  72.904 66.144 75.539 66.168 ;
     RECT  74.189 2.208 75.665 5.544 ;
     RECT  75.665 2.208 78.008 2.328 ;
     RECT  75.665 3.312 78.008 5.544 ;
     RECT  73.217 6.624 78.008 63.624 ;
     RECT  78.008 2.148 78.112 63.624 ;
     RECT  78.008 65.868 78.112 84.252 ;
     RECT  78.112 65.868 78.2 83.982 ;
     RECT  78.112 2.208 78.304 63.624 ;
     RECT  78.2 65.598 78.304 83.982 ;
     RECT  78.304 2.208 80.773 2.328 ;
     RECT  78.304 3.312 80.773 63.624 ;
     RECT  80.773 2.208 83.408 63.624 ;
     RECT  83.408 2.148 83.512 63.624 ;
     RECT  83.408 65.868 83.512 84.252 ;
     RECT  83.512 65.868 83.6 83.982 ;
     RECT  83.6 65.598 83.704 83.982 ;
     RECT  83.512 2.208 88.808 63.624 ;
     RECT  88.808 2.148 88.912 63.624 ;
     RECT  88.808 65.868 88.912 84.252 ;
     RECT  88.912 65.868 89 83.982 ;
     RECT  89 65.598 89.104 83.982 ;
     RECT  88.912 2.208 94.208 63.624 ;
     RECT  94.208 2.148 94.312 63.624 ;
     RECT  94.208 65.868 94.312 84.252 ;
     RECT  94.312 65.868 94.4 83.982 ;
     RECT  94.4 65.598 94.504 83.982 ;
     RECT  94.312 2.208 99.608 63.624 ;
     RECT  99.608 2.148 99.712 63.624 ;
     RECT  99.608 65.868 99.712 84.252 ;
     RECT  99.712 65.868 99.8 83.982 ;
     RECT  99.8 65.598 99.904 83.982 ;
     RECT  99.712 2.208 100.019 63.624 ;
     RECT  100.019 8.832 100.217 63.624 ;
     RECT  100.217 9.024 101.747 63.624 ;
     RECT  101.747 9.36 101.843 63.624 ;
     RECT  101.843 10.272 102.124 63.624 ;
     RECT  102.124 10.272 102.125 17.352 ;
     RECT  102.125 10.608 102.377 17.352 ;
     RECT  102.377 12.288 102.485 17.352 ;
     RECT  102.485 12.288 102.845 16.344 ;
     RECT  100.019 2.208 105.008 7.752 ;
     RECT  102.377 10.608 105.008 11.16 ;
     RECT  102.845 12.288 105.008 16.152 ;
     RECT  102.485 17.328 105.008 17.352 ;
     RECT  102.124 18.48 105.008 63.624 ;
     RECT  105.008 2.148 105.112 63.624 ;
     RECT  105.008 65.868 105.112 84.252 ;
     RECT  105.112 65.868 105.2 83.982 ;
     RECT  105.112 2.208 105.304 63.624 ;
     RECT  105.2 65.598 105.304 83.982 ;
     RECT  105.304 2.208 110.408 7.752 ;
     RECT  105.304 10.608 110.408 11.16 ;
     RECT  105.304 12.288 110.408 16.152 ;
     RECT  105.304 17.328 110.408 17.352 ;
     RECT  105.304 18.48 110.408 63.624 ;
     RECT  110.408 2.148 110.512 63.624 ;
     RECT  110.408 65.868 110.512 84.252 ;
     RECT  110.512 65.868 110.6 83.982 ;
     RECT  110.512 2.208 110.704 63.624 ;
     RECT  110.6 65.598 110.704 83.982 ;
     RECT  110.704 2.208 114.577 7.752 ;
     RECT  110.704 12.288 114.577 16.152 ;
     RECT  110.704 17.328 114.577 17.352 ;
     RECT  114.577 17.328 114.617 17.448 ;
     RECT  114.577 2.064 115.808 7.752 ;
     RECT  110.704 10.608 115.808 11.16 ;
     RECT  114.577 12.288 115.808 16.296 ;
     RECT  114.617 17.424 115.808 17.448 ;
     RECT  110.704 18.48 115.808 63.624 ;
     RECT  115.808 65.868 115.912 84.252 ;
     RECT  115.912 65.868 116 83.982 ;
     RECT  115.808 2.064 116.104 63.624 ;
     RECT  116 65.598 116.104 83.982 ;
     RECT  116.104 10.608 116.915 11.16 ;
     RECT  116.104 17.424 116.921 17.448 ;
     RECT  116.104 18.48 117.216 63.624 ;
     RECT  116.104 2.064 117.317 7.752 ;
     RECT  117.216 18.48 117.425 62.424 ;
     RECT  117.425 40.992 117.461 46.2 ;
     RECT  117.425 47.328 117.461 59.352 ;
     RECT  117.425 60.384 117.461 62.424 ;
     RECT  117.425 18.48 117.587 39.96 ;
     RECT  116.104 12.288 117.683 16.296 ;
     RECT  117.587 21.792 118.001 39.96 ;
     RECT  117.461 47.328 118.037 56.952 ;
     RECT  118.001 21.792 118.067 22.2 ;
     RECT  117.587 18.48 118.163 20.808 ;
     RECT  118.067 21.792 118.307 22.152 ;
     RECT  118.163 20.16 118.549 20.808 ;
     RECT  118.307 21.792 118.549 22.008 ;
     RECT  118.549 20.16 118.595 22.008 ;
     RECT  117.461 42.144 118.613 46.2 ;
     RECT  118.037 47.328 118.613 54.168 ;
     RECT  117.461 59.232 118.613 59.352 ;
     RECT  118.613 43.968 118.685 46.2 ;
     RECT  117.317 2.304 118.691 7.752 ;
     RECT  118.685 46.176 118.721 46.2 ;
     RECT  116.915 11.136 118.787 11.16 ;
     RECT  117.683 12.816 118.793 16.296 ;
     RECT  118.793 15.264 118.829 16.296 ;
     RECT  118.691 6.624 118.835 7.752 ;
     RECT  118.595 20.16 118.835 21.24 ;
     RECT  118.163 18.48 118.865 19.08 ;
     RECT  118.691 2.304 118.883 5.544 ;
     RECT  118.883 3.648 118.931 5.544 ;
     RECT  118.001 23.232 118.931 39.96 ;
     RECT  118.931 33.12 118.937 39.96 ;
     RECT  118.835 20.16 118.979 21.144 ;
     RECT  118.685 43.968 119.081 45.048 ;
     RECT  118.937 33.216 119.117 39.96 ;
     RECT  119.081 43.968 119.117 43.992 ;
     RECT  119.081 45.024 119.117 45.048 ;
     RECT  118.613 47.328 119.117 54.072 ;
     RECT  117.461 58.08 119.117 58.2 ;
     RECT  119.117 49.44 119.153 49.464 ;
     RECT  118.793 12.816 119.189 13.992 ;
     RECT  118.883 2.304 119.219 2.328 ;
     RECT  118.613 42.144 119.225 42.84 ;
     RECT  118.931 3.936 119.267 5.544 ;
     RECT  119.117 58.08 119.297 58.104 ;
     RECT  118.835 6.672 119.315 7.752 ;
     RECT  119.117 33.216 119.333 38.232 ;
     RECT  118.979 20.16 119.363 20.808 ;
     RECT  118.931 23.232 119.363 31.896 ;
     RECT  119.267 3.936 119.411 4.68 ;
     RECT  119.363 29.568 119.411 31.896 ;
     RECT  118.865 18.48 119.477 18.84 ;
     RECT  119.333 33.216 119.513 36.984 ;
     RECT  119.513 34.56 119.549 36.984 ;
     RECT  119.117 47.328 119.549 47.544 ;
     RECT  119.549 34.56 119.585 36.888 ;
     RECT  118.037 55.2 119.585 56.952 ;
     RECT  119.117 50.592 119.621 54.072 ;
     RECT  119.621 51.648 119.657 52.632 ;
     RECT  119.621 54.048 119.657 54.072 ;
     RECT  119.585 55.68 119.657 56.28 ;
     RECT  118.613 59.232 119.657 59.256 ;
     RECT  117.461 60.384 119.657 62.136 ;
     RECT  119.225 42.816 119.693 42.84 ;
     RECT  119.189 13.92 119.729 13.992 ;
     RECT  119.585 35.616 119.765 36.792 ;
     RECT  118.829 15.264 119.795 15.816 ;
     RECT  119.363 20.496 119.801 20.808 ;
     RECT  119.765 36.48 119.801 36.792 ;
     RECT  119.333 38.208 119.837 38.232 ;
     RECT  119.729 13.968 119.843 13.992 ;
     RECT  119.363 23.232 119.873 28.248 ;
     RECT  119.549 47.328 119.873 47.352 ;
     RECT  119.477 18.816 119.891 18.84 ;
     RECT  119.513 33.216 119.945 33.24 ;
     RECT  119.189 12.816 119.981 12.84 ;
     RECT  119.585 34.56 120.017 34.584 ;
     RECT  119.411 29.568 120.089 30.264 ;
     RECT  119.315 7.152 120.125 7.752 ;
     RECT  119.873 23.232 120.125 28.056 ;
     RECT  119.411 3.936 121.208 3.96 ;
     RECT  120.125 7.2 121.208 7.752 ;
     RECT  119.795 15.264 121.208 15.288 ;
     RECT  119.801 20.784 121.208 20.808 ;
     RECT  120.125 23.232 121.208 23.256 ;
     RECT  120.125 24.576 121.208 28.056 ;
     RECT  120.089 29.568 121.208 29.976 ;
     RECT  119.411 31.584 121.208 31.896 ;
     RECT  117.216 63.6 121.208 63.624 ;
     RECT  121.208 2.148 121.312 84.252 ;
     RECT  121.312 2.418 121.504 83.982 ;
     RECT  121.504 7.2 121.565 7.224 ;
     RECT  121.504 26.016 121.565 26.328 ;
     RECT  121.565 26.016 121.601 26.136 ;
     RECT  121.601 26.112 121.637 26.136 ;
     RECT  121.504 63.6 126.608 63.624 ;
     RECT  126.608 2.148 126.712 84.252 ;
     RECT  126.712 2.418 126.904 83.982 ;
     RECT  126.904 63.6 132.008 63.624 ;
     RECT  132.008 2.148 132.112 84.252 ;
     RECT  132.112 2.418 132.304 83.982 ;
     RECT  132.304 63.6 137.408 63.624 ;
     RECT  137.408 2.148 137.512 84.252 ;
     RECT  137.512 2.418 137.704 83.982 ;
     RECT  137.704 63.6 140.033 63.624 ;
    LAYER M5 ;
     RECT  24.528 0.144 61.272 0.227 ;
     RECT  66.576 0.144 67.896 0.227 ;
     RECT  24.672 0.227 61.272 0.275 ;
     RECT  24.816 0.275 61.272 0.323 ;
     RECT  24.96 0.323 61.272 0.515 ;
     RECT  24.96 0.515 61.128 1.139 ;
     RECT  27.264 1.139 61.128 1.619 ;
     RECT  24.96 1.139 25.992 1.715 ;
     RECT  27.264 1.619 38.52 1.763 ;
     RECT  40.08 1.619 61.128 1.763 ;
     RECT  40.08 1.763 48.888 1.811 ;
     RECT  49.872 1.763 61.128 1.811 ;
     RECT  11.52 1.621 11.544 1.861 ;
     RECT  66.72 0.227 67.896 1.909 ;
     RECT  40.08 1.811 44.568 1.955 ;
     RECT  45.6 1.811 48.888 1.955 ;
     RECT  40.08 1.955 42.264 2.051 ;
     RECT  11.52 1.861 12.312 2.137 ;
     RECT  24.96 1.715 25.704 2.137 ;
     RECT  50.016 1.811 61.128 2.137 ;
     RECT  2.4 2.137 2.52 2.151 ;
     RECT  7.8 2.137 7.92 2.151 ;
     RECT  11.52 2.137 13.32 2.151 ;
     RECT  18.6 2.137 18.72 2.151 ;
     RECT  50.016 2.137 61.92 2.151 ;
     RECT  72.6 2.137 72.72 2.151 ;
     RECT  78 2.137 78.12 2.151 ;
     RECT  83.4 2.137 83.52 2.151 ;
     RECT  88.8 2.137 88.92 2.151 ;
     RECT  94.2 2.137 94.32 2.151 ;
     RECT  99.6 2.137 99.72 2.151 ;
     RECT  105 2.137 105.12 2.151 ;
     RECT  110.4 2.137 110.52 2.151 ;
     RECT  115.8 2.137 115.92 2.151 ;
     RECT  121.2 2.137 121.32 2.151 ;
     RECT  126.6 2.137 126.72 2.151 ;
     RECT  132 2.137 132.12 2.151 ;
     RECT  137.4 2.137 137.52 2.151 ;
     RECT  66.72 1.909 68.232 2.243 ;
     RECT  66.72 2.243 68.088 2.245 ;
     RECT  70.512 0.144 71.112 2.245 ;
     RECT  31.296 1.763 38.376 2.531 ;
     RECT  50.016 2.151 62.112 2.531 ;
     RECT  59.952 2.531 62.112 2.579 ;
     RECT  14.688 2.341 14.712 2.581 ;
     RECT  15.84 2.533 15.864 2.581 ;
     RECT  43.248 1.955 44.568 2.627 ;
     RECT  17.04 2.485 17.064 2.821 ;
     RECT  66.288 2.245 68.088 2.821 ;
     RECT  24 2.137 25.704 2.867 ;
     RECT  60.816 2.579 62.112 2.867 ;
     RECT  24 2.867 24.984 2.915 ;
     RECT  27.696 1.763 30.168 2.915 ;
     RECT  31.296 2.531 33.336 2.915 ;
     RECT  45.6 1.955 48.456 2.915 ;
     RECT  50.016 2.531 58.968 2.915 ;
     RECT  70.512 2.245 71.16 2.915 ;
     RECT  43.392 2.627 44.568 2.917 ;
     RECT  31.44 2.915 33.336 2.963 ;
     RECT  119.184 2.293 119.208 3.013 ;
     RECT  43.392 2.917 44.616 3.059 ;
     RECT  118.848 3.013 119.208 3.061 ;
     RECT  11.52 2.151 13.512 3.157 ;
     RECT  14.688 2.581 15.864 3.157 ;
     RECT  17.04 2.821 17.592 3.301 ;
     RECT  18.6 2.151 18.912 3.301 ;
     RECT  50.016 2.915 53.064 3.395 ;
     RECT  43.392 3.059 44.568 3.491 ;
     RECT  27.696 2.915 29.88 3.589 ;
     RECT  11.52 3.157 15.864 3.685 ;
     RECT  17.04 3.301 18.912 3.685 ;
     RECT  54.48 2.915 56.904 3.731 ;
     RECT  34.32 2.531 38.376 3.733 ;
     RECT  40.08 2.051 41.976 3.733 ;
     RECT  45.6 2.915 48.312 3.779 ;
     RECT  11.52 3.685 18.912 3.781 ;
     RECT  20.064 3.589 20.088 3.781 ;
     RECT  7.8 2.151 8.112 3.877 ;
     RECT  70.656 2.915 71.16 3.877 ;
     RECT  26.784 3.589 29.88 3.923 ;
     RECT  121.2 2.151 121.512 3.925 ;
     RECT  34.32 3.733 41.976 4.019 ;
     RECT  66.096 2.821 68.088 4.019 ;
     RECT  70.128 3.877 71.16 4.019 ;
     RECT  36.336 4.019 41.976 4.067 ;
     RECT  70.128 4.019 70.68 4.115 ;
     RECT  9.792 2.773 9.816 4.117 ;
     RECT  11.52 3.781 20.088 4.117 ;
     RECT  54.48 3.731 56.808 4.163 ;
     RECT  66.096 4.019 67.8 4.213 ;
     RECT  65.808 4.213 67.8 4.259 ;
     RECT  44.256 3.491 44.28 4.403 ;
     RECT  24 2.915 24.312 4.405 ;
     RECT  21.12 4.261 21.144 4.451 ;
     RECT  65.808 4.259 67.704 4.451 ;
     RECT  22.416 2.485 22.44 4.501 ;
     RECT  24 4.405 24.6 4.501 ;
     RECT  22.416 4.501 24.6 4.547 ;
     RECT  31.584 2.963 33.336 4.595 ;
     RECT  34.32 4.019 35.304 4.595 ;
     RECT  52.752 3.395 53.064 4.595 ;
     RECT  65.808 4.451 67.512 4.595 ;
     RECT  22.416 4.547 24.312 4.643 ;
     RECT  7.248 3.877 8.112 4.645 ;
     RECT  9.792 4.117 20.088 4.645 ;
     RECT  118.704 3.061 119.208 4.645 ;
     RECT  6.144 2.821 6.168 4.693 ;
     RECT  7.248 4.645 20.088 4.693 ;
     RECT  36.336 4.067 41.88 4.739 ;
     RECT  70.128 4.115 70.152 4.739 ;
     RECT  45.6 3.779 46.584 4.789 ;
     RECT  44.64 4.789 46.584 4.979 ;
     RECT  27.696 3.923 29.88 4.981 ;
     RECT  34.464 4.595 35.304 5.027 ;
     RECT  66.96 4.595 67.512 5.027 ;
     RECT  26.736 4.981 29.88 5.123 ;
     RECT  34.464 5.027 35.208 5.123 ;
     RECT  52.752 4.595 52.92 5.123 ;
     RECT  26.784 5.123 29.88 5.171 ;
     RECT  31.584 4.595 31.608 5.171 ;
     RECT  32.64 4.595 33.336 5.171 ;
     RECT  45.6 4.979 46.584 5.171 ;
     RECT  48.144 3.779 48.312 5.171 ;
     RECT  50.016 3.395 51.312 5.171 ;
     RECT  54.48 4.163 56.712 5.171 ;
     RECT  65.808 4.595 65.832 5.173 ;
     RECT  55.056 5.171 56.712 5.219 ;
     RECT  33.312 5.171 33.336 5.317 ;
     RECT  48.288 5.171 48.312 5.413 ;
     RECT  34.464 5.123 35.112 5.507 ;
     RECT  48.288 5.413 49.032 5.603 ;
     RECT  64.992 5.173 65.832 5.603 ;
     RECT  48.288 5.603 48.312 5.699 ;
     RECT  22.416 4.643 22.968 5.701 ;
     RECT  24 4.643 24.312 5.701 ;
     RECT  28.128 5.171 29.88 5.747 ;
     RECT  33.312 5.317 33.432 5.747 ;
     RECT  55.056 5.219 55.368 5.747 ;
     RECT  22.416 5.701 24.312 5.797 ;
     RECT  21.456 5.797 24.312 5.843 ;
     RECT  118.704 4.645 119.4 5.989 ;
     RECT  21.456 5.843 22.824 6.131 ;
     RECT  61.008 2.867 62.112 6.229 ;
     RECT  67.2 5.027 67.512 6.229 ;
     RECT  28.848 5.747 29.88 6.323 ;
     RECT  55.056 5.747 55.08 6.323 ;
     RECT  65.808 5.603 65.832 6.323 ;
     RECT  36.336 4.739 41.544 6.469 ;
     RECT  69.456 6.229 69.48 6.565 ;
     RECT  44.016 6.277 44.04 6.611 ;
     RECT  33.408 5.747 33.432 6.709 ;
     RECT  36.336 6.469 42.168 6.805 ;
     RECT  72.6 2.151 72.912 6.805 ;
     RECT  88.8 2.151 89.112 6.805 ;
     RECT  6.144 4.693 20.088 6.853 ;
     RECT  21.456 6.131 22.776 6.853 ;
     RECT  28.848 6.323 29.712 6.899 ;
     RECT  76.992 6.805 77.016 6.901 ;
     RECT  76.944 6.901 77.016 7.043 ;
     RECT  45.6 5.171 45.912 7.045 ;
     RECT  60.48 6.229 62.112 7.093 ;
     RECT  74.64 6.805 74.664 7.093 ;
     RECT  115.8 2.151 116.112 7.093 ;
     RECT  117.6 5.173 117.624 7.093 ;
     RECT  45.024 7.045 45.912 7.235 ;
     RECT  80.592 7.093 80.616 7.235 ;
     RECT  6.144 6.853 22.776 7.237 ;
     RECT  60.48 7.093 62.664 7.237 ;
     RECT  56.4 5.219 56.712 7.333 ;
     RECT  60.48 7.237 63.384 7.379 ;
     RECT  34.8 5.507 35.112 7.381 ;
     RECT  63.36 7.379 63.384 7.381 ;
     RECT  64.464 7.285 64.488 7.381 ;
     RECT  78 2.151 78.312 7.381 ;
     RECT  26.784 5.171 26.808 7.429 ;
     RECT  72.48 6.805 72.912 7.475 ;
     RECT  69.072 6.565 69.48 7.477 ;
     RECT  74.64 7.093 75 7.477 ;
     RECT  36.24 6.805 42.168 7.523 ;
     RECT  26.592 7.429 26.808 7.621 ;
     RECT  6.144 7.237 22.824 7.715 ;
     RECT  26.592 7.621 27.24 7.715 ;
     RECT  45.6 7.235 45.912 7.717 ;
     RECT  39.696 7.523 42.168 7.765 ;
     RECT  60.48 7.379 62.232 7.765 ;
     RECT  67.056 6.229 67.608 7.765 ;
     RECT  92.352 6.805 92.376 7.765 ;
     RECT  45.6 7.717 46.44 7.861 ;
     RECT  76.992 7.043 77.016 7.907 ;
     RECT  94.2 2.151 94.512 7.909 ;
     RECT  28.944 6.899 29.712 7.955 ;
     RECT  32.784 6.709 33.432 7.955 ;
     RECT  34.704 7.381 35.112 7.955 ;
     RECT  49.44 6.133 49.464 7.957 ;
     RECT  58.368 5.701 58.392 7.957 ;
     RECT  59.808 7.765 62.232 7.957 ;
     RECT  74.64 7.477 75.528 8.003 ;
     RECT  88.8 6.805 89.736 8.003 ;
     RECT  92.352 7.765 93.144 8.003 ;
     RECT  99.6 2.151 99.912 8.005 ;
     RECT  88.8 8.003 89.496 8.101 ;
     RECT  32.784 7.955 33.384 8.195 ;
     RECT  49.44 7.957 49.56 8.197 ;
     RECT  94.2 7.909 94.968 8.197 ;
     RECT  92.928 8.003 93.144 8.243 ;
     RECT  66.72 7.765 67.608 8.245 ;
     RECT  44.448 8.197 44.472 8.387 ;
     RECT  49.152 8.197 49.56 8.387 ;
     RECT  34.8 7.955 35.112 8.389 ;
     RECT  36.24 7.523 38.376 8.389 ;
     RECT  51 5.171 51.312 8.437 ;
     RECT  66.72 8.245 67.656 8.437 ;
     RECT  81.408 8.005 81.432 8.437 ;
     RECT  68.976 7.477 69.48 8.485 ;
     RECT  78 7.381 78.648 8.485 ;
     RECT  81.408 8.437 81.912 8.485 ;
     RECT  72.6 7.475 72.912 8.533 ;
     RECT  83.4 2.151 83.712 8.581 ;
     RECT  85.152 8.485 85.176 8.581 ;
     RECT  45.6 7.861 46.728 8.677 ;
     RECT  75.264 8.003 75.528 8.677 ;
     RECT  76.56 8.485 76.584 8.677 ;
     RECT  96.528 4.501 96.552 8.677 ;
     RECT  49.536 8.387 49.56 8.723 ;
     RECT  80.304 8.629 80.328 8.725 ;
     RECT  93.072 8.243 93.144 8.725 ;
     RECT  94.2 8.197 95.16 8.725 ;
     RECT  58.368 7.957 62.232 8.773 ;
     RECT  63.36 7.381 64.488 8.773 ;
     RECT  66.24 8.437 67.656 8.821 ;
     RECT  68.976 8.485 69.672 8.869 ;
     RECT  75.264 8.677 76.584 8.869 ;
     RECT  80.016 8.725 80.328 8.915 ;
     RECT  66.24 8.821 67.704 8.917 ;
     RECT  68.88 8.869 69.672 8.917 ;
     RECT  90.912 8.773 90.936 8.965 ;
     RECT  45.6 8.677 47.208 9.013 ;
     RECT  56.4 7.333 57 9.013 ;
     RECT  96.528 8.677 96.936 9.013 ;
     RECT  34.8 8.389 38.376 9.061 ;
     RECT  58.368 8.773 64.488 9.061 ;
     RECT  77.904 8.485 78.648 9.061 ;
     RECT  83.4 8.581 85.176 9.061 ;
     RECT  101.712 9.013 101.736 9.061 ;
     RECT  39.696 7.765 42.744 9.109 ;
     RECT  83.28 9.061 85.176 9.155 ;
     RECT  81.408 8.485 82.056 9.157 ;
     RECT  83.28 9.155 84.456 9.157 ;
     RECT  88.416 8.101 89.496 9.157 ;
     RECT  6.144 7.715 22.776 9.253 ;
     RECT  45.504 9.013 47.448 9.253 ;
     RECT  39.696 9.109 43.08 9.299 ;
     RECT  77.904 9.061 78.984 9.301 ;
     RECT  93.072 8.725 95.16 9.301 ;
     RECT  96.528 9.013 97.368 9.301 ;
     RECT  32.784 8.195 32.808 9.349 ;
     RECT  99.6 8.005 100.008 9.349 ;
     RECT  101.136 9.061 101.736 9.349 ;
     RECT  29.4 7.955 29.712 9.397 ;
     RECT  27.216 7.715 27.24 9.445 ;
     RECT  54 9.397 54.024 9.493 ;
     RECT  50.688 8.437 51.312 9.541 ;
     RECT  93.072 9.301 97.368 9.541 ;
     RECT  49.056 9.493 49.08 9.589 ;
     RECT  54 9.493 54.168 9.589 ;
     RECT  92.352 9.541 97.368 9.589 ;
     RECT  26.784 9.445 27.24 9.635 ;
     RECT  44.88 9.253 47.448 9.637 ;
     RECT  70.896 9.205 70.92 9.637 ;
     RECT  75.264 8.869 76.68 9.637 ;
     RECT  77.904 9.301 79.032 9.637 ;
     RECT  92.352 9.589 97.8 9.637 ;
     RECT  99.6 9.349 101.832 9.637 ;
     RECT  50.688 9.541 51.72 9.779 ;
     RECT  55.728 9.013 57 9.779 ;
     RECT  92.352 9.637 101.832 9.779 ;
     RECT  88.128 9.157 89.496 9.781 ;
     RECT  90.72 8.965 90.936 9.781 ;
     RECT  95.568 9.779 101.832 9.923 ;
     RECT  55.728 9.779 56.952 9.925 ;
     RECT  32.784 9.349 33.192 10.069 ;
     RECT  70.896 9.637 71.544 10.069 ;
     RECT  72.6 8.533 73.08 10.069 ;
     RECT  6.144 9.253 22.824 10.165 ;
     RECT  24 5.843 24.312 10.165 ;
     RECT  44.064 9.637 47.448 10.165 ;
     RECT  48.912 9.589 49.08 10.165 ;
     RECT  74.256 9.061 74.28 10.165 ;
     RECT  75.264 9.637 76.728 10.165 ;
     RECT  32.112 10.069 33.192 10.213 ;
     RECT  74.256 10.165 76.728 10.261 ;
     RECT  52.896 9.061 52.92 10.307 ;
     RECT  101.136 9.923 101.832 10.307 ;
     RECT  66.24 8.917 69.672 10.309 ;
     RECT  70.896 10.069 73.08 10.309 ;
     RECT  53.904 9.589 54.168 10.355 ;
     RECT  58.368 9.061 64.872 10.355 ;
     RECT  44.064 10.165 49.08 10.357 ;
     RECT  64.464 10.355 64.872 10.357 ;
     RECT  55.632 9.925 56.952 10.403 ;
     RECT  31.872 10.213 33.192 10.501 ;
     RECT  34.224 9.061 38.376 10.501 ;
     RECT  74.208 10.261 76.728 10.501 ;
     RECT  77.904 9.637 79.224 10.501 ;
     RECT  29.4 9.397 29.928 10.549 ;
     RECT  53.904 10.355 53.928 10.549 ;
     RECT  31.872 10.501 38.376 10.739 ;
     RECT  64.464 10.357 64.92 10.739 ;
     RECT  39.696 9.299 42.744 10.741 ;
     RECT  43.776 10.357 49.08 10.741 ;
     RECT  74.208 10.501 79.224 10.787 ;
     RECT  88.128 9.781 90.936 10.789 ;
     RECT  92.352 9.779 94.512 10.789 ;
     RECT  6.144 10.165 24.312 10.837 ;
     RECT  58.368 10.355 63.288 10.837 ;
     RECT  74.208 10.787 76.728 10.837 ;
     RECT  3.936 10.309 3.96 10.883 ;
     RECT  88.128 10.789 94.512 10.883 ;
     RECT  34.224 10.739 38.376 10.931 ;
     RECT  66.24 10.309 73.08 11.075 ;
     RECT  80.976 9.157 84.456 11.077 ;
     RECT  31.872 10.739 33.192 11.123 ;
     RECT  50.832 9.779 51.72 11.123 ;
     RECT  58.224 10.837 63.288 11.171 ;
     RECT  6.144 10.837 24.6 11.173 ;
     RECT  34.704 10.931 38.376 11.315 ;
     RECT  77.856 10.787 79.224 11.315 ;
     RECT  27.216 9.635 27.24 11.317 ;
     RECT  60.48 11.171 63.288 11.317 ;
     RECT  64.464 10.739 64.872 11.317 ;
     RECT  4.8 11.269 4.824 11.365 ;
     RECT  6.144 11.173 25.08 11.365 ;
     RECT  86.88 10.453 86.904 11.365 ;
     RECT  95.568 9.923 100.008 11.413 ;
     RECT  39.696 10.741 49.08 11.459 ;
     RECT  86.88 11.365 87.48 11.459 ;
     RECT  88.656 10.883 94.512 11.459 ;
     RECT  77.856 11.315 79.128 11.507 ;
     RECT  27.024 11.317 27.24 11.603 ;
     RECT  70.656 11.075 73.08 11.653 ;
     RECT  74.112 10.837 76.728 11.653 ;
     RECT  77.904 11.507 79.128 11.699 ;
     RECT  60.48 11.317 64.872 11.797 ;
     RECT  66.24 11.075 69.528 11.797 ;
     RECT  91.728 11.459 94.512 11.893 ;
     RECT  95.568 11.413 100.056 11.893 ;
     RECT  91.728 11.893 100.056 11.939 ;
     RECT  70.656 11.653 76.728 11.987 ;
     RECT  60.48 11.797 69.528 12.035 ;
     RECT  55.632 10.403 56.712 12.133 ;
     RECT  91.776 11.939 100.056 12.227 ;
     RECT  27.216 11.603 27.24 12.229 ;
     RECT  88.656 11.459 90.744 12.275 ;
     RECT  31.872 11.123 33.096 12.277 ;
     RECT  115.8 7.093 117.624 12.277 ;
     RECT  60.48 12.035 69.48 12.323 ;
     RECT  88.656 12.275 89.832 12.325 ;
     RECT  65.808 12.323 69.48 12.371 ;
     RECT  80.4 11.077 84.456 12.467 ;
     RECT  80.4 12.467 84.024 12.515 ;
     RECT  31.44 12.277 33.096 12.563 ;
     RECT  34.8 11.315 38.376 12.563 ;
     RECT  43.632 11.459 49.08 12.707 ;
     RECT  88.512 12.325 89.832 12.707 ;
     RECT  27.216 12.229 27.528 12.755 ;
     RECT  80.4 12.515 83.712 12.851 ;
     RECT  4.8 11.365 25.08 12.901 ;
     RECT  78 11.699 79.128 12.901 ;
     RECT  39.696 11.459 42.168 12.949 ;
     RECT  43.632 12.707 48.888 12.949 ;
     RECT  70.656 11.987 72.912 12.995 ;
     RECT  81.696 12.851 83.712 12.995 ;
     RECT  80.4 12.851 80.424 13.043 ;
     RECT  2.4 2.151 2.712 13.045 ;
     RECT  39.696 12.949 48.888 13.139 ;
     RECT  58.368 11.171 59.4 13.187 ;
     RECT  31.632 12.563 33.096 13.235 ;
     RECT  42.048 13.139 48.888 13.283 ;
     RECT  88.608 12.707 89.832 13.331 ;
     RECT  50.832 11.123 51.624 13.333 ;
     RECT  68.976 12.371 69.48 13.571 ;
     RECT  58.416 13.187 59.4 13.573 ;
     RECT  60.48 12.323 64.488 13.573 ;
     RECT  58.416 13.573 64.488 13.619 ;
     RECT  31.632 13.235 31.656 13.621 ;
     RECT  65.808 12.371 67.848 13.621 ;
     RECT  68.976 13.571 69.24 13.621 ;
     RECT  115.8 12.277 117.672 13.621 ;
     RECT  118.656 5.989 119.4 13.621 ;
     RECT  74.016 11.987 76.728 13.763 ;
     RECT  4.608 12.901 25.08 13.813 ;
     RECT  74.016 13.763 76.632 13.859 ;
     RECT  101.136 10.307 101.736 13.859 ;
     RECT  29.4 10.549 30.024 13.861 ;
     RECT  101.28 13.859 101.736 13.861 ;
     RECT  81.888 12.995 83.712 13.907 ;
     RECT  39.792 13.139 40.68 13.955 ;
     RECT  115.8 13.621 119.4 13.957 ;
     RECT  120.432 3.925 121.512 13.957 ;
     RECT  29.28 13.861 30.024 14.003 ;
     RECT  101.28 13.861 102.168 14.003 ;
     RECT  32.784 13.235 33.096 14.053 ;
     RECT  34.8 12.563 37.464 14.053 ;
     RECT  2.4 13.045 2.808 14.101 ;
     RECT  29.4 14.003 30.024 14.101 ;
     RECT  31.008 13.621 31.656 14.101 ;
     RECT  71.52 12.995 72.912 14.197 ;
     RECT  74.016 13.859 76.584 14.197 ;
     RECT  81.936 13.907 83.712 14.197 ;
     RECT  44.016 13.283 48.888 14.243 ;
     RECT  91.776 12.227 100.008 14.243 ;
     RECT  78 12.901 79.224 14.341 ;
     RECT  86.064 13.573 86.088 14.341 ;
     RECT  58.416 13.619 59.352 14.387 ;
     RECT  80.784 14.005 80.808 14.389 ;
     RECT  85.872 14.341 86.088 14.389 ;
     RECT  87.456 11.459 87.48 14.389 ;
     RECT  88.608 13.331 89.544 14.389 ;
     RECT  85.872 14.389 89.544 14.435 ;
     RECT  85.872 14.435 89.496 14.483 ;
     RECT  29.4 14.101 31.656 14.485 ;
     RECT  32.784 14.053 37.464 14.485 ;
     RECT  65.808 13.621 69.24 14.485 ;
     RECT  44.064 14.243 48.888 14.531 ;
     RECT  80.784 14.389 80.904 14.531 ;
     RECT  63.504 13.619 64.488 14.773 ;
     RECT  55.488 12.133 56.712 14.819 ;
     RECT  58.416 14.387 58.44 14.867 ;
     RECT  63.504 14.773 64.632 14.867 ;
     RECT  4.608 13.813 25.656 14.917 ;
     RECT  81.936 14.197 84.6 14.963 ;
     RECT  77.664 14.341 79.224 15.059 ;
     RECT  91.776 14.243 99.912 15.059 ;
     RECT  50.736 13.333 51.624 15.061 ;
     RECT  65.76 14.485 69.24 15.061 ;
     RECT  91.776 15.059 91.8 15.109 ;
     RECT  91.008 15.109 91.8 15.155 ;
     RECT  80.784 14.531 80.808 15.203 ;
     RECT  53.04 10.549 53.928 15.349 ;
     RECT  55.68 14.819 56.712 15.349 ;
     RECT  42.048 13.283 42.888 15.445 ;
     RECT  77.664 15.059 78.312 15.491 ;
     RECT  93.072 15.059 99.912 15.491 ;
     RECT  39.792 13.955 40.632 15.493 ;
     RECT  41.616 15.445 42.888 15.493 ;
     RECT  71.52 14.197 76.584 15.539 ;
     RECT  39.792 15.493 42.888 15.637 ;
     RECT  29.4 14.485 37.464 15.827 ;
     RECT  39.36 15.637 42.888 15.827 ;
     RECT  50.688 15.061 51.624 15.829 ;
     RECT  50.592 15.829 51.624 15.875 ;
     RECT  39.696 15.827 42.648 15.923 ;
     RECT  4.608 14.917 26.04 15.925 ;
     RECT  27.216 12.755 27.24 15.925 ;
     RECT  50.592 15.875 51.528 16.019 ;
     RECT  44.064 14.531 48.696 16.021 ;
     RECT  29.4 15.827 30.024 16.067 ;
     RECT  4.608 15.925 27.24 16.069 ;
     RECT  44.064 16.021 49.032 16.117 ;
     RECT  65.76 15.061 69.336 16.117 ;
     RECT  64.464 14.867 64.632 16.165 ;
     RECT  4.608 16.069 27.384 16.259 ;
     RECT  31.008 15.827 37.464 16.309 ;
     RECT  4.608 16.259 27.288 16.355 ;
     RECT  43.632 16.117 49.032 16.405 ;
     RECT  81.936 14.963 84.552 16.405 ;
     RECT  31.008 16.309 37.512 16.499 ;
     RECT  86.016 14.483 89.496 16.501 ;
     RECT  91.008 15.155 91.032 16.547 ;
     RECT  64.464 16.165 64.68 16.549 ;
     RECT  65.76 16.117 69.912 16.549 ;
     RECT  99.6 15.491 99.912 16.549 ;
     RECT  81.84 16.405 84.552 16.595 ;
     RECT  93.072 15.491 97.944 16.691 ;
     RECT  101.28 14.003 102.072 16.691 ;
     RECT  29.4 16.067 29.832 16.693 ;
     RECT  55.68 15.349 57.192 16.741 ;
     RECT  52.944 15.349 53.928 16.837 ;
     RECT  78 15.491 78.312 16.837 ;
     RECT  93.072 16.691 94.872 16.837 ;
     RECT  43.632 16.405 49.368 16.883 ;
     RECT  50.688 16.019 51.528 16.885 ;
     RECT  81.936 16.595 84.552 16.885 ;
     RECT  43.632 16.883 49.176 16.931 ;
     RECT  48.384 16.931 49.176 16.979 ;
     RECT  78 16.837 78.408 16.979 ;
     RECT  27.072 16.355 27.288 17.027 ;
     RECT  55.68 16.741 57.672 17.029 ;
     RECT  86.016 16.501 89.784 17.029 ;
     RECT  92.88 16.837 94.872 17.029 ;
     RECT  39.696 15.923 42.552 17.077 ;
     RECT  52.8 16.837 53.928 17.077 ;
     RECT  48.384 16.979 48.696 17.171 ;
     RECT  92.784 17.029 94.872 17.171 ;
     RECT  38.784 17.077 42.552 17.173 ;
     RECT  71.52 15.539 76.536 17.267 ;
     RECT  38.784 17.173 42.648 17.269 ;
     RECT  43.632 16.931 47.4 17.269 ;
     RECT  92.784 17.171 94.68 17.269 ;
     RECT  86.016 17.029 90.648 17.315 ;
     RECT  95.904 16.691 97.944 17.363 ;
     RECT  38.784 17.269 47.4 17.411 ;
     RECT  60.336 13.619 62.472 17.411 ;
     RECT  38.784 17.411 42.648 17.459 ;
     RECT  86.016 17.315 89.784 17.555 ;
     RECT  39.696 17.459 42.552 17.603 ;
     RECT  92.4 17.269 94.68 17.603 ;
     RECT  101.616 16.691 102.072 17.603 ;
     RECT  52.8 17.077 54.6 17.651 ;
     RECT  101.616 17.603 101.64 17.651 ;
     RECT  4.608 16.355 26.088 17.699 ;
     RECT  55.68 17.029 58.152 17.699 ;
     RECT  64.464 16.549 69.912 17.699 ;
     RECT  93.36 17.603 94.68 17.699 ;
     RECT  99.6 16.549 100.008 17.699 ;
     RECT  71.52 17.267 74.088 17.701 ;
     RECT  39.696 17.603 42.168 17.747 ;
     RECT  50.688 16.885 51.768 17.747 ;
     RECT  93.36 17.699 94.512 17.747 ;
     RECT  27.264 17.027 27.288 17.749 ;
     RECT  43.632 17.411 47.4 17.795 ;
     RECT  81.936 16.885 84.936 17.795 ;
     RECT  83.28 17.795 84.936 17.843 ;
     RECT  31.008 16.499 37.464 17.891 ;
     RECT  27.264 17.749 27.672 17.893 ;
     RECT  29.28 16.693 29.832 17.893 ;
     RECT  32.544 17.891 37.464 17.939 ;
     RECT  27.264 17.893 29.832 17.987 ;
     RECT  34.656 17.939 37.464 17.987 ;
     RECT  88.8 17.555 89.784 18.035 ;
     RECT  95.904 17.363 97.512 18.035 ;
     RECT  75.168 17.267 76.536 18.037 ;
     RECT  6 17.699 26.088 18.083 ;
     RECT  60.336 17.411 62.232 18.083 ;
     RECT  65.52 17.699 69.912 18.083 ;
     RECT  55.68 17.699 57.048 18.131 ;
     RECT  68.64 18.083 69.912 18.133 ;
     RECT  78 16.979 78.312 18.133 ;
     RECT  31.008 17.891 31.08 18.179 ;
     RECT  53.088 17.651 54.6 18.179 ;
     RECT  86.016 17.555 87.768 18.179 ;
     RECT  26.064 18.083 26.088 18.227 ;
     RECT  83.4 17.843 84.936 18.229 ;
     RECT  86.016 18.179 86.04 18.229 ;
     RECT  27.264 17.987 29.712 18.275 ;
     RECT  32.784 17.939 33.672 18.275 ;
     RECT  68.64 18.133 70.104 18.275 ;
     RECT  75.168 18.037 76.968 18.275 ;
     RECT  78 18.133 78.936 18.275 ;
     RECT  81.936 17.795 81.96 18.275 ;
     RECT  93.408 17.747 94.512 18.275 ;
     RECT  71.376 17.701 74.088 18.323 ;
     RECT  83.4 18.229 86.04 18.323 ;
     RECT  87.216 18.179 87.768 18.323 ;
     RECT  95.904 18.035 96.936 18.323 ;
     RECT  48.432 17.171 48.696 18.325 ;
     RECT  27.648 18.275 27.672 18.371 ;
     RECT  87.216 18.323 87.528 18.419 ;
     RECT  95.904 18.323 96.648 18.419 ;
     RECT  75.168 18.275 76.92 18.467 ;
     RECT  75.168 18.467 75.528 18.515 ;
     RECT  65.52 18.083 67.656 18.563 ;
     RECT  76.896 18.467 76.92 18.563 ;
     RECT  65.52 18.563 66.168 18.659 ;
     RECT  83.4 18.323 85.704 18.659 ;
     RECT  28.704 18.275 29.712 18.707 ;
     RECT  64.464 17.699 64.488 18.709 ;
     RECT  65.52 18.659 65.544 18.709 ;
     RECT  64.464 18.709 65.544 18.755 ;
     RECT  64.464 18.755 65.112 18.757 ;
     RECT  71.376 18.323 72.912 18.757 ;
     RECT  51 17.747 51.768 18.803 ;
     RECT  54.288 18.179 54.6 18.803 ;
     RECT  60.336 18.083 62.112 18.851 ;
     RECT  73.968 18.323 74.088 18.851 ;
     RECT  83.4 18.659 85.608 18.851 ;
     RECT  39.792 17.747 42.168 18.853 ;
     RECT  39.264 18.853 42.168 18.947 ;
     RECT  64.176 18.757 65.112 18.995 ;
     RECT  39.264 18.947 40.512 19.043 ;
     RECT  48.432 18.325 48.792 19.091 ;
     RECT  6 18.083 24.504 19.235 ;
     RECT  32.784 18.275 33.624 19.379 ;
     RECT  31.008 18.179 31.032 19.427 ;
     RECT  44.976 17.795 47.4 19.427 ;
     RECT  64.176 18.995 64.488 19.523 ;
     RECT  83.4 18.851 84.936 19.571 ;
     RECT  48.96 19.333 48.984 19.573 ;
     RECT  53.088 18.179 53.304 19.573 ;
     RECT  54.288 18.803 54.312 19.573 ;
     RECT  56.4 18.131 57.048 19.573 ;
     RECT  70.944 18.757 72.912 19.621 ;
     RECT  6 19.235 24.456 19.763 ;
     RECT  88.8 18.035 89.544 19.763 ;
     RECT  56.4 19.573 57.768 19.765 ;
     RECT  84.912 19.571 84.936 19.811 ;
     RECT  96 18.419 96.648 19.811 ;
     RECT  60.624 18.851 62.112 19.813 ;
     RECT  29.184 18.707 29.712 19.859 ;
     RECT  92.64 19.141 92.664 19.859 ;
     RECT  93.792 18.275 94.512 19.859 ;
     RECT  60.624 19.813 62.28 19.861 ;
     RECT  2.4 14.101 3.24 19.909 ;
     RECT  4.608 17.699 4.632 19.909 ;
     RECT  43.632 17.795 43.656 19.909 ;
     RECT  44.976 19.427 46.536 19.909 ;
     RECT  53.088 19.573 54.312 19.909 ;
     RECT  55.776 19.765 57.768 19.909 ;
     RECT  39.552 19.043 40.512 19.955 ;
     RECT  70.944 19.621 73.512 20.003 ;
     RECT  26.64 18.757 26.664 20.147 ;
     RECT  47.568 19.957 47.592 20.149 ;
     RECT  48.96 19.573 49.08 20.149 ;
     RECT  52.368 19.909 54.312 20.149 ;
     RECT  55.44 19.909 57.768 20.149 ;
     RECT  24 19.763 24.456 20.245 ;
     RECT  51 18.803 51.312 20.293 ;
     RECT  24 20.245 25.128 20.387 ;
     RECT  6 19.763 22.776 20.437 ;
     RECT  64.464 19.523 64.488 20.531 ;
     RECT  96.624 19.811 96.648 20.579 ;
     RECT  31.344 21.013 31.368 21.061 ;
     RECT  32.784 19.379 32.808 21.061 ;
     RECT  39.792 19.955 40.512 21.061 ;
     RECT  47.568 20.149 49.08 21.061 ;
     RECT  50.4 20.293 51.312 21.061 ;
     RECT  68.64 18.275 69.912 21.107 ;
     RECT  31.344 21.061 32.808 21.109 ;
     RECT  39.696 21.061 40.512 21.109 ;
     RECT  42.144 18.947 42.168 21.109 ;
     RECT  5.712 20.437 22.776 21.155 ;
     RECT  24 20.387 24.456 21.299 ;
     RECT  52.368 20.149 57.768 21.637 ;
     RECT  29.4 19.859 29.712 21.685 ;
     RECT  29.4 21.685 29.976 21.733 ;
     RECT  31.344 21.109 33.72 21.733 ;
     RECT  43.488 19.909 46.536 21.923 ;
     RECT  6 21.155 22.776 22.165 ;
     RECT  24 21.299 24.312 22.165 ;
     RECT  115.8 13.957 121.512 22.307 ;
     RECT  2.4 19.909 4.632 22.309 ;
     RECT  2.4 22.309 5.016 24.085 ;
     RECT  6 22.165 24.312 24.085 ;
     RECT  117.144 22.307 121.512 25.187 ;
     RECT  120.384 25.187 121.512 25.283 ;
     RECT  117.144 25.187 119.4 30.851 ;
     RECT  118.656 30.851 119.4 31.043 ;
     RECT  117.144 30.851 117.672 31.139 ;
     RECT  118.656 31.043 118.92 32.771 ;
     RECT  118.656 32.771 118.776 32.963 ;
     RECT  118.656 32.963 118.68 34.307 ;
     RECT  117.144 31.139 117.624 34.499 ;
     RECT  117.144 34.499 117.24 63.528 ;
     RECT  2.4 24.085 24.312 63.589 ;
     RECT  26.448 22.117 26.472 63.637 ;
     RECT  26.112 63.637 26.472 63.829 ;
     RECT  39.696 21.109 42.168 63.875 ;
     RECT  52.368 21.637 58.68 63.875 ;
     RECT  2.4 63.589 24.696 63.877 ;
     RECT  34.8 17.987 37.464 63.923 ;
     RECT  34.8 63.923 36.744 63.971 ;
     RECT  2.4 63.877 24.888 63.973 ;
     RECT  29.4 21.733 33.72 64.019 ;
     RECT  26.112 63.829 26.616 64.067 ;
     RECT  2.4 63.973 24.984 64.211 ;
     RECT  3.936 64.211 24.984 64.355 ;
     RECT  55.44 63.875 57.048 64.403 ;
     RECT  67.2 18.563 67.656 64.403 ;
     RECT  39.696 63.875 41.256 64.451 ;
     RECT  36.72 63.971 36.744 64.499 ;
     RECT  68.64 21.107 69.816 64.691 ;
     RECT  52.368 63.875 54.312 64.739 ;
     RECT  29.4 64.019 31.944 64.837 ;
     RECT  34.8 63.971 35.592 65.027 ;
     RECT  60.336 19.861 62.28 65.027 ;
     RECT  56.4 64.403 57.048 65.267 ;
     RECT  27.6 65.125 27.624 65.269 ;
     RECT  28.608 64.837 31.944 65.269 ;
     RECT  70.944 20.003 72.912 65.315 ;
     RECT  43.488 21.923 46.44 65.317 ;
     RECT  52.368 64.739 53.88 65.363 ;
     RECT  42.528 65.317 46.44 65.365 ;
     RECT  52.368 65.363 53.352 65.555 ;
     RECT  3.936 64.355 24.792 65.557 ;
     RECT  71.568 65.315 72.912 65.651 ;
     RECT  64.368 21.637 64.392 65.797 ;
     RECT  26.112 64.067 26.52 65.893 ;
     RECT  60.336 65.027 62.112 65.893 ;
     RECT  69.792 64.691 69.816 65.893 ;
     RECT  27.6 65.269 31.944 65.939 ;
     RECT  75.504 18.515 75.528 66.179 ;
     RECT  58.656 63.875 58.68 66.277 ;
     RECT  42.24 65.365 46.44 66.325 ;
     RECT  47.568 21.061 51.312 66.325 ;
     RECT  3.936 65.557 25.128 66.371 ;
     RECT  56.4 65.267 56.712 66.565 ;
     RECT  58.32 66.277 58.68 66.613 ;
     RECT  69.792 65.893 70.152 66.613 ;
     RECT  53.328 65.555 53.352 66.661 ;
     RECT  56.4 66.565 56.808 66.661 ;
     RECT  58.176 66.613 58.68 66.661 ;
     RECT  59.76 65.893 62.112 66.661 ;
     RECT  33.072 64.019 33.72 66.755 ;
     RECT  64.368 65.797 65.256 66.755 ;
     RECT  69.792 66.613 70.68 66.755 ;
     RECT  71.856 65.651 72.912 66.755 ;
     RECT  27.6 65.939 30.072 66.803 ;
     RECT  33.072 66.755 33.096 66.803 ;
     RECT  56.4 66.661 58.68 66.805 ;
     RECT  59.712 66.661 62.112 66.805 ;
     RECT  34.8 65.027 35.208 66.901 ;
     RECT  40.2 64.451 41.256 67.045 ;
     RECT  31.344 65.939 31.944 67.093 ;
     RECT  69.792 66.755 69.816 67.139 ;
     RECT  38.784 66.901 38.808 67.141 ;
     RECT  39.984 67.045 41.256 67.141 ;
     RECT  42.24 66.325 51.312 67.141 ;
     RECT  36.528 65.461 36.552 67.189 ;
     RECT  42.24 67.141 51.672 67.189 ;
     RECT  34.8 66.901 35.304 67.237 ;
     RECT  36.528 67.189 36.6 67.237 ;
     RECT  53.328 66.661 54.168 67.283 ;
     RECT  31.344 67.093 31.992 67.427 ;
     RECT  54.144 67.283 54.168 67.427 ;
     RECT  42.24 67.189 52.056 67.669 ;
     RECT  3.936 66.371 24.792 67.765 ;
     RECT  64.848 66.755 65.256 67.811 ;
     RECT  37.632 67.669 37.656 67.813 ;
     RECT  38.784 67.141 41.256 67.813 ;
     RECT  31.92 67.427 31.992 68.003 ;
     RECT  3.936 67.765 25.128 68.051 ;
     RECT  28.032 66.803 30.072 68.053 ;
     RECT  31.968 68.003 31.992 68.149 ;
     RECT  31.968 68.149 32.04 68.291 ;
     RECT  27.984 68.053 30.072 68.341 ;
     RECT  34.8 67.237 36.6 68.341 ;
     RECT  37.632 67.813 41.256 68.341 ;
     RECT  64.992 67.811 65.256 68.435 ;
     RECT  27.888 68.341 30.072 68.965 ;
     RECT  31.968 68.291 31.992 69.155 ;
     RECT  68.64 64.691 68.664 69.299 ;
     RECT  26.112 65.893 26.616 69.445 ;
     RECT  34.8 68.341 41.256 69.445 ;
     RECT  42.24 67.669 52.728 69.445 ;
     RECT  26.112 69.445 26.856 69.541 ;
     RECT  26.016 69.541 26.856 69.587 ;
     RECT  3.936 68.051 24.744 69.637 ;
     RECT  26.016 69.587 26.76 69.637 ;
     RECT  34.8 69.445 52.728 69.781 ;
     RECT  56.4 66.805 62.112 69.829 ;
     RECT  27.888 68.965 30.168 69.877 ;
     RECT  34.656 69.781 53.592 70.019 ;
     RECT  32.832 69.541 32.856 70.021 ;
     RECT  3.936 69.637 26.76 70.355 ;
     RECT  27.84 69.877 30.168 70.549 ;
     RECT  31.296 69.589 31.32 70.549 ;
     RECT  32.832 70.021 33.576 70.549 ;
     RECT  34.656 70.019 53.16 70.549 ;
     RECT  32.448 70.549 53.16 70.645 ;
     RECT  64.368 69.493 64.392 71.123 ;
     RECT  3.936 70.355 26.328 71.365 ;
     RECT  27.84 70.549 31.32 71.605 ;
     RECT  32.4 70.645 53.16 71.605 ;
     RECT  27.84 71.605 53.16 71.651 ;
     RECT  56.4 69.829 62.232 71.651 ;
     RECT  3.936 71.365 26.76 71.797 ;
     RECT  27.84 71.651 46.104 71.797 ;
     RECT  3.936 71.797 46.104 71.843 ;
     RECT  47.136 71.651 53.16 71.941 ;
     RECT  56.4 71.651 60.648 72.131 ;
     RECT  56.4 72.131 60.408 72.181 ;
     RECT  47.136 71.941 53.592 72.229 ;
     RECT  47.136 72.229 54.12 72.421 ;
     RECT  47.136 72.421 54.648 72.661 ;
     RECT  3.936 71.843 45.912 72.853 ;
     RECT  47.136 72.661 54.744 72.853 ;
     RECT  3.936 72.853 54.744 72.995 ;
     RECT  61.8 71.651 62.232 72.995 ;
     RECT  56.16 72.181 60.408 73.379 ;
     RECT  56.304 73.379 60.408 73.523 ;
     RECT  3.936 72.995 38.376 73.619 ;
     RECT  3.936 73.619 26.52 73.859 ;
     RECT  39.36 72.995 54.744 73.907 ;
     RECT  27.648 73.619 38.376 74.005 ;
     RECT  39.36 73.907 49.176 74.005 ;
     RECT  50.16 73.907 54.744 74.053 ;
     RECT  56.4 73.523 60.408 74.099 ;
     RECT  56.4 74.099 56.808 74.339 ;
     RECT  27.648 74.005 49.176 74.483 ;
     RECT  50.16 74.053 54.888 74.485 ;
     RECT  2.4 64.211 2.712 74.581 ;
     RECT  50.16 74.485 55.224 74.819 ;
     RECT  39.36 74.483 49.176 74.917 ;
     RECT  50.4 74.819 55.224 75.013 ;
     RECT  56.4 74.339 56.712 75.013 ;
     RECT  27.648 74.483 38.376 75.059 ;
     RECT  27.648 75.059 38.088 75.107 ;
     RECT  2.4 74.581 2.904 75.205 ;
     RECT  3.936 73.859 26.184 75.205 ;
     RECT  50.4 75.013 56.712 75.299 ;
     RECT  58.416 74.099 60.408 75.299 ;
     RECT  2.4 75.205 26.184 75.395 ;
     RECT  50.4 75.299 54.888 75.395 ;
     RECT  27.648 75.107 32.952 75.397 ;
     RECT  3.84 75.395 26.184 75.491 ;
     RECT  33.984 75.107 38.088 75.539 ;
     RECT  60.384 75.299 60.408 75.539 ;
     RECT  3.84 75.491 24.84 75.635 ;
     RECT  34.8 75.539 36.6 75.731 ;
     RECT  34.8 75.731 36.504 75.779 ;
     RECT  58.416 75.299 59.256 75.875 ;
     RECT  39.36 74.917 49.224 75.923 ;
     RECT  58.416 75.875 58.44 75.923 ;
     RECT  50.4 75.395 53.64 75.925 ;
     RECT  37.632 75.539 38.088 76.019 ;
     RECT  56.016 75.299 56.712 76.019 ;
     RECT  39.36 75.923 44.376 76.067 ;
     RECT  45.504 75.923 49.224 76.115 ;
     RECT  27.36 75.397 32.952 76.163 ;
     RECT  50.208 75.925 53.64 76.163 ;
     RECT  45.6 76.115 49.224 76.211 ;
     RECT  45.6 76.211 48.792 76.259 ;
     RECT  47.232 76.259 48.792 76.403 ;
     RECT  50.208 76.163 53.592 76.403 ;
     RECT  54.624 75.395 54.888 76.403 ;
     RECT  26.16 75.491 26.184 76.453 ;
     RECT  27.36 76.163 30.744 76.453 ;
     RECT  39.36 76.067 42.696 76.547 ;
     RECT  47.568 76.403 48.792 76.691 ;
     RECT  50.208 76.403 52.968 76.691 ;
     RECT  3.84 75.635 24.6 76.693 ;
     RECT  38.064 76.019 38.088 76.739 ;
     RECT  39.36 76.547 42.552 76.739 ;
     RECT  3.84 76.693 24.936 76.741 ;
     RECT  52.704 76.691 52.968 76.787 ;
     RECT  45.6 76.259 46.008 76.835 ;
     RECT  50.208 76.691 51.528 76.883 ;
     RECT  39.36 76.739 41.112 76.933 ;
     RECT  3.84 76.741 25.032 76.979 ;
     RECT  38.928 76.933 41.112 76.979 ;
     RECT  43.872 76.067 44.376 76.979 ;
     RECT  52.704 76.787 52.92 76.979 ;
     RECT  54.624 76.403 54.648 76.979 ;
     RECT  47.568 76.691 48.408 77.075 ;
     RECT  26.16 76.453 30.744 77.077 ;
     RECT  26.112 77.077 30.744 77.125 ;
     RECT  31.824 76.163 32.952 77.125 ;
     RECT  26.112 77.125 32.952 77.555 ;
     RECT  38.928 76.979 38.952 77.555 ;
     RECT  56.304 76.019 56.712 77.555 ;
     RECT  12.048 76.979 25.032 77.557 ;
     RECT  26.112 77.555 32.664 77.557 ;
     RECT  3.84 76.979 11.064 77.603 ;
     RECT  40.2 76.979 41.112 77.893 ;
     RECT  12.048 77.557 32.664 78.035 ;
     RECT  44.352 76.979 44.376 78.037 ;
     RECT  50.208 76.883 51.312 78.083 ;
     RECT  3.84 77.603 9.144 78.227 ;
     RECT  34.8 75.779 35.88 78.373 ;
     RECT  37.2 78.085 37.224 78.373 ;
     RECT  40.2 77.893 41.256 78.373 ;
     RECT  42.24 76.739 42.552 78.373 ;
     RECT  7.008 78.227 9.144 78.419 ;
     RECT  2.4 75.395 2.712 78.613 ;
     RECT  43.968 78.037 44.376 78.707 ;
     RECT  47.568 77.075 48.168 78.707 ;
     RECT  40.2 78.373 42.552 79.141 ;
     RECT  50.4 78.083 51.312 79.283 ;
     RECT  2.4 78.613 2.856 79.475 ;
     RECT  7.632 78.419 9.144 79.619 ;
     RECT  3.84 78.227 5.688 79.715 ;
     RECT  43.968 78.707 43.992 79.715 ;
     RECT  39.936 79.141 42.552 79.765 ;
     RECT  14.976 78.035 32.664 79.811 ;
     RECT  20.832 79.811 32.664 79.859 ;
     RECT  47.568 78.707 47.592 79.859 ;
     RECT  32.112 79.859 32.664 80.005 ;
     RECT  39.648 79.765 42.552 80.101 ;
     RECT  32.112 80.005 33.624 80.243 ;
     RECT  34.8 78.373 37.224 80.389 ;
     RECT  10.128 77.603 11.064 80.819 ;
     RECT  32.16 80.243 33.624 80.869 ;
     RECT  34.8 80.389 37.944 80.869 ;
     RECT  10.128 80.819 10.536 81.059 ;
     RECT  32.16 80.869 37.944 81.349 ;
     RECT  39.072 80.101 42.552 81.349 ;
     RECT  12.048 78.035 13.992 81.443 ;
     RECT  7.632 79.619 9.048 81.923 ;
     RECT  32.16 81.349 42.552 82.453 ;
     RECT  14.976 79.811 19.752 82.739 ;
     RECT  12.48 81.443 13.992 82.979 ;
     RECT  15.36 82.739 19.752 83.363 ;
     RECT  3.936 79.715 5.688 83.555 ;
     RECT  18.144 83.363 19.752 83.603 ;
     RECT  20.832 79.859 31.032 83.701 ;
     RECT  32.16 82.453 42.696 83.701 ;
     RECT  15.36 83.363 16.92 83.843 ;
     RECT  20.832 83.701 42.696 83.891 ;
     RECT  4.704 83.555 5.688 84.083 ;
     RECT  2.4 79.475 2.712 84.249 ;
     RECT  7.632 81.923 8.112 84.249 ;
     RECT  45.6 76.835 45.912 84.249 ;
     RECT  51 79.283 51.312 84.249 ;
     RECT  56.4 77.555 56.712 84.249 ;
     RECT  61.8 72.995 62.112 84.249 ;
     RECT  67.2 64.403 67.512 84.249 ;
     RECT  72.6 66.755 72.912 84.249 ;
     RECT  78 18.275 78.312 84.249 ;
     RECT  83.4 19.571 83.712 84.249 ;
     RECT  88.8 19.763 89.112 84.249 ;
     RECT  94.2 19.859 94.512 84.249 ;
     RECT  99.6 17.699 99.912 84.249 ;
     RECT  105 2.151 105.312 84.249 ;
     RECT  110.4 2.151 110.712 84.249 ;
     RECT  115.8 22.307 116.112 84.249 ;
     RECT  121.2 25.283 121.512 84.249 ;
     RECT  126.6 2.151 126.912 84.249 ;
     RECT  132 2.151 132.312 84.249 ;
     RECT  137.4 2.151 137.712 84.249 ;
     RECT  2.4 84.249 2.52 84.263 ;
     RECT  7.632 84.249 7.92 84.263 ;
     RECT  12.48 82.979 13.944 84.263 ;
     RECT  18.6 83.603 19.752 84.263 ;
     RECT  21.312 83.891 42.696 84.263 ;
     RECT  45.6 84.249 45.72 84.263 ;
     RECT  51 84.249 51.12 84.263 ;
     RECT  56.4 84.249 56.52 84.263 ;
     RECT  61.8 84.249 61.92 84.263 ;
     RECT  67.2 84.249 67.32 84.263 ;
     RECT  72.6 84.249 72.72 84.263 ;
     RECT  78 84.249 78.12 84.263 ;
     RECT  83.4 84.249 83.52 84.263 ;
     RECT  88.8 84.249 88.92 84.263 ;
     RECT  94.2 84.249 94.32 84.263 ;
     RECT  99.6 84.249 99.72 84.263 ;
     RECT  105 84.249 105.12 84.263 ;
     RECT  110.4 84.249 110.52 84.263 ;
     RECT  115.8 84.249 115.92 84.263 ;
     RECT  121.2 84.249 121.32 84.263 ;
     RECT  126.6 84.249 126.72 84.263 ;
     RECT  132 84.249 132.12 84.263 ;
     RECT  137.4 84.249 137.52 84.263 ;
     RECT  15.36 83.843 16.68 84.515 ;
     RECT  21.312 84.263 23.208 84.563 ;
     RECT  12.48 84.263 12.504 84.611 ;
     RECT  10.128 81.059 10.152 84.659 ;
     RECT  5.664 84.083 5.688 84.755 ;
     RECT  19.488 84.263 19.752 84.803 ;
     RECT  24.432 84.263 42.696 84.851 ;
     RECT  19.488 84.803 19.512 84.899 ;
     RECT  16.464 84.515 16.68 84.947 ;
     RECT  7.632 84.263 7.656 85.235 ;
     RECT  15.36 84.515 15.384 85.379 ;
     RECT  21.312 84.563 23.16 85.475 ;
     RECT  21.312 85.475 21.864 86.003 ;
     RECT  13.92 84.263 13.944 86.051 ;
     RECT  23.136 85.475 23.16 86.099 ;
     RECT  24.528 84.851 42.696 86.101 ;
     RECT  21.312 86.003 21.336 86.147 ;
     RECT  24.528 86.101 42.936 86.224 ;
     RECT  16.656 84.947 16.68 86.243 ;
     RECT  42.912 86.224 42.936 86.243 ;
     RECT  25.992 1.139 27.264 1.715 ;
     RECT  30.168 1.763 31.296 2.915 ;
     RECT  48.888 1.763 49.872 1.811 ;
     RECT  44.568 1.811 45.6 2.917 ;
     RECT  48.888 1.811 50.016 1.955 ;
     RECT  42.264 1.955 43.248 2.051 ;
     RECT  41.976 2.051 43.248 2.627 ;
     RECT  71.112 2.137 72.6 2.245 ;
     RECT  71.16 2.245 72.6 4.019 ;
     RECT  13.512 2.341 14.688 3.157 ;
     RECT  33.336 2.531 34.32 4.595 ;
     RECT  58.968 2.531 59.952 2.579 ;
     RECT  14.712 2.533 15.84 2.581 ;
     RECT  15.864 2.533 17.04 3.685 ;
     RECT  41.976 2.627 43.392 3.491 ;
     RECT  17.592 2.821 18.6 3.301 ;
     RECT  24.312 2.915 24.6 4.405 ;
     RECT  53.064 2.915 54.48 4.595 ;
     RECT  70.512 2.915 70.656 3.877 ;
     RECT  44.616 2.917 45.6 3.059 ;
     RECT  44.568 3.059 45.6 3.491 ;
     RECT  51.312 3.395 52.752 5.123 ;
     RECT  44.28 3.491 45.6 4.403 ;
     RECT  18.912 3.589 20.064 3.781 ;
     RECT  6.168 3.877 7.248 4.693 ;
     RECT  26.784 3.923 27.696 4.981 ;
     RECT  119.208 3.925 120.432 4.645 ;
     RECT  35.304 4.019 36.336 5.027 ;
     RECT  20.088 4.261 21.12 4.451 ;
     RECT  21.144 4.261 22.416 4.451 ;
     RECT  44.64 4.403 45.6 4.789 ;
     RECT  20.088 4.451 22.416 5.797 ;
     RECT  31.608 4.595 32.64 5.171 ;
     RECT  33.336 4.595 34.464 5.317 ;
     RECT  65.832 4.595 66.96 5.027 ;
     RECT  22.968 4.643 24 5.701 ;
     RECT  119.4 4.645 120.432 13.957 ;
     RECT  35.208 5.027 36.336 5.123 ;
     RECT  65.832 5.027 67.2 6.229 ;
     RECT  35.112 5.123 36.336 6.805 ;
     RECT  26.808 5.171 28.128 5.747 ;
     RECT  116.112 5.173 117.6 7.093 ;
     RECT  117.624 5.173 118.704 5.989 ;
     RECT  55.368 5.219 56.4 5.747 ;
     RECT  33.432 5.317 34.464 5.507 ;
     RECT  33.432 5.507 34.8 7.381 ;
     RECT  33.312 5.747 33.408 6.709 ;
     RECT  55.08 5.747 56.4 6.323 ;
     RECT  20.088 5.797 21.456 6.853 ;
     RECT  22.824 5.843 24 6.131 ;
     RECT  117.624 5.989 118.656 12.277 ;
     RECT  22.776 6.131 24 7.237 ;
     RECT  65.832 6.229 67.056 6.323 ;
     RECT  66.72 6.323 67.056 7.765 ;
     RECT  67.608 6.565 69.072 7.477 ;
     RECT  35.112 6.805 36.24 8.389 ;
     RECT  77.016 6.805 78 7.907 ;
     RECT  76.944 7.043 76.992 7.477 ;
     RECT  45.024 7.235 45.6 8.197 ;
     RECT  80.592 7.235 80.616 8.005 ;
     RECT  22.824 7.237 24 7.715 ;
     RECT  63.384 7.285 64.464 7.381 ;
     RECT  57 7.333 58.368 9.779 ;
     RECT  62.232 7.379 63.36 8.773 ;
     RECT  33.432 7.381 34.704 7.955 ;
     RECT  67.608 7.477 68.976 8.245 ;
     RECT  75.528 7.477 76.992 7.907 ;
     RECT  38.376 7.523 39.696 12.563 ;
     RECT  22.776 7.715 24 9.253 ;
     RECT  58.392 7.765 59.808 7.957 ;
     RECT  93.144 7.765 94.2 8.725 ;
     RECT  75.528 7.907 78 8.485 ;
     RECT  33.384 7.955 34.8 8.195 ;
     RECT  49.56 7.957 51 8.437 ;
     RECT  74.64 8.003 75.264 9.061 ;
     RECT  89.496 8.003 89.736 8.773 ;
     RECT  80.592 8.005 81.408 8.629 ;
     RECT  32.808 8.195 34.8 9.061 ;
     RECT  44.472 8.197 45.6 8.387 ;
     RECT  95.16 8.197 96.528 9.301 ;
     RECT  92.928 8.243 93.072 9.541 ;
     RECT  67.656 8.245 68.976 8.821 ;
     RECT  44.448 8.387 45.6 9.013 ;
     RECT  49.56 8.437 50.688 8.723 ;
     RECT  81.912 8.437 83.4 8.485 ;
     RECT  75.528 8.485 76.56 8.677 ;
     RECT  76.584 8.485 77.904 8.869 ;
     RECT  82.056 8.485 83.4 9.061 ;
     RECT  83.712 8.485 85.152 8.581 ;
     RECT  80.328 8.629 81.408 8.915 ;
     RECT  78.648 8.725 80.016 8.915 ;
     RECT  89.496 8.773 90.912 8.965 ;
     RECT  67.704 8.821 68.976 8.869 ;
     RECT  67.704 8.869 68.88 8.917 ;
     RECT  76.68 8.869 77.904 9.637 ;
     RECT  78.648 8.915 79.224 9.061 ;
     RECT  80.976 8.915 81.408 9.157 ;
     RECT  89.496 8.965 90.72 9.781 ;
     RECT  44.448 9.013 45.504 9.109 ;
     RECT  32.808 9.061 34.224 9.349 ;
     RECT  64.872 9.061 66.24 10.357 ;
     RECT  73.08 9.061 74.256 10.261 ;
     RECT  74.28 9.061 75.264 10.165 ;
     RECT  78.984 9.061 79.224 9.301 ;
     RECT  82.056 9.061 83.28 9.157 ;
     RECT  100.008 9.061 101.136 9.349 ;
     RECT  43.08 9.109 45.504 9.253 ;
     RECT  69.672 9.205 70.896 10.309 ;
     RECT  22.824 9.253 24 10.165 ;
     RECT  43.08 9.253 44.88 9.299 ;
     RECT  42.744 9.299 44.88 9.637 ;
     RECT  79.032 9.301 79.224 9.637 ;
     RECT  33.192 9.349 34.224 10.501 ;
     RECT  52.92 9.397 54 9.589 ;
     RECT  51.72 9.541 52.896 10.307 ;
     RECT  90.936 9.541 92.352 10.789 ;
     RECT  47.448 9.589 48.912 10.165 ;
     RECT  52.92 9.589 53.904 10.307 ;
     RECT  42.744 9.637 44.064 10.357 ;
     RECT  71.544 9.637 72.6 10.069 ;
     RECT  76.728 9.637 77.904 10.501 ;
     RECT  56.952 9.779 58.368 10.403 ;
     RECT  94.512 9.779 95.568 11.893 ;
     RECT  100.008 9.923 101.136 11.413 ;
     RECT  54.168 9.925 55.632 10.355 ;
     RECT  73.08 10.261 74.208 10.837 ;
     RECT  51.72 10.307 53.904 10.549 ;
     RECT  2.712 10.309 3.936 10.883 ;
     RECT  63.288 10.355 64.464 11.317 ;
     RECT  42.744 10.357 43.776 10.741 ;
     RECT  64.92 10.357 66.24 10.739 ;
     RECT  56.712 10.403 58.368 10.837 ;
     RECT  86.904 10.453 88.128 10.883 ;
     RECT  51.72 10.549 53.04 11.123 ;
     RECT  33.192 10.739 34.224 10.931 ;
     RECT  64.872 10.739 66.24 11.797 ;
     RECT  76.728 10.787 77.856 11.507 ;
     RECT  56.712 10.837 58.224 11.171 ;
     RECT  73.08 10.837 74.112 11.653 ;
     RECT  86.904 10.883 88.656 11.365 ;
     RECT  33.192 10.931 34.704 11.123 ;
     RECT  69.528 11.075 70.656 12.035 ;
     RECT  79.224 11.077 80.4 11.315 ;
     RECT  51.624 11.123 53.04 15.349 ;
     RECT  59.4 11.171 60.48 13.573 ;
     RECT  4.824 11.269 6.144 11.365 ;
     RECT  79.128 11.315 80.4 12.901 ;
     RECT  87.48 11.365 88.656 12.325 ;
     RECT  100.056 11.413 101.136 12.227 ;
     RECT  42.168 11.459 43.632 12.949 ;
     RECT  90.744 11.459 91.728 11.939 ;
     RECT  76.728 11.507 77.904 11.699 ;
     RECT  76.728 11.699 78 13.763 ;
     RECT  90.744 11.939 91.776 12.275 ;
     RECT  72.912 11.987 74.016 14.197 ;
     RECT  69.48 12.035 70.656 12.995 ;
     RECT  100.008 12.227 101.136 13.859 ;
     RECT  30.024 12.277 31.44 12.563 ;
     RECT  117.672 12.277 118.656 13.621 ;
     RECT  64.488 12.323 65.808 14.485 ;
     RECT  87.48 12.325 88.512 12.707 ;
     RECT  67.848 12.371 68.976 13.621 ;
     RECT  30.024 12.563 31.632 13.621 ;
     RECT  87.48 12.707 88.608 14.389 ;
     RECT  80.424 12.851 81.696 12.995 ;
     RECT  79.224 12.901 80.4 13.043 ;
     RECT  80.424 12.995 81.888 13.043 ;
     RECT  80.784 13.043 81.888 13.907 ;
     RECT  40.68 13.139 42.048 13.955 ;
     RECT  31.656 13.235 32.784 14.485 ;
     RECT  42.888 13.283 44.016 14.243 ;
     RECT  69.24 13.571 69.336 15.061 ;
     RECT  86.088 13.573 87.456 14.389 ;
     RECT  59.352 13.619 60.336 14.387 ;
     RECT  62.472 13.619 63.504 14.867 ;
     RECT  30.024 13.621 31.008 14.101 ;
     RECT  76.632 13.763 78 13.859 ;
     RECT  76.584 13.859 78 14.341 ;
     RECT  100.008 13.859 101.28 14.243 ;
     RECT  80.784 13.907 81.936 14.005 ;
     RECT  40.632 13.955 42.048 15.445 ;
     RECT  80.808 14.005 81.936 14.389 ;
     RECT  3.24 14.101 4.608 19.909 ;
     RECT  84.6 14.197 86.064 14.341 ;
     RECT  42.888 14.243 44.064 15.827 ;
     RECT  99.912 14.243 101.28 16.549 ;
     RECT  76.584 14.341 77.664 15.491 ;
     RECT  84.6 14.341 85.872 14.483 ;
     RECT  80.904 14.389 81.936 14.531 ;
     RECT  89.496 14.435 89.544 15.109 ;
     RECT  84.6 14.483 86.016 14.963 ;
     RECT  64.488 14.485 65.76 14.773 ;
     RECT  48.696 14.531 48.888 16.021 ;
     RECT  80.808 14.531 81.936 15.203 ;
     RECT  64.632 14.773 65.76 16.165 ;
     RECT  26.04 14.917 27.216 15.925 ;
     RECT  84.552 14.963 86.016 16.885 ;
     RECT  91.8 15.059 93.072 15.155 ;
     RECT  89.496 15.109 91.008 16.501 ;
     RECT  81.84 15.203 81.936 16.405 ;
     RECT  51.624 15.349 52.944 15.875 ;
     RECT  40.632 15.445 41.616 15.493 ;
     RECT  76.584 15.491 78 15.539 ;
     RECT  76.536 15.539 78 18.037 ;
     RECT  30.024 15.827 31.008 16.067 ;
     RECT  39.36 15.827 39.696 17.077 ;
     RECT  42.648 15.827 44.064 15.923 ;
     RECT  51.528 15.875 52.944 16.837 ;
     RECT  42.552 15.923 44.064 16.117 ;
     RECT  50.592 16.019 50.688 16.405 ;
     RECT  29.832 16.067 31.008 17.987 ;
     RECT  42.552 16.117 43.632 17.173 ;
     RECT  64.68 16.165 65.76 16.549 ;
     RECT  27.288 16.259 27.384 17.749 ;
     RECT  26.088 16.355 27.072 17.027 ;
     RECT  49.368 16.405 50.688 16.883 ;
     RECT  37.464 16.499 37.512 17.077 ;
     RECT  89.784 16.501 91.008 16.547 ;
     RECT  89.784 16.547 90.648 17.029 ;
     RECT  100.008 16.549 101.28 16.691 ;
     RECT  94.872 16.691 95.904 17.171 ;
     RECT  51.528 16.837 52.8 16.885 ;
     RECT  49.176 16.883 50.688 16.979 ;
     RECT  51.768 16.885 52.8 17.651 ;
     RECT  84.936 16.885 86.016 18.229 ;
     RECT  47.4 16.931 48.384 17.171 ;
     RECT  48.696 16.979 48.792 18.325 ;
     RECT  78.312 16.979 78.408 18.133 ;
     RECT  26.088 17.027 27.264 18.227 ;
     RECT  37.464 17.077 38.784 17.459 ;
     RECT  54.6 17.077 55.68 18.131 ;
     RECT  47.4 17.171 48.432 19.091 ;
     RECT  94.68 17.171 95.904 17.699 ;
     RECT  42.648 17.173 43.632 17.269 ;
     RECT  74.088 17.267 75.168 18.515 ;
     RECT  42.648 17.411 43.632 17.459 ;
     RECT  39.264 17.459 39.696 17.747 ;
     RECT  42.552 17.459 43.632 17.603 ;
     RECT  87.768 17.555 88.8 18.323 ;
     RECT  42.168 17.603 43.632 19.909 ;
     RECT  51.768 17.651 53.088 18.803 ;
     RECT  4.632 17.699 6 20.437 ;
     RECT  64.488 17.699 65.52 18.709 ;
     RECT  94.512 17.699 95.904 18.419 ;
     RECT  69.912 17.701 71.376 18.133 ;
     RECT  39.264 17.747 39.792 18.853 ;
     RECT  93.36 17.747 93.408 18.275 ;
     RECT  43.656 17.795 44.976 19.909 ;
     RECT  81.96 17.795 83.28 17.843 ;
     RECT  81.96 17.843 83.4 18.275 ;
     RECT  31.08 17.891 32.544 17.939 ;
     RECT  33.672 17.939 34.656 17.987 ;
     RECT  29.712 17.987 31.008 19.427 ;
     RECT  33.672 17.987 34.8 18.275 ;
     RECT  76.968 18.037 78 18.275 ;
     RECT  67.656 18.083 68.64 64.403 ;
     RECT  70.104 18.133 71.376 18.275 ;
     RECT  53.304 18.179 54.288 19.573 ;
     RECT  86.04 18.179 87.216 18.323 ;
     RECT  26.64 18.227 27.264 18.275 ;
     RECT  26.64 18.275 27.648 18.371 ;
     RECT  27.672 18.275 28.704 18.371 ;
     RECT  33.624 18.275 34.8 19.379 ;
     RECT  69.912 18.275 71.376 18.757 ;
     RECT  76.92 18.275 78 18.563 ;
     RECT  93.36 18.275 93.792 19.141 ;
     RECT  72.912 18.323 73.968 18.851 ;
     RECT  85.704 18.323 87.216 18.419 ;
     RECT  87.528 18.323 88.8 18.419 ;
     RECT  26.64 18.371 26.664 18.757 ;
     RECT  94.512 18.419 96 19.811 ;
     RECT  75.528 18.467 76.896 18.563 ;
     RECT  74.088 18.515 75.504 18.851 ;
     RECT  66.168 18.563 67.2 18.659 ;
     RECT  69.912 18.757 70.944 21.107 ;
     RECT  51.312 18.803 53.088 19.909 ;
     RECT  54.312 18.803 54.6 19.765 ;
     RECT  60.336 18.851 60.624 19.861 ;
     RECT  72.912 18.851 73.512 19.621 ;
     RECT  47.4 19.091 48.792 19.333 ;
     RECT  92.664 19.141 93.792 19.859 ;
     RECT  24.456 19.235 24.504 20.245 ;
     RECT  47.4 19.333 48.96 19.427 ;
     RECT  46.536 19.427 48.96 19.957 ;
     RECT  83.712 19.571 84.912 19.811 ;
     RECT  22.776 19.763 24 22.165 ;
     RECT  54.312 19.765 55.776 19.909 ;
     RECT  42.168 19.909 43.488 63.875 ;
     RECT  51.312 19.909 52.368 65.555 ;
     RECT  54.312 19.909 55.44 20.149 ;
     RECT  39.696 19.955 39.792 21.061 ;
     RECT  46.536 19.957 47.568 21.923 ;
     RECT  47.592 19.957 48.96 20.149 ;
     RECT  49.08 20.293 50.4 21.061 ;
     RECT  4.632 20.437 5.712 21.155 ;
     RECT  31.368 21.013 32.784 21.061 ;
     RECT  69.816 21.107 70.944 65.315 ;
     RECT  33.72 21.109 34.8 66.755 ;
     RECT  4.632 21.155 6 22.309 ;
     RECT  29.976 21.685 31.344 21.733 ;
     RECT  46.44 21.923 47.568 66.325 ;
     RECT  116.112 22.307 117.144 63.528 ;
     RECT  5.016 22.309 6 24.085 ;
     RECT  119.4 25.187 120.384 25.283 ;
     RECT  117.672 30.851 118.656 31.139 ;
     RECT  117.624 31.139 118.656 34.307 ;
     RECT  24.696 63.637 26.112 63.877 ;
     RECT  41.256 63.875 43.488 65.317 ;
     RECT  54.312 63.875 55.44 64.403 ;
     RECT  24.888 63.877 26.112 63.973 ;
     RECT  35.592 63.971 36.72 64.499 ;
     RECT  24.984 63.973 26.112 64.355 ;
     RECT  31.944 64.019 33.072 66.803 ;
     RECT  26.52 64.067 26.616 65.125 ;
     RECT  2.712 64.211 3.936 74.581 ;
     RECT  24.792 64.355 26.112 65.557 ;
     RECT  67.512 64.403 68.64 69.299 ;
     RECT  35.592 64.499 36.552 65.027 ;
     RECT  68.664 64.691 69.792 67.139 ;
     RECT  35.208 65.027 36.552 65.461 ;
     RECT  26.52 65.125 27.6 65.893 ;
     RECT  27.624 65.125 28.608 65.269 ;
     RECT  56.712 65.267 57.048 66.277 ;
     RECT  69.816 65.315 71.568 65.651 ;
     RECT  41.256 65.317 42.528 65.365 ;
     RECT  53.352 65.363 53.88 66.661 ;
     RECT  41.256 65.365 42.24 69.445 ;
     RECT  35.208 65.461 36.528 66.901 ;
     RECT  25.128 65.557 26.112 66.371 ;
     RECT  69.816 65.651 71.856 65.893 ;
     RECT  26.616 65.893 27.6 66.803 ;
     RECT  58.68 65.893 59.76 66.661 ;
     RECT  70.152 65.893 71.856 66.613 ;
     RECT  30.072 65.939 31.344 67.427 ;
     RECT  56.712 66.277 58.32 66.565 ;
     RECT  24.792 66.371 26.112 67.765 ;
     RECT  56.808 66.565 58.32 66.613 ;
     RECT  56.808 66.613 58.176 66.661 ;
     RECT  70.68 66.613 71.856 66.755 ;
     RECT  58.68 66.661 59.712 66.805 ;
     RECT  26.616 66.803 28.032 68.053 ;
     RECT  31.944 66.803 32.04 67.093 ;
     RECT  35.304 66.901 36.528 67.237 ;
     RECT  38.808 66.901 40.2 67.045 ;
     RECT  38.808 67.045 39.984 67.141 ;
     RECT  31.992 67.093 32.04 68.149 ;
     RECT  52.056 67.189 53.328 67.283 ;
     RECT  52.056 67.283 54.144 67.427 ;
     RECT  52.056 67.427 52.728 67.669 ;
     RECT  36.6 67.669 37.632 68.341 ;
     RECT  37.656 67.669 38.784 67.813 ;
     RECT  25.128 67.765 26.112 68.051 ;
     RECT  24.744 68.051 26.112 69.541 ;
     RECT  26.616 68.053 27.984 68.341 ;
     RECT  31.992 68.291 32.04 69.155 ;
     RECT  26.616 68.341 27.888 69.445 ;
     RECT  31.968 69.155 32.04 69.541 ;
     RECT  26.856 69.445 27.888 69.587 ;
     RECT  24.744 69.541 26.016 69.637 ;
     RECT  31.968 69.541 32.832 69.589 ;
     RECT  26.76 69.587 27.888 69.877 ;
     RECT  30.168 69.589 31.296 70.549 ;
     RECT  31.32 69.589 32.832 70.549 ;
     RECT  26.76 69.877 27.84 70.355 ;
     RECT  33.576 70.021 34.656 70.549 ;
     RECT  26.328 70.355 27.84 71.365 ;
     RECT  31.32 70.549 32.448 70.645 ;
     RECT  31.32 70.645 32.4 71.605 ;
     RECT  26.76 71.365 27.84 71.797 ;
     RECT  46.104 71.651 47.136 71.843 ;
     RECT  60.648 71.651 61.8 72.131 ;
     RECT  45.912 71.843 47.136 72.853 ;
     RECT  60.408 72.131 61.8 75.539 ;
     RECT  54.648 72.421 56.16 72.661 ;
     RECT  54.744 72.661 56.16 73.379 ;
     RECT  38.376 72.995 39.36 74.005 ;
     RECT  54.744 73.379 56.304 73.523 ;
     RECT  54.744 73.523 56.4 74.053 ;
     RECT  26.52 73.619 27.648 73.859 ;
     RECT  26.184 73.859 27.648 75.397 ;
     RECT  49.176 73.907 50.16 74.819 ;
     RECT  54.888 74.053 56.4 74.485 ;
     RECT  38.376 74.483 39.36 75.059 ;
     RECT  55.224 74.485 56.4 75.013 ;
     RECT  2.904 74.581 3.936 75.205 ;
     RECT  49.176 74.819 50.4 74.917 ;
     RECT  49.224 74.917 50.4 75.925 ;
     RECT  38.088 75.059 39.36 76.739 ;
     RECT  32.952 75.107 33.984 75.539 ;
     RECT  54.888 75.299 56.016 76.019 ;
     RECT  59.256 75.299 60.384 75.539 ;
     RECT  2.712 75.395 3.84 78.613 ;
     RECT  53.64 75.395 54.624 76.163 ;
     RECT  26.184 75.397 27.36 76.453 ;
     RECT  24.84 75.491 26.16 75.635 ;
     RECT  36.6 75.539 37.632 75.731 ;
     RECT  24.6 75.635 26.16 76.693 ;
     RECT  36.504 75.731 37.632 75.779 ;
     RECT  44.376 75.923 45.504 76.115 ;
     RECT  49.224 75.925 50.208 76.211 ;
     RECT  54.888 76.019 56.304 76.403 ;
     RECT  42.696 76.067 43.872 76.547 ;
     RECT  44.376 76.115 45.6 78.707 ;
     RECT  30.744 76.163 31.824 77.125 ;
     RECT  53.592 76.163 54.624 76.403 ;
     RECT  48.792 76.211 50.208 76.691 ;
     RECT  46.008 76.259 47.232 76.403 ;
     RECT  42.552 76.547 43.872 76.979 ;
     RECT  51.528 76.691 52.704 76.883 ;
     RECT  24.936 76.693 26.16 76.741 ;
     RECT  38.928 76.739 39.36 76.933 ;
     RECT  41.112 76.739 42.24 77.893 ;
     RECT  25.032 76.741 26.16 77.077 ;
     RECT  51.312 76.883 52.704 76.979 ;
     RECT  11.064 76.979 12.048 80.819 ;
     RECT  38.952 76.979 40.2 77.555 ;
     RECT  42.552 76.979 44.352 78.037 ;
     RECT  25.032 77.077 26.112 77.557 ;
     RECT  9.144 77.603 10.128 79.619 ;
     RECT  41.256 77.893 42.24 78.373 ;
     RECT  13.992 78.035 14.976 82.739 ;
     RECT  42.552 78.037 43.968 79.715 ;
     RECT  35.88 78.085 37.2 78.373 ;
     RECT  5.688 78.227 7.008 78.419 ;
     RECT  2.856 78.613 3.84 79.475 ;
     RECT  2.712 79.475 3.84 79.715 ;
     RECT  9.048 79.619 10.128 81.923 ;
     RECT  2.712 79.715 3.936 83.555 ;
     RECT  19.752 79.811 20.832 83.891 ;
     RECT  31.032 79.859 32.112 80.243 ;
     RECT  33.624 80.005 34.8 80.869 ;
     RECT  31.032 80.243 32.16 83.701 ;
     RECT  37.944 80.389 39.072 81.349 ;
     RECT  10.536 80.819 12.048 81.059 ;
     RECT  13.992 82.739 15.36 82.979 ;
     RECT  13.944 82.979 15.36 85.379 ;
     RECT  16.92 83.363 18.144 83.603 ;
     RECT  12.504 84.263 13.92 84.611 ;
     RECT  23.208 84.263 24.432 84.563 ;
     RECT  15.384 84.515 16.464 84.947 ;
     RECT  23.16 84.563 24.432 84.851 ;
     RECT  23.16 84.851 24.528 86.099 ;
     RECT  15.384 84.947 16.656 85.379 ;
     RECT  21.864 85.475 23.136 86.003 ;
  END
END ot_s81_pq_qb_bank3_native
END LIBRARY
